VERSION 5.8 ;
BUSBITCHARS "[]" ;
DIVIDERCHAR "/" ;
UNITS
    DATABASE MICRONS 1000 ;
END UNITS

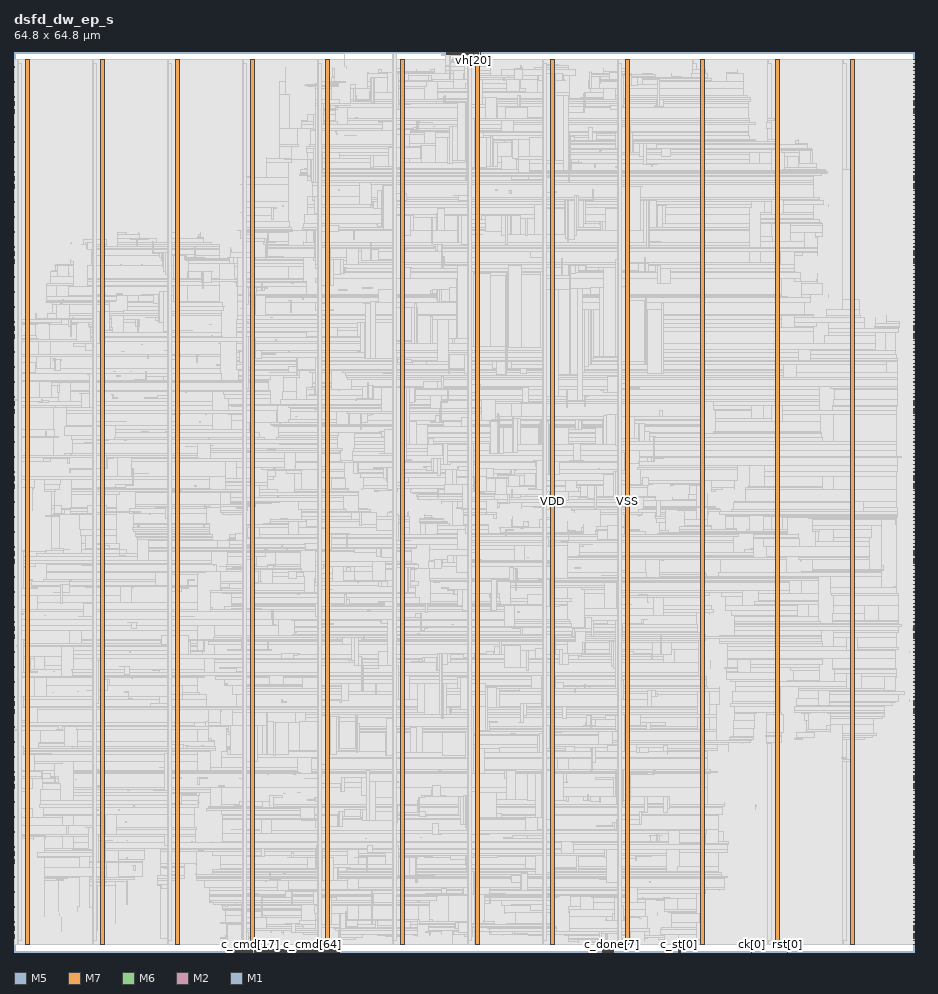
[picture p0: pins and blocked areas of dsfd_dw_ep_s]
MACRO dsfd_dw_ep_s
  FOREIGN dsfd_dw_ep_s 0 0 ;
  CLASS BLOCK ;
  SIZE 64.8 BY 64.8 ;
  PIN c_cmd[0]
    DIRECTION INPUT ;
    USE SIGNAL ;
    PORT
      LAYER M5 ;
        RECT  15.36 0 15.384 0.192 ;
    END
  END c_cmd[0]
  PIN c_cmd[10]
    DIRECTION INPUT ;
    USE SIGNAL ;
    PORT
      LAYER M5 ;
        RECT  16.32 0 16.344 0.192 ;
    END
  END c_cmd[10]
  PIN c_cmd[11]
    DIRECTION INPUT ;
    USE SIGNAL ;
    PORT
      LAYER M5 ;
        RECT  16.416 0 16.44 0.192 ;
    END
  END c_cmd[11]
  PIN c_cmd[12]
    DIRECTION INPUT ;
    USE SIGNAL ;
    PORT
      LAYER M5 ;
        RECT  16.512 0 16.536 0.192 ;
    END
  END c_cmd[12]
  PIN c_cmd[13]
    DIRECTION INPUT ;
    USE SIGNAL ;
    PORT
      LAYER M5 ;
        RECT  16.608 0 16.632 0.192 ;
    END
  END c_cmd[13]
  PIN c_cmd[14]
    DIRECTION INPUT ;
    USE SIGNAL ;
    PORT
      LAYER M5 ;
        RECT  16.704 0 16.728 0.192 ;
    END
  END c_cmd[14]
  PIN c_cmd[15]
    DIRECTION INPUT ;
    USE SIGNAL ;
    PORT
      LAYER M5 ;
        RECT  16.8 0 16.824 0.192 ;
    END
  END c_cmd[15]
  PIN c_cmd[16]
    DIRECTION INPUT ;
    USE SIGNAL ;
    PORT
      LAYER M5 ;
        RECT  16.896 0 16.92 0.192 ;
    END
  END c_cmd[16]
  PIN c_cmd[17]
    DIRECTION INPUT ;
    USE SIGNAL ;
    PORT
      LAYER M5 ;
        RECT  16.992 0 17.016 0.192 ;
    END
  END c_cmd[17]
  PIN c_cmd[18]
    DIRECTION INPUT ;
    USE SIGNAL ;
    PORT
      LAYER M5 ;
        RECT  17.088 0 17.112 0.192 ;
    END
  END c_cmd[18]
  PIN c_cmd[19]
    DIRECTION INPUT ;
    USE SIGNAL ;
    PORT
      LAYER M5 ;
        RECT  17.184 0 17.208 0.192 ;
    END
  END c_cmd[19]
  PIN c_cmd[1]
    DIRECTION INPUT ;
    USE SIGNAL ;
    PORT
      LAYER M5 ;
        RECT  15.456 0 15.48 0.192 ;
    END
  END c_cmd[1]
  PIN c_cmd[20]
    DIRECTION INPUT ;
    USE SIGNAL ;
    PORT
      LAYER M5 ;
        RECT  17.28 0 17.304 0.192 ;
    END
  END c_cmd[20]
  PIN c_cmd[21]
    DIRECTION INPUT ;
    USE SIGNAL ;
    PORT
      LAYER M5 ;
        RECT  17.376 0 17.4 0.192 ;
    END
  END c_cmd[21]
  PIN c_cmd[22]
    DIRECTION INPUT ;
    USE SIGNAL ;
    PORT
      LAYER M5 ;
        RECT  17.472 0 17.496 0.192 ;
    END
  END c_cmd[22]
  PIN c_cmd[23]
    DIRECTION INPUT ;
    USE SIGNAL ;
    PORT
      LAYER M5 ;
        RECT  17.568 0 17.592 0.192 ;
    END
  END c_cmd[23]
  PIN c_cmd[24]
    DIRECTION INPUT ;
    USE SIGNAL ;
    PORT
      LAYER M5 ;
        RECT  17.664 0 17.688 0.192 ;
    END
  END c_cmd[24]
  PIN c_cmd[25]
    DIRECTION INPUT ;
    USE SIGNAL ;
    PORT
      LAYER M5 ;
        RECT  17.76 0 17.784 0.192 ;
    END
  END c_cmd[25]
  PIN c_cmd[26]
    DIRECTION INPUT ;
    USE SIGNAL ;
    PORT
      LAYER M5 ;
        RECT  17.856 0 17.88 0.192 ;
    END
  END c_cmd[26]
  PIN c_cmd[27]
    DIRECTION INPUT ;
    USE SIGNAL ;
    PORT
      LAYER M5 ;
        RECT  17.952 0 17.976 0.192 ;
    END
  END c_cmd[27]
  PIN c_cmd[28]
    DIRECTION INPUT ;
    USE SIGNAL ;
    PORT
      LAYER M5 ;
        RECT  18.048 0 18.072 0.192 ;
    END
  END c_cmd[28]
  PIN c_cmd[29]
    DIRECTION INPUT ;
    USE SIGNAL ;
    PORT
      LAYER M5 ;
        RECT  18.144 0 18.168 0.192 ;
    END
  END c_cmd[29]
  PIN c_cmd[2]
    DIRECTION INPUT ;
    USE SIGNAL ;
    PORT
      LAYER M5 ;
        RECT  15.552 0 15.576 0.192 ;
    END
  END c_cmd[2]
  PIN c_cmd[30]
    DIRECTION INPUT ;
    USE SIGNAL ;
    PORT
      LAYER M5 ;
        RECT  18.24 0 18.264 0.192 ;
    END
  END c_cmd[30]
  PIN c_cmd[31]
    DIRECTION INPUT ;
    USE SIGNAL ;
    PORT
      LAYER M5 ;
        RECT  18.336 0 18.36 0.192 ;
    END
  END c_cmd[31]
  PIN c_cmd[32]
    DIRECTION INPUT ;
    USE SIGNAL ;
    PORT
      LAYER M5 ;
        RECT  18.432 0 18.456 0.192 ;
    END
  END c_cmd[32]
  PIN c_cmd[33]
    DIRECTION INPUT ;
    USE SIGNAL ;
    PORT
      LAYER M5 ;
        RECT  18.528 0 18.552 0.192 ;
    END
  END c_cmd[33]
  PIN c_cmd[34]
    DIRECTION INPUT ;
    USE SIGNAL ;
    PORT
      LAYER M5 ;
        RECT  18.624 0 18.648 0.192 ;
    END
  END c_cmd[34]
  PIN c_cmd[35]
    DIRECTION INPUT ;
    USE SIGNAL ;
    PORT
      LAYER M5 ;
        RECT  18.72 0 18.744 0.192 ;
    END
  END c_cmd[35]
  PIN c_cmd[36]
    DIRECTION INPUT ;
    USE SIGNAL ;
    PORT
      LAYER M5 ;
        RECT  18.816 0 18.84 0.192 ;
    END
  END c_cmd[36]
  PIN c_cmd[37]
    DIRECTION INPUT ;
    USE SIGNAL ;
    PORT
      LAYER M5 ;
        RECT  18.912 0 18.936 0.192 ;
    END
  END c_cmd[37]
  PIN c_cmd[38]
    DIRECTION INPUT ;
    USE SIGNAL ;
    PORT
      LAYER M5 ;
        RECT  19.008 0 19.032 0.192 ;
    END
  END c_cmd[38]
  PIN c_cmd[39]
    DIRECTION INPUT ;
    USE SIGNAL ;
    PORT
      LAYER M5 ;
        RECT  19.104 0 19.128 0.192 ;
    END
  END c_cmd[39]
  PIN c_cmd[3]
    DIRECTION INPUT ;
    USE SIGNAL ;
    PORT
      LAYER M5 ;
        RECT  15.648 0 15.672 0.192 ;
    END
  END c_cmd[3]
  PIN c_cmd[40]
    DIRECTION INPUT ;
    USE SIGNAL ;
    PORT
      LAYER M5 ;
        RECT  19.2 0 19.224 0.192 ;
    END
  END c_cmd[40]
  PIN c_cmd[41]
    DIRECTION INPUT ;
    USE SIGNAL ;
    PORT
      LAYER M5 ;
        RECT  19.296 0 19.32 0.192 ;
    END
  END c_cmd[41]
  PIN c_cmd[42]
    DIRECTION INPUT ;
    USE SIGNAL ;
    PORT
      LAYER M5 ;
        RECT  19.392 0 19.416 0.192 ;
    END
  END c_cmd[42]
  PIN c_cmd[43]
    DIRECTION INPUT ;
    USE SIGNAL ;
    PORT
      LAYER M5 ;
        RECT  19.488 0 19.512 0.192 ;
    END
  END c_cmd[43]
  PIN c_cmd[44]
    DIRECTION INPUT ;
    USE SIGNAL ;
    PORT
      LAYER M5 ;
        RECT  19.584 0 19.608 0.192 ;
    END
  END c_cmd[44]
  PIN c_cmd[45]
    DIRECTION INPUT ;
    USE SIGNAL ;
    PORT
      LAYER M5 ;
        RECT  19.68 0 19.704 0.192 ;
    END
  END c_cmd[45]
  PIN c_cmd[46]
    DIRECTION INPUT ;
    USE SIGNAL ;
    PORT
      LAYER M5 ;
        RECT  19.776 0 19.8 0.192 ;
    END
  END c_cmd[46]
  PIN c_cmd[47]
    DIRECTION INPUT ;
    USE SIGNAL ;
    PORT
      LAYER M5 ;
        RECT  19.872 0 19.896 0.192 ;
    END
  END c_cmd[47]
  PIN c_cmd[48]
    DIRECTION INPUT ;
    USE SIGNAL ;
    PORT
      LAYER M5 ;
        RECT  19.968 0 19.992 0.192 ;
    END
  END c_cmd[48]
  PIN c_cmd[49]
    DIRECTION INPUT ;
    USE SIGNAL ;
    PORT
      LAYER M5 ;
        RECT  20.064 0 20.088 0.192 ;
    END
  END c_cmd[49]
  PIN c_cmd[4]
    DIRECTION INPUT ;
    USE SIGNAL ;
    PORT
      LAYER M5 ;
        RECT  15.744 0 15.768 0.192 ;
    END
  END c_cmd[4]
  PIN c_cmd[50]
    DIRECTION INPUT ;
    USE SIGNAL ;
    PORT
      LAYER M5 ;
        RECT  20.16 0 20.184 0.192 ;
    END
  END c_cmd[50]
  PIN c_cmd[51]
    DIRECTION INPUT ;
    USE SIGNAL ;
    PORT
      LAYER M5 ;
        RECT  20.256 0 20.28 0.192 ;
    END
  END c_cmd[51]
  PIN c_cmd[52]
    DIRECTION INPUT ;
    USE SIGNAL ;
    PORT
      LAYER M5 ;
        RECT  20.352 0 20.376 0.192 ;
    END
  END c_cmd[52]
  PIN c_cmd[53]
    DIRECTION INPUT ;
    USE SIGNAL ;
    PORT
      LAYER M5 ;
        RECT  20.448 0 20.472 0.192 ;
    END
  END c_cmd[53]
  PIN c_cmd[54]
    DIRECTION INPUT ;
    USE SIGNAL ;
    PORT
      LAYER M5 ;
        RECT  20.544 0 20.568 0.192 ;
    END
  END c_cmd[54]
  PIN c_cmd[55]
    DIRECTION INPUT ;
    USE SIGNAL ;
    PORT
      LAYER M5 ;
        RECT  20.64 0 20.664 0.192 ;
    END
  END c_cmd[55]
  PIN c_cmd[56]
    DIRECTION INPUT ;
    USE SIGNAL ;
    PORT
      LAYER M5 ;
        RECT  20.736 0 20.76 0.192 ;
    END
  END c_cmd[56]
  PIN c_cmd[57]
    DIRECTION INPUT ;
    USE SIGNAL ;
    PORT
      LAYER M5 ;
        RECT  20.832 0 20.856 0.192 ;
    END
  END c_cmd[57]
  PIN c_cmd[58]
    DIRECTION INPUT ;
    USE SIGNAL ;
    PORT
      LAYER M5 ;
        RECT  20.928 0 20.952 0.192 ;
    END
  END c_cmd[58]
  PIN c_cmd[59]
    DIRECTION INPUT ;
    USE SIGNAL ;
    PORT
      LAYER M5 ;
        RECT  21.024 0 21.048 0.192 ;
    END
  END c_cmd[59]
  PIN c_cmd[5]
    DIRECTION INPUT ;
    USE SIGNAL ;
    PORT
      LAYER M5 ;
        RECT  15.84 0 15.864 0.192 ;
    END
  END c_cmd[5]
  PIN c_cmd[60]
    DIRECTION INPUT ;
    USE SIGNAL ;
    PORT
      LAYER M5 ;
        RECT  21.12 0 21.144 0.192 ;
    END
  END c_cmd[60]
  PIN c_cmd[61]
    DIRECTION INPUT ;
    USE SIGNAL ;
    PORT
      LAYER M5 ;
        RECT  21.216 0 21.24 0.192 ;
    END
  END c_cmd[61]
  PIN c_cmd[62]
    DIRECTION INPUT ;
    USE SIGNAL ;
    PORT
      LAYER M5 ;
        RECT  21.312 0 21.336 0.192 ;
    END
  END c_cmd[62]
  PIN c_cmd[63]
    DIRECTION INPUT ;
    USE SIGNAL ;
    PORT
      LAYER M5 ;
        RECT  21.408 0 21.432 0.192 ;
    END
  END c_cmd[63]
  PIN c_cmd[64]
    DIRECTION INPUT ;
    USE SIGNAL ;
    PORT
      LAYER M5 ;
        RECT  21.504 0 21.528 0.192 ;
    END
  END c_cmd[64]
  PIN c_cmd[65]
    DIRECTION INPUT ;
    USE SIGNAL ;
    PORT
      LAYER M5 ;
        RECT  21.6 0 21.624 0.192 ;
    END
  END c_cmd[65]
  PIN c_cmd[66]
    DIRECTION INPUT ;
    USE SIGNAL ;
    PORT
      LAYER M5 ;
        RECT  21.696 0 21.72 0.192 ;
    END
  END c_cmd[66]
  PIN c_cmd[67]
    DIRECTION INPUT ;
    USE SIGNAL ;
    PORT
      LAYER M5 ;
        RECT  21.792 0 21.816 0.192 ;
    END
  END c_cmd[67]
  PIN c_cmd[68]
    DIRECTION INPUT ;
    USE SIGNAL ;
    PORT
      LAYER M5 ;
        RECT  21.888 0 21.912 0.192 ;
    END
  END c_cmd[68]
  PIN c_cmd[69]
    DIRECTION INPUT ;
    USE SIGNAL ;
    PORT
      LAYER M5 ;
        RECT  21.984 0 22.008 0.192 ;
    END
  END c_cmd[69]
  PIN c_cmd[6]
    DIRECTION INPUT ;
    USE SIGNAL ;
    PORT
      LAYER M5 ;
        RECT  15.936 0 15.96 0.192 ;
    END
  END c_cmd[6]
  PIN c_cmd[70]
    DIRECTION INPUT ;
    USE SIGNAL ;
    PORT
      LAYER M5 ;
        RECT  22.08 0 22.104 0.192 ;
    END
  END c_cmd[70]
  PIN c_cmd[71]
    DIRECTION INPUT ;
    USE SIGNAL ;
    PORT
      LAYER M5 ;
        RECT  22.176 0 22.2 0.192 ;
    END
  END c_cmd[71]
  PIN c_cmd[72]
    DIRECTION INPUT ;
    USE SIGNAL ;
    PORT
      LAYER M5 ;
        RECT  22.272 0 22.296 0.192 ;
    END
  END c_cmd[72]
  PIN c_cmd[73]
    DIRECTION INPUT ;
    USE SIGNAL ;
    PORT
      LAYER M5 ;
        RECT  22.368 0 22.392 0.192 ;
    END
  END c_cmd[73]
  PIN c_cmd[74]
    DIRECTION INPUT ;
    USE SIGNAL ;
    PORT
      LAYER M5 ;
        RECT  22.464 0 22.488 0.192 ;
    END
  END c_cmd[74]
  PIN c_cmd[75]
    DIRECTION INPUT ;
    USE SIGNAL ;
    PORT
      LAYER M5 ;
        RECT  22.56 0 22.584 0.192 ;
    END
  END c_cmd[75]
  PIN c_cmd[76]
    DIRECTION INPUT ;
    USE SIGNAL ;
    PORT
      LAYER M5 ;
        RECT  22.656 0 22.68 0.192 ;
    END
  END c_cmd[76]
  PIN c_cmd[77]
    DIRECTION INPUT ;
    USE SIGNAL ;
    PORT
      LAYER M5 ;
        RECT  22.752 0 22.776 0.192 ;
    END
  END c_cmd[77]
  PIN c_cmd[78]
    DIRECTION INPUT ;
    USE SIGNAL ;
    PORT
      LAYER M5 ;
        RECT  22.848 0 22.872 0.192 ;
    END
  END c_cmd[78]
  PIN c_cmd[79]
    DIRECTION INPUT ;
    USE SIGNAL ;
    PORT
      LAYER M5 ;
        RECT  22.944 0 22.968 0.192 ;
    END
  END c_cmd[79]
  PIN c_cmd[7]
    DIRECTION INPUT ;
    USE SIGNAL ;
    PORT
      LAYER M5 ;
        RECT  16.032 0 16.056 0.192 ;
    END
  END c_cmd[7]
  PIN c_cmd[80]
    DIRECTION INPUT ;
    USE SIGNAL ;
    PORT
      LAYER M5 ;
        RECT  23.04 0 23.064 0.192 ;
    END
  END c_cmd[80]
  PIN c_cmd[81]
    DIRECTION INPUT ;
    USE SIGNAL ;
    PORT
      LAYER M5 ;
        RECT  23.136 0 23.16 0.192 ;
    END
  END c_cmd[81]
  PIN c_cmd[82]
    DIRECTION INPUT ;
    USE SIGNAL ;
    PORT
      LAYER M5 ;
        RECT  23.232 0 23.256 0.192 ;
    END
  END c_cmd[82]
  PIN c_cmd[83]
    DIRECTION INPUT ;
    USE SIGNAL ;
    PORT
      LAYER M5 ;
        RECT  23.328 0 23.352 0.192 ;
    END
  END c_cmd[83]
  PIN c_cmd[84]
    DIRECTION INPUT ;
    USE SIGNAL ;
    PORT
      LAYER M5 ;
        RECT  23.424 0 23.448 0.192 ;
    END
  END c_cmd[84]
  PIN c_cmd[8]
    DIRECTION INPUT ;
    USE SIGNAL ;
    PORT
      LAYER M5 ;
        RECT  16.128 0 16.152 0.192 ;
    END
  END c_cmd[8]
  PIN c_cmd[9]
    DIRECTION INPUT ;
    USE SIGNAL ;
    PORT
      LAYER M5 ;
        RECT  16.224 0 16.248 0.192 ;
    END
  END c_cmd[9]
  PIN c_done[0]
    DIRECTION OUTPUT ;
    USE SIGNAL ;
    PORT
      LAYER M5 ;
        RECT  42.336 0 42.36 0.192 ;
    END
  END c_done[0]
  PIN c_done[1]
    DIRECTION OUTPUT ;
    USE SIGNAL ;
    PORT
      LAYER M5 ;
        RECT  42.432 0 42.456 0.192 ;
    END
  END c_done[1]
  PIN c_done[2]
    DIRECTION OUTPUT ;
    USE SIGNAL ;
    PORT
      LAYER M5 ;
        RECT  42.528 0 42.552 0.192 ;
    END
  END c_done[2]
  PIN c_done[3]
    DIRECTION OUTPUT ;
    USE SIGNAL ;
    PORT
      LAYER M5 ;
        RECT  42.624 0 42.648 0.192 ;
    END
  END c_done[3]
  PIN c_done[4]
    DIRECTION OUTPUT ;
    USE SIGNAL ;
    PORT
      LAYER M5 ;
        RECT  42.72 0 42.744 0.192 ;
    END
  END c_done[4]
  PIN c_done[5]
    DIRECTION OUTPUT ;
    USE SIGNAL ;
    PORT
      LAYER M5 ;
        RECT  42.816 0 42.84 0.192 ;
    END
  END c_done[5]
  PIN c_done[6]
    DIRECTION OUTPUT ;
    USE SIGNAL ;
    PORT
      LAYER M5 ;
        RECT  42.912 0 42.936 0.192 ;
    END
  END c_done[6]
  PIN c_done[7]
    DIRECTION OUTPUT ;
    USE SIGNAL ;
    PORT
      LAYER M5 ;
        RECT  43.008 0 43.032 0.192 ;
    END
  END c_done[7]
  PIN c_done[8]
    DIRECTION OUTPUT ;
    USE SIGNAL ;
    PORT
      LAYER M5 ;
        RECT  43.104 0 43.128 0.192 ;
    END
  END c_done[8]
  PIN c_st[0]
    DIRECTION OUTPUT ;
    USE SIGNAL ;
    PORT
      LAYER M5 ;
        RECT  47.856 0 47.88 0.192 ;
    END
  END c_st[0]
  PIN c_st[1]
    DIRECTION OUTPUT ;
    USE SIGNAL ;
    PORT
      LAYER M5 ;
        RECT  47.952 0 47.976 0.192 ;
    END
  END c_st[1]
  PIN ck[0]
    DIRECTION INPUT ;
    USE SIGNAL ;
    PORT
      LAYER M5 ;
        RECT  53.088 0 53.112 0.192 ;
    END
  END ck[0]
  PIN rst[0]
    DIRECTION INPUT ;
    USE SIGNAL ;
    PORT
      LAYER M5 ;
        RECT  55.68 0 55.704 0.192 ;
    END
  END rst[0]
  PIN vh[0]
    DIRECTION INPUT ;
    USE SIGNAL ;
    PORT
      LAYER M5 ;
        RECT  31.152 64.608 31.176 64.8 ;
    END
  END vh[0]
  PIN vh[10]
    DIRECTION INPUT ;
    USE SIGNAL ;
    PORT
      LAYER M5 ;
        RECT  32.112 64.608 32.136 64.8 ;
    END
  END vh[10]
  PIN vh[11]
    DIRECTION INPUT ;
    USE SIGNAL ;
    PORT
      LAYER M5 ;
        RECT  32.208 64.608 32.232 64.8 ;
    END
  END vh[11]
  PIN vh[12]
    DIRECTION INPUT ;
    USE SIGNAL ;
    PORT
      LAYER M5 ;
        RECT  32.304 64.608 32.328 64.8 ;
    END
  END vh[12]
  PIN vh[13]
    DIRECTION INPUT ;
    USE SIGNAL ;
    PORT
      LAYER M5 ;
        RECT  32.4 64.608 32.424 64.8 ;
    END
  END vh[13]
  PIN vh[14]
    DIRECTION INPUT ;
    USE SIGNAL ;
    PORT
      LAYER M5 ;
        RECT  32.496 64.608 32.52 64.8 ;
    END
  END vh[14]
  PIN vh[15]
    DIRECTION INPUT ;
    USE SIGNAL ;
    PORT
      LAYER M5 ;
        RECT  32.592 64.608 32.616 64.8 ;
    END
  END vh[15]
  PIN vh[16]
    DIRECTION INPUT ;
    USE SIGNAL ;
    PORT
      LAYER M5 ;
        RECT  32.688 64.608 32.712 64.8 ;
    END
  END vh[16]
  PIN vh[17]
    DIRECTION INPUT ;
    USE SIGNAL ;
    PORT
      LAYER M5 ;
        RECT  32.784 64.608 32.808 64.8 ;
    END
  END vh[17]
  PIN vh[18]
    DIRECTION INPUT ;
    USE SIGNAL ;
    PORT
      LAYER M5 ;
        RECT  32.88 64.608 32.904 64.8 ;
    END
  END vh[18]
  PIN vh[19]
    DIRECTION INPUT ;
    USE SIGNAL ;
    PORT
      LAYER M5 ;
        RECT  32.976 64.608 33 64.8 ;
    END
  END vh[19]
  PIN vh[1]
    DIRECTION INPUT ;
    USE SIGNAL ;
    PORT
      LAYER M5 ;
        RECT  31.248 64.608 31.272 64.8 ;
    END
  END vh[1]
  PIN vh[20]
    DIRECTION INPUT ;
    USE SIGNAL ;
    PORT
      LAYER M5 ;
        RECT  33.072 64.608 33.096 64.8 ;
    END
  END vh[20]
  PIN vh[21]
    DIRECTION INPUT ;
    USE SIGNAL ;
    PORT
      LAYER M5 ;
        RECT  33.168 64.608 33.192 64.8 ;
    END
  END vh[21]
  PIN vh[22]
    DIRECTION INPUT ;
    USE SIGNAL ;
    PORT
      LAYER M5 ;
        RECT  33.264 64.608 33.288 64.8 ;
    END
  END vh[22]
  PIN vh[23]
    DIRECTION INPUT ;
    USE SIGNAL ;
    PORT
      LAYER M5 ;
        RECT  33.36 64.608 33.384 64.8 ;
    END
  END vh[23]
  PIN vh[24]
    DIRECTION INPUT ;
    USE SIGNAL ;
    PORT
      LAYER M5 ;
        RECT  33.456 64.608 33.48 64.8 ;
    END
  END vh[24]
  PIN vh[25]
    DIRECTION INPUT ;
    USE SIGNAL ;
    PORT
      LAYER M5 ;
        RECT  33.552 64.608 33.576 64.8 ;
    END
  END vh[25]
  PIN vh[2]
    DIRECTION INPUT ;
    USE SIGNAL ;
    PORT
      LAYER M5 ;
        RECT  31.344 64.608 31.368 64.8 ;
    END
  END vh[2]
  PIN vh[3]
    DIRECTION INPUT ;
    USE SIGNAL ;
    PORT
      LAYER M5 ;
        RECT  31.44 64.608 31.464 64.8 ;
    END
  END vh[3]
  PIN vh[4]
    DIRECTION INPUT ;
    USE SIGNAL ;
    PORT
      LAYER M5 ;
        RECT  31.536 64.608 31.56 64.8 ;
    END
  END vh[4]
  PIN vh[5]
    DIRECTION INPUT ;
    USE SIGNAL ;
    PORT
      LAYER M5 ;
        RECT  31.632 64.608 31.656 64.8 ;
    END
  END vh[5]
  PIN vh[6]
    DIRECTION INPUT ;
    USE SIGNAL ;
    PORT
      LAYER M5 ;
        RECT  31.728 64.608 31.752 64.8 ;
    END
  END vh[6]
  PIN vh[7]
    DIRECTION INPUT ;
    USE SIGNAL ;
    PORT
      LAYER M5 ;
        RECT  31.824 64.608 31.848 64.8 ;
    END
  END vh[7]
  PIN vh[8]
    DIRECTION INPUT ;
    USE SIGNAL ;
    PORT
      LAYER M5 ;
        RECT  31.92 64.608 31.944 64.8 ;
    END
  END vh[8]
  PIN vh[9]
    DIRECTION INPUT ;
    USE SIGNAL ;
    PORT
      LAYER M5 ;
        RECT  32.016 64.608 32.04 64.8 ;
    END
  END vh[9]
  PIN VDD
    DIRECTION INOUT ;
    USE POWER ;
    PORT
      LAYER M7 ;
        RECT  60.256 0.531 60.544 64.269 ;
        RECT  49.456 0.531 49.744 64.269 ;
        RECT  38.656 0.531 38.944 64.269 ;
        RECT  27.856 0.531 28.144 64.269 ;
        RECT  17.056 0.531 17.344 64.269 ;
        RECT  6.256 0.531 6.544 64.269 ;
      LAYER M6 ;
        RECT  64.768 60.972 64.8 61.26 ;
        RECT  0 60.972 0.032 61.26 ;
        RECT  64.768 55.572 64.8 55.86 ;
        RECT  0 55.572 0.032 55.86 ;
        RECT  64.768 50.172 64.8 50.46 ;
        RECT  0 50.172 0.032 50.46 ;
        RECT  64.768 44.772 64.8 45.06 ;
        RECT  0 44.772 0.032 45.06 ;
        RECT  64.768 39.372 64.8 39.66 ;
        RECT  0 39.372 0.032 39.66 ;
        RECT  64.768 33.972 64.8 34.26 ;
        RECT  0 33.972 0.032 34.26 ;
        RECT  64.768 28.572 64.8 28.86 ;
        RECT  0 28.572 0.032 28.86 ;
        RECT  64.768 23.172 64.8 23.46 ;
        RECT  0 23.172 0.032 23.46 ;
        RECT  64.768 17.772 64.8 18.06 ;
        RECT  0 17.772 0.032 18.06 ;
        RECT  64.768 12.372 64.8 12.66 ;
        RECT  0 12.372 0.032 12.66 ;
        RECT  64.768 6.972 64.8 7.26 ;
        RECT  0 6.972 0.032 7.26 ;
        RECT  64.768 1.572 64.8 1.86 ;
        RECT  0 1.572 0.032 1.86 ;
      LAYER M2 ;
        RECT  64.782 63.981 64.8 63.999 ;
        RECT  0 63.981 0.018 63.999 ;
        RECT  64.782 63.441 64.8 63.459 ;
        RECT  0 63.441 0.018 63.459 ;
        RECT  64.782 62.901 64.8 62.919 ;
        RECT  0 62.901 0.018 62.919 ;
        RECT  64.782 62.361 64.8 62.379 ;
        RECT  0 62.361 0.018 62.379 ;
        RECT  64.782 61.821 64.8 61.839 ;
        RECT  0 61.821 0.018 61.839 ;
        RECT  64.782 61.281 64.8 61.299 ;
        RECT  0 61.281 0.018 61.299 ;
        RECT  64.782 60.741 64.8 60.759 ;
        RECT  0 60.741 0.018 60.759 ;
        RECT  64.782 60.201 64.8 60.219 ;
        RECT  0 60.201 0.018 60.219 ;
        RECT  64.782 59.661 64.8 59.679 ;
        RECT  0 59.661 0.018 59.679 ;
        RECT  64.782 59.121 64.8 59.139 ;
        RECT  0 59.121 0.018 59.139 ;
        RECT  64.782 58.581 64.8 58.599 ;
        RECT  0 58.581 0.018 58.599 ;
        RECT  64.782 58.041 64.8 58.059 ;
        RECT  0 58.041 0.018 58.059 ;
        RECT  64.782 57.501 64.8 57.519 ;
        RECT  0 57.501 0.018 57.519 ;
        RECT  64.782 56.961 64.8 56.979 ;
        RECT  0 56.961 0.018 56.979 ;
        RECT  64.782 56.421 64.8 56.439 ;
        RECT  0 56.421 0.018 56.439 ;
        RECT  64.782 55.881 64.8 55.899 ;
        RECT  0 55.881 0.018 55.899 ;
        RECT  64.782 55.341 64.8 55.359 ;
        RECT  0 55.341 0.018 55.359 ;
        RECT  64.782 54.801 64.8 54.819 ;
        RECT  0 54.801 0.018 54.819 ;
        RECT  64.782 54.261 64.8 54.279 ;
        RECT  0 54.261 0.018 54.279 ;
        RECT  64.782 53.721 64.8 53.739 ;
        RECT  0 53.721 0.018 53.739 ;
        RECT  64.782 53.181 64.8 53.199 ;
        RECT  0 53.181 0.018 53.199 ;
        RECT  64.782 52.641 64.8 52.659 ;
        RECT  0 52.641 0.018 52.659 ;
        RECT  64.782 52.101 64.8 52.119 ;
        RECT  0 52.101 0.018 52.119 ;
        RECT  64.782 51.561 64.8 51.579 ;
        RECT  0 51.561 0.018 51.579 ;
        RECT  64.782 51.021 64.8 51.039 ;
        RECT  0 51.021 0.018 51.039 ;
        RECT  64.782 50.481 64.8 50.499 ;
        RECT  0 50.481 0.018 50.499 ;
        RECT  64.782 49.941 64.8 49.959 ;
        RECT  0 49.941 0.018 49.959 ;
        RECT  64.782 49.401 64.8 49.419 ;
        RECT  0 49.401 0.018 49.419 ;
        RECT  64.782 48.861 64.8 48.879 ;
        RECT  0 48.861 0.018 48.879 ;
        RECT  64.782 48.321 64.8 48.339 ;
        RECT  0 48.321 0.018 48.339 ;
        RECT  64.782 47.781 64.8 47.799 ;
        RECT  0 47.781 0.018 47.799 ;
        RECT  64.782 47.241 64.8 47.259 ;
        RECT  0 47.241 0.018 47.259 ;
        RECT  64.782 46.701 64.8 46.719 ;
        RECT  0 46.701 0.018 46.719 ;
        RECT  64.782 46.161 64.8 46.179 ;
        RECT  0 46.161 0.018 46.179 ;
        RECT  64.782 45.621 64.8 45.639 ;
        RECT  0 45.621 0.018 45.639 ;
        RECT  64.782 45.081 64.8 45.099 ;
        RECT  0 45.081 0.018 45.099 ;
        RECT  64.782 44.541 64.8 44.559 ;
        RECT  0 44.541 0.018 44.559 ;
        RECT  64.782 44.001 64.8 44.019 ;
        RECT  0 44.001 0.018 44.019 ;
        RECT  64.782 43.461 64.8 43.479 ;
        RECT  0 43.461 0.018 43.479 ;
        RECT  64.782 42.921 64.8 42.939 ;
        RECT  0 42.921 0.018 42.939 ;
        RECT  64.782 42.381 64.8 42.399 ;
        RECT  0 42.381 0.018 42.399 ;
        RECT  64.782 41.841 64.8 41.859 ;
        RECT  0 41.841 0.018 41.859 ;
        RECT  64.782 41.301 64.8 41.319 ;
        RECT  0 41.301 0.018 41.319 ;
        RECT  64.782 40.761 64.8 40.779 ;
        RECT  0 40.761 0.018 40.779 ;
        RECT  64.782 40.221 64.8 40.239 ;
        RECT  0 40.221 0.018 40.239 ;
        RECT  64.782 39.681 64.8 39.699 ;
        RECT  0 39.681 0.018 39.699 ;
        RECT  64.782 39.141 64.8 39.159 ;
        RECT  0 39.141 0.018 39.159 ;
        RECT  64.782 38.601 64.8 38.619 ;
        RECT  0 38.601 0.018 38.619 ;
        RECT  64.782 38.061 64.8 38.079 ;
        RECT  0 38.061 0.018 38.079 ;
        RECT  64.782 37.521 64.8 37.539 ;
        RECT  0 37.521 0.018 37.539 ;
        RECT  64.782 36.981 64.8 36.999 ;
        RECT  0 36.981 0.018 36.999 ;
        RECT  64.782 36.441 64.8 36.459 ;
        RECT  0 36.441 0.018 36.459 ;
        RECT  64.782 35.901 64.8 35.919 ;
        RECT  0 35.901 0.018 35.919 ;
        RECT  64.782 35.361 64.8 35.379 ;
        RECT  0 35.361 0.018 35.379 ;
        RECT  64.782 34.821 64.8 34.839 ;
        RECT  0 34.821 0.018 34.839 ;
        RECT  64.782 34.281 64.8 34.299 ;
        RECT  0 34.281 0.018 34.299 ;
        RECT  64.782 33.741 64.8 33.759 ;
        RECT  0 33.741 0.018 33.759 ;
        RECT  64.782 33.201 64.8 33.219 ;
        RECT  0 33.201 0.018 33.219 ;
        RECT  64.782 32.661 64.8 32.679 ;
        RECT  0 32.661 0.018 32.679 ;
        RECT  64.782 32.121 64.8 32.139 ;
        RECT  0 32.121 0.018 32.139 ;
        RECT  64.782 31.581 64.8 31.599 ;
        RECT  0 31.581 0.018 31.599 ;
        RECT  64.782 31.041 64.8 31.059 ;
        RECT  0 31.041 0.018 31.059 ;
        RECT  64.782 30.501 64.8 30.519 ;
        RECT  0 30.501 0.018 30.519 ;
        RECT  64.782 29.961 64.8 29.979 ;
        RECT  0 29.961 0.018 29.979 ;
        RECT  64.782 29.421 64.8 29.439 ;
        RECT  0 29.421 0.018 29.439 ;
        RECT  64.782 28.881 64.8 28.899 ;
        RECT  0 28.881 0.018 28.899 ;
        RECT  64.782 28.341 64.8 28.359 ;
        RECT  0 28.341 0.018 28.359 ;
        RECT  64.782 27.801 64.8 27.819 ;
        RECT  0 27.801 0.018 27.819 ;
        RECT  64.782 27.261 64.8 27.279 ;
        RECT  0 27.261 0.018 27.279 ;
        RECT  64.782 26.721 64.8 26.739 ;
        RECT  0 26.721 0.018 26.739 ;
        RECT  64.782 26.181 64.8 26.199 ;
        RECT  0 26.181 0.018 26.199 ;
        RECT  64.782 25.641 64.8 25.659 ;
        RECT  0 25.641 0.018 25.659 ;
        RECT  64.782 25.101 64.8 25.119 ;
        RECT  0 25.101 0.018 25.119 ;
        RECT  64.782 24.561 64.8 24.579 ;
        RECT  0 24.561 0.018 24.579 ;
        RECT  64.782 24.021 64.8 24.039 ;
        RECT  0 24.021 0.018 24.039 ;
        RECT  64.782 23.481 64.8 23.499 ;
        RECT  0 23.481 0.018 23.499 ;
        RECT  64.782 22.941 64.8 22.959 ;
        RECT  0 22.941 0.018 22.959 ;
        RECT  64.782 22.401 64.8 22.419 ;
        RECT  0 22.401 0.018 22.419 ;
        RECT  64.782 21.861 64.8 21.879 ;
        RECT  0 21.861 0.018 21.879 ;
        RECT  64.782 21.321 64.8 21.339 ;
        RECT  0 21.321 0.018 21.339 ;
        RECT  64.782 20.781 64.8 20.799 ;
        RECT  0 20.781 0.018 20.799 ;
        RECT  64.782 20.241 64.8 20.259 ;
        RECT  0 20.241 0.018 20.259 ;
        RECT  64.782 19.701 64.8 19.719 ;
        RECT  0 19.701 0.018 19.719 ;
        RECT  64.782 19.161 64.8 19.179 ;
        RECT  0 19.161 0.018 19.179 ;
        RECT  64.782 18.621 64.8 18.639 ;
        RECT  0 18.621 0.018 18.639 ;
        RECT  64.782 18.081 64.8 18.099 ;
        RECT  0 18.081 0.018 18.099 ;
        RECT  64.782 17.541 64.8 17.559 ;
        RECT  0 17.541 0.018 17.559 ;
        RECT  64.782 17.001 64.8 17.019 ;
        RECT  0 17.001 0.018 17.019 ;
        RECT  64.782 16.461 64.8 16.479 ;
        RECT  0 16.461 0.018 16.479 ;
        RECT  64.782 15.921 64.8 15.939 ;
        RECT  0 15.921 0.018 15.939 ;
        RECT  64.782 15.381 64.8 15.399 ;
        RECT  0 15.381 0.018 15.399 ;
        RECT  64.782 14.841 64.8 14.859 ;
        RECT  0 14.841 0.018 14.859 ;
        RECT  64.782 14.301 64.8 14.319 ;
        RECT  0 14.301 0.018 14.319 ;
        RECT  64.782 13.761 64.8 13.779 ;
        RECT  0 13.761 0.018 13.779 ;
        RECT  64.782 13.221 64.8 13.239 ;
        RECT  0 13.221 0.018 13.239 ;
        RECT  64.782 12.681 64.8 12.699 ;
        RECT  0 12.681 0.018 12.699 ;
        RECT  64.782 12.141 64.8 12.159 ;
        RECT  0 12.141 0.018 12.159 ;
        RECT  64.782 11.601 64.8 11.619 ;
        RECT  0 11.601 0.018 11.619 ;
        RECT  64.782 11.061 64.8 11.079 ;
        RECT  0 11.061 0.018 11.079 ;
        RECT  64.782 10.521 64.8 10.539 ;
        RECT  0 10.521 0.018 10.539 ;
        RECT  64.782 9.981 64.8 9.999 ;
        RECT  0 9.981 0.018 9.999 ;
        RECT  64.782 9.441 64.8 9.459 ;
        RECT  0 9.441 0.018 9.459 ;
        RECT  64.782 8.901 64.8 8.919 ;
        RECT  0 8.901 0.018 8.919 ;
        RECT  64.782 8.361 64.8 8.379 ;
        RECT  0 8.361 0.018 8.379 ;
        RECT  64.782 7.821 64.8 7.839 ;
        RECT  0 7.821 0.018 7.839 ;
        RECT  64.782 7.281 64.8 7.299 ;
        RECT  0 7.281 0.018 7.299 ;
        RECT  64.782 6.741 64.8 6.759 ;
        RECT  0 6.741 0.018 6.759 ;
        RECT  64.782 6.201 64.8 6.219 ;
        RECT  0 6.201 0.018 6.219 ;
        RECT  64.782 5.661 64.8 5.679 ;
        RECT  0 5.661 0.018 5.679 ;
        RECT  64.782 5.121 64.8 5.139 ;
        RECT  0 5.121 0.018 5.139 ;
        RECT  64.782 4.581 64.8 4.599 ;
        RECT  0 4.581 0.018 4.599 ;
        RECT  64.782 4.041 64.8 4.059 ;
        RECT  0 4.041 0.018 4.059 ;
        RECT  64.782 3.501 64.8 3.519 ;
        RECT  0 3.501 0.018 3.519 ;
        RECT  64.782 2.961 64.8 2.979 ;
        RECT  0 2.961 0.018 2.979 ;
        RECT  64.782 2.421 64.8 2.439 ;
        RECT  0 2.421 0.018 2.439 ;
        RECT  64.782 1.881 64.8 1.899 ;
        RECT  0 1.881 0.018 1.899 ;
        RECT  64.782 1.341 64.8 1.359 ;
        RECT  0 1.341 0.018 1.359 ;
        RECT  64.782 0.801 64.8 0.819 ;
        RECT  0 0.801 0.018 0.819 ;
      LAYER M1 ;
        RECT  64.782 63.981 64.8 63.999 ;
        RECT  0 63.981 0.018 63.999 ;
        RECT  64.782 63.441 64.8 63.459 ;
        RECT  0 63.441 0.018 63.459 ;
        RECT  64.782 62.901 64.8 62.919 ;
        RECT  0 62.901 0.018 62.919 ;
        RECT  64.782 62.361 64.8 62.379 ;
        RECT  0 62.361 0.018 62.379 ;
        RECT  64.782 61.821 64.8 61.839 ;
        RECT  0 61.821 0.018 61.839 ;
        RECT  64.782 61.281 64.8 61.299 ;
        RECT  0 61.281 0.018 61.299 ;
        RECT  64.782 60.741 64.8 60.759 ;
        RECT  0 60.741 0.018 60.759 ;
        RECT  64.782 60.201 64.8 60.219 ;
        RECT  0 60.201 0.018 60.219 ;
        RECT  64.782 59.661 64.8 59.679 ;
        RECT  0 59.661 0.018 59.679 ;
        RECT  64.782 59.121 64.8 59.139 ;
        RECT  0 59.121 0.018 59.139 ;
        RECT  64.782 58.581 64.8 58.599 ;
        RECT  0 58.581 0.018 58.599 ;
        RECT  64.782 58.041 64.8 58.059 ;
        RECT  0 58.041 0.018 58.059 ;
        RECT  64.782 57.501 64.8 57.519 ;
        RECT  0 57.501 0.018 57.519 ;
        RECT  64.782 56.961 64.8 56.979 ;
        RECT  0 56.961 0.018 56.979 ;
        RECT  64.782 56.421 64.8 56.439 ;
        RECT  0 56.421 0.018 56.439 ;
        RECT  64.782 55.881 64.8 55.899 ;
        RECT  0 55.881 0.018 55.899 ;
        RECT  64.782 55.341 64.8 55.359 ;
        RECT  0 55.341 0.018 55.359 ;
        RECT  64.782 54.801 64.8 54.819 ;
        RECT  0 54.801 0.018 54.819 ;
        RECT  64.782 54.261 64.8 54.279 ;
        RECT  0 54.261 0.018 54.279 ;
        RECT  64.782 53.721 64.8 53.739 ;
        RECT  0 53.721 0.018 53.739 ;
        RECT  64.782 53.181 64.8 53.199 ;
        RECT  0 53.181 0.018 53.199 ;
        RECT  64.782 52.641 64.8 52.659 ;
        RECT  0 52.641 0.018 52.659 ;
        RECT  64.782 52.101 64.8 52.119 ;
        RECT  0 52.101 0.018 52.119 ;
        RECT  64.782 51.561 64.8 51.579 ;
        RECT  0 51.561 0.018 51.579 ;
        RECT  64.782 51.021 64.8 51.039 ;
        RECT  0 51.021 0.018 51.039 ;
        RECT  64.782 50.481 64.8 50.499 ;
        RECT  0 50.481 0.018 50.499 ;
        RECT  64.782 49.941 64.8 49.959 ;
        RECT  0 49.941 0.018 49.959 ;
        RECT  64.782 49.401 64.8 49.419 ;
        RECT  0 49.401 0.018 49.419 ;
        RECT  64.782 48.861 64.8 48.879 ;
        RECT  0 48.861 0.018 48.879 ;
        RECT  64.782 48.321 64.8 48.339 ;
        RECT  0 48.321 0.018 48.339 ;
        RECT  64.782 47.781 64.8 47.799 ;
        RECT  0 47.781 0.018 47.799 ;
        RECT  64.782 47.241 64.8 47.259 ;
        RECT  0 47.241 0.018 47.259 ;
        RECT  64.782 46.701 64.8 46.719 ;
        RECT  0 46.701 0.018 46.719 ;
        RECT  64.782 46.161 64.8 46.179 ;
        RECT  0 46.161 0.018 46.179 ;
        RECT  64.782 45.621 64.8 45.639 ;
        RECT  0 45.621 0.018 45.639 ;
        RECT  64.782 45.081 64.8 45.099 ;
        RECT  0 45.081 0.018 45.099 ;
        RECT  64.782 44.541 64.8 44.559 ;
        RECT  0 44.541 0.018 44.559 ;
        RECT  64.782 44.001 64.8 44.019 ;
        RECT  0 44.001 0.018 44.019 ;
        RECT  64.782 43.461 64.8 43.479 ;
        RECT  0 43.461 0.018 43.479 ;
        RECT  64.782 42.921 64.8 42.939 ;
        RECT  0 42.921 0.018 42.939 ;
        RECT  64.782 42.381 64.8 42.399 ;
        RECT  0 42.381 0.018 42.399 ;
        RECT  64.782 41.841 64.8 41.859 ;
        RECT  0 41.841 0.018 41.859 ;
        RECT  64.782 41.301 64.8 41.319 ;
        RECT  0 41.301 0.018 41.319 ;
        RECT  64.782 40.761 64.8 40.779 ;
        RECT  0 40.761 0.018 40.779 ;
        RECT  64.782 40.221 64.8 40.239 ;
        RECT  0 40.221 0.018 40.239 ;
        RECT  64.782 39.681 64.8 39.699 ;
        RECT  0 39.681 0.018 39.699 ;
        RECT  64.782 39.141 64.8 39.159 ;
        RECT  0 39.141 0.018 39.159 ;
        RECT  64.782 38.601 64.8 38.619 ;
        RECT  0 38.601 0.018 38.619 ;
        RECT  64.782 38.061 64.8 38.079 ;
        RECT  0 38.061 0.018 38.079 ;
        RECT  64.782 37.521 64.8 37.539 ;
        RECT  0 37.521 0.018 37.539 ;
        RECT  64.782 36.981 64.8 36.999 ;
        RECT  0 36.981 0.018 36.999 ;
        RECT  64.782 36.441 64.8 36.459 ;
        RECT  0 36.441 0.018 36.459 ;
        RECT  64.782 35.901 64.8 35.919 ;
        RECT  0 35.901 0.018 35.919 ;
        RECT  64.782 35.361 64.8 35.379 ;
        RECT  0 35.361 0.018 35.379 ;
        RECT  64.782 34.821 64.8 34.839 ;
        RECT  0 34.821 0.018 34.839 ;
        RECT  64.782 34.281 64.8 34.299 ;
        RECT  0 34.281 0.018 34.299 ;
        RECT  64.782 33.741 64.8 33.759 ;
        RECT  0 33.741 0.018 33.759 ;
        RECT  64.782 33.201 64.8 33.219 ;
        RECT  0 33.201 0.018 33.219 ;
        RECT  64.782 32.661 64.8 32.679 ;
        RECT  0 32.661 0.018 32.679 ;
        RECT  64.782 32.121 64.8 32.139 ;
        RECT  0 32.121 0.018 32.139 ;
        RECT  64.782 31.581 64.8 31.599 ;
        RECT  0 31.581 0.018 31.599 ;
        RECT  64.782 31.041 64.8 31.059 ;
        RECT  0 31.041 0.018 31.059 ;
        RECT  64.782 30.501 64.8 30.519 ;
        RECT  0 30.501 0.018 30.519 ;
        RECT  64.782 29.961 64.8 29.979 ;
        RECT  0 29.961 0.018 29.979 ;
        RECT  64.782 29.421 64.8 29.439 ;
        RECT  0 29.421 0.018 29.439 ;
        RECT  64.782 28.881 64.8 28.899 ;
        RECT  0 28.881 0.018 28.899 ;
        RECT  64.782 28.341 64.8 28.359 ;
        RECT  0 28.341 0.018 28.359 ;
        RECT  64.782 27.801 64.8 27.819 ;
        RECT  0 27.801 0.018 27.819 ;
        RECT  64.782 27.261 64.8 27.279 ;
        RECT  0 27.261 0.018 27.279 ;
        RECT  64.782 26.721 64.8 26.739 ;
        RECT  0 26.721 0.018 26.739 ;
        RECT  64.782 26.181 64.8 26.199 ;
        RECT  0 26.181 0.018 26.199 ;
        RECT  64.782 25.641 64.8 25.659 ;
        RECT  0 25.641 0.018 25.659 ;
        RECT  64.782 25.101 64.8 25.119 ;
        RECT  0 25.101 0.018 25.119 ;
        RECT  64.782 24.561 64.8 24.579 ;
        RECT  0 24.561 0.018 24.579 ;
        RECT  64.782 24.021 64.8 24.039 ;
        RECT  0 24.021 0.018 24.039 ;
        RECT  64.782 23.481 64.8 23.499 ;
        RECT  0 23.481 0.018 23.499 ;
        RECT  64.782 22.941 64.8 22.959 ;
        RECT  0 22.941 0.018 22.959 ;
        RECT  64.782 22.401 64.8 22.419 ;
        RECT  0 22.401 0.018 22.419 ;
        RECT  64.782 21.861 64.8 21.879 ;
        RECT  0 21.861 0.018 21.879 ;
        RECT  64.782 21.321 64.8 21.339 ;
        RECT  0 21.321 0.018 21.339 ;
        RECT  64.782 20.781 64.8 20.799 ;
        RECT  0 20.781 0.018 20.799 ;
        RECT  64.782 20.241 64.8 20.259 ;
        RECT  0 20.241 0.018 20.259 ;
        RECT  64.782 19.701 64.8 19.719 ;
        RECT  0 19.701 0.018 19.719 ;
        RECT  64.782 19.161 64.8 19.179 ;
        RECT  0 19.161 0.018 19.179 ;
        RECT  64.782 18.621 64.8 18.639 ;
        RECT  0 18.621 0.018 18.639 ;
        RECT  64.782 18.081 64.8 18.099 ;
        RECT  0 18.081 0.018 18.099 ;
        RECT  64.782 17.541 64.8 17.559 ;
        RECT  0 17.541 0.018 17.559 ;
        RECT  64.782 17.001 64.8 17.019 ;
        RECT  0 17.001 0.018 17.019 ;
        RECT  64.782 16.461 64.8 16.479 ;
        RECT  0 16.461 0.018 16.479 ;
        RECT  64.782 15.921 64.8 15.939 ;
        RECT  0 15.921 0.018 15.939 ;
        RECT  64.782 15.381 64.8 15.399 ;
        RECT  0 15.381 0.018 15.399 ;
        RECT  64.782 14.841 64.8 14.859 ;
        RECT  0 14.841 0.018 14.859 ;
        RECT  64.782 14.301 64.8 14.319 ;
        RECT  0 14.301 0.018 14.319 ;
        RECT  64.782 13.761 64.8 13.779 ;
        RECT  0 13.761 0.018 13.779 ;
        RECT  64.782 13.221 64.8 13.239 ;
        RECT  0 13.221 0.018 13.239 ;
        RECT  64.782 12.681 64.8 12.699 ;
        RECT  0 12.681 0.018 12.699 ;
        RECT  64.782 12.141 64.8 12.159 ;
        RECT  0 12.141 0.018 12.159 ;
        RECT  64.782 11.601 64.8 11.619 ;
        RECT  0 11.601 0.018 11.619 ;
        RECT  64.782 11.061 64.8 11.079 ;
        RECT  0 11.061 0.018 11.079 ;
        RECT  64.782 10.521 64.8 10.539 ;
        RECT  0 10.521 0.018 10.539 ;
        RECT  64.782 9.981 64.8 9.999 ;
        RECT  0 9.981 0.018 9.999 ;
        RECT  64.782 9.441 64.8 9.459 ;
        RECT  0 9.441 0.018 9.459 ;
        RECT  64.782 8.901 64.8 8.919 ;
        RECT  0 8.901 0.018 8.919 ;
        RECT  64.782 8.361 64.8 8.379 ;
        RECT  0 8.361 0.018 8.379 ;
        RECT  64.782 7.821 64.8 7.839 ;
        RECT  0 7.821 0.018 7.839 ;
        RECT  64.782 7.281 64.8 7.299 ;
        RECT  0 7.281 0.018 7.299 ;
        RECT  64.782 6.741 64.8 6.759 ;
        RECT  0 6.741 0.018 6.759 ;
        RECT  64.782 6.201 64.8 6.219 ;
        RECT  0 6.201 0.018 6.219 ;
        RECT  64.782 5.661 64.8 5.679 ;
        RECT  0 5.661 0.018 5.679 ;
        RECT  64.782 5.121 64.8 5.139 ;
        RECT  0 5.121 0.018 5.139 ;
        RECT  64.782 4.581 64.8 4.599 ;
        RECT  0 4.581 0.018 4.599 ;
        RECT  64.782 4.041 64.8 4.059 ;
        RECT  0 4.041 0.018 4.059 ;
        RECT  64.782 3.501 64.8 3.519 ;
        RECT  0 3.501 0.018 3.519 ;
        RECT  64.782 2.961 64.8 2.979 ;
        RECT  0 2.961 0.018 2.979 ;
        RECT  64.782 2.421 64.8 2.439 ;
        RECT  0 2.421 0.018 2.439 ;
        RECT  64.782 1.881 64.8 1.899 ;
        RECT  0 1.881 0.018 1.899 ;
        RECT  64.782 1.341 64.8 1.359 ;
        RECT  0 1.341 0.018 1.359 ;
        RECT  64.782 0.801 64.8 0.819 ;
        RECT  0 0.801 0.018 0.819 ;
    END
  END VDD
  PIN VSS
    DIRECTION INOUT ;
    USE GROUND ;
    PORT
      LAYER M7 ;
        RECT  54.856 0.531 55.144 64.269 ;
        RECT  44.056 0.531 44.344 64.269 ;
        RECT  33.256 0.531 33.544 64.269 ;
        RECT  22.456 0.531 22.744 64.269 ;
        RECT  11.656 0.531 11.944 64.269 ;
        RECT  0.856 0.531 1.144 64.269 ;
      LAYER M6 ;
        RECT  64.768 60.396 64.8 60.684 ;
        RECT  0 60.396 0.032 60.684 ;
        RECT  64.768 54.996 64.8 55.284 ;
        RECT  0 54.996 0.032 55.284 ;
        RECT  64.768 49.596 64.8 49.884 ;
        RECT  0 49.596 0.032 49.884 ;
        RECT  64.768 44.196 64.8 44.484 ;
        RECT  0 44.196 0.032 44.484 ;
        RECT  64.768 38.796 64.8 39.084 ;
        RECT  0 38.796 0.032 39.084 ;
        RECT  64.768 33.396 64.8 33.684 ;
        RECT  0 33.396 0.032 33.684 ;
        RECT  64.768 27.996 64.8 28.284 ;
        RECT  0 27.996 0.032 28.284 ;
        RECT  64.768 22.596 64.8 22.884 ;
        RECT  0 22.596 0.032 22.884 ;
        RECT  64.768 17.196 64.8 17.484 ;
        RECT  0 17.196 0.032 17.484 ;
        RECT  64.768 11.796 64.8 12.084 ;
        RECT  0 11.796 0.032 12.084 ;
        RECT  64.768 6.396 64.8 6.684 ;
        RECT  0 6.396 0.032 6.684 ;
        RECT  64.768 0.996 64.8 1.284 ;
        RECT  0 0.996 0.032 1.284 ;
      LAYER M2 ;
        RECT  64.782 64.251 64.8 64.269 ;
        RECT  0 64.251 0.018 64.269 ;
        RECT  64.782 63.711 64.8 63.729 ;
        RECT  0 63.711 0.018 63.729 ;
        RECT  64.782 63.171 64.8 63.189 ;
        RECT  0 63.171 0.018 63.189 ;
        RECT  64.782 62.631 64.8 62.649 ;
        RECT  0 62.631 0.018 62.649 ;
        RECT  64.782 62.091 64.8 62.109 ;
        RECT  0 62.091 0.018 62.109 ;
        RECT  64.782 61.551 64.8 61.569 ;
        RECT  0 61.551 0.018 61.569 ;
        RECT  64.782 61.011 64.8 61.029 ;
        RECT  0 61.011 0.018 61.029 ;
        RECT  64.782 60.471 64.8 60.489 ;
        RECT  0 60.471 0.018 60.489 ;
        RECT  64.782 59.931 64.8 59.949 ;
        RECT  0 59.931 0.018 59.949 ;
        RECT  64.782 59.391 64.8 59.409 ;
        RECT  0 59.391 0.018 59.409 ;
        RECT  64.782 58.851 64.8 58.869 ;
        RECT  0 58.851 0.018 58.869 ;
        RECT  64.782 58.311 64.8 58.329 ;
        RECT  0 58.311 0.018 58.329 ;
        RECT  64.782 57.771 64.8 57.789 ;
        RECT  0 57.771 0.018 57.789 ;
        RECT  64.782 57.231 64.8 57.249 ;
        RECT  0 57.231 0.018 57.249 ;
        RECT  64.782 56.691 64.8 56.709 ;
        RECT  0 56.691 0.018 56.709 ;
        RECT  64.782 56.151 64.8 56.169 ;
        RECT  0 56.151 0.018 56.169 ;
        RECT  64.782 55.611 64.8 55.629 ;
        RECT  0 55.611 0.018 55.629 ;
        RECT  64.782 55.071 64.8 55.089 ;
        RECT  0 55.071 0.018 55.089 ;
        RECT  64.782 54.531 64.8 54.549 ;
        RECT  0 54.531 0.018 54.549 ;
        RECT  64.782 53.991 64.8 54.009 ;
        RECT  0 53.991 0.018 54.009 ;
        RECT  64.782 53.451 64.8 53.469 ;
        RECT  0 53.451 0.018 53.469 ;
        RECT  64.782 52.911 64.8 52.929 ;
        RECT  0 52.911 0.018 52.929 ;
        RECT  64.782 52.371 64.8 52.389 ;
        RECT  0 52.371 0.018 52.389 ;
        RECT  64.782 51.831 64.8 51.849 ;
        RECT  0 51.831 0.018 51.849 ;
        RECT  64.782 51.291 64.8 51.309 ;
        RECT  0 51.291 0.018 51.309 ;
        RECT  64.782 50.751 64.8 50.769 ;
        RECT  0 50.751 0.018 50.769 ;
        RECT  64.782 50.211 64.8 50.229 ;
        RECT  0 50.211 0.018 50.229 ;
        RECT  64.782 49.671 64.8 49.689 ;
        RECT  0 49.671 0.018 49.689 ;
        RECT  64.782 49.131 64.8 49.149 ;
        RECT  0 49.131 0.018 49.149 ;
        RECT  64.782 48.591 64.8 48.609 ;
        RECT  0 48.591 0.018 48.609 ;
        RECT  64.782 48.051 64.8 48.069 ;
        RECT  0 48.051 0.018 48.069 ;
        RECT  64.782 47.511 64.8 47.529 ;
        RECT  0 47.511 0.018 47.529 ;
        RECT  64.782 46.971 64.8 46.989 ;
        RECT  0 46.971 0.018 46.989 ;
        RECT  64.782 46.431 64.8 46.449 ;
        RECT  0 46.431 0.018 46.449 ;
        RECT  64.782 45.891 64.8 45.909 ;
        RECT  0 45.891 0.018 45.909 ;
        RECT  64.782 45.351 64.8 45.369 ;
        RECT  0 45.351 0.018 45.369 ;
        RECT  64.782 44.811 64.8 44.829 ;
        RECT  0 44.811 0.018 44.829 ;
        RECT  64.782 44.271 64.8 44.289 ;
        RECT  0 44.271 0.018 44.289 ;
        RECT  64.782 43.731 64.8 43.749 ;
        RECT  0 43.731 0.018 43.749 ;
        RECT  64.782 43.191 64.8 43.209 ;
        RECT  0 43.191 0.018 43.209 ;
        RECT  64.782 42.651 64.8 42.669 ;
        RECT  0 42.651 0.018 42.669 ;
        RECT  64.782 42.111 64.8 42.129 ;
        RECT  0 42.111 0.018 42.129 ;
        RECT  64.782 41.571 64.8 41.589 ;
        RECT  0 41.571 0.018 41.589 ;
        RECT  64.782 41.031 64.8 41.049 ;
        RECT  0 41.031 0.018 41.049 ;
        RECT  64.782 40.491 64.8 40.509 ;
        RECT  0 40.491 0.018 40.509 ;
        RECT  64.782 39.951 64.8 39.969 ;
        RECT  0 39.951 0.018 39.969 ;
        RECT  64.782 39.411 64.8 39.429 ;
        RECT  0 39.411 0.018 39.429 ;
        RECT  64.782 38.871 64.8 38.889 ;
        RECT  0 38.871 0.018 38.889 ;
        RECT  64.782 38.331 64.8 38.349 ;
        RECT  0 38.331 0.018 38.349 ;
        RECT  64.782 37.791 64.8 37.809 ;
        RECT  0 37.791 0.018 37.809 ;
        RECT  64.782 37.251 64.8 37.269 ;
        RECT  0 37.251 0.018 37.269 ;
        RECT  64.782 36.711 64.8 36.729 ;
        RECT  0 36.711 0.018 36.729 ;
        RECT  64.782 36.171 64.8 36.189 ;
        RECT  0 36.171 0.018 36.189 ;
        RECT  64.782 35.631 64.8 35.649 ;
        RECT  0 35.631 0.018 35.649 ;
        RECT  64.782 35.091 64.8 35.109 ;
        RECT  0 35.091 0.018 35.109 ;
        RECT  64.782 34.551 64.8 34.569 ;
        RECT  0 34.551 0.018 34.569 ;
        RECT  64.782 34.011 64.8 34.029 ;
        RECT  0 34.011 0.018 34.029 ;
        RECT  64.782 33.471 64.8 33.489 ;
        RECT  0 33.471 0.018 33.489 ;
        RECT  64.782 32.931 64.8 32.949 ;
        RECT  0 32.931 0.018 32.949 ;
        RECT  64.782 32.391 64.8 32.409 ;
        RECT  0 32.391 0.018 32.409 ;
        RECT  64.782 31.851 64.8 31.869 ;
        RECT  0 31.851 0.018 31.869 ;
        RECT  64.782 31.311 64.8 31.329 ;
        RECT  0 31.311 0.018 31.329 ;
        RECT  64.782 30.771 64.8 30.789 ;
        RECT  0 30.771 0.018 30.789 ;
        RECT  64.782 30.231 64.8 30.249 ;
        RECT  0 30.231 0.018 30.249 ;
        RECT  64.782 29.691 64.8 29.709 ;
        RECT  0 29.691 0.018 29.709 ;
        RECT  64.782 29.151 64.8 29.169 ;
        RECT  0 29.151 0.018 29.169 ;
        RECT  64.782 28.611 64.8 28.629 ;
        RECT  0 28.611 0.018 28.629 ;
        RECT  64.782 28.071 64.8 28.089 ;
        RECT  0 28.071 0.018 28.089 ;
        RECT  64.782 27.531 64.8 27.549 ;
        RECT  0 27.531 0.018 27.549 ;
        RECT  64.782 26.991 64.8 27.009 ;
        RECT  0 26.991 0.018 27.009 ;
        RECT  64.782 26.451 64.8 26.469 ;
        RECT  0 26.451 0.018 26.469 ;
        RECT  64.782 25.911 64.8 25.929 ;
        RECT  0 25.911 0.018 25.929 ;
        RECT  64.782 25.371 64.8 25.389 ;
        RECT  0 25.371 0.018 25.389 ;
        RECT  64.782 24.831 64.8 24.849 ;
        RECT  0 24.831 0.018 24.849 ;
        RECT  64.782 24.291 64.8 24.309 ;
        RECT  0 24.291 0.018 24.309 ;
        RECT  64.782 23.751 64.8 23.769 ;
        RECT  0 23.751 0.018 23.769 ;
        RECT  64.782 23.211 64.8 23.229 ;
        RECT  0 23.211 0.018 23.229 ;
        RECT  64.782 22.671 64.8 22.689 ;
        RECT  0 22.671 0.018 22.689 ;
        RECT  64.782 22.131 64.8 22.149 ;
        RECT  0 22.131 0.018 22.149 ;
        RECT  64.782 21.591 64.8 21.609 ;
        RECT  0 21.591 0.018 21.609 ;
        RECT  64.782 21.051 64.8 21.069 ;
        RECT  0 21.051 0.018 21.069 ;
        RECT  64.782 20.511 64.8 20.529 ;
        RECT  0 20.511 0.018 20.529 ;
        RECT  64.782 19.971 64.8 19.989 ;
        RECT  0 19.971 0.018 19.989 ;
        RECT  64.782 19.431 64.8 19.449 ;
        RECT  0 19.431 0.018 19.449 ;
        RECT  64.782 18.891 64.8 18.909 ;
        RECT  0 18.891 0.018 18.909 ;
        RECT  64.782 18.351 64.8 18.369 ;
        RECT  0 18.351 0.018 18.369 ;
        RECT  64.782 17.811 64.8 17.829 ;
        RECT  0 17.811 0.018 17.829 ;
        RECT  64.782 17.271 64.8 17.289 ;
        RECT  0 17.271 0.018 17.289 ;
        RECT  64.782 16.731 64.8 16.749 ;
        RECT  0 16.731 0.018 16.749 ;
        RECT  64.782 16.191 64.8 16.209 ;
        RECT  0 16.191 0.018 16.209 ;
        RECT  64.782 15.651 64.8 15.669 ;
        RECT  0 15.651 0.018 15.669 ;
        RECT  64.782 15.111 64.8 15.129 ;
        RECT  0 15.111 0.018 15.129 ;
        RECT  64.782 14.571 64.8 14.589 ;
        RECT  0 14.571 0.018 14.589 ;
        RECT  64.782 14.031 64.8 14.049 ;
        RECT  0 14.031 0.018 14.049 ;
        RECT  64.782 13.491 64.8 13.509 ;
        RECT  0 13.491 0.018 13.509 ;
        RECT  64.782 12.951 64.8 12.969 ;
        RECT  0 12.951 0.018 12.969 ;
        RECT  64.782 12.411 64.8 12.429 ;
        RECT  0 12.411 0.018 12.429 ;
        RECT  64.782 11.871 64.8 11.889 ;
        RECT  0 11.871 0.018 11.889 ;
        RECT  64.782 11.331 64.8 11.349 ;
        RECT  0 11.331 0.018 11.349 ;
        RECT  64.782 10.791 64.8 10.809 ;
        RECT  0 10.791 0.018 10.809 ;
        RECT  64.782 10.251 64.8 10.269 ;
        RECT  0 10.251 0.018 10.269 ;
        RECT  64.782 9.711 64.8 9.729 ;
        RECT  0 9.711 0.018 9.729 ;
        RECT  64.782 9.171 64.8 9.189 ;
        RECT  0 9.171 0.018 9.189 ;
        RECT  64.782 8.631 64.8 8.649 ;
        RECT  0 8.631 0.018 8.649 ;
        RECT  64.782 8.091 64.8 8.109 ;
        RECT  0 8.091 0.018 8.109 ;
        RECT  64.782 7.551 64.8 7.569 ;
        RECT  0 7.551 0.018 7.569 ;
        RECT  64.782 7.011 64.8 7.029 ;
        RECT  0 7.011 0.018 7.029 ;
        RECT  64.782 6.471 64.8 6.489 ;
        RECT  0 6.471 0.018 6.489 ;
        RECT  64.782 5.931 64.8 5.949 ;
        RECT  0 5.931 0.018 5.949 ;
        RECT  64.782 5.391 64.8 5.409 ;
        RECT  0 5.391 0.018 5.409 ;
        RECT  64.782 4.851 64.8 4.869 ;
        RECT  0 4.851 0.018 4.869 ;
        RECT  64.782 4.311 64.8 4.329 ;
        RECT  0 4.311 0.018 4.329 ;
        RECT  64.782 3.771 64.8 3.789 ;
        RECT  0 3.771 0.018 3.789 ;
        RECT  64.782 3.231 64.8 3.249 ;
        RECT  0 3.231 0.018 3.249 ;
        RECT  64.782 2.691 64.8 2.709 ;
        RECT  0 2.691 0.018 2.709 ;
        RECT  64.782 2.151 64.8 2.169 ;
        RECT  0 2.151 0.018 2.169 ;
        RECT  64.782 1.611 64.8 1.629 ;
        RECT  0 1.611 0.018 1.629 ;
        RECT  64.782 1.071 64.8 1.089 ;
        RECT  0 1.071 0.018 1.089 ;
        RECT  64.782 0.531 64.8 0.549 ;
        RECT  0 0.531 0.018 0.549 ;
      LAYER M1 ;
        RECT  64.782 64.251 64.8 64.269 ;
        RECT  0 64.251 0.018 64.269 ;
        RECT  64.782 63.711 64.8 63.729 ;
        RECT  0 63.711 0.018 63.729 ;
        RECT  64.782 63.171 64.8 63.189 ;
        RECT  0 63.171 0.018 63.189 ;
        RECT  64.782 62.631 64.8 62.649 ;
        RECT  0 62.631 0.018 62.649 ;
        RECT  64.782 62.091 64.8 62.109 ;
        RECT  0 62.091 0.018 62.109 ;
        RECT  64.782 61.551 64.8 61.569 ;
        RECT  0 61.551 0.018 61.569 ;
        RECT  64.782 61.011 64.8 61.029 ;
        RECT  0 61.011 0.018 61.029 ;
        RECT  64.782 60.471 64.8 60.489 ;
        RECT  0 60.471 0.018 60.489 ;
        RECT  64.782 59.931 64.8 59.949 ;
        RECT  0 59.931 0.018 59.949 ;
        RECT  64.782 59.391 64.8 59.409 ;
        RECT  0 59.391 0.018 59.409 ;
        RECT  64.782 58.851 64.8 58.869 ;
        RECT  0 58.851 0.018 58.869 ;
        RECT  64.782 58.311 64.8 58.329 ;
        RECT  0 58.311 0.018 58.329 ;
        RECT  64.782 57.771 64.8 57.789 ;
        RECT  0 57.771 0.018 57.789 ;
        RECT  64.782 57.231 64.8 57.249 ;
        RECT  0 57.231 0.018 57.249 ;
        RECT  64.782 56.691 64.8 56.709 ;
        RECT  0 56.691 0.018 56.709 ;
        RECT  64.782 56.151 64.8 56.169 ;
        RECT  0 56.151 0.018 56.169 ;
        RECT  64.782 55.611 64.8 55.629 ;
        RECT  0 55.611 0.018 55.629 ;
        RECT  64.782 55.071 64.8 55.089 ;
        RECT  0 55.071 0.018 55.089 ;
        RECT  64.782 54.531 64.8 54.549 ;
        RECT  0 54.531 0.018 54.549 ;
        RECT  64.782 53.991 64.8 54.009 ;
        RECT  0 53.991 0.018 54.009 ;
        RECT  64.782 53.451 64.8 53.469 ;
        RECT  0 53.451 0.018 53.469 ;
        RECT  64.782 52.911 64.8 52.929 ;
        RECT  0 52.911 0.018 52.929 ;
        RECT  64.782 52.371 64.8 52.389 ;
        RECT  0 52.371 0.018 52.389 ;
        RECT  64.782 51.831 64.8 51.849 ;
        RECT  0 51.831 0.018 51.849 ;
        RECT  64.782 51.291 64.8 51.309 ;
        RECT  0 51.291 0.018 51.309 ;
        RECT  64.782 50.751 64.8 50.769 ;
        RECT  0 50.751 0.018 50.769 ;
        RECT  64.782 50.211 64.8 50.229 ;
        RECT  0 50.211 0.018 50.229 ;
        RECT  64.782 49.671 64.8 49.689 ;
        RECT  0 49.671 0.018 49.689 ;
        RECT  64.782 49.131 64.8 49.149 ;
        RECT  0 49.131 0.018 49.149 ;
        RECT  64.782 48.591 64.8 48.609 ;
        RECT  0 48.591 0.018 48.609 ;
        RECT  64.782 48.051 64.8 48.069 ;
        RECT  0 48.051 0.018 48.069 ;
        RECT  64.782 47.511 64.8 47.529 ;
        RECT  0 47.511 0.018 47.529 ;
        RECT  64.782 46.971 64.8 46.989 ;
        RECT  0 46.971 0.018 46.989 ;
        RECT  64.782 46.431 64.8 46.449 ;
        RECT  0 46.431 0.018 46.449 ;
        RECT  64.782 45.891 64.8 45.909 ;
        RECT  0 45.891 0.018 45.909 ;
        RECT  64.782 45.351 64.8 45.369 ;
        RECT  0 45.351 0.018 45.369 ;
        RECT  64.782 44.811 64.8 44.829 ;
        RECT  0 44.811 0.018 44.829 ;
        RECT  64.782 44.271 64.8 44.289 ;
        RECT  0 44.271 0.018 44.289 ;
        RECT  64.782 43.731 64.8 43.749 ;
        RECT  0 43.731 0.018 43.749 ;
        RECT  64.782 43.191 64.8 43.209 ;
        RECT  0 43.191 0.018 43.209 ;
        RECT  64.782 42.651 64.8 42.669 ;
        RECT  0 42.651 0.018 42.669 ;
        RECT  64.782 42.111 64.8 42.129 ;
        RECT  0 42.111 0.018 42.129 ;
        RECT  64.782 41.571 64.8 41.589 ;
        RECT  0 41.571 0.018 41.589 ;
        RECT  64.782 41.031 64.8 41.049 ;
        RECT  0 41.031 0.018 41.049 ;
        RECT  64.782 40.491 64.8 40.509 ;
        RECT  0 40.491 0.018 40.509 ;
        RECT  64.782 39.951 64.8 39.969 ;
        RECT  0 39.951 0.018 39.969 ;
        RECT  64.782 39.411 64.8 39.429 ;
        RECT  0 39.411 0.018 39.429 ;
        RECT  64.782 38.871 64.8 38.889 ;
        RECT  0 38.871 0.018 38.889 ;
        RECT  64.782 38.331 64.8 38.349 ;
        RECT  0 38.331 0.018 38.349 ;
        RECT  64.782 37.791 64.8 37.809 ;
        RECT  0 37.791 0.018 37.809 ;
        RECT  64.782 37.251 64.8 37.269 ;
        RECT  0 37.251 0.018 37.269 ;
        RECT  64.782 36.711 64.8 36.729 ;
        RECT  0 36.711 0.018 36.729 ;
        RECT  64.782 36.171 64.8 36.189 ;
        RECT  0 36.171 0.018 36.189 ;
        RECT  64.782 35.631 64.8 35.649 ;
        RECT  0 35.631 0.018 35.649 ;
        RECT  64.782 35.091 64.8 35.109 ;
        RECT  0 35.091 0.018 35.109 ;
        RECT  64.782 34.551 64.8 34.569 ;
        RECT  0 34.551 0.018 34.569 ;
        RECT  64.782 34.011 64.8 34.029 ;
        RECT  0 34.011 0.018 34.029 ;
        RECT  64.782 33.471 64.8 33.489 ;
        RECT  0 33.471 0.018 33.489 ;
        RECT  64.782 32.931 64.8 32.949 ;
        RECT  0 32.931 0.018 32.949 ;
        RECT  64.782 32.391 64.8 32.409 ;
        RECT  0 32.391 0.018 32.409 ;
        RECT  64.782 31.851 64.8 31.869 ;
        RECT  0 31.851 0.018 31.869 ;
        RECT  64.782 31.311 64.8 31.329 ;
        RECT  0 31.311 0.018 31.329 ;
        RECT  64.782 30.771 64.8 30.789 ;
        RECT  0 30.771 0.018 30.789 ;
        RECT  64.782 30.231 64.8 30.249 ;
        RECT  0 30.231 0.018 30.249 ;
        RECT  64.782 29.691 64.8 29.709 ;
        RECT  0 29.691 0.018 29.709 ;
        RECT  64.782 29.151 64.8 29.169 ;
        RECT  0 29.151 0.018 29.169 ;
        RECT  64.782 28.611 64.8 28.629 ;
        RECT  0 28.611 0.018 28.629 ;
        RECT  64.782 28.071 64.8 28.089 ;
        RECT  0 28.071 0.018 28.089 ;
        RECT  64.782 27.531 64.8 27.549 ;
        RECT  0 27.531 0.018 27.549 ;
        RECT  64.782 26.991 64.8 27.009 ;
        RECT  0 26.991 0.018 27.009 ;
        RECT  64.782 26.451 64.8 26.469 ;
        RECT  0 26.451 0.018 26.469 ;
        RECT  64.782 25.911 64.8 25.929 ;
        RECT  0 25.911 0.018 25.929 ;
        RECT  64.782 25.371 64.8 25.389 ;
        RECT  0 25.371 0.018 25.389 ;
        RECT  64.782 24.831 64.8 24.849 ;
        RECT  0 24.831 0.018 24.849 ;
        RECT  64.782 24.291 64.8 24.309 ;
        RECT  0 24.291 0.018 24.309 ;
        RECT  64.782 23.751 64.8 23.769 ;
        RECT  0 23.751 0.018 23.769 ;
        RECT  64.782 23.211 64.8 23.229 ;
        RECT  0 23.211 0.018 23.229 ;
        RECT  64.782 22.671 64.8 22.689 ;
        RECT  0 22.671 0.018 22.689 ;
        RECT  64.782 22.131 64.8 22.149 ;
        RECT  0 22.131 0.018 22.149 ;
        RECT  64.782 21.591 64.8 21.609 ;
        RECT  0 21.591 0.018 21.609 ;
        RECT  64.782 21.051 64.8 21.069 ;
        RECT  0 21.051 0.018 21.069 ;
        RECT  64.782 20.511 64.8 20.529 ;
        RECT  0 20.511 0.018 20.529 ;
        RECT  64.782 19.971 64.8 19.989 ;
        RECT  0 19.971 0.018 19.989 ;
        RECT  64.782 19.431 64.8 19.449 ;
        RECT  0 19.431 0.018 19.449 ;
        RECT  64.782 18.891 64.8 18.909 ;
        RECT  0 18.891 0.018 18.909 ;
        RECT  64.782 18.351 64.8 18.369 ;
        RECT  0 18.351 0.018 18.369 ;
        RECT  64.782 17.811 64.8 17.829 ;
        RECT  0 17.811 0.018 17.829 ;
        RECT  64.782 17.271 64.8 17.289 ;
        RECT  0 17.271 0.018 17.289 ;
        RECT  64.782 16.731 64.8 16.749 ;
        RECT  0 16.731 0.018 16.749 ;
        RECT  64.782 16.191 64.8 16.209 ;
        RECT  0 16.191 0.018 16.209 ;
        RECT  64.782 15.651 64.8 15.669 ;
        RECT  0 15.651 0.018 15.669 ;
        RECT  64.782 15.111 64.8 15.129 ;
        RECT  0 15.111 0.018 15.129 ;
        RECT  64.782 14.571 64.8 14.589 ;
        RECT  0 14.571 0.018 14.589 ;
        RECT  64.782 14.031 64.8 14.049 ;
        RECT  0 14.031 0.018 14.049 ;
        RECT  64.782 13.491 64.8 13.509 ;
        RECT  0 13.491 0.018 13.509 ;
        RECT  64.782 12.951 64.8 12.969 ;
        RECT  0 12.951 0.018 12.969 ;
        RECT  64.782 12.411 64.8 12.429 ;
        RECT  0 12.411 0.018 12.429 ;
        RECT  64.782 11.871 64.8 11.889 ;
        RECT  0 11.871 0.018 11.889 ;
        RECT  64.782 11.331 64.8 11.349 ;
        RECT  0 11.331 0.018 11.349 ;
        RECT  64.782 10.791 64.8 10.809 ;
        RECT  0 10.791 0.018 10.809 ;
        RECT  64.782 10.251 64.8 10.269 ;
        RECT  0 10.251 0.018 10.269 ;
        RECT  64.782 9.711 64.8 9.729 ;
        RECT  0 9.711 0.018 9.729 ;
        RECT  64.782 9.171 64.8 9.189 ;
        RECT  0 9.171 0.018 9.189 ;
        RECT  64.782 8.631 64.8 8.649 ;
        RECT  0 8.631 0.018 8.649 ;
        RECT  64.782 8.091 64.8 8.109 ;
        RECT  0 8.091 0.018 8.109 ;
        RECT  64.782 7.551 64.8 7.569 ;
        RECT  0 7.551 0.018 7.569 ;
        RECT  64.782 7.011 64.8 7.029 ;
        RECT  0 7.011 0.018 7.029 ;
        RECT  64.782 6.471 64.8 6.489 ;
        RECT  0 6.471 0.018 6.489 ;
        RECT  64.782 5.931 64.8 5.949 ;
        RECT  0 5.931 0.018 5.949 ;
        RECT  64.782 5.391 64.8 5.409 ;
        RECT  0 5.391 0.018 5.409 ;
        RECT  64.782 4.851 64.8 4.869 ;
        RECT  0 4.851 0.018 4.869 ;
        RECT  64.782 4.311 64.8 4.329 ;
        RECT  0 4.311 0.018 4.329 ;
        RECT  64.782 3.771 64.8 3.789 ;
        RECT  0 3.771 0.018 3.789 ;
        RECT  64.782 3.231 64.8 3.249 ;
        RECT  0 3.231 0.018 3.249 ;
        RECT  64.782 2.691 64.8 2.709 ;
        RECT  0 2.691 0.018 2.709 ;
        RECT  64.782 2.151 64.8 2.169 ;
        RECT  0 2.151 0.018 2.169 ;
        RECT  64.782 1.611 64.8 1.629 ;
        RECT  0 1.611 0.018 1.629 ;
        RECT  64.782 1.071 64.8 1.089 ;
        RECT  0 1.071 0.018 1.089 ;
        RECT  64.782 0.531 64.8 0.549 ;
        RECT  0 0.531 0.018 0.549 ;
    END
  END VSS
  OBS
    LAYER LVTN ;
     RECT  46.116 31.32 46.44 31.455 ;
     RECT  46.602 31.725 47.196 31.86 ;
     RECT  46.062 31.86 46.44 31.995 ;
     RECT  46.764 31.86 47.088 31.995 ;
     RECT  46.278 32.265 47.034 32.4 ;
     RECT  31.212 32.94 32.184 33.075 ;
     RECT  30.888 37.8 31.266 37.935 ;
     RECT  18.306 38.205 19.008 38.34 ;
     RECT  34.128 38.205 34.56 38.34 ;
     RECT  17.118 38.88 17.658 39.015 ;
     RECT  50.598 39.285 51.03 39.42 ;
     RECT  19.116 39.825 20.52 39.96 ;
     RECT  24.462 39.825 24.894 39.96 ;
     RECT  48.762 39.96 49.194 40.095 ;
     RECT  40.554 40.365 41.094 40.5 ;
     RECT  16.254 41.445 16.632 41.58 ;
     RECT  51.408 41.985 51.84 42.12 ;
     RECT  39.528 42.12 40.068 42.255 ;
     RECT  31.158 43.2 31.374 43.335 ;
     RECT  30.618 44.145 30.942 44.28 ;
     RECT  30.618 46.845 31.158 46.98 ;
     RECT  45.198 46.845 46.17 46.98 ;
     RECT  30.348 46.98 30.726 47.115 ;
     RECT  37.152 46.98 37.692 47.115 ;
     RECT  30.942 47.925 31.806 48.06 ;
     RECT  39.42 49.68 40.392 49.815 ;
     RECT  39.582 52.38 40.122 52.515 ;
     RECT  37.692 52.92 38.34 53.055 ;
     RECT  39.096 52.92 40.068 53.055 ;
     RECT  40.23 53.46 41.202 53.595 ;
     RECT  34.668 54.945 35.64 55.08 ;
     RECT  40.662 56.7 41.094 56.835 ;
     RECT  37.152 58.725 37.692 58.86 ;
     RECT  51.408 59.4 51.84 59.535 ;
     RECT  51.462 60.48 51.894 60.615 ;
     RECT  48.978 62.64 49.41 62.775 ;
     RECT  31.05 63.72 32.022 63.855 ;
    LAYER LVTP ;
     RECT  46.116 31.455 46.44 31.59 ;
     RECT  46.602 31.59 47.196 31.725 ;
     RECT  46.062 31.995 46.44 32.13 ;
     RECT  46.764 31.995 47.088 32.13 ;
     RECT  46.278 32.13 47.034 32.265 ;
     RECT  31.212 33.075 32.184 33.21 ;
     RECT  30.888 37.935 31.266 38.07 ;
     RECT  18.306 38.07 19.008 38.205 ;
     RECT  34.128 38.07 34.56 38.205 ;
     RECT  17.118 39.015 17.658 39.15 ;
     RECT  50.598 39.15 51.03 39.285 ;
     RECT  19.116 39.69 20.52 39.825 ;
     RECT  24.462 39.69 24.894 39.825 ;
     RECT  48.762 40.095 49.194 40.23 ;
     RECT  40.554 40.23 41.094 40.365 ;
     RECT  16.254 41.31 16.632 41.445 ;
     RECT  51.408 41.85 51.84 41.985 ;
     RECT  39.528 42.255 40.068 42.39 ;
     RECT  31.158 43.335 31.374 43.47 ;
     RECT  30.618 44.01 30.942 44.145 ;
     RECT  30.618 46.71 31.158 46.845 ;
     RECT  45.198 46.71 46.17 46.845 ;
     RECT  30.348 47.115 30.726 47.25 ;
     RECT  37.152 47.115 37.692 47.25 ;
     RECT  30.942 47.79 31.806 47.925 ;
     RECT  39.42 49.815 40.392 49.95 ;
     RECT  39.582 52.515 40.122 52.65 ;
     RECT  37.692 53.055 38.34 53.19 ;
     RECT  39.096 53.055 40.068 53.19 ;
     RECT  40.23 53.595 41.202 53.73 ;
     RECT  34.668 54.81 35.64 54.945 ;
     RECT  40.662 56.835 41.094 56.97 ;
     RECT  37.152 58.59 37.692 58.725 ;
     RECT  51.408 59.535 51.84 59.67 ;
     RECT  51.462 60.615 51.894 60.75 ;
     RECT  48.978 62.775 49.41 62.91 ;
     RECT  31.05 63.855 32.022 63.99 ;
    LAYER RVTN ;
     RECT  0 0.54 64.8 0.675 ;
     RECT  0 0.945 64.8 1.215 ;
     RECT  0 1.485 64.8 1.755 ;
     RECT  0 2.025 64.8 2.295 ;
     RECT  0 2.565 64.8 2.835 ;
     RECT  0 3.105 64.8 3.375 ;
     RECT  0 3.645 64.8 3.915 ;
     RECT  0 4.185 64.8 4.455 ;
     RECT  0 4.725 64.8 4.995 ;
     RECT  0 5.265 64.8 5.535 ;
     RECT  0 5.805 64.8 6.075 ;
     RECT  0 6.345 64.8 6.615 ;
     RECT  0 6.885 64.8 7.155 ;
     RECT  0 7.425 64.8 7.695 ;
     RECT  0 7.965 64.8 8.235 ;
     RECT  0 8.505 64.8 8.775 ;
     RECT  0 9.045 64.8 9.315 ;
     RECT  0 9.585 64.8 9.855 ;
     RECT  0 10.125 64.8 10.395 ;
     RECT  0 10.665 64.8 10.935 ;
     RECT  0 11.205 64.8 11.475 ;
     RECT  0 11.745 64.8 12.015 ;
     RECT  0 12.285 64.8 12.555 ;
     RECT  0 12.825 64.8 13.095 ;
     RECT  0 13.365 64.8 13.635 ;
     RECT  0 13.905 64.8 14.175 ;
     RECT  0 14.445 64.8 14.715 ;
     RECT  0 14.985 64.8 15.255 ;
     RECT  0 15.525 64.8 15.795 ;
     RECT  0 16.065 64.8 16.335 ;
     RECT  0 16.605 64.8 16.875 ;
     RECT  0 17.145 64.8 17.415 ;
     RECT  0 17.685 64.8 17.955 ;
     RECT  0 18.225 64.8 18.495 ;
     RECT  0 18.765 64.8 19.035 ;
     RECT  0 19.305 64.8 19.575 ;
     RECT  0 19.845 64.8 20.115 ;
     RECT  0 20.385 64.8 20.655 ;
     RECT  0 20.925 64.8 21.195 ;
     RECT  0 21.465 64.8 21.735 ;
     RECT  0 22.005 64.8 22.275 ;
     RECT  0 22.545 64.8 22.815 ;
     RECT  0 23.085 64.8 23.355 ;
     RECT  0 23.625 64.8 23.895 ;
     RECT  0 24.165 64.8 24.435 ;
     RECT  0 24.705 64.8 24.975 ;
     RECT  0 25.245 64.8 25.515 ;
     RECT  0 25.785 64.8 26.055 ;
     RECT  0 26.325 64.8 26.595 ;
     RECT  0 26.865 64.8 27.135 ;
     RECT  0 27.405 64.8 27.675 ;
     RECT  0 27.945 64.8 28.215 ;
     RECT  0 28.485 64.8 28.755 ;
     RECT  0 29.025 64.8 29.295 ;
     RECT  0 29.565 64.8 29.835 ;
     RECT  0 30.105 64.8 30.375 ;
     RECT  0 30.645 64.8 30.915 ;
     RECT  0 31.185 64.8 31.32 ;
     RECT  0 31.32 46.116 31.455 ;
     RECT  46.44 31.32 64.8 31.455 ;
     RECT  0 31.725 46.602 31.86 ;
     RECT  47.196 31.725 64.8 31.86 ;
     RECT  0 31.86 46.062 31.995 ;
     RECT  46.44 31.86 46.764 31.995 ;
     RECT  47.088 31.86 64.8 31.995 ;
     RECT  0 32.265 46.278 32.4 ;
     RECT  47.034 32.265 64.8 32.4 ;
     RECT  0 32.4 64.8 32.535 ;
     RECT  0 32.805 64.8 32.94 ;
     RECT  0 32.94 31.212 33.075 ;
     RECT  32.184 32.94 64.8 33.075 ;
     RECT  0 33.345 64.8 33.615 ;
     RECT  0 33.885 64.8 34.155 ;
     RECT  0 34.425 64.8 34.695 ;
     RECT  0 34.965 64.8 35.235 ;
     RECT  0 35.505 64.8 35.775 ;
     RECT  0 36.045 64.8 36.315 ;
     RECT  0 36.585 64.8 36.855 ;
     RECT  0 37.125 64.8 37.395 ;
     RECT  0 37.665 64.8 37.8 ;
     RECT  0 37.8 30.888 37.935 ;
     RECT  31.266 37.8 64.8 37.935 ;
     RECT  0 38.205 18.306 38.34 ;
     RECT  19.008 38.205 34.128 38.34 ;
     RECT  34.56 38.205 64.8 38.34 ;
     RECT  0 38.34 64.8 38.475 ;
     RECT  0 38.745 64.8 38.88 ;
     RECT  0 38.88 17.118 39.015 ;
     RECT  17.658 38.88 64.8 39.015 ;
     RECT  0 39.285 50.598 39.42 ;
     RECT  51.03 39.285 64.8 39.42 ;
     RECT  0 39.42 64.8 39.555 ;
     RECT  0 39.825 19.116 39.96 ;
     RECT  20.52 39.825 24.462 39.96 ;
     RECT  24.894 39.825 64.8 39.96 ;
     RECT  0 39.96 48.762 40.095 ;
     RECT  49.194 39.96 64.8 40.095 ;
     RECT  0 40.365 40.554 40.5 ;
     RECT  41.094 40.365 64.8 40.5 ;
     RECT  0 40.5 64.8 40.635 ;
     RECT  0 40.905 64.8 41.175 ;
     RECT  0 41.445 16.254 41.58 ;
     RECT  16.632 41.445 64.8 41.58 ;
     RECT  0 41.58 64.8 41.715 ;
     RECT  0 41.985 51.408 42.12 ;
     RECT  51.84 41.985 64.8 42.12 ;
     RECT  0 42.12 39.528 42.255 ;
     RECT  40.068 42.12 64.8 42.255 ;
     RECT  0 42.525 64.8 42.795 ;
     RECT  0 43.065 64.8 43.2 ;
     RECT  0 43.2 31.158 43.335 ;
     RECT  31.374 43.2 64.8 43.335 ;
     RECT  0 43.605 64.8 43.875 ;
     RECT  0 44.145 30.618 44.28 ;
     RECT  30.942 44.145 64.8 44.28 ;
     RECT  0 44.28 64.8 44.415 ;
     RECT  0 44.685 64.8 44.955 ;
     RECT  0 45.225 64.8 45.495 ;
     RECT  0 45.765 64.8 46.035 ;
     RECT  0 46.305 64.8 46.575 ;
     RECT  0 46.845 30.618 46.98 ;
     RECT  31.158 46.845 45.198 46.98 ;
     RECT  46.17 46.845 64.8 46.98 ;
     RECT  0 46.98 30.348 47.115 ;
     RECT  30.726 46.98 37.152 47.115 ;
     RECT  37.692 46.98 64.8 47.115 ;
     RECT  0 47.385 64.8 47.655 ;
     RECT  0 47.925 30.942 48.06 ;
     RECT  31.806 47.925 64.8 48.06 ;
     RECT  0 48.06 64.8 48.195 ;
     RECT  0 48.465 64.8 48.735 ;
     RECT  0 49.005 64.8 49.275 ;
     RECT  0 49.545 64.8 49.68 ;
     RECT  0 49.68 39.42 49.815 ;
     RECT  40.392 49.68 64.8 49.815 ;
     RECT  0 50.085 64.8 50.355 ;
     RECT  0 50.625 64.8 50.895 ;
     RECT  0 51.165 64.8 51.435 ;
     RECT  0 51.705 64.8 51.975 ;
     RECT  0 52.245 64.8 52.38 ;
     RECT  0 52.38 39.582 52.515 ;
     RECT  40.122 52.38 64.8 52.515 ;
     RECT  0 52.785 64.8 52.92 ;
     RECT  0 52.92 37.692 53.055 ;
     RECT  38.34 52.92 39.096 53.055 ;
     RECT  40.068 52.92 64.8 53.055 ;
     RECT  0 53.325 64.8 53.46 ;
     RECT  0 53.46 40.23 53.595 ;
     RECT  41.202 53.46 64.8 53.595 ;
     RECT  0 53.865 64.8 54.135 ;
     RECT  0 54.405 64.8 54.675 ;
     RECT  0 54.945 34.668 55.08 ;
     RECT  35.64 54.945 64.8 55.08 ;
     RECT  0 55.08 64.8 55.215 ;
     RECT  0 55.485 64.8 55.755 ;
     RECT  0 56.025 64.8 56.295 ;
     RECT  0 56.565 64.8 56.7 ;
     RECT  0 56.7 40.662 56.835 ;
     RECT  41.094 56.7 64.8 56.835 ;
     RECT  0 57.105 64.8 57.375 ;
     RECT  0 57.645 64.8 57.915 ;
     RECT  0 58.185 64.8 58.455 ;
     RECT  0 58.725 37.152 58.86 ;
     RECT  37.692 58.725 64.8 58.86 ;
     RECT  0 58.86 64.8 58.995 ;
     RECT  0 59.265 64.8 59.4 ;
     RECT  0 59.4 51.408 59.535 ;
     RECT  51.84 59.4 64.8 59.535 ;
     RECT  0 59.805 64.8 60.075 ;
     RECT  0 60.345 64.8 60.48 ;
     RECT  0 60.48 51.462 60.615 ;
     RECT  51.894 60.48 64.8 60.615 ;
     RECT  0 60.885 64.8 61.155 ;
     RECT  0 61.425 64.8 61.695 ;
     RECT  0 61.965 64.8 62.235 ;
     RECT  0 62.505 64.8 62.64 ;
     RECT  0 62.64 48.978 62.775 ;
     RECT  49.41 62.64 64.8 62.775 ;
     RECT  0 63.045 64.8 63.315 ;
     RECT  0 63.585 64.8 63.72 ;
     RECT  0 63.72 31.05 63.855 ;
     RECT  32.022 63.72 64.8 63.855 ;
     RECT  0 64.125 64.8 64.26 ;
    LAYER RVTP ;
     RECT  0 0.675 64.8 0.945 ;
     RECT  0 1.215 64.8 1.485 ;
     RECT  0 1.755 64.8 2.025 ;
     RECT  0 2.295 64.8 2.565 ;
     RECT  0 2.835 64.8 3.105 ;
     RECT  0 3.375 64.8 3.645 ;
     RECT  0 3.915 64.8 4.185 ;
     RECT  0 4.455 64.8 4.725 ;
     RECT  0 4.995 64.8 5.265 ;
     RECT  0 5.535 64.8 5.805 ;
     RECT  0 6.075 64.8 6.345 ;
     RECT  0 6.615 64.8 6.885 ;
     RECT  0 7.155 64.8 7.425 ;
     RECT  0 7.695 64.8 7.965 ;
     RECT  0 8.235 64.8 8.505 ;
     RECT  0 8.775 64.8 9.045 ;
     RECT  0 9.315 64.8 9.585 ;
     RECT  0 9.855 64.8 10.125 ;
     RECT  0 10.395 64.8 10.665 ;
     RECT  0 10.935 64.8 11.205 ;
     RECT  0 11.475 64.8 11.745 ;
     RECT  0 12.015 64.8 12.285 ;
     RECT  0 12.555 64.8 12.825 ;
     RECT  0 13.095 64.8 13.365 ;
     RECT  0 13.635 64.8 13.905 ;
     RECT  0 14.175 64.8 14.445 ;
     RECT  0 14.715 64.8 14.985 ;
     RECT  0 15.255 64.8 15.525 ;
     RECT  0 15.795 64.8 16.065 ;
     RECT  0 16.335 64.8 16.605 ;
     RECT  0 16.875 64.8 17.145 ;
     RECT  0 17.415 64.8 17.685 ;
     RECT  0 17.955 64.8 18.225 ;
     RECT  0 18.495 64.8 18.765 ;
     RECT  0 19.035 64.8 19.305 ;
     RECT  0 19.575 64.8 19.845 ;
     RECT  0 20.115 64.8 20.385 ;
     RECT  0 20.655 64.8 20.925 ;
     RECT  0 21.195 64.8 21.465 ;
     RECT  0 21.735 64.8 22.005 ;
     RECT  0 22.275 64.8 22.545 ;
     RECT  0 22.815 64.8 23.085 ;
     RECT  0 23.355 64.8 23.625 ;
     RECT  0 23.895 64.8 24.165 ;
     RECT  0 24.435 64.8 24.705 ;
     RECT  0 24.975 64.8 25.245 ;
     RECT  0 25.515 64.8 25.785 ;
     RECT  0 26.055 64.8 26.325 ;
     RECT  0 26.595 64.8 26.865 ;
     RECT  0 27.135 64.8 27.405 ;
     RECT  0 27.675 64.8 27.945 ;
     RECT  0 28.215 64.8 28.485 ;
     RECT  0 28.755 64.8 29.025 ;
     RECT  0 29.295 64.8 29.565 ;
     RECT  0 29.835 64.8 30.105 ;
     RECT  0 30.375 64.8 30.645 ;
     RECT  0 30.915 64.8 31.185 ;
     RECT  0 31.455 46.116 31.59 ;
     RECT  46.44 31.455 64.8 31.59 ;
     RECT  0 31.59 46.602 31.725 ;
     RECT  47.196 31.59 64.8 31.725 ;
     RECT  0 31.995 46.062 32.13 ;
     RECT  46.44 31.995 46.764 32.13 ;
     RECT  47.088 31.995 64.8 32.13 ;
     RECT  0 32.13 46.278 32.265 ;
     RECT  47.034 32.13 64.8 32.265 ;
     RECT  0 32.535 64.8 32.805 ;
     RECT  0 33.075 31.212 33.21 ;
     RECT  32.184 33.075 64.8 33.21 ;
     RECT  0 33.21 64.8 33.345 ;
     RECT  0 33.615 64.8 33.885 ;
     RECT  0 34.155 64.8 34.425 ;
     RECT  0 34.695 64.8 34.965 ;
     RECT  0 35.235 64.8 35.505 ;
     RECT  0 35.775 64.8 36.045 ;
     RECT  0 36.315 64.8 36.585 ;
     RECT  0 36.855 64.8 37.125 ;
     RECT  0 37.395 64.8 37.665 ;
     RECT  0 37.935 30.888 38.07 ;
     RECT  31.266 37.935 64.8 38.07 ;
     RECT  0 38.07 18.306 38.205 ;
     RECT  19.008 38.07 34.128 38.205 ;
     RECT  34.56 38.07 64.8 38.205 ;
     RECT  0 38.475 64.8 38.745 ;
     RECT  0 39.015 17.118 39.15 ;
     RECT  17.658 39.015 64.8 39.15 ;
     RECT  0 39.15 50.598 39.285 ;
     RECT  51.03 39.15 64.8 39.285 ;
     RECT  0 39.555 64.8 39.69 ;
     RECT  0 39.69 19.116 39.825 ;
     RECT  20.52 39.69 24.462 39.825 ;
     RECT  24.894 39.69 64.8 39.825 ;
     RECT  0 40.095 48.762 40.23 ;
     RECT  49.194 40.095 64.8 40.23 ;
     RECT  0 40.23 40.554 40.365 ;
     RECT  41.094 40.23 64.8 40.365 ;
     RECT  0 40.635 64.8 40.905 ;
     RECT  0 41.175 64.8 41.31 ;
     RECT  0 41.31 16.254 41.445 ;
     RECT  16.632 41.31 64.8 41.445 ;
     RECT  0 41.715 64.8 41.85 ;
     RECT  0 41.85 51.408 41.985 ;
     RECT  51.84 41.85 64.8 41.985 ;
     RECT  0 42.255 39.528 42.39 ;
     RECT  40.068 42.255 64.8 42.39 ;
     RECT  0 42.39 64.8 42.525 ;
     RECT  0 42.795 64.8 43.065 ;
     RECT  0 43.335 31.158 43.47 ;
     RECT  31.374 43.335 64.8 43.47 ;
     RECT  0 43.47 64.8 43.605 ;
     RECT  0 43.875 64.8 44.01 ;
     RECT  0 44.01 30.618 44.145 ;
     RECT  30.942 44.01 64.8 44.145 ;
     RECT  0 44.415 64.8 44.685 ;
     RECT  0 44.955 64.8 45.225 ;
     RECT  0 45.495 64.8 45.765 ;
     RECT  0 46.035 64.8 46.305 ;
     RECT  0 46.575 64.8 46.71 ;
     RECT  0 46.71 30.618 46.845 ;
     RECT  31.158 46.71 45.198 46.845 ;
     RECT  46.17 46.71 64.8 46.845 ;
     RECT  0 47.115 30.348 47.25 ;
     RECT  30.726 47.115 37.152 47.25 ;
     RECT  37.692 47.115 64.8 47.25 ;
     RECT  0 47.25 64.8 47.385 ;
     RECT  0 47.655 64.8 47.79 ;
     RECT  0 47.79 30.942 47.925 ;
     RECT  31.806 47.79 64.8 47.925 ;
     RECT  0 48.195 64.8 48.465 ;
     RECT  0 48.735 64.8 49.005 ;
     RECT  0 49.275 64.8 49.545 ;
     RECT  0 49.815 39.42 49.95 ;
     RECT  40.392 49.815 64.8 49.95 ;
     RECT  0 49.95 64.8 50.085 ;
     RECT  0 50.355 64.8 50.625 ;
     RECT  0 50.895 64.8 51.165 ;
     RECT  0 51.435 64.8 51.705 ;
     RECT  0 51.975 64.8 52.245 ;
     RECT  0 52.515 39.582 52.65 ;
     RECT  40.122 52.515 64.8 52.65 ;
     RECT  0 52.65 64.8 52.785 ;
     RECT  0 53.055 37.692 53.19 ;
     RECT  38.34 53.055 39.096 53.19 ;
     RECT  40.068 53.055 64.8 53.19 ;
     RECT  0 53.19 64.8 53.325 ;
     RECT  0 53.595 40.23 53.73 ;
     RECT  41.202 53.595 64.8 53.73 ;
     RECT  0 53.73 64.8 53.865 ;
     RECT  0 54.135 64.8 54.405 ;
     RECT  0 54.675 64.8 54.81 ;
     RECT  0 54.81 34.668 54.945 ;
     RECT  35.64 54.81 64.8 54.945 ;
     RECT  0 55.215 64.8 55.485 ;
     RECT  0 55.755 64.8 56.025 ;
     RECT  0 56.295 64.8 56.565 ;
     RECT  0 56.835 40.662 56.97 ;
     RECT  41.094 56.835 64.8 56.97 ;
     RECT  0 56.97 64.8 57.105 ;
     RECT  0 57.375 64.8 57.645 ;
     RECT  0 57.915 64.8 58.185 ;
     RECT  0 58.455 64.8 58.59 ;
     RECT  0 58.59 37.152 58.725 ;
     RECT  37.692 58.59 64.8 58.725 ;
     RECT  0 58.995 64.8 59.265 ;
     RECT  0 59.535 51.408 59.67 ;
     RECT  51.84 59.535 64.8 59.67 ;
     RECT  0 59.67 64.8 59.805 ;
     RECT  0 60.075 64.8 60.345 ;
     RECT  0 60.615 51.462 60.75 ;
     RECT  51.894 60.615 64.8 60.75 ;
     RECT  0 60.75 64.8 60.885 ;
     RECT  0 61.155 64.8 61.425 ;
     RECT  0 61.695 64.8 61.965 ;
     RECT  0 62.235 64.8 62.505 ;
     RECT  0 62.775 48.978 62.91 ;
     RECT  49.41 62.775 64.8 62.91 ;
     RECT  0 62.91 64.8 63.045 ;
     RECT  0 63.315 64.8 63.585 ;
     RECT  0 63.855 31.05 63.99 ;
     RECT  32.022 63.855 64.8 63.99 ;
     RECT  0 63.99 64.8 64.125 ;
    LAYER M1 ;
     RECT  0 0.531 64.8 64.269 ;
    LAYER M2 ;
     RECT  0 0.531 31.603 64.269 ;
     RECT  31.603 0.531 33.143 64.386 ;
     RECT  33.143 0.531 64.8 64.269 ;
    LAYER M3 ;
     RECT  42.66 0.187 42.678 0.235 ;
     RECT  15.408 0.187 16.326 0.283 ;
     RECT  15.408 0.283 16.434 0.379 ;
     RECT  42.66 0.235 42.75 0.523 ;
     RECT  49.176 0.043 49.194 0.523 ;
     RECT  42.66 0.523 43.545 0.571 ;
     RECT  42.48 0.571 44.118 0.619 ;
     RECT  42.084 0.619 44.118 0.667 ;
     RECT  42.084 0.667 44.226 0.712 ;
     RECT  15.408 0.379 16.614 0.751 ;
     RECT  40.608 0.715 40.626 0.751 ;
     RECT  0.255 0.523 0.345 0.793 ;
     RECT  5.655 0.523 5.745 0.793 ;
     RECT  11.055 0.523 11.145 0.793 ;
     RECT  21.855 0.523 21.945 0.793 ;
     RECT  27.255 0.523 27.345 0.793 ;
     RECT  32.655 0.523 32.745 0.793 ;
     RECT  38.055 0.523 38.145 0.793 ;
     RECT  54.255 0.523 54.345 0.793 ;
     RECT  59.655 0.523 59.745 0.793 ;
     RECT  48.855 0.523 49.194 0.811 ;
     RECT  48.855 0.811 49.554 0.869 ;
     RECT  23.328 0.187 23.346 0.877 ;
     RECT  41.508 0.712 44.226 0.877 ;
     RECT  46.836 0.751 46.854 0.877 ;
     RECT  47.844 0.187 47.862 0.877 ;
     RECT  48.855 0.869 49.194 0.877 ;
     RECT  47.844 0.877 49.194 0.905 ;
     RECT  39.888 0.751 40.626 0.913 ;
     RECT  41.4 0.877 44.226 0.913 ;
     RECT  11.055 0.793 11.337 0.949 ;
     RECT  15.408 0.751 17.046 0.949 ;
     RECT  45.396 0.751 45.414 0.949 ;
     RECT  39.888 0.913 44.226 0.985 ;
     RECT  23.328 0.877 24.57 1.021 ;
     RECT  45.396 0.949 45.594 1.021 ;
     RECT  46.368 0.877 46.854 1.021 ;
     RECT  14.832 0.949 17.046 1.049 ;
     RECT  15.264 1.049 17.046 1.111 ;
     RECT  27.255 0.793 27.537 1.111 ;
     RECT  32.655 0.793 32.937 1.111 ;
     RECT  45.396 1.021 46.854 1.175 ;
     RECT  26.748 1.111 27.954 1.219 ;
     RECT  29.052 1.111 29.07 1.219 ;
     RECT  38.055 0.793 38.337 1.219 ;
     RECT  39.888 0.985 44.406 1.219 ;
     RECT  26.172 1.219 27.954 1.255 ;
     RECT  28.728 1.219 29.07 1.255 ;
     RECT  32.436 1.111 32.994 1.255 ;
     RECT  35.172 1.219 35.19 1.255 ;
     RECT  37.044 1.219 38.337 1.255 ;
     RECT  39.6 1.219 44.406 1.255 ;
     RECT  21.855 0.793 22.137 1.291 ;
     RECT  23.328 1.021 25.074 1.291 ;
     RECT  26.172 1.255 29.07 1.291 ;
     RECT  29.916 1.219 29.934 1.291 ;
     RECT  32.004 1.255 32.994 1.291 ;
     RECT  34.884 1.255 35.946 1.291 ;
     RECT  36.828 1.255 38.337 1.291 ;
     RECT  39.528 1.255 44.406 1.291 ;
     RECT  46.512 1.175 46.854 1.291 ;
     RECT  47.844 0.905 49.137 1.291 ;
     RECT  15.264 1.111 17.226 1.381 ;
     RECT  19.368 1.291 19.386 1.417 ;
     RECT  29.916 1.291 30.006 1.417 ;
     RECT  20.844 1.291 22.137 1.435 ;
     RECT  29.844 1.417 30.006 1.453 ;
     RECT  30.744 1.255 30.762 1.453 ;
     RECT  34.2 1.291 44.406 1.453 ;
     RECT  45.396 1.175 45.774 1.453 ;
     RECT  34.2 1.453 45.774 1.481 ;
     RECT  31.644 1.291 32.994 1.489 ;
     RECT  5.655 0.793 5.937 1.561 ;
     RECT  15.264 1.381 17.298 1.561 ;
     RECT  18.504 1.387 18.522 1.561 ;
     RECT  19.26 1.417 19.386 1.561 ;
     RECT  20.268 1.435 22.137 1.561 ;
     RECT  23.328 1.291 29.07 1.561 ;
     RECT  29.844 1.453 30.762 1.561 ;
     RECT  31.536 1.489 32.994 1.561 ;
     RECT  46.512 1.291 49.137 1.589 ;
     RECT  15.264 1.561 22.137 1.679 ;
     RECT  39.96 1.481 45.774 1.679 ;
     RECT  23.112 1.561 29.07 1.687 ;
     RECT  18.18 1.679 20.898 1.715 ;
     RECT  34.2 1.481 39.042 1.723 ;
     RECT  46.62 1.589 49.137 1.751 ;
     RECT  29.844 1.561 32.994 1.759 ;
     RECT  34.056 1.723 39.042 1.759 ;
     RECT  21.672 1.679 22.137 1.795 ;
     RECT  23.004 1.687 29.07 1.795 ;
     RECT  18.18 1.715 20.826 1.859 ;
     RECT  29.844 1.759 39.042 1.859 ;
     RECT  18.18 1.859 20.754 1.949 ;
     RECT  29.844 1.859 38.898 1.949 ;
     RECT  21.672 1.795 29.07 1.957 ;
     RECT  29.844 1.949 34.578 1.957 ;
     RECT  35.46 1.949 38.898 2.021 ;
     RECT  15.264 1.679 17.226 2.029 ;
     RECT  21.672 1.957 34.578 2.057 ;
     RECT  47.34 1.751 49.137 2.101 ;
     RECT  14.832 2.029 17.226 2.129 ;
     RECT  21.672 2.057 32.937 2.219 ;
     RECT  33.768 2.057 34.578 2.219 ;
     RECT  33.768 2.219 33.858 2.291 ;
     RECT  21.672 2.219 29.106 2.363 ;
     RECT  29.916 2.219 30.114 2.363 ;
     RECT  3.42 1.489 3.438 2.489 ;
     RECT  18.18 1.949 20.718 2.491 ;
     RECT  39.96 1.679 45.63 2.525 ;
     RECT  15.192 2.129 17.226 2.605 ;
     RECT  18.108 2.491 20.718 2.605 ;
     RECT  3.276 2.641 3.294 2.759 ;
     RECT  47.34 2.101 49.338 2.759 ;
     RECT  21.672 2.363 24.03 2.803 ;
     RECT  47.34 2.759 49.137 2.827 ;
     RECT  36.108 2.021 38.898 2.831 ;
     RECT  46.296 2.641 46.314 2.831 ;
     RECT  35.352 2.803 35.37 2.839 ;
     RECT  36.108 2.831 38.862 2.839 ;
     RECT  47.196 2.827 49.137 2.911 ;
     RECT  15.192 2.605 20.718 3.001 ;
     RECT  39.96 2.525 45.486 3.029 ;
     RECT  39.96 3.029 40.986 3.065 ;
     RECT  46.836 2.911 49.137 3.065 ;
     RECT  15.048 3.001 20.718 3.073 ;
     RECT  39.96 3.065 40.77 3.073 ;
     RECT  15.012 3.073 20.718 3.145 ;
     RECT  5.655 1.561 6.03 3.181 ;
     RECT  4.572 2.911 4.59 3.271 ;
     RECT  4.572 3.271 4.698 3.299 ;
     RECT  39.888 3.073 40.77 3.299 ;
     RECT  29.916 2.363 29.934 3.307 ;
     RECT  14.976 3.145 20.718 3.343 ;
     RECT  21.636 2.803 24.03 3.379 ;
     RECT  24.804 2.363 29.106 3.379 ;
     RECT  29.88 3.307 29.934 3.379 ;
     RECT  35.352 2.839 38.862 3.379 ;
     RECT  14.94 3.343 20.718 3.403 ;
     RECT  14.868 3.403 20.718 3.415 ;
     RECT  14.328 3.415 20.862 3.451 ;
     RECT  21.636 3.379 29.934 3.451 ;
     RECT  33.84 2.291 33.858 3.499 ;
     RECT  41.724 3.029 45.486 3.569 ;
     RECT  14.328 3.451 29.934 3.577 ;
     RECT  46.836 3.065 46.854 3.685 ;
     RECT  14.076 3.577 29.934 3.721 ;
     RECT  33.84 3.499 34.254 3.721 ;
     RECT  35.064 3.379 38.862 3.721 ;
     RECT  44.892 3.569 45.486 3.811 ;
     RECT  46.224 3.685 46.854 3.811 ;
     RECT  44.892 3.811 46.854 3.883 ;
     RECT  47.736 3.065 49.137 3.883 ;
     RECT  41.724 3.569 44.154 3.931 ;
     RECT  33.84 3.721 38.862 3.955 ;
     RECT  14.076 3.721 30.402 3.991 ;
     RECT  33.84 3.955 39.114 3.991 ;
     RECT  40.032 3.299 40.77 3.991 ;
     RECT  41.58 3.931 44.154 3.991 ;
     RECT  14.076 3.991 30.51 4.081 ;
     RECT  31.248 2.219 32.937 4.081 ;
     RECT  33.84 3.991 39.258 4.081 ;
     RECT  40.032 3.991 44.154 4.081 ;
     RECT  14.076 4.081 32.937 4.123 ;
     RECT  33.84 4.081 44.154 4.123 ;
     RECT  44.892 3.883 49.137 4.189 ;
     RECT  14.076 4.123 44.154 4.415 ;
     RECT  19.764 4.415 44.154 4.487 ;
     RECT  44.892 4.189 49.77 4.495 ;
     RECT  50.796 4.459 50.814 4.495 ;
     RECT  44.892 4.495 50.814 4.531 ;
     RECT  14.076 4.415 18.954 4.657 ;
     RECT  24.768 4.487 44.154 4.657 ;
     RECT  44.892 4.531 51.174 4.657 ;
     RECT  5.436 3.181 6.03 4.801 ;
     RECT  7.272 2.029 7.29 4.801 ;
     RECT  10.548 0.949 11.337 4.801 ;
     RECT  5.436 4.801 7.29 5.071 ;
     RECT  8.136 3.451 8.154 5.071 ;
     RECT  2.196 2.569 2.214 5.131 ;
     RECT  3.168 2.911 3.186 5.131 ;
     RECT  2.196 5.131 3.186 5.161 ;
     RECT  10.332 4.801 11.337 5.161 ;
     RECT  13.68 4.657 18.954 5.161 ;
     RECT  2.196 5.161 3.222 5.179 ;
     RECT  13.14 5.161 18.954 5.179 ;
     RECT  19.764 4.487 24.03 5.179 ;
     RECT  5.436 5.071 8.154 5.233 ;
     RECT  10.332 5.161 11.79 5.269 ;
     RECT  2.196 5.179 3.546 5.305 ;
     RECT  10.296 5.269 11.79 5.305 ;
     RECT  13.14 5.179 24.03 5.305 ;
     RECT  24.768 4.657 51.174 5.305 ;
     RECT  2.196 5.305 3.87 5.341 ;
     RECT  4.68 3.299 4.698 5.341 ;
     RECT  13.14 5.305 51.174 5.341 ;
     RECT  5.436 5.233 8.658 5.369 ;
     RECT  7.488 5.369 8.658 5.431 ;
     RECT  13.14 5.341 51.39 5.459 ;
     RECT  2.196 5.341 4.698 5.467 ;
     RECT  5.436 5.369 6.678 5.467 ;
     RECT  10.296 5.305 12.258 5.531 ;
     RECT  13.14 5.459 50.958 5.567 ;
     RECT  14.256 5.567 50.958 5.729 ;
     RECT  14.256 5.729 50.742 5.765 ;
     RECT  14.256 5.765 46.998 5.909 ;
     RECT  14.832 5.909 46.998 5.999 ;
     RECT  2.196 5.467 6.678 6.107 ;
     RECT  10.512 5.531 12.258 6.107 ;
     RECT  37.584 5.999 46.998 6.125 ;
     RECT  37.656 6.125 46.998 6.143 ;
     RECT  10.548 6.107 12.258 6.151 ;
     RECT  47.736 5.765 50.742 6.179 ;
     RECT  13.14 5.567 13.158 6.277 ;
     RECT  14.832 5.999 36.81 6.305 ;
     RECT  10.548 6.151 12.294 6.349 ;
     RECT  13.068 6.277 13.158 6.349 ;
     RECT  5.436 6.107 6.678 6.421 ;
     RECT  7.488 5.431 9.27 6.421 ;
     RECT  5.436 6.421 9.27 6.539 ;
     RECT  7.524 6.539 9.27 6.691 ;
     RECT  2.196 6.107 4.698 6.811 ;
     RECT  1.692 6.811 4.698 6.889 ;
     RECT  5.436 6.539 6.57 6.889 ;
     RECT  24.804 6.305 36.81 6.889 ;
     RECT  14.832 6.305 24.03 6.961 ;
     RECT  24.804 6.889 36.99 6.961 ;
     RECT  37.836 6.143 46.998 6.961 ;
     RECT  24.804 6.961 46.998 7.079 ;
     RECT  1.692 6.889 6.57 7.151 ;
     RECT  47.916 6.179 50.742 7.159 ;
     RECT  10.548 6.349 13.158 7.231 ;
     RECT  14.292 6.961 24.03 7.231 ;
     RECT  2.196 7.151 6.57 7.321 ;
     RECT  7.524 6.691 9.378 7.321 ;
     RECT  10.548 7.231 24.03 7.357 ;
     RECT  24.804 7.079 39.402 7.357 ;
     RECT  40.248 7.079 46.998 7.357 ;
     RECT  47.916 7.159 51.39 7.357 ;
     RECT  2.196 7.321 9.378 7.421 ;
     RECT  4.284 7.421 9.378 7.429 ;
     RECT  10.548 7.357 39.402 7.429 ;
     RECT  2.196 7.421 3.546 7.457 ;
     RECT  40.248 7.357 51.39 7.763 ;
     RECT  47.88 7.763 51.39 7.771 ;
     RECT  47.88 7.771 51.426 7.805 ;
     RECT  4.284 7.429 39.402 7.889 ;
     RECT  47.88 7.805 49.77 7.889 ;
     RECT  40.248 7.763 47.106 7.897 ;
     RECT  14.256 7.889 14.274 7.925 ;
     RECT  15.012 7.889 39.402 7.933 ;
     RECT  40.14 7.897 47.106 7.933 ;
     RECT  50.724 7.805 51.426 7.961 ;
     RECT  0.255 0.793 0.537 8.203 ;
     RECT  1.368 8.131 1.386 8.203 ;
     RECT  0.255 8.203 1.386 8.311 ;
     RECT  2.196 7.457 3.51 8.311 ;
     RECT  4.284 7.889 13.05 8.311 ;
     RECT  0.255 8.311 13.05 8.465 ;
     RECT  15.012 7.933 47.106 8.537 ;
     RECT  47.916 7.889 49.77 8.539 ;
     RECT  47.916 8.539 49.806 8.545 ;
     RECT  50.724 7.961 51.066 8.699 ;
     RECT  18.54 8.537 47.106 8.743 ;
     RECT  47.916 8.545 49.842 8.743 ;
     RECT  18.54 8.743 49.842 8.771 ;
     RECT  50.724 8.699 50.742 8.815 ;
     RECT  7.344 8.465 13.05 8.851 ;
     RECT  37.692 8.771 49.842 8.851 ;
     RECT  50.652 8.815 50.742 8.851 ;
     RECT  7.344 8.851 13.158 8.969 ;
     RECT  0.255 8.465 6.57 9.101 ;
     RECT  15.012 8.537 17.802 9.517 ;
     RECT  18.54 8.771 36.846 9.517 ;
     RECT  15.012 9.517 36.846 9.617 ;
     RECT  0.255 9.101 3.474 9.653 ;
     RECT  2.088 9.653 3.474 9.823 ;
     RECT  4.284 9.101 6.57 9.823 ;
     RECT  15.012 9.617 20.61 9.859 ;
     RECT  21.6 9.617 36.846 9.859 ;
     RECT  37.692 8.851 50.742 9.859 ;
     RECT  2.088 9.823 6.57 9.931 ;
     RECT  7.344 8.969 13.014 9.931 ;
     RECT  14.976 9.859 20.61 9.931 ;
     RECT  21.6 9.859 50.742 9.931 ;
     RECT  13.86 10.129 13.878 10.165 ;
     RECT  13.86 10.165 14.022 10.201 ;
     RECT  14.94 9.931 20.61 10.201 ;
     RECT  0.255 9.653 1.35 10.319 ;
     RECT  13.86 10.201 20.61 10.319 ;
     RECT  2.088 9.931 13.014 10.399 ;
     RECT  14.004 10.319 20.61 10.399 ;
     RECT  21.6 9.931 50.994 10.399 ;
     RECT  14.004 10.399 50.994 10.463 ;
     RECT  14.112 10.463 50.994 10.471 ;
     RECT  53.388 10.291 53.406 10.471 ;
     RECT  14.112 10.471 51.174 10.493 ;
     RECT  53.388 10.471 53.442 10.541 ;
     RECT  1.836 10.399 13.266 10.589 ;
     RECT  14.94 10.493 51.174 10.589 ;
     RECT  53.388 10.541 53.406 10.589 ;
     RECT  51.156 10.589 51.174 10.733 ;
     RECT  1.872 10.589 13.266 10.925 ;
     RECT  4.248 10.925 13.266 11.281 ;
     RECT  14.112 10.493 14.13 11.479 ;
     RECT  4.248 11.281 13.338 11.515 ;
     RECT  14.076 11.479 14.13 11.515 ;
     RECT  0.255 10.319 1.098 11.551 ;
     RECT  1.872 10.925 3.33 11.705 ;
     RECT  4.248 11.515 14.13 11.713 ;
     RECT  0.255 11.551 1.134 11.785 ;
     RECT  4.248 11.713 14.166 11.821 ;
     RECT  14.94 10.589 49.95 11.821 ;
     RECT  2.052 11.705 3.33 12.119 ;
     RECT  2.052 12.119 3.222 12.209 ;
     RECT  0.255 11.785 1.314 12.523 ;
     RECT  2.052 12.209 3.186 12.523 ;
     RECT  0.255 12.523 3.186 12.659 ;
     RECT  4.248 11.821 49.95 12.821 ;
     RECT  21.42 12.821 49.95 12.865 ;
     RECT  21.42 12.865 50.166 12.901 ;
     RECT  4.248 12.821 20.61 12.929 ;
     RECT  4.248 12.929 20.466 13.019 ;
     RECT  21.42 12.901 50.67 13.019 ;
     RECT  0.255 12.659 2.898 13.037 ;
     RECT  4.248 13.019 20.394 13.091 ;
     RECT  21.42 13.019 50.166 13.163 ;
     RECT  14.148 13.091 20.394 13.289 ;
     RECT  1.44 13.037 2.898 13.603 ;
     RECT  1.44 13.603 3.51 13.711 ;
     RECT  4.248 13.091 13.23 13.711 ;
     RECT  59.655 0.793 59.937 13.711 ;
     RECT  59.655 13.711 60.498 13.829 ;
     RECT  21.42 13.163 39.15 13.945 ;
     RECT  39.888 13.163 49.95 13.945 ;
     RECT  59.655 13.829 59.937 13.945 ;
     RECT  14.94 13.289 20.394 13.981 ;
     RECT  21.42 13.945 49.95 13.981 ;
     RECT  59.544 13.945 59.937 13.997 ;
     RECT  0.255 13.037 0.537 14.215 ;
     RECT  1.44 13.711 13.23 14.215 ;
     RECT  14.94 13.981 49.95 14.405 ;
     RECT  0.255 14.215 13.23 14.449 ;
     RECT  14.148 13.289 14.166 14.449 ;
     RECT  0.255 14.449 14.166 14.485 ;
     RECT  15.3 14.405 49.95 14.485 ;
     RECT  15.3 14.485 50.274 14.521 ;
     RECT  0.255 14.485 14.526 14.639 ;
     RECT  15.3 14.521 50.67 14.639 ;
     RECT  15.3 14.639 25.974 14.747 ;
     RECT  1.728 14.639 14.526 14.783 ;
     RECT  15.3 14.747 20.466 14.783 ;
     RECT  1.728 14.783 14.418 14.819 ;
     RECT  26.712 14.639 50.67 14.915 ;
     RECT  43.056 14.915 50.67 14.917 ;
     RECT  51.408 14.443 51.426 14.917 ;
     RECT  1.728 14.819 3.654 15.017 ;
     RECT  54.255 0.793 54.537 15.025 ;
     RECT  1.764 15.017 3.654 15.053 ;
     RECT  43.056 14.917 51.426 15.061 ;
     RECT  52.452 15.025 52.47 15.061 ;
     RECT  54.18 15.025 54.537 15.061 ;
     RECT  4.572 14.819 14.418 15.179 ;
     RECT  14.004 15.179 14.418 15.215 ;
     RECT  43.056 15.061 53.046 15.215 ;
     RECT  51.48 15.215 53.046 15.223 ;
     RECT  51.48 15.223 53.118 15.331 ;
     RECT  59.655 13.997 59.937 15.331 ;
     RECT  14.004 15.215 14.238 15.359 ;
     RECT  56.16 15.331 56.79 15.389 ;
     RECT  59.655 15.331 61.218 15.448 ;
     RECT  51.48 15.331 53.226 15.449 ;
     RECT  56.304 15.389 56.79 15.457 ;
     RECT  57.636 15.421 57.654 15.457 ;
     RECT  51.588 15.449 53.226 15.491 ;
     RECT  54.18 15.061 55.278 15.529 ;
     RECT  21.204 14.747 25.974 15.565 ;
     RECT  26.712 14.915 42.102 15.565 ;
     RECT  54.108 15.529 55.278 15.581 ;
     RECT  59.655 15.448 61.83 15.601 ;
     RECT  15.3 14.783 20.43 15.691 ;
     RECT  21.204 15.565 42.102 15.691 ;
     RECT  59.655 15.601 62.082 15.719 ;
     RECT  56.304 15.457 57.654 15.827 ;
     RECT  54.18 15.581 55.278 15.835 ;
     RECT  15.3 15.691 42.102 15.871 ;
     RECT  43.056 15.215 50.562 15.871 ;
     RECT  56.952 15.827 57.654 15.871 ;
     RECT  58.788 15.799 58.806 15.871 ;
     RECT  56.952 15.871 58.806 15.899 ;
     RECT  0.255 14.639 0.918 15.961 ;
     RECT  1.872 15.053 3.654 15.961 ;
     RECT  57.06 15.899 58.806 15.989 ;
     RECT  4.572 15.179 13.23 15.997 ;
     RECT  14.004 15.359 14.022 15.997 ;
     RECT  15.3 15.871 50.562 16.025 ;
     RECT  4.572 15.997 14.022 16.033 ;
     RECT  51.804 15.491 53.226 16.069 ;
     RECT  15.3 16.025 49.23 16.097 ;
     RECT  0.255 15.961 3.654 16.231 ;
     RECT  4.5 16.033 14.022 16.231 ;
     RECT  15.732 16.097 49.23 16.259 ;
     RECT  58.5 15.989 58.806 16.301 ;
     RECT  0.255 16.231 14.238 16.303 ;
     RECT  58.752 16.301 58.806 16.411 ;
     RECT  59.655 15.719 61.866 16.411 ;
     RECT  0.255 16.303 14.85 16.529 ;
     RECT  0.255 16.529 14.022 16.541 ;
     RECT  0.255 16.541 0.954 16.637 ;
     RECT  51.804 16.069 53.334 16.673 ;
     RECT  57.06 15.989 57.222 16.681 ;
     RECT  58.752 16.411 61.866 16.807 ;
     RECT  20.988 16.259 49.23 16.915 ;
     RECT  50.076 16.025 50.562 16.915 ;
     RECT  58.752 16.807 62.514 16.951 ;
     RECT  20.988 16.915 50.562 17.069 ;
     RECT  54.18 15.835 55.386 17.069 ;
     RECT  56.88 16.681 57.222 17.149 ;
     RECT  51.84 16.673 53.334 17.185 ;
     RECT  56.7 17.149 57.222 17.185 ;
     RECT  58.752 16.951 62.694 17.185 ;
     RECT  15.732 16.259 20.25 17.221 ;
     RECT  20.988 17.069 49.23 17.221 ;
     RECT  51.84 17.185 53.442 17.221 ;
     RECT  54.18 17.069 55.278 17.221 ;
     RECT  56.7 17.185 57.366 17.221 ;
     RECT  58.536 17.185 62.694 17.221 ;
     RECT  51.84 17.221 55.278 17.249 ;
     RECT  14.832 16.529 14.85 17.347 ;
     RECT  56.16 17.221 62.694 17.411 ;
     RECT  1.692 16.541 14.022 17.491 ;
     RECT  14.832 17.347 14.922 17.491 ;
     RECT  15.732 17.221 49.23 17.491 ;
     RECT  0.255 16.637 0.918 17.581 ;
     RECT  1.692 17.491 49.23 17.581 ;
     RECT  0.255 17.581 49.23 17.645 ;
     RECT  56.196 17.411 62.694 17.645 ;
     RECT  0.255 17.645 14.922 17.651 ;
     RECT  51.84 17.249 55.206 17.653 ;
     RECT  14.904 17.651 14.922 17.681 ;
     RECT  15.912 17.645 49.23 17.681 ;
     RECT  56.34 17.645 62.694 17.717 ;
     RECT  58.68 17.717 62.694 17.725 ;
     RECT  58.68 17.725 62.838 17.761 ;
     RECT  50.076 17.069 50.562 17.851 ;
     RECT  51.588 17.653 55.206 17.879 ;
     RECT  58.68 17.761 63.27 17.959 ;
     RECT  58.68 17.959 63.486 18.031 ;
     RECT  51.732 17.879 55.206 18.059 ;
     RECT  64.476 18.031 64.494 18.149 ;
     RECT  0.255 17.651 13.842 18.185 ;
     RECT  56.34 17.717 57.906 18.221 ;
     RECT  0.255 18.185 11.337 18.419 ;
     RECT  12.096 18.185 13.842 18.527 ;
     RECT  16.02 17.681 49.23 18.565 ;
     RECT  58.68 18.031 63.702 18.571 ;
     RECT  12.096 18.527 13.374 18.689 ;
     RECT  51.732 18.059 55.17 18.725 ;
     RECT  58.68 18.571 64.134 18.725 ;
     RECT  15.768 18.565 49.23 18.769 ;
     RECT  50.076 17.851 50.814 18.769 ;
     RECT  58.68 18.725 63.486 18.797 ;
     RECT  56.448 18.221 57.906 18.805 ;
     RECT  58.68 18.797 62.694 18.805 ;
     RECT  15.768 18.769 50.814 18.959 ;
     RECT  56.448 18.805 62.694 18.995 ;
     RECT  15.768 18.959 49.914 19.103 ;
     RECT  51.948 18.725 55.17 19.111 ;
     RECT  56.448 18.995 59.937 19.111 ;
     RECT  50.796 18.959 50.814 19.139 ;
     RECT  15.768 19.103 49.878 19.192 ;
     RECT  2.304 18.419 11.337 19.201 ;
     RECT  12.096 18.689 13.23 19.201 ;
     RECT  15.444 19.192 49.878 19.201 ;
     RECT  51.948 19.111 59.937 19.471 ;
     RECT  51.876 19.471 59.937 19.499 ;
     RECT  51.876 19.499 54.846 19.507 ;
     RECT  55.692 19.499 58.014 19.535 ;
     RECT  15.156 19.201 49.878 19.651 ;
     RECT  51.588 19.507 54.846 19.651 ;
     RECT  63.468 18.797 63.486 19.741 ;
     RECT  0.255 18.419 1.458 19.777 ;
     RECT  2.304 19.201 13.23 19.777 ;
     RECT  14.472 19.651 49.878 19.805 ;
     RECT  60.984 18.995 62.694 19.813 ;
     RECT  63.468 19.741 63.522 19.813 ;
     RECT  0.255 19.777 13.698 19.841 ;
     RECT  4.176 19.841 13.698 19.921 ;
     RECT  14.472 19.805 49.266 19.921 ;
     RECT  59.076 19.499 59.937 20.047 ;
     RECT  60.984 19.813 63.522 20.047 ;
     RECT  4.176 19.921 49.266 20.147 ;
     RECT  51.3 19.651 54.846 20.147 ;
     RECT  51.3 20.147 52.146 20.219 ;
     RECT  56.124 19.535 58.014 20.281 ;
     RECT  59.076 20.047 63.522 20.317 ;
     RECT  0.255 19.841 3.438 20.345 ;
     RECT  4.176 20.147 13.698 20.345 ;
     RECT  58.932 20.317 63.522 20.381 ;
     RECT  51.3 20.219 52.074 20.425 ;
     RECT  53.028 20.147 54.846 20.461 ;
     RECT  55.872 20.281 58.014 20.461 ;
     RECT  51.12 20.425 52.074 20.477 ;
     RECT  2.196 20.345 3.438 20.651 ;
     RECT  53.028 20.461 58.014 20.695 ;
     RECT  14.436 20.147 49.266 20.849 ;
     RECT  50.148 20.425 50.166 21.005 ;
     RECT  14.436 20.849 46.782 21.029 ;
     RECT  51.336 20.477 52.074 21.091 ;
     RECT  53.028 20.695 58.194 21.091 ;
     RECT  0.255 20.345 1.458 21.127 ;
     RECT  4.284 20.345 13.698 21.127 ;
     RECT  14.436 21.029 39.87 21.127 ;
     RECT  51.336 21.091 58.194 21.127 ;
     RECT  58.932 20.381 63.486 21.127 ;
     RECT  0.216 21.127 1.458 21.271 ;
     RECT  2.196 20.651 3.402 21.271 ;
     RECT  40.644 21.029 46.782 21.299 ;
     RECT  40.824 21.299 46.782 21.395 ;
     RECT  4.284 21.127 39.87 21.425 ;
     RECT  64.476 21.541 64.494 21.659 ;
     RECT  4.284 21.425 13.554 21.677 ;
     RECT  51.336 21.127 63.486 21.677 ;
     RECT  40.932 21.395 46.782 21.775 ;
     RECT  47.556 20.849 49.266 21.775 ;
     RECT  60.696 21.677 63.486 21.775 ;
     RECT  60.696 21.775 63.558 21.811 ;
     RECT  60.696 21.811 63.702 21.929 ;
     RECT  51.336 21.677 59.937 21.971 ;
     RECT  0.216 21.271 3.402 22.009 ;
     RECT  4.284 21.677 13.23 22.009 ;
     RECT  0.216 22.009 13.23 22.061 ;
     RECT  14.436 21.425 39.87 22.171 ;
     RECT  0.255 22.061 13.23 22.199 ;
     RECT  51.336 21.971 58.194 22.219 ;
     RECT  40.932 21.775 49.266 22.307 ;
     RECT  50.76 22.219 58.194 22.343 ;
     RECT  13.968 22.171 39.87 22.351 ;
     RECT  41.148 22.307 49.266 22.441 ;
     RECT  4.824 22.199 13.23 22.459 ;
     RECT  13.968 22.351 40.41 22.459 ;
     RECT  4.824 22.459 40.41 22.505 ;
     RECT  41.148 22.441 49.806 22.585 ;
     RECT  50.76 22.343 58.122 22.585 ;
     RECT  58.968 21.971 59.937 22.621 ;
     RECT  60.696 21.929 63.558 22.621 ;
     RECT  14.328 22.505 40.41 22.649 ;
     RECT  41.148 22.585 58.122 22.739 ;
     RECT  14.4 22.649 40.41 22.811 ;
     RECT  50.76 22.739 58.122 22.811 ;
     RECT  20.016 22.811 40.41 22.847 ;
     RECT  41.148 22.739 49.806 22.883 ;
     RECT  58.968 22.621 63.558 22.981 ;
     RECT  41.148 22.883 49.482 23.009 ;
     RECT  20.16 22.847 40.41 23.089 ;
     RECT  41.148 23.009 49.23 23.089 ;
     RECT  51.84 22.811 58.122 23.125 ;
     RECT  58.968 22.981 63.702 23.125 ;
     RECT  0.255 22.199 3.978 23.161 ;
     RECT  4.824 22.505 13.23 23.161 ;
     RECT  64.656 23.161 64.674 23.279 ;
     RECT  20.16 23.089 49.23 23.351 ;
     RECT  20.16 23.351 40.158 23.423 ;
     RECT  51.84 23.125 63.702 23.431 ;
     RECT  0.255 23.161 13.23 23.515 ;
     RECT  14.4 22.811 19.026 23.515 ;
     RECT  41.076 23.351 49.23 23.549 ;
     RECT  51.84 23.431 63.918 23.549 ;
     RECT  36.036 23.423 40.158 23.621 ;
     RECT  51.84 23.549 63.702 23.657 ;
     RECT  36.036 23.621 40.086 23.819 ;
     RECT  51.84 23.657 58.086 23.819 ;
     RECT  58.896 23.657 63.702 23.819 ;
     RECT  58.896 23.819 63.666 23.855 ;
     RECT  20.16 23.423 35.298 23.863 ;
     RECT  36.036 23.819 40.014 23.927 ;
     RECT  0.255 23.515 19.026 23.935 ;
     RECT  19.944 23.863 35.298 23.935 ;
     RECT  51.84 23.819 57.906 24.125 ;
     RECT  41.076 23.549 49.137 24.197 ;
     RECT  51.84 24.125 56.43 24.205 ;
     RECT  58.896 23.855 61.218 24.395 ;
     RECT  46.764 24.197 49.137 24.469 ;
     RECT  50.04 24.331 50.058 24.469 ;
     RECT  46.764 24.469 50.058 24.475 ;
     RECT  0.255 23.935 35.298 24.503 ;
     RECT  51.66 24.205 56.43 24.601 ;
     RECT  0.255 24.503 13.23 24.629 ;
     RECT  14.112 24.503 35.298 24.629 ;
     RECT  46.764 24.475 50.346 24.629 ;
     RECT  41.076 24.197 46.026 24.737 ;
     RECT  14.112 24.629 14.274 24.809 ;
     RECT  15.12 24.629 35.298 24.899 ;
     RECT  46.764 24.629 50.202 24.935 ;
     RECT  15.66 24.899 35.298 24.943 ;
     RECT  36.036 23.927 39.87 24.943 ;
     RECT  51.228 24.601 56.43 24.971 ;
     RECT  58.968 24.395 61.218 24.979 ;
     RECT  62.208 23.855 63.666 24.979 ;
     RECT  15.66 24.943 39.87 25.043 ;
     RECT  53.28 24.971 56.43 25.051 ;
     RECT  57.168 24.125 57.906 25.051 ;
     RECT  15.66 25.043 35.01 25.085 ;
     RECT  1.656 24.629 13.23 25.169 ;
     RECT  29.952 25.085 35.01 25.205 ;
     RECT  53.28 25.051 57.906 25.205 ;
     RECT  53.568 25.205 57.906 25.24 ;
     RECT  35.748 25.043 39.87 25.249 ;
     RECT  53.568 25.24 57.942 25.277 ;
     RECT  35.748 25.249 40.158 25.439 ;
     RECT  43.344 24.737 46.026 25.519 ;
     RECT  46.764 24.935 49.662 25.519 ;
     RECT  15.66 25.085 29.178 25.547 ;
     RECT  51.228 24.971 52.434 25.591 ;
     RECT  43.344 25.519 49.662 25.675 ;
     RECT  0.255 24.629 0.846 25.681 ;
     RECT  1.656 25.169 7.65 25.681 ;
     RECT  58.968 24.979 63.666 25.681 ;
     RECT  29.952 25.205 34.974 25.781 ;
     RECT  58.86 25.681 63.666 25.781 ;
     RECT  15.66 25.547 28.89 25.789 ;
     RECT  53.568 25.277 57.906 25.817 ;
     RECT  15.588 25.789 28.89 25.825 ;
     RECT  41.076 24.737 42.498 25.825 ;
     RECT  58.86 25.781 63.558 25.825 ;
     RECT  14.112 24.809 14.13 25.861 ;
     RECT  14.976 25.825 28.89 25.861 ;
     RECT  43.344 25.675 50.094 25.861 ;
     RECT  50.94 25.591 52.434 25.861 ;
     RECT  14.112 25.861 28.89 25.889 ;
     RECT  43.344 25.861 52.434 26.023 ;
     RECT  53.568 25.817 55.818 26.023 ;
     RECT  14.112 25.889 20.898 26.051 ;
     RECT  41.04 25.825 42.498 26.131 ;
     RECT  58.788 25.825 63.558 26.249 ;
     RECT  35.748 25.439 39.87 26.257 ;
     RECT  40.824 26.131 42.498 26.257 ;
     RECT  63.288 26.249 63.558 26.285 ;
     RECT  0.255 25.681 7.65 26.293 ;
     RECT  8.424 25.169 13.23 26.293 ;
     RECT  63.396 26.285 63.558 26.321 ;
     RECT  0.255 26.293 13.23 26.393 ;
     RECT  21.636 25.889 28.89 26.401 ;
     RECT  35.748 26.257 42.498 26.401 ;
     RECT  14.832 26.051 20.898 26.519 ;
     RECT  35.748 26.401 42.534 26.599 ;
     RECT  43.344 26.023 55.818 26.599 ;
     RECT  0.255 26.393 10.17 26.663 ;
     RECT  14.832 26.519 17.802 26.663 ;
     RECT  21.636 26.401 29.106 26.663 ;
     RECT  29.952 25.781 34.794 26.671 ;
     RECT  35.748 26.599 55.818 26.671 ;
     RECT  23.724 26.663 29.106 26.699 ;
     RECT  23.724 26.699 28.854 26.717 ;
     RECT  29.952 26.671 55.818 26.731 ;
     RECT  56.664 25.817 57.906 26.731 ;
     RECT  29.952 26.731 57.906 26.761 ;
     RECT  0.255 26.663 1.314 26.789 ;
     RECT  2.124 26.663 10.17 26.789 ;
     RECT  29.916 26.761 57.906 26.861 ;
     RECT  21.636 26.663 22.95 26.897 ;
     RECT  39.852 26.861 57.906 26.969 ;
     RECT  46.476 26.969 57.906 27.031 ;
     RECT  58.788 26.249 62.478 27.031 ;
     RECT  18.576 26.519 20.898 27.059 ;
     RECT  46.476 27.031 62.478 27.059 ;
     RECT  46.476 27.059 49.878 27.167 ;
     RECT  11.052 26.393 13.23 27.211 ;
     RECT  21.672 26.897 22.95 27.239 ;
     RECT  2.34 26.789 10.17 27.307 ;
     RECT  11.052 27.211 13.266 27.307 ;
     RECT  18.576 27.059 20.862 27.329 ;
     RECT  39.852 26.969 45.558 27.329 ;
     RECT  46.476 27.167 49.77 27.329 ;
     RECT  50.724 27.059 62.478 27.329 ;
     RECT  2.34 27.307 13.266 27.337 ;
     RECT  56.664 27.329 62.478 27.365 ;
     RECT  2.34 27.337 13.806 27.373 ;
     RECT  14.832 26.663 17.73 27.373 ;
     RECT  2.34 27.373 17.73 27.401 ;
     RECT  23.724 26.717 25.83 27.403 ;
     RECT  56.664 27.365 56.682 27.437 ;
     RECT  57.456 27.365 62.478 27.481 ;
     RECT  57.456 27.481 62.622 27.509 ;
     RECT  15.3 27.401 17.73 27.571 ;
     RECT  18.576 27.329 20.718 27.571 ;
     RECT  26.712 26.717 28.854 27.571 ;
     RECT  26.712 27.571 28.962 27.595 ;
     RECT  0.255 26.789 0.846 27.607 ;
     RECT  15.3 27.571 20.718 27.635 ;
     RECT  26.712 27.595 29.178 27.635 ;
     RECT  0.255 27.607 0.918 27.679 ;
     RECT  15.3 27.635 20.61 27.743 ;
     RECT  0.255 27.679 0.99 27.751 ;
     RECT  21.708 27.239 22.95 27.751 ;
     RECT  23.688 27.403 25.83 27.751 ;
     RECT  29.916 26.861 38.862 27.751 ;
     RECT  62.46 27.509 62.622 27.821 ;
     RECT  2.34 27.401 14.562 27.869 ;
     RECT  18.252 27.743 20.61 27.869 ;
     RECT  26.712 27.635 29.142 27.869 ;
     RECT  2.34 27.869 14.418 27.905 ;
     RECT  15.3 27.743 17.478 27.905 ;
     RECT  26.712 27.869 28.962 27.941 ;
     RECT  26.712 27.941 28.638 27.977 ;
     RECT  0.255 27.751 1.566 27.985 ;
     RECT  2.34 27.905 14.238 27.985 ;
     RECT  29.916 27.751 38.934 28.075 ;
     RECT  29.88 28.075 38.934 28.139 ;
     RECT  21.708 27.751 25.83 28.147 ;
     RECT  26.712 27.977 28.602 28.147 ;
     RECT  0.255 27.985 14.238 28.175 ;
     RECT  29.916 28.139 38.934 28.211 ;
     RECT  56.628 28.147 56.646 28.219 ;
     RECT  39.852 27.329 45.486 28.255 ;
     RECT  46.476 27.329 49.734 28.255 ;
     RECT  50.832 27.329 55.602 28.255 ;
     RECT  56.628 28.219 56.682 28.255 ;
     RECT  57.456 27.509 61.578 28.255 ;
     RECT  56.628 28.255 61.578 28.291 ;
     RECT  56.484 28.291 61.578 28.381 ;
     RECT  39.852 28.255 55.602 28.409 ;
     RECT  0.255 28.175 8.91 28.445 ;
     RECT  54.144 28.409 55.602 28.445 ;
     RECT  39.852 28.409 53.226 28.481 ;
     RECT  15.336 27.905 17.478 28.489 ;
     RECT  54.18 28.445 55.602 28.489 ;
     RECT  56.448 28.381 61.578 28.489 ;
     RECT  40.608 28.481 53.226 28.553 ;
     RECT  1.62 28.445 8.91 28.679 ;
     RECT  40.68 28.553 53.226 28.787 ;
     RECT  15.336 28.489 18.09 28.795 ;
     RECT  18.828 27.869 20.61 28.795 ;
     RECT  9.684 28.175 14.238 28.831 ;
     RECT  15.336 28.795 20.61 28.831 ;
     RECT  21.708 28.147 28.602 28.831 ;
     RECT  0.255 28.445 0.882 28.877 ;
     RECT  2.268 28.679 3.582 28.877 ;
     RECT  9.684 28.831 20.61 28.921 ;
     RECT  21.672 28.831 28.602 28.921 ;
     RECT  29.916 28.211 36.018 28.949 ;
     RECT  52.596 28.787 53.226 28.949 ;
     RECT  4.86 28.679 8.082 28.985 ;
     RECT  2.7 28.877 3.582 29.021 ;
     RECT  52.992 28.949 53.226 29.021 ;
     RECT  9.684 28.921 28.602 29.029 ;
     RECT  9.684 29.029 28.962 29.093 ;
     RECT  54.18 28.489 61.578 29.191 ;
     RECT  53.964 29.191 61.578 29.219 ;
     RECT  32.655 28.949 36.018 29.299 ;
     RECT  36.756 28.211 38.934 29.299 ;
     RECT  39.852 28.481 39.87 29.299 ;
     RECT  15.48 29.093 28.962 29.335 ;
     RECT  29.916 28.949 31.914 29.335 ;
     RECT  4.86 28.985 7.614 29.399 ;
     RECT  32.655 29.299 39.87 29.497 ;
     RECT  40.68 28.787 51.786 29.497 ;
     RECT  57.708 29.219 61.578 29.561 ;
     RECT  9.684 29.093 14.67 29.605 ;
     RECT  32.655 29.497 51.786 29.641 ;
     RECT  9.648 29.605 14.67 29.645 ;
     RECT  8.892 28.679 8.91 29.731 ;
     RECT  9.648 29.645 14.274 29.731 ;
     RECT  15.48 29.335 31.914 29.795 ;
     RECT  53.964 29.219 56.574 29.795 ;
     RECT  53.208 29.021 53.226 29.803 ;
     RECT  53.964 29.795 56.502 29.803 ;
     RECT  15.516 29.795 31.914 29.831 ;
     RECT  53.208 29.803 56.502 29.831 ;
     RECT  58.968 29.561 61.578 29.839 ;
     RECT  8.892 29.731 14.274 29.875 ;
     RECT  8.82 29.875 14.274 29.911 ;
     RECT  32.655 29.641 51.822 29.911 ;
     RECT  4.86 29.399 7.398 30.001 ;
     RECT  8.712 29.911 14.274 30.029 ;
     RECT  15.516 29.831 16.83 30.029 ;
     RECT  17.64 29.831 31.914 30.029 ;
     RECT  32.655 29.911 52.146 30.029 ;
     RECT  53.208 29.831 56.466 30.029 ;
     RECT  15.516 30.029 15.534 30.065 ;
     RECT  20.484 30.029 28.53 30.065 ;
     RECT  29.268 30.029 31.914 30.065 ;
     RECT  32.655 30.029 41.13 30.065 ;
     RECT  16.272 30.029 16.83 30.074 ;
     RECT  8.712 30.029 14.166 30.101 ;
     RECT  32.655 30.065 41.022 30.101 ;
     RECT  16.308 30.074 16.83 30.125 ;
     RECT  30.384 30.065 31.914 30.137 ;
     RECT  46.296 30.029 52.146 30.137 ;
     RECT  56.448 30.029 56.466 30.137 ;
     RECT  46.476 30.137 52.146 30.145 ;
     RECT  53.208 30.029 55.71 30.145 ;
     RECT  34.992 30.101 41.022 30.209 ;
     RECT  46.476 30.145 55.71 30.209 ;
     RECT  39.852 30.209 41.022 30.299 ;
     RECT  41.868 30.029 45.486 30.299 ;
     RECT  47.88 30.209 55.71 30.299 ;
     RECT  8.712 30.101 14.094 30.307 ;
     RECT  57.708 29.561 57.906 30.307 ;
     RECT  46.476 30.209 47.142 30.335 ;
     RECT  41.868 30.299 45.018 30.371 ;
     RECT  39.852 30.299 39.942 30.407 ;
     RECT  47.88 30.299 52.002 30.407 ;
     RECT  4.752 30.001 7.398 30.415 ;
     RECT  53.964 30.299 55.71 30.416 ;
     RECT  41.904 30.371 45.018 30.443 ;
     RECT  47.88 30.407 50.274 30.443 ;
     RECT  52.74 30.299 52.938 30.443 ;
     RECT  8.568 30.307 14.094 30.451 ;
     RECT  30.492 30.137 31.914 30.451 ;
     RECT  32.655 30.101 34.182 30.451 ;
     RECT  57.456 30.307 58.014 30.451 ;
     RECT  58.968 29.839 61.722 30.451 ;
     RECT  51.192 30.407 52.002 30.461 ;
     RECT  8.532 30.451 14.094 30.569 ;
     RECT  20.484 30.065 28.494 30.569 ;
     RECT  34.992 30.209 38.754 30.569 ;
     RECT  40.824 30.299 41.022 30.569 ;
     RECT  16.455 30.125 16.83 30.577 ;
     RECT  17.64 30.029 19.746 30.577 ;
     RECT  47.88 30.443 50.202 30.605 ;
     RECT  35.82 30.569 37.026 30.641 ;
     RECT  41.904 30.443 43.938 30.641 ;
     RECT  30.492 30.451 34.182 30.677 ;
     RECT  48.276 30.605 50.202 30.701 ;
     RECT  57.456 30.451 61.722 30.721 ;
     RECT  62.46 27.821 62.478 30.721 ;
     RECT  8.568 30.569 14.094 30.749 ;
     RECT  16.455 30.577 19.746 30.749 ;
     RECT  32.364 30.677 34.182 30.749 ;
     RECT  41.004 30.569 41.022 30.749 ;
     RECT  63.54 26.321 63.558 30.811 ;
     RECT  30.492 30.677 31.374 30.839 ;
     RECT  8.568 30.749 13.914 30.875 ;
     RECT  17.964 30.749 19.746 30.875 ;
     RECT  29.268 30.065 29.646 30.883 ;
     RECT  30.492 30.839 31.194 30.883 ;
     RECT  29.268 30.883 31.194 30.955 ;
     RECT  46.476 30.335 46.89 30.955 ;
     RECT  29.196 30.955 31.194 30.983 ;
     RECT  36.648 30.641 37.026 30.983 ;
     RECT  39.852 30.407 39.87 30.983 ;
     RECT  37.008 30.983 37.026 30.989 ;
     RECT  18.432 30.875 19.746 30.991 ;
     RECT  20.484 30.569 28.458 30.991 ;
     RECT  18.432 30.991 28.458 31.109 ;
     RECT  29.196 30.983 30.942 31.109 ;
     RECT  35.82 30.641 35.91 31.109 ;
     RECT  37.8 30.569 38.754 31.109 ;
     RECT  48.276 30.701 49.95 31.109 ;
     RECT  19.188 31.109 28.458 31.145 ;
     RECT  57.456 30.721 62.478 31.153 ;
     RECT  63.468 30.811 63.558 31.153 ;
     RECT  18.432 31.109 18.45 31.181 ;
     RECT  19.188 31.145 19.674 31.181 ;
     RECT  29.232 31.109 30.942 31.181 ;
     RECT  57.456 31.153 63.558 31.189 ;
     RECT  46.224 30.955 46.89 31.225 ;
     RECT  29.232 31.181 30.222 31.229 ;
     RECT  55.296 30.416 55.71 31.261 ;
     RECT  57.168 31.189 63.558 31.261 ;
     RECT  29.52 31.229 30.222 31.289 ;
     RECT  38.055 31.109 38.754 31.289 ;
     RECT  46.188 31.225 46.89 31.339 ;
     RECT  20.664 31.145 28.458 31.379 ;
     RECT  35.892 31.109 35.91 31.379 ;
     RECT  55.26 31.261 63.63 31.379 ;
     RECT  2.7 29.021 3.294 31.387 ;
     RECT  51.192 30.461 51.786 31.387 ;
     RECT  52.92 30.443 52.938 31.387 ;
     RECT  53.964 30.416 54.537 31.387 ;
     RECT  55.26 31.379 63.594 31.387 ;
     RECT  29.52 31.289 30.078 31.415 ;
     RECT  32.364 30.749 33.39 31.423 ;
     RECT  44.928 31.351 44.946 31.423 ;
     RECT  2.556 31.387 3.294 31.424 ;
     RECT  51.192 31.387 52.938 31.459 ;
     RECT  53.964 31.387 63.594 31.459 ;
     RECT  29.52 31.415 29.538 31.487 ;
     RECT  4.68 30.415 7.398 31.495 ;
     RECT  32.328 31.423 33.39 31.495 ;
     RECT  34.488 31.225 34.758 31.495 ;
     RECT  44.928 31.423 45.198 31.495 ;
     RECT  4.104 31.495 7.398 31.525 ;
     RECT  2.7 31.424 3.294 31.531 ;
     RECT  4.032 31.525 7.398 31.531 ;
     RECT  15.588 31.459 15.606 31.531 ;
     RECT  16.455 30.749 16.737 31.531 ;
     RECT  42.192 30.641 43.938 31.531 ;
     RECT  44.676 31.495 45.198 31.531 ;
     RECT  46.152 31.339 46.89 31.531 ;
     RECT  49.932 31.109 49.95 31.531 ;
     RECT  51.192 31.459 63.594 31.531 ;
     RECT  8.568 30.875 13.878 31.579 ;
     RECT  26.892 31.379 27.537 31.649 ;
     RECT  28.296 31.379 28.422 31.649 ;
     RECT  32.328 31.495 34.758 31.649 ;
     RECT  42.192 31.531 45.234 31.649 ;
     RECT  14.976 31.531 16.737 31.657 ;
     RECT  44.928 31.649 45.234 31.657 ;
     RECT  46.152 31.531 46.926 31.657 ;
     RECT  20.664 31.379 26.082 31.661 ;
     RECT  50.796 31.531 63.594 31.685 ;
     RECT  49.932 31.531 50.022 31.693 ;
     RECT  50.796 31.685 60.354 31.693 ;
     RECT  20.664 31.661 25.65 31.721 ;
     RECT  27 31.649 27.537 31.721 ;
     RECT  28.404 31.649 28.422 31.721 ;
     RECT  49.932 31.693 60.354 31.721 ;
     RECT  14.832 31.657 16.737 31.801 ;
     RECT  40.356 31.657 40.374 31.801 ;
     RECT  48.276 31.109 49.137 31.801 ;
     RECT  20.664 31.721 23.922 31.829 ;
     RECT  24.804 31.721 25.65 31.829 ;
     RECT  44.928 31.657 46.926 31.829 ;
     RECT  49.932 31.721 50.886 31.829 ;
     RECT  51.66 31.721 60.354 31.829 ;
     RECT  20.664 31.829 23.742 31.891 ;
     RECT  32.328 31.649 34.038 31.891 ;
     RECT  40.104 31.801 40.374 31.891 ;
     RECT  42.192 31.649 44.154 31.891 ;
     RECT  45.216 31.829 46.926 31.891 ;
     RECT  47.772 31.801 49.137 31.891 ;
     RECT  2.7 31.531 7.398 31.901 ;
     RECT  2.7 31.901 3.114 31.919 ;
     RECT  8.316 31.579 13.878 31.919 ;
     RECT  45.216 31.891 49.137 31.919 ;
     RECT  49.932 31.829 50.814 31.919 ;
     RECT  24.804 31.829 25.434 31.955 ;
     RECT  32.184 31.891 34.038 31.963 ;
     RECT  34.776 31.927 34.794 31.999 ;
     RECT  40.104 31.891 44.154 31.999 ;
     RECT  4.032 31.901 7.398 32.027 ;
     RECT  61.164 31.685 63.594 32.027 ;
     RECT  34.776 31.999 34.866 32.035 ;
     RECT  38.055 31.289 38.337 32.035 ;
     RECT  39.564 31.999 44.154 32.035 ;
     RECT  45.288 31.919 49.137 32.035 ;
     RECT  49.932 31.919 50.49 32.035 ;
     RECT  45.288 32.035 50.49 32.063 ;
     RECT  8.712 31.919 13.878 32.071 ;
     RECT  14.832 31.801 16.794 32.071 ;
     RECT  36.54 31.963 36.558 32.071 ;
     RECT  37.404 32.035 38.337 32.071 ;
     RECT  39.06 32.035 44.154 32.071 ;
     RECT  45.288 32.063 50.166 32.093 ;
     RECT  2.7 31.919 2.97 32.141 ;
     RECT  14.832 32.071 17.406 32.189 ;
     RECT  8.712 32.071 14.094 32.197 ;
     RECT  14.832 32.189 14.85 32.197 ;
     RECT  15.588 32.189 17.406 32.269 ;
     RECT  34.776 32.035 34.938 32.269 ;
     RECT  15.588 32.269 17.946 32.305 ;
     RECT  15.588 32.305 18.558 32.341 ;
     RECT  34.776 32.269 35.622 32.341 ;
     RECT  36.54 32.071 44.154 32.341 ;
     RECT  51.768 31.829 60.354 32.369 ;
     RECT  51.84 32.369 60.354 32.431 ;
     RECT  61.164 32.027 63.558 32.431 ;
     RECT  51.84 32.431 63.558 32.459 ;
     RECT  15.588 32.341 19.098 32.467 ;
     RECT  20.484 31.891 23.742 32.467 ;
     RECT  30.78 32.269 30.798 32.467 ;
     RECT  31.932 31.963 34.038 32.467 ;
     RECT  45.288 32.093 49.137 32.495 ;
     RECT  51.84 32.459 51.858 32.495 ;
     RECT  47.376 32.495 49.137 32.567 ;
     RECT  29.988 32.539 30.006 32.575 ;
     RECT  30.78 32.467 34.038 32.575 ;
     RECT  34.776 32.341 44.154 32.575 ;
     RECT  30.78 32.575 44.154 32.603 ;
     RECT  29.808 32.575 30.006 32.611 ;
     RECT  30.78 32.603 39.69 32.611 ;
     RECT  15.588 32.467 23.742 32.729 ;
     RECT  47.376 32.567 47.394 32.729 ;
     RECT  40.608 32.603 44.154 32.737 ;
     RECT  45.288 32.495 46.206 32.737 ;
     RECT  40.608 32.737 46.206 32.765 ;
     RECT  29.052 32.611 39.69 32.827 ;
     RECT  17.676 32.729 23.742 32.845 ;
     RECT  24.804 31.955 24.822 32.845 ;
     RECT  29.016 32.827 39.69 32.909 ;
     RECT  48.564 32.567 49.137 32.909 ;
     RECT  4.104 32.027 7.398 32.971 ;
     RECT  29.016 32.909 34.686 32.999 ;
     RECT  49.932 32.093 49.95 33.035 ;
     RECT  29.016 32.999 33.102 33.043 ;
     RECT  17.676 32.845 24.822 33.071 ;
     RECT  28.656 33.043 33.102 33.071 ;
     RECT  8.712 32.197 14.85 33.115 ;
     RECT  15.588 32.729 16.737 33.115 ;
     RECT  28.656 33.071 33.066 33.115 ;
     RECT  20.16 33.071 24.822 33.143 ;
     RECT  33.84 32.999 34.686 33.149 ;
     RECT  2.7 32.141 2.934 33.151 ;
     RECT  4.104 32.971 7.578 33.151 ;
     RECT  8.712 33.115 16.737 33.151 ;
     RECT  27.255 31.721 27.537 33.151 ;
     RECT  27.255 33.151 27.594 33.241 ;
     RECT  25.956 33.151 26.226 33.259 ;
     RECT  27.072 33.241 27.594 33.259 ;
     RECT  4.104 33.151 16.737 33.269 ;
     RECT  17.676 33.071 18.99 33.269 ;
     RECT  20.16 33.143 24.102 33.269 ;
     RECT  52.668 32.459 63.558 33.269 ;
     RECT  1.332 31.801 1.35 33.277 ;
     RECT  2.196 33.151 2.97 33.277 ;
     RECT  50.184 33.151 50.526 33.277 ;
     RECT  17.676 33.269 18.558 33.305 ;
     RECT  20.16 33.269 21.114 33.305 ;
     RECT  1.332 33.277 1.386 33.313 ;
     RECT  22.86 33.269 24.102 33.341 ;
     RECT  25.02 33.307 25.038 33.347 ;
     RECT  25.956 33.259 27.594 33.349 ;
     RECT  4.104 33.269 14.166 33.377 ;
     RECT  25.128 33.349 27.594 33.385 ;
     RECT  28.512 33.115 33.066 33.385 ;
     RECT  0.255 28.877 0.537 33.421 ;
     RECT  1.296 33.313 1.386 33.421 ;
     RECT  40.608 32.765 45.594 33.421 ;
     RECT  50.184 33.277 51.03 33.421 ;
     RECT  51.876 33.277 51.894 33.421 ;
     RECT  52.668 33.269 58.23 33.449 ;
     RECT  35.424 32.909 39.69 33.539 ;
     RECT  52.848 33.449 58.23 33.539 ;
     RECT  36.36 33.539 39.69 33.575 ;
     RECT  52.848 33.539 52.938 33.575 ;
     RECT  15.192 33.269 16.737 33.583 ;
     RECT  17.676 33.305 18.27 33.583 ;
     RECT  48.6 32.909 49.137 33.583 ;
     RECT  40.464 33.421 45.594 33.595 ;
     RECT  25.128 33.385 33.066 33.611 ;
     RECT  47.268 33.547 47.286 33.619 ;
     RECT  40.464 33.595 45.666 33.629 ;
     RECT  47.268 33.619 47.502 33.655 ;
     RECT  48.6 33.583 49.446 33.655 ;
     RECT  2.196 33.277 3.294 33.691 ;
     RECT  45.108 33.629 45.666 33.691 ;
     RECT  47.268 33.655 47.682 33.691 ;
     RECT  48.456 33.655 49.446 33.691 ;
     RECT  45.108 33.691 45.99 33.739 ;
     RECT  47.268 33.691 49.446 33.739 ;
     RECT  15.192 33.583 18.27 33.809 ;
     RECT  15.192 33.809 17.226 33.845 ;
     RECT  37.548 33.575 39.69 33.961 ;
     RECT  40.464 33.629 44.154 33.961 ;
     RECT  45.108 33.739 49.446 33.961 ;
     RECT  50.184 33.421 51.894 33.961 ;
     RECT  0.255 33.421 1.458 34.051 ;
     RECT  2.196 33.691 3.366 34.051 ;
     RECT  4.104 33.377 14.058 34.051 ;
     RECT  18.252 33.809 18.27 34.051 ;
     RECT  15.192 33.845 17.082 34.079 ;
     RECT  22.86 33.341 23.886 34.079 ;
     RECT  34.02 33.149 34.686 34.087 ;
     RECT  35.424 33.539 35.622 34.087 ;
     RECT  21.855 33.269 22.137 34.159 ;
     RECT  22.86 34.079 23.814 34.159 ;
     RECT  25.128 33.611 31.086 34.159 ;
     RECT  31.824 33.611 33.066 34.195 ;
     RECT  34.02 34.087 35.622 34.195 ;
     RECT  0.255 34.051 14.058 34.231 ;
     RECT  15.192 34.079 15.21 34.231 ;
     RECT  18.252 34.051 18.666 34.231 ;
     RECT  31.824 34.195 33.102 34.231 ;
     RECT  54.036 33.539 58.23 34.231 ;
     RECT  58.968 33.269 63.558 34.231 ;
     RECT  0.255 34.231 15.21 34.259 ;
     RECT  33.912 34.195 35.622 34.321 ;
     RECT  36.36 33.575 36.738 34.321 ;
     RECT  24.912 34.159 31.086 34.429 ;
     RECT  20.16 33.305 20.682 34.465 ;
     RECT  33.912 34.321 36.738 34.465 ;
     RECT  37.548 33.961 44.154 34.465 ;
     RECT  24.696 34.429 31.086 34.493 ;
     RECT  21.855 34.159 23.814 34.627 ;
     RECT  54.036 34.231 63.558 34.627 ;
     RECT  18.252 34.231 18.846 34.699 ;
     RECT  19.62 34.465 20.682 34.699 ;
     RECT  18.252 34.699 20.682 34.735 ;
     RECT  45.108 33.961 52.11 34.735 ;
     RECT  18.252 34.735 21.078 34.763 ;
     RECT  18.252 34.763 19.458 34.771 ;
     RECT  20.232 34.763 21.078 34.771 ;
     RECT  21.816 34.627 23.814 34.771 ;
     RECT  24.768 34.493 31.086 34.771 ;
     RECT  31.824 34.231 33.174 34.771 ;
     RECT  33.912 34.465 44.154 34.771 ;
     RECT  15.984 34.079 16.737 34.861 ;
     RECT  17.784 34.771 19.458 34.861 ;
     RECT  44.892 34.735 52.11 34.889 ;
     RECT  52.92 33.575 52.938 35.005 ;
     RECT  45 34.889 52.11 35.041 ;
     RECT  52.92 35.005 53.298 35.041 ;
     RECT  54.036 34.627 63.594 35.041 ;
     RECT  20.232 34.771 23.814 35.227 ;
     RECT  24.768 34.771 44.154 35.227 ;
     RECT  8.46 34.259 15.21 35.311 ;
     RECT  15.984 34.861 19.458 35.311 ;
     RECT  20.232 35.227 44.154 35.339 ;
     RECT  8.46 35.311 19.458 35.501 ;
     RECT  0.255 34.259 7.434 35.581 ;
     RECT  8.46 35.501 13.23 35.581 ;
     RECT  45 35.041 63.594 35.581 ;
     RECT  45 35.581 63.882 35.699 ;
     RECT  24.372 35.339 44.154 35.735 ;
     RECT  0.255 35.581 13.23 35.771 ;
     RECT  3.6 35.771 13.23 35.879 ;
     RECT  14.148 35.501 19.458 35.977 ;
     RECT  20.232 35.339 23.49 35.977 ;
     RECT  24.372 35.735 29.79 36.014 ;
     RECT  14.148 35.977 23.49 36.121 ;
     RECT  30.816 35.735 44.154 36.121 ;
     RECT  45 35.699 63.558 36.121 ;
     RECT  14.148 36.121 23.634 36.239 ;
     RECT  24.408 36.014 29.79 36.275 ;
     RECT  24.516 36.275 29.79 36.553 ;
     RECT  30.816 36.121 63.558 36.553 ;
     RECT  4.176 35.879 13.23 36.625 ;
     RECT  14.148 36.239 23.31 36.625 ;
     RECT  24.516 36.553 63.558 36.779 ;
     RECT  4.176 36.625 23.31 36.923 ;
     RECT  4.176 36.923 6.426 36.931 ;
     RECT  0.255 35.771 2.862 37.048 ;
     RECT  7.2 36.923 18.018 37.049 ;
     RECT  18.864 36.923 23.31 37.049 ;
     RECT  24.516 36.779 58.23 37.049 ;
     RECT  0.255 37.048 3.186 37.085 ;
     RECT  4.104 36.931 6.426 37.165 ;
     RECT  19.008 37.049 23.31 37.201 ;
     RECT  24.516 37.049 58.122 37.355 ;
     RECT  50.328 37.355 58.122 37.391 ;
     RECT  7.308 37.049 17.694 37.427 ;
     RECT  50.328 37.391 58.086 37.427 ;
     RECT  19.008 37.201 23.382 37.435 ;
     RECT  24.516 37.355 49.59 37.435 ;
     RECT  50.364 37.427 58.086 37.499 ;
     RECT  0.255 37.085 2.898 37.589 ;
     RECT  7.308 37.427 16.974 37.625 ;
     RECT  19.008 37.435 49.59 37.831 ;
     RECT  3.636 37.165 6.426 37.859 ;
     RECT  3.744 37.859 6.426 37.903 ;
     RECT  7.308 37.625 14.274 37.903 ;
     RECT  18.684 37.831 49.59 37.939 ;
     RECT  18.54 37.939 49.59 37.967 ;
     RECT  18.54 37.967 23.31 37.975 ;
     RECT  18.468 37.975 23.31 38.003 ;
     RECT  18.468 38.003 23.238 38.101 ;
     RECT  18.396 38.101 23.238 38.129 ;
     RECT  18.396 38.129 18.954 38.155 ;
     RECT  50.472 37.499 58.086 38.165 ;
     RECT  24.048 37.967 49.59 38.273 ;
     RECT  15.624 37.625 16.974 38.281 ;
     RECT  18.216 38.155 18.954 38.281 ;
     RECT  19.764 38.129 23.238 38.309 ;
     RECT  34.38 38.273 49.59 38.309 ;
     RECT  50.472 38.165 54.537 38.435 ;
     RECT  34.668 38.309 49.59 38.579 ;
     RECT  55.296 38.165 58.086 38.677 ;
     RECT  58.968 36.779 63.558 38.677 ;
     RECT  15.624 38.281 18.954 38.713 ;
     RECT  24.048 38.273 33.642 38.779 ;
     RECT  3.744 37.903 14.274 38.785 ;
     RECT  15.444 38.713 18.954 38.785 ;
     RECT  19.908 38.309 23.238 38.947 ;
     RECT  23.976 38.779 33.642 38.947 ;
     RECT  3.744 38.785 18.954 39.011 ;
     RECT  55.296 38.677 63.558 39.011 ;
     RECT  15.408 39.011 18.954 39.019 ;
     RECT  50.472 38.435 53.082 39.019 ;
     RECT  50.436 39.019 53.082 39.091 ;
     RECT  19.908 38.947 33.642 39.101 ;
     RECT  19.908 39.101 29.97 39.181 ;
     RECT  0.255 37.589 2.862 39.211 ;
     RECT  58.932 39.011 63.558 39.253 ;
     RECT  58.932 39.253 63.63 39.317 ;
     RECT  15.408 39.019 18.99 39.355 ;
     RECT  19.764 39.181 29.97 39.355 ;
     RECT  0.255 39.211 2.97 39.361 ;
     RECT  3.744 39.011 14.274 39.361 ;
     RECT  50.328 39.091 53.082 39.361 ;
     RECT  53.964 38.435 54.537 39.361 ;
     RECT  55.296 39.011 58.014 39.361 ;
     RECT  15.408 39.355 29.97 39.389 ;
     RECT  34.668 38.579 35.802 39.487 ;
     RECT  36.54 38.579 49.59 39.487 ;
     RECT  0.255 39.361 14.274 39.623 ;
     RECT  34.668 39.487 49.59 39.631 ;
     RECT  50.328 39.361 58.014 39.631 ;
     RECT  30.744 39.101 33.642 39.721 ;
     RECT  19.188 39.389 29.97 39.749 ;
     RECT  58.968 39.317 63.63 39.749 ;
     RECT  19.188 39.749 20.322 39.785 ;
     RECT  30.744 39.721 33.678 39.793 ;
     RECT  34.668 39.631 58.014 39.793 ;
     RECT  15.408 39.389 18.45 39.865 ;
     RECT  0.255 39.623 3.222 39.893 ;
     RECT  21.06 39.749 29.97 40.063 ;
     RECT  30.744 39.793 58.014 40.063 ;
     RECT  15.156 39.865 18.45 40.135 ;
     RECT  19.296 39.785 20.322 40.325 ;
     RECT  4.032 39.623 14.274 40.333 ;
     RECT  15.048 40.135 18.45 40.333 ;
     RECT  4.032 40.333 18.45 40.445 ;
     RECT  21.06 40.063 58.014 40.469 ;
     RECT  59.04 39.749 63.63 40.531 ;
     RECT  59.004 40.531 63.63 40.567 ;
     RECT  21.06 40.469 22.878 40.667 ;
     RECT  21.42 40.667 22.878 40.703 ;
     RECT  24.264 40.469 58.014 40.711 ;
     RECT  58.788 40.567 63.63 40.711 ;
     RECT  2.7 39.893 3.222 40.795 ;
     RECT  21.456 40.703 22.878 40.937 ;
     RECT  2.7 40.795 3.258 40.981 ;
     RECT  4.032 40.445 18.342 40.981 ;
     RECT  21.492 40.937 22.878 41.009 ;
     RECT  0.255 39.893 1.854 41.107 ;
     RECT  2.7 40.981 18.342 41.107 ;
     RECT  0.255 41.107 18.342 41.135 ;
     RECT  16.128 41.135 18.342 41.215 ;
     RECT  24.264 40.711 63.63 41.215 ;
     RECT  19.404 40.325 20.322 41.341 ;
     RECT  24.012 41.215 63.63 41.369 ;
     RECT  24.012 41.369 55.386 41.377 ;
     RECT  16.128 41.215 18.486 41.485 ;
     RECT  19.404 41.341 20.538 41.485 ;
     RECT  23.904 41.377 55.386 41.521 ;
     RECT  0.255 41.135 14.922 41.639 ;
     RECT  56.34 41.369 63.63 41.711 ;
     RECT  21.492 41.009 22.842 41.719 ;
     RECT  23.832 41.521 55.386 41.755 ;
     RECT  16.128 41.485 20.538 41.881 ;
     RECT  21.276 41.719 22.842 41.881 ;
     RECT  23.652 41.755 55.386 41.881 ;
     RECT  16.128 41.881 55.386 41.953 ;
     RECT  0.255 41.639 14.85 41.981 ;
     RECT  16.02 41.953 55.386 42.331 ;
     RECT  56.34 41.711 62.838 42.331 ;
     RECT  16.02 42.331 62.838 42.493 ;
     RECT  63.612 41.711 63.63 42.493 ;
     RECT  16.02 42.493 63.63 42.557 ;
     RECT  57.312 42.557 63.63 42.719 ;
     RECT  16.02 42.557 56.502 42.799 ;
     RECT  0.255 41.981 1.638 42.871 ;
     RECT  2.628 41.981 14.85 42.871 ;
     RECT  0.255 42.871 14.85 42.989 ;
     RECT  57.312 42.719 63.558 42.989 ;
     RECT  15.984 42.799 56.502 43.169 ;
     RECT  15.984 43.169 41.778 43.295 ;
     RECT  57.312 42.989 63.486 43.295 ;
     RECT  42.516 43.169 56.502 43.411 ;
     RECT  57.312 43.295 62.01 43.411 ;
     RECT  15.984 43.295 41.742 43.799 ;
     RECT  42.516 43.411 62.01 43.835 ;
     RECT  0.255 42.989 1.746 43.951 ;
     RECT  2.628 42.989 14.85 43.951 ;
     RECT  15.984 43.799 30.978 43.951 ;
     RECT  0.255 43.951 30.978 43.979 ;
     RECT  0.255 43.979 4.518 44.105 ;
     RECT  0.255 44.105 1.746 44.177 ;
     RECT  5.508 43.979 30.978 44.249 ;
     RECT  5.508 44.249 15.03 44.339 ;
     RECT  0.255 44.177 1.602 44.375 ;
     RECT  58.356 43.835 62.01 44.384 ;
     RECT  15.984 44.249 30.978 44.581 ;
     RECT  31.716 43.799 41.742 44.581 ;
     RECT  58.608 44.384 62.01 44.581 ;
     RECT  62.748 43.295 63.486 44.581 ;
     RECT  5.508 44.339 14.958 44.609 ;
     RECT  58.608 44.581 63.486 44.617 ;
     RECT  15.984 44.581 41.742 44.653 ;
     RECT  42.516 43.835 57.582 44.653 ;
     RECT  5.508 44.609 7.11 44.813 ;
     RECT  58.608 44.617 63.666 44.879 ;
     RECT  5.508 44.813 7.074 44.951 ;
     RECT  15.984 44.653 57.582 44.987 ;
     RECT  5.508 44.951 7.038 44.995 ;
     RECT  61.956 44.879 63.666 44.995 ;
     RECT  5.4 44.995 7.038 45.031 ;
     RECT  56.196 44.987 57.582 45.031 ;
     RECT  61.956 44.995 63.738 45.059 ;
     RECT  0.255 44.375 1.53 45.193 ;
     RECT  2.52 44.105 4.518 45.193 ;
     RECT  15.984 44.987 55.278 45.221 ;
     RECT  61.992 45.059 63.738 45.221 ;
     RECT  0.255 45.193 1.674 45.265 ;
     RECT  2.484 45.193 4.518 45.265 ;
     RECT  0.255 45.265 4.59 45.301 ;
     RECT  5.364 45.031 7.038 45.301 ;
     RECT  56.196 45.031 57.798 45.301 ;
     RECT  58.608 44.879 61.218 45.301 ;
     RECT  62.784 45.221 63.738 45.419 ;
     RECT  0.255 45.301 7.038 45.527 ;
     RECT  16.02 45.221 55.278 45.527 ;
     RECT  1.512 45.527 7.038 45.581 ;
     RECT  2.376 45.581 7.038 45.599 ;
     RECT  56.196 45.301 61.218 45.689 ;
     RECT  61.992 45.221 62.01 45.689 ;
     RECT  7.884 44.609 14.958 45.805 ;
     RECT  16.056 45.527 55.278 45.833 ;
     RECT  58.5 45.689 60.966 45.833 ;
     RECT  62.784 45.419 62.802 45.833 ;
     RECT  18.108 45.833 55.278 45.835 ;
     RECT  56.196 45.689 57.582 45.835 ;
     RECT  3.996 45.599 7.038 45.841 ;
     RECT  7.848 45.805 14.958 45.841 ;
     RECT  18.108 45.835 57.582 45.869 ;
     RECT  1.512 45.581 1.602 45.959 ;
     RECT  2.376 45.599 3.078 45.959 ;
     RECT  3.996 45.841 14.958 45.959 ;
     RECT  1.512 45.959 1.53 45.995 ;
     RECT  7.848 45.959 14.958 46.157 ;
     RECT  8.172 46.157 14.958 46.201 ;
     RECT  58.5 45.833 60.894 46.229 ;
     RECT  58.5 46.229 58.518 46.265 ;
     RECT  8.172 46.201 15.102 46.499 ;
     RECT  2.736 45.959 3.078 46.615 ;
     RECT  3.996 45.959 6.858 46.615 ;
     RECT  2.736 46.615 6.858 46.741 ;
     RECT  2.628 46.741 6.858 46.747 ;
     RECT  18.108 45.869 56.898 46.747 ;
     RECT  8.172 46.499 15.03 46.769 ;
     RECT  16.056 45.833 17.37 46.805 ;
     RECT  8.172 46.769 14.778 46.829 ;
     RECT  2.304 46.747 6.858 46.849 ;
     RECT  2.304 46.849 7.326 46.921 ;
     RECT  59.655 46.229 60.894 46.949 ;
     RECT  18.108 46.747 57.33 47.147 ;
     RECT  18.108 47.147 55.674 47.165 ;
     RECT  18.108 47.165 55.602 47.183 ;
     RECT  2.304 46.921 7.398 47.219 ;
     RECT  3.888 47.219 7.398 47.281 ;
     RECT  8.172 46.829 11.502 47.281 ;
     RECT  16.092 46.805 17.37 47.281 ;
     RECT  18.108 47.183 55.278 47.281 ;
     RECT  16.092 47.281 55.278 47.309 ;
     RECT  58.608 47.155 58.626 47.309 ;
     RECT  56.7 47.147 57.33 47.353 ;
     RECT  58.14 47.317 58.194 47.353 ;
     RECT  3.888 47.281 11.502 47.885 ;
     RECT  16.092 47.309 21.078 47.893 ;
     RECT  2.304 47.219 3.078 48.001 ;
     RECT  3.888 47.885 4.302 48.001 ;
     RECT  5.292 47.885 11.502 48.001 ;
     RECT  12.492 46.829 14.778 48.001 ;
     RECT  56.7 47.353 58.194 48.119 ;
     RECT  2.304 48.001 4.302 48.155 ;
     RECT  16.02 47.893 21.078 48.199 ;
     RECT  56.7 48.119 57.834 48.263 ;
     RECT  5.292 48.001 14.778 48.271 ;
     RECT  15.84 48.199 21.078 48.271 ;
     RECT  5.292 48.271 21.078 48.299 ;
     RECT  5.292 48.299 20.826 48.389 ;
     RECT  57.744 48.263 57.834 48.389 ;
     RECT  5.292 48.389 14.778 48.461 ;
     RECT  15.84 48.389 20.826 48.461 ;
     RECT  21.855 47.309 55.278 48.505 ;
     RECT  56.196 48.271 56.61 48.505 ;
     RECT  2.628 48.155 4.302 48.659 ;
     RECT  57.816 48.389 57.834 48.839 ;
     RECT  21.855 48.505 56.61 48.929 ;
     RECT  2.628 48.659 3.114 48.965 ;
     RECT  21.855 48.929 56.25 48.965 ;
     RECT  2.736 48.965 3.114 49.073 ;
     RECT  21.855 48.965 56.214 49.243 ;
     RECT  15.84 48.461 19.782 49.351 ;
     RECT  20.808 48.461 20.826 49.351 ;
     RECT  5.292 48.461 11.502 49.421 ;
     RECT  2.952 49.073 3.114 49.435 ;
     RECT  3.888 48.659 4.302 49.435 ;
     RECT  2.952 49.435 4.302 49.469 ;
     RECT  21.708 49.243 56.214 49.469 ;
     RECT  3.6 49.469 4.302 49.505 ;
     RECT  15.84 49.351 20.826 49.579 ;
     RECT  12.528 48.461 14.778 49.585 ;
     RECT  15.552 49.579 20.826 49.585 ;
     RECT  24.768 49.469 55.17 49.613 ;
     RECT  4.032 49.505 4.302 49.739 ;
     RECT  12.528 49.585 20.826 49.813 ;
     RECT  21.708 49.469 23.958 49.819 ;
     RECT  12.384 49.813 20.826 49.855 ;
     RECT  4.032 49.739 4.05 49.883 ;
     RECT  12.24 49.855 20.826 49.883 ;
     RECT  12.24 49.883 17.334 49.919 ;
     RECT  15.552 49.919 17.334 49.949 ;
     RECT  18.108 49.883 20.826 50.017 ;
     RECT  21.564 49.819 23.958 50.017 ;
     RECT  5.544 49.421 11.502 50.125 ;
     RECT  12.24 49.919 14.778 50.125 ;
     RECT  56.196 49.469 56.214 50.161 ;
     RECT  15.552 49.949 17.226 50.351 ;
     RECT  56.196 50.161 56.754 50.395 ;
     RECT  57.852 50.161 57.87 50.395 ;
     RECT  24.768 49.613 52.974 50.431 ;
     RECT  53.712 49.613 55.17 50.431 ;
     RECT  56.196 50.395 57.87 50.431 ;
     RECT  15.552 50.351 15.642 50.549 ;
     RECT  5.544 50.125 14.778 50.584 ;
     RECT  5.364 50.584 14.778 50.665 ;
     RECT  18.108 50.017 23.958 50.665 ;
     RECT  24.768 50.431 57.87 50.665 ;
     RECT  15.552 50.549 15.57 50.693 ;
     RECT  18.108 50.665 57.87 50.693 ;
     RECT  18.108 50.693 56.898 50.729 ;
     RECT  5.184 50.665 14.778 50.819 ;
     RECT  18.108 50.729 52.974 50.891 ;
     RECT  5.184 50.819 6.642 50.923 ;
     RECT  7.416 50.819 14.778 50.927 ;
     RECT  4.896 50.923 6.642 50.963 ;
     RECT  18.108 50.891 19.782 50.971 ;
     RECT  4.104 51.019 4.122 51.089 ;
     RECT  7.416 50.927 14.238 51.089 ;
     RECT  20.808 50.891 52.974 51.101 ;
     RECT  20.808 51.101 20.826 51.125 ;
     RECT  16.455 50.351 17.226 51.133 ;
     RECT  17.964 50.971 19.782 51.133 ;
     RECT  53.712 50.729 56.898 51.161 ;
     RECT  4.968 50.963 6.642 51.269 ;
     RECT  7.416 51.089 10.242 51.359 ;
     RECT  11.055 51.089 13.662 51.359 ;
     RECT  7.416 51.359 9.666 51.395 ;
     RECT  57.852 50.693 57.87 51.439 ;
     RECT  13.212 51.359 13.662 51.467 ;
     RECT  53.712 51.161 54.594 51.503 ;
     RECT  57.708 51.439 57.87 51.511 ;
     RECT  13.212 51.467 13.41 51.539 ;
     RECT  13.284 51.539 13.41 51.629 ;
     RECT  7.416 51.395 9.018 51.665 ;
     RECT  8.928 51.665 9.018 51.737 ;
     RECT  7.416 51.665 8.118 51.773 ;
     RECT  8.928 51.737 8.946 51.773 ;
     RECT  11.055 51.359 11.934 51.773 ;
     RECT  13.392 51.629 13.41 51.773 ;
     RECT  16.455 51.133 19.782 51.781 ;
     RECT  55.872 51.161 56.898 51.781 ;
     RECT  57.708 51.511 58.194 51.781 ;
     RECT  8.1 51.773 8.118 51.809 ;
     RECT  16.344 51.781 19.782 51.871 ;
     RECT  16.344 51.871 20.034 51.931 ;
     RECT  20.844 51.931 20.862 51.943 ;
     RECT  21.6 51.101 52.974 51.943 ;
     RECT  16.164 51.931 20.07 51.971 ;
     RECT  20.844 51.943 52.974 52.015 ;
     RECT  16.455 51.971 20.07 52.043 ;
     RECT  20.808 52.015 52.974 52.051 ;
     RECT  16.455 52.043 19.962 52.169 ;
     RECT  20.736 52.051 52.974 52.169 ;
     RECT  55.872 51.781 58.194 52.321 ;
     RECT  20.808 52.169 52.974 52.439 ;
     RECT  55.872 52.321 58.23 52.439 ;
     RECT  53.712 51.503 54.537 52.447 ;
     RECT  55.872 52.439 58.122 52.447 ;
     RECT  53.712 52.447 58.122 52.511 ;
     RECT  16.455 52.169 19.818 52.583 ;
     RECT  53.712 52.511 57.978 52.709 ;
     RECT  53.712 52.709 57.654 52.745 ;
     RECT  53.712 52.745 57.582 52.817 ;
     RECT  20.88 52.439 52.974 53.087 ;
     RECT  53.748 52.817 57.582 53.123 ;
     RECT  53.748 53.123 54.537 53.249 ;
     RECT  55.296 53.123 57.582 53.249 ;
     RECT  21.132 53.087 52.974 53.635 ;
     RECT  58.644 53.671 58.662 53.789 ;
     RECT  55.404 53.249 57.582 53.797 ;
     RECT  21.132 53.635 53.118 53.825 ;
     RECT  16.455 52.583 19.782 54.067 ;
     RECT  25.704 53.825 53.118 54.067 ;
     RECT  54 53.249 54.537 54.067 ;
     RECT  55.404 53.797 58.266 54.095 ;
     RECT  55.404 54.095 58.014 54.139 ;
     RECT  25.704 54.067 54.537 54.211 ;
     RECT  55.296 54.139 58.014 54.211 ;
     RECT  25.704 54.211 58.014 54.329 ;
     RECT  21.132 53.825 24.894 54.413 ;
     RECT  21.492 54.413 24.894 55.219 ;
     RECT  16.416 54.067 19.782 55.243 ;
     RECT  16.344 55.243 19.782 55.283 ;
     RECT  25.704 54.329 57.582 55.291 ;
     RECT  21.456 55.219 24.894 55.381 ;
     RECT  25.632 55.291 57.582 55.381 ;
     RECT  21.456 55.381 57.582 55.417 ;
     RECT  21.384 55.417 57.582 55.525 ;
     RECT  16.455 55.283 19.782 55.751 ;
     RECT  16.455 55.751 17.118 55.823 ;
     RECT  21.132 55.525 57.582 55.831 ;
     RECT  21.096 55.831 57.582 55.915 ;
     RECT  20.628 55.915 57.582 55.921 ;
     RECT  20.628 55.921 58.122 56.065 ;
     RECT  20.628 56.065 58.554 56.129 ;
     RECT  37.08 56.129 58.554 56.219 ;
     RECT  37.08 56.219 58.446 56.291 ;
     RECT  20.628 56.129 36.306 56.327 ;
     RECT  55.332 56.291 58.446 56.363 ;
     RECT  59.655 46.949 60.354 56.363 ;
     RECT  20.916 56.327 35.082 56.399 ;
     RECT  55.476 56.363 57.798 56.489 ;
     RECT  56.448 56.489 57.798 56.759 ;
     RECT  37.08 56.291 54.537 56.795 ;
     RECT  18.144 55.751 19.782 56.839 ;
     RECT  21.096 56.399 35.082 56.867 ;
     RECT  36.18 56.327 36.306 57.073 ;
     RECT  37.08 56.795 52.938 57.073 ;
     RECT  18.144 56.839 19.962 57.101 ;
     RECT  18.144 57.101 18.162 57.173 ;
     RECT  55.476 56.489 55.674 57.307 ;
     RECT  56.448 56.759 56.538 57.307 ;
     RECT  36.108 57.073 52.938 57.407 ;
     RECT  36.18 57.407 52.938 57.437 ;
     RECT  21.096 56.867 27.702 57.541 ;
     RECT  55.476 57.307 56.538 57.541 ;
     RECT  36.216 57.437 52.938 57.577 ;
     RECT  53.676 56.795 54.537 57.577 ;
     RECT  55.26 57.541 56.538 57.685 ;
     RECT  57.348 56.759 57.474 57.685 ;
     RECT  55.26 57.685 57.474 57.749 ;
     RECT  36.216 57.577 54.537 57.787 ;
     RECT  55.26 57.749 57.438 57.787 ;
     RECT  21.06 57.541 27.702 57.839 ;
     RECT  36.216 57.787 57.438 57.839 ;
     RECT  28.44 56.867 35.082 57.883 ;
     RECT  21.06 57.839 27.537 57.983 ;
     RECT  19.116 57.101 19.962 57.991 ;
     RECT  28.26 57.883 35.082 57.991 ;
     RECT  28.26 57.991 35.226 58.019 ;
     RECT  19.116 57.991 20.466 58.109 ;
     RECT  21.24 57.983 27.537 58.145 ;
     RECT  36.216 57.839 57.114 58.145 ;
     RECT  36.216 58.145 55.494 58.157 ;
     RECT  56.268 58.145 57.114 58.181 ;
     RECT  36.216 58.157 55.098 58.189 ;
     RECT  28.44 58.019 35.226 58.217 ;
     RECT  30.312 58.217 35.226 58.253 ;
     RECT  33.804 58.253 35.226 58.261 ;
     RECT  36.144 58.189 55.098 58.379 ;
     RECT  56.268 58.181 56.502 58.415 ;
     RECT  33.804 58.261 35.298 58.459 ;
     RECT  36.144 58.379 53.406 58.459 ;
     RECT  54.255 58.379 55.098 58.487 ;
     RECT  56.484 58.415 56.502 58.487 ;
     RECT  33.804 58.459 53.406 58.523 ;
     RECT  33.804 58.523 52.938 58.793 ;
     RECT  28.44 58.217 29.538 58.891 ;
     RECT  30.312 58.253 33.066 59.029 ;
     RECT  33.804 58.793 52.866 59.029 ;
     RECT  28.404 58.891 29.538 59.035 ;
     RECT  28.26 59.035 29.538 59.071 ;
     RECT  30.312 59.029 52.866 59.071 ;
     RECT  28.26 59.071 52.866 59.099 ;
     RECT  21.312 58.145 27.537 59.161 ;
     RECT  28.26 59.099 35.082 59.161 ;
     RECT  19.116 58.109 20.394 59.269 ;
     RECT  21.312 59.161 35.082 59.269 ;
     RECT  54.255 58.487 54.537 59.275 ;
     RECT  19.116 59.269 35.082 59.297 ;
     RECT  20.7 59.297 35.082 59.603 ;
     RECT  35.964 59.099 52.866 59.611 ;
     RECT  35.964 59.611 53.37 59.729 ;
     RECT  54.144 59.275 54.537 59.729 ;
     RECT  20.7 59.603 23.274 59.765 ;
     RECT  20.7 59.765 23.13 59.837 ;
     RECT  24.012 59.603 35.082 59.845 ;
     RECT  54.255 59.729 54.537 59.851 ;
     RECT  24.012 59.845 35.19 59.881 ;
     RECT  35.964 59.729 52.974 59.881 ;
     RECT  54.255 59.851 54.738 59.999 ;
     RECT  24.012 59.881 52.974 60.035 ;
     RECT  21.168 59.837 23.13 60.275 ;
     RECT  21.672 60.275 23.13 60.575 ;
     RECT  21.708 60.575 23.13 60.655 ;
     RECT  21.708 60.655 23.274 60.781 ;
     RECT  24.012 60.035 52.902 60.781 ;
     RECT  21.708 60.781 52.902 61.079 ;
     RECT  24.228 61.079 52.902 61.231 ;
     RECT  21.708 61.079 23.454 61.349 ;
     RECT  24.228 61.231 53.01 61.349 ;
     RECT  30.312 61.349 42.426 61.385 ;
     RECT  30.492 61.385 42.426 61.421 ;
     RECT  40.788 61.421 42.426 61.493 ;
     RECT  43.308 61.349 53.01 61.529 ;
     RECT  43.308 61.529 52.794 61.655 ;
     RECT  19.116 59.297 19.818 61.763 ;
     RECT  30.492 61.421 40.014 61.889 ;
     RECT  41.076 61.493 42.426 61.889 ;
     RECT  30.492 61.889 36.81 61.925 ;
     RECT  36.324 61.925 36.81 61.961 ;
     RECT  30.492 61.925 35.478 62.159 ;
     RECT  21.708 61.349 22.842 62.167 ;
     RECT  24.228 61.349 29.574 62.195 ;
     RECT  36.36 61.961 36.81 62.195 ;
     RECT  41.508 61.889 42.426 62.203 ;
     RECT  43.308 61.655 52.542 62.203 ;
     RECT  21.672 62.167 22.842 62.311 ;
     RECT  25.452 62.195 29.574 62.311 ;
     RECT  21.096 62.311 23.346 62.395 ;
     RECT  24.228 62.195 24.57 62.429 ;
     RECT  20.952 62.395 23.346 62.435 ;
     RECT  21.672 62.435 23.346 62.465 ;
     RECT  21.708 62.465 23.346 62.501 ;
     RECT  32.544 62.159 35.478 62.501 ;
     RECT  21.855 62.501 23.346 62.581 ;
     RECT  21.855 62.581 23.85 62.669 ;
     RECT  19.116 61.763 19.566 62.699 ;
     RECT  21.855 62.669 23.778 62.699 ;
     RECT  41.508 62.203 52.542 62.699 ;
     RECT  25.452 62.311 29.718 62.707 ;
     RECT  30.492 62.159 31.626 62.707 ;
     RECT  41.508 62.699 50.238 62.731 ;
     RECT  41.4 62.731 50.238 62.78 ;
     RECT  41.436 62.78 50.238 62.861 ;
     RECT  41.436 62.861 50.022 62.879 ;
     RECT  22.86 62.699 23.094 62.969 ;
     RECT  41.436 62.879 49.95 62.969 ;
     RECT  32.616 62.501 35.478 62.971 ;
     RECT  47.304 62.969 48.042 63.005 ;
     RECT  22.932 62.969 23.094 63.041 ;
     RECT  41.436 62.969 46.17 63.053 ;
     RECT  32.616 62.971 35.586 63.085 ;
     RECT  36.36 62.195 36.486 63.085 ;
     RECT  32.616 63.085 36.486 63.113 ;
     RECT  35.1 63.113 36.486 63.121 ;
     RECT  37.692 61.889 40.014 63.121 ;
     RECT  41.508 63.053 46.17 63.149 ;
     RECT  25.452 62.707 31.626 63.239 ;
     RECT  41.508 63.149 44.478 63.239 ;
     RECT  45.216 63.149 45.99 63.239 ;
     RECT  47.304 63.005 47.322 63.239 ;
     RECT  48.78 62.969 49.95 63.239 ;
     RECT  51.264 62.699 52.542 63.239 ;
     RECT  32.616 63.113 34.326 63.247 ;
     RECT  45.972 63.239 45.99 63.275 ;
     RECT  48.78 63.239 49.806 63.275 ;
     RECT  51.264 63.239 52.074 63.311 ;
     RECT  25.452 63.239 25.47 63.347 ;
     RECT  26.244 63.239 30.294 63.347 ;
     RECT  51.912 63.311 52.074 63.347 ;
     RECT  27.255 63.347 30.294 63.383 ;
     RECT  41.508 63.239 41.526 63.383 ;
     RECT  42.408 63.239 44.298 63.383 ;
     RECT  27.255 63.383 28.962 63.419 ;
     RECT  31.068 63.239 31.626 63.481 ;
     RECT  32.4 63.247 34.326 63.481 ;
     RECT  26.244 63.347 26.442 63.509 ;
     RECT  28.944 63.419 28.962 63.509 ;
     RECT  29.952 63.383 30.294 63.509 ;
     RECT  35.1 63.121 40.41 63.509 ;
     RECT  42.408 63.383 42.462 63.509 ;
     RECT  48.855 63.275 49.806 63.509 ;
     RECT  52.056 63.347 52.074 63.509 ;
     RECT  22.932 63.041 23.058 63.581 ;
     RECT  30.276 63.509 30.294 63.581 ;
     RECT  36.036 63.509 36.594 63.581 ;
     RECT  42.444 63.509 42.462 63.581 ;
     RECT  43.452 63.383 44.298 63.581 ;
     RECT  27.255 63.419 27.918 63.617 ;
     RECT  22.932 63.581 22.95 63.653 ;
     RECT  19.548 62.699 19.566 63.689 ;
     RECT  36.468 63.581 36.594 63.689 ;
     RECT  37.476 63.509 39.906 63.689 ;
     RECT  23.904 63.625 23.922 63.779 ;
     RECT  31.068 63.481 34.326 63.779 ;
     RECT  36.468 63.689 36.558 63.815 ;
     RECT  38.055 63.689 39.906 63.815 ;
     RECT  36.54 63.815 36.558 63.851 ;
     RECT  38.055 63.815 39.186 63.887 ;
     RECT  38.055 63.887 38.97 63.923 ;
     RECT  0.255 45.527 0.537 64.007 ;
     RECT  5.655 51.269 5.937 64.007 ;
     RECT  11.055 51.773 11.337 64.007 ;
     RECT  16.455 55.823 16.737 64.007 ;
     RECT  21.855 62.699 22.137 64.007 ;
     RECT  27.255 63.617 27.537 64.007 ;
     RECT  38.055 63.923 38.337 64.007 ;
     RECT  43.455 63.581 43.737 64.007 ;
     RECT  48.855 63.509 49.137 64.007 ;
     RECT  54.255 59.999 54.537 64.007 ;
     RECT  59.655 56.363 59.937 64.007 ;
     RECT  31.068 63.779 33.93 64.049 ;
     RECT  31.068 64.049 33.606 64.121 ;
     RECT  31.068 64.121 33.138 64.205 ;
     RECT  0.255 64.007 0.345 64.277 ;
     RECT  5.655 64.007 5.745 64.277 ;
     RECT  11.055 64.007 11.145 64.277 ;
     RECT  16.455 64.007 16.545 64.277 ;
     RECT  21.855 64.007 21.945 64.277 ;
     RECT  27.255 64.007 27.345 64.277 ;
     RECT  38.055 64.007 38.145 64.277 ;
     RECT  43.455 64.007 43.545 64.277 ;
     RECT  48.855 64.007 48.945 64.277 ;
     RECT  54.255 64.007 54.345 64.277 ;
     RECT  59.655 64.007 59.745 64.277 ;
     RECT  31.608 64.205 33.138 64.319 ;
     RECT  31.608 64.319 31.626 64.391 ;
     RECT  32.436 64.319 33.138 64.397 ;
     RECT  32.616 64.397 33.138 64.445 ;
     RECT  23.796 63.787 23.814 64.685 ;
     RECT  30.78 64.555 30.798 64.685 ;
    LAYER M4 ;
     RECT  0.133 15.984 0.248 16.008 ;
     RECT  0.205 22.032 0.248 22.056 ;
     RECT  0.133 39.744 0.248 39.768 ;
     RECT  0.248 0.528 0.352 64.272 ;
     RECT  0.352 0.798 0.544 64.002 ;
     RECT  0.544 17.616 0.659 18.408 ;
     RECT  0.544 20.16 0.659 22.488 ;
     RECT  0.544 24.336 0.659 24.36 ;
     RECT  0.544 26.208 0.659 28.872 ;
     RECT  0.544 14.256 0.713 14.808 ;
     RECT  0.659 18.384 0.857 18.408 ;
     RECT  0.659 22.464 0.94 22.488 ;
     RECT  0.659 26.208 1.001 27.72 ;
     RECT  0.544 16.32 1.109 16.536 ;
     RECT  0.659 20.16 1.181 21.144 ;
     RECT  1.001 26.208 1.225 26.76 ;
     RECT  0.544 41.76 1.571 42.456 ;
     RECT  1.181 20.16 1.715 20.184 ;
     RECT  1.225 26.208 1.715 26.232 ;
     RECT  1.109 16.32 1.721 16.344 ;
     RECT  1.753 39.552 1.964 39.576 ;
     RECT  0.544 13.008 2.005 13.032 ;
     RECT  2.005 12.528 2.045 13.032 ;
     RECT  1.964 39.552 2.051 39.768 ;
     RECT  0.544 8.4 2.077 8.424 ;
     RECT  0.544 35.328 2.108 35.352 ;
     RECT  2.077 8.4 2.185 8.472 ;
     RECT  1.681 37.056 2.245 37.08 ;
     RECT  2.197 24.24 2.284 24.264 ;
     RECT  2.185 20.832 2.291 20.856 ;
     RECT  2.185 8.208 2.297 8.472 ;
     RECT  0.659 28.848 2.332 28.872 ;
     RECT  2.245 37.056 2.332 37.464 ;
     RECT  0.544 45.552 2.339 45.576 ;
     RECT  2.293 46.752 2.377 46.776 ;
     RECT  2.051 39.552 2.513 39.72 ;
     RECT  2.293 31.392 2.585 31.416 ;
     RECT  2.54 45.312 2.617 45.336 ;
     RECT  2.045 12.528 2.657 12.84 ;
     RECT  2.108 35.328 2.657 35.544 ;
     RECT  0.713 14.256 2.693 14.28 ;
     RECT  1.681 6.816 2.837 6.84 ;
     RECT  2.78 18.672 2.867 18.696 ;
     RECT  2.761 42.72 2.869 42.744 ;
     RECT  2.869 42.624 2.917 42.744 ;
     RECT  2.657 12.528 2.924 12.552 ;
     RECT  2.869 31.584 2.941 31.608 ;
     RECT  2.861 20.208 2.945 20.232 ;
     RECT  2.924 12.24 2.981 12.552 ;
     RECT  2.981 12.24 3.011 12.264 ;
     RECT  2.917 41.856 3.017 42.744 ;
     RECT  2.905 5.136 3.085 5.16 ;
     RECT  2.917 40.8 3.164 40.824 ;
     RECT  2.332 37.056 3.197 37.08 ;
     RECT  3.049 16.032 3.229 16.056 ;
     RECT  3.164 40.32 3.251 40.824 ;
     RECT  3.251 40.8 3.269 40.824 ;
     RECT  2.725 33.312 3.305 33.336 ;
     RECT  3.017 41.856 3.341 42.648 ;
     RECT  2.869 25.872 3.356 25.896 ;
     RECT  3.356 25.872 3.373 26.472 ;
     RECT  2.297 8.304 3.413 8.472 ;
     RECT  2.905 22.224 3.413 22.248 ;
     RECT  3.085 5.136 3.443 5.208 ;
     RECT  2.941 31.584 3.443 32.136 ;
     RECT  3.341 42.624 3.443 42.648 ;
     RECT  2.617 45.216 3.445 45.336 ;
     RECT  3.373 25.104 3.457 26.472 ;
     RECT  3.349 46.656 3.491 46.68 ;
     RECT  3.229 16.032 3.521 16.296 ;
     RECT  3.443 5.184 3.557 5.208 ;
     RECT  3.493 46.992 3.58 47.016 ;
     RECT  3.443 31.584 3.625 31.896 ;
     RECT  2.941 49.44 3.635 49.464 ;
     RECT  3.521 16.272 3.737 16.296 ;
     RECT  3.413 8.448 3.788 8.472 ;
     RECT  3.788 8.448 3.805 8.904 ;
     RECT  3.797 13.728 3.881 13.752 ;
     RECT  2.657 35.52 3.884 35.544 ;
     RECT  3.805 8.448 3.889 9.096 ;
     RECT  3.445 45.216 3.913 45.576 ;
     RECT  3.805 10.896 3.971 10.92 ;
     RECT  3.553 28.992 3.971 29.016 ;
     RECT  3.884 35.136 3.971 35.544 ;
     RECT  3.889 8.448 3.989 8.472 ;
     RECT  3.925 48.864 4.012 48.888 ;
     RECT  3.457 25.872 4.021 26.472 ;
     RECT  4.021 25.872 4.025 26.808 ;
     RECT  3.625 31.536 4.061 31.896 ;
     RECT  3.98 34.512 4.067 34.776 ;
     RECT  3.913 45.024 4.069 45.576 ;
     RECT  4.061 31.584 4.097 31.896 ;
     RECT  4.025 26.784 4.105 26.808 ;
     RECT  4.069 44.352 4.156 45.576 ;
     RECT  4.076 51.024 4.163 51.048 ;
     RECT  4.085 35.808 4.169 35.832 ;
     RECT  4.156 45.024 4.169 45.576 ;
     RECT  4.117 20.304 4.205 20.328 ;
     RECT  4.165 14.64 4.237 14.664 ;
     RECT  4.229 45.648 4.313 45.672 ;
     RECT  4.412 12.432 4.499 12.456 ;
     RECT  4.237 14.64 4.601 14.808 ;
     RECT  4.549 18.768 4.636 18.792 ;
     RECT  2.877 39.216 4.837 39.24 ;
     RECT  4.7 40.224 4.837 40.248 ;
     RECT  4.652 24.144 5.036 24.168 ;
     RECT  4.885 50.928 5.125 50.952 ;
     RECT  4.273 43.584 5.137 43.848 ;
     RECT  4.837 30 5.145 30.024 ;
     RECT  4.097 31.584 5.269 31.704 ;
     RECT  5.125 50.928 5.269 51.096 ;
     RECT  4.237 7.392 5.389 7.416 ;
     RECT  5.125 8.976 5.389 9 ;
     RECT  4.837 39.216 5.425 40.248 ;
     RECT  5.276 41.616 5.425 41.64 ;
     RECT  5.389 7.392 5.648 9 ;
     RECT  5.221 10.896 5.648 10.92 ;
     RECT  5.276 13.008 5.648 13.032 ;
     RECT  4.601 14.64 5.648 14.664 ;
     RECT  4.777 16.032 5.648 16.056 ;
     RECT  4.597 17.616 5.648 17.64 ;
     RECT  5.209 18.816 5.648 18.84 ;
     RECT  5.605 20.976 5.648 21 ;
     RECT  5.036 24.144 5.648 25.128 ;
     RECT  5.125 26.256 5.648 26.28 ;
     RECT  4.844 27.84 5.648 27.864 ;
     RECT  5.145 29.04 5.648 30.024 ;
     RECT  5.269 31.584 5.648 32.184 ;
     RECT  4.837 33.264 5.648 33.288 ;
     RECT  4.067 34.752 5.648 34.776 ;
     RECT  5.065 36.624 5.648 36.648 ;
     RECT  5.425 39.216 5.648 41.64 ;
     RECT  5.137 43.344 5.648 43.848 ;
     RECT  5.353 45.168 5.648 45.192 ;
     RECT  5.269 49.392 5.648 49.416 ;
     RECT  5.269 50.592 5.648 51.096 ;
     RECT  5.648 0.528 5.752 64.272 ;
     RECT  5.752 0.798 5.944 64.002 ;
     RECT  5.944 41.136 5.969 41.16 ;
     RECT  5.944 14.208 6.005 14.232 ;
     RECT  5.944 6.528 6.077 8.472 ;
     RECT  5.944 10.224 6.083 10.248 ;
     RECT  5.944 17.904 6.083 21 ;
     RECT  5.944 13.104 6.113 13.128 ;
     RECT  5.944 43.824 6.149 46.152 ;
     RECT  6.083 18.816 6.257 21 ;
     RECT  5.944 24.528 6.437 24.552 ;
     RECT  6.257 20.928 6.473 21 ;
     RECT  5.944 29.04 6.473 29.352 ;
     RECT  5.944 26.256 6.515 26.28 ;
     RECT  5.944 11.952 6.545 11.976 ;
     RECT  6.473 20.928 6.545 20.952 ;
     RECT  6.077 6.528 6.563 8.04 ;
     RECT  5.944 47.328 6.563 47.352 ;
     RECT  6.563 7.392 6.581 8.04 ;
     RECT  5.944 5.04 6.653 5.064 ;
     RECT  5.944 31.68 6.653 32.184 ;
     RECT  5.944 34.848 6.689 35.736 ;
     RECT  6.257 18.816 6.761 19.656 ;
     RECT  6.689 34.848 6.761 35.544 ;
     RECT  5.944 36.864 6.803 36.888 ;
     RECT  6.761 19.2 6.851 19.656 ;
     RECT  6.473 29.04 6.851 29.256 ;
     RECT  6.149 44.784 6.869 46.152 ;
     RECT  7.045 40.128 7.081 40.152 ;
     RECT  6.581 8.016 7.085 8.04 ;
     RECT  6.869 44.784 7.121 44.808 ;
     RECT  7.081 39.888 7.132 40.152 ;
     RECT  6.761 35.52 7.193 35.544 ;
     RECT  7.196 41.808 7.283 41.832 ;
     RECT  5.944 33.408 7.333 33.432 ;
     RECT  6.851 19.2 7.427 19.224 ;
     RECT  7.132 39.888 7.445 39.912 ;
     RECT  6.851 29.04 7.585 29.064 ;
     RECT  7.532 10.224 7.619 10.248 ;
     RECT  7.585 28.512 7.625 29.064 ;
     RECT  7.405 41.472 7.661 41.496 ;
     RECT  7.676 49.488 7.763 49.512 ;
     RECT  7.369 47.376 7.841 47.4 ;
     RECT  6.869 46.128 7.877 46.152 ;
     RECT  7.729 43.248 7.955 43.272 ;
     RECT  7.585 20.544 7.957 20.568 ;
     RECT  7.625 28.512 8.057 28.536 ;
     RECT  7.333 33.408 8.057 33.624 ;
     RECT  8.005 9.36 8.092 9.384 ;
     RECT  7.957 36.864 8.093 36.888 ;
     RECT  5.944 38.208 8.093 38.232 ;
     RECT  8.089 6.768 8.173 6.792 ;
     RECT  8.089 8.016 8.173 8.04 ;
     RECT  7.957 18.72 8.233 18.744 ;
     RECT  8.233 18.24 8.273 18.744 ;
     RECT  8.204 11.664 8.291 11.688 ;
     RECT  6.653 31.68 8.305 31.704 ;
     RECT  7.957 19.968 8.339 20.568 ;
     RECT  8.293 21.6 8.38 21.624 ;
     RECT  8.396 41.808 8.483 41.832 ;
     RECT  8.197 23.712 8.485 23.736 ;
     RECT  8.273 18.24 8.531 18.264 ;
     RECT  8.444 19.68 8.531 19.704 ;
     RECT  8.305 31.584 8.531 31.704 ;
     RECT  8.057 33.6 8.533 33.624 ;
     RECT  8.449 34.8 8.533 34.824 ;
     RECT  8.477 27.36 8.561 27.384 ;
     RECT  8.533 33.6 8.579 34.824 ;
     RECT  8.513 26.256 8.597 26.28 ;
     RECT  8.579 33.6 8.633 34.488 ;
     RECT  8.521 6.24 8.636 6.264 ;
     RECT  8.588 10.512 8.675 10.536 ;
     RECT  8.636 5.856 8.723 6.264 ;
     RECT  7.909 45.36 8.773 45.528 ;
     RECT  8.413 51.312 8.809 51.336 ;
     RECT  8.485 23.328 8.813 23.736 ;
     RECT  8.773 45.024 8.869 45.528 ;
     RECT  8.813 23.712 8.885 23.736 ;
     RECT  8.809 50.784 8.893 51.336 ;
     RECT  8.869 44.592 8.957 45.528 ;
     RECT  8.869 46.848 8.981 46.872 ;
     RECT  8.981 46.848 8.993 47.304 ;
     RECT  8.917 30.672 9.029 30.696 ;
     RECT  8.957 45.024 9.065 45.528 ;
     RECT  8.993 47.28 9.065 47.304 ;
     RECT  8.953 14.208 9.107 14.232 ;
     RECT  8.531 31.68 9.137 31.704 ;
     RECT  9.157 49.488 9.245 49.512 ;
     RECT  9.164 43.728 9.251 43.752 ;
     RECT  8.701 41.184 9.452 41.208 ;
     RECT  9.452 41.184 9.539 41.832 ;
     RECT  9.421 43.008 9.589 43.032 ;
     RECT  8.633 34.464 9.677 34.488 ;
     RECT  9.589 42.72 9.677 43.032 ;
     RECT  8.893 51.312 9.677 51.336 ;
     RECT  9.205 37.44 9.683 37.464 ;
     RECT  9.677 43.008 9.683 43.032 ;
     RECT  9.733 17.616 9.817 17.64 ;
     RECT  9.733 31.536 9.82 31.56 ;
     RECT  9.817 17.616 9.821 17.928 ;
     RECT  9.169 47.328 10.069 47.352 ;
     RECT  9.961 50.304 10.073 51.192 ;
     RECT  9.452 45.648 10.177 45.672 ;
     RECT  9.421 39.888 10.357 39.912 ;
     RECT  10.177 45.456 10.405 45.672 ;
     RECT  10.069 46.704 10.405 47.352 ;
     RECT  9.821 17.904 10.453 17.928 ;
     RECT  10.073 50.304 10.453 50.328 ;
     RECT  9.961 20.304 10.501 20.328 ;
     RECT  10.405 45.312 10.508 47.352 ;
     RECT  10.316 4.848 10.597 4.872 ;
     RECT  10.537 22.32 10.609 22.536 ;
     RECT  10.453 50.016 10.609 50.328 ;
     RECT  10.609 22.32 10.652 22.776 ;
     RECT  10.609 49.824 10.717 50.328 ;
     RECT  10.508 45.312 10.741 47.592 ;
     RECT  9.539 41.184 10.753 41.448 ;
     RECT  10.717 49.344 10.789 50.328 ;
     RECT  10.46 8.448 10.825 8.472 ;
     RECT  10.069 11.664 10.825 11.688 ;
     RECT  10.453 13.296 10.825 13.32 ;
     RECT  10.213 32.016 10.933 32.04 ;
     RECT  10.789 49.008 10.933 50.328 ;
     RECT  10.597 4.608 11.048 4.872 ;
     RECT  10.837 6 11.048 6.024 ;
     RECT  10.825 7.68 11.048 8.472 ;
     RECT  10.825 11.664 11.048 14.28 ;
     RECT  9.709 16.224 11.048 16.248 ;
     RECT  10.453 17.904 11.048 18.408 ;
     RECT  10.501 20.16 11.048 20.328 ;
     RECT  10.652 22.176 11.048 22.776 ;
     RECT  10.261 27.312 11.048 27.336 ;
     RECT  10.933 31.2 11.048 32.04 ;
     RECT  10.885 37.44 11.048 37.464 ;
     RECT  10.357 39.888 11.048 40.056 ;
     RECT  10.753 41.136 11.048 41.448 ;
     RECT  10.837 43.296 11.048 43.32 ;
     RECT  10.741 44.688 11.048 47.592 ;
     RECT  10.933 48.768 11.048 50.328 ;
     RECT  11.048 0.528 11.152 64.272 ;
     RECT  11.152 0.798 11.344 64.002 ;
     RECT  11.344 5.616 11.603 5.784 ;
     RECT  11.603 5.76 11.621 5.784 ;
     RECT  11.344 46.128 11.692 46.824 ;
     RECT  11.344 27.408 11.795 27.912 ;
     RECT  11.344 38.208 11.909 38.712 ;
     RECT  11.344 42.672 11.945 42.984 ;
     RECT  11.909 38.688 11.987 38.712 ;
     RECT  11.945 42.864 11.987 42.984 ;
     RECT  11.344 29.664 12.009 29.688 ;
     RECT  11.344 10.704 12.035 11.4 ;
     RECT  11.344 51.36 12.035 51.384 ;
     RECT  11.344 25.968 12.053 26.232 ;
     RECT  11.344 33.216 12.053 33.24 ;
     RECT  11.344 12.528 12.089 12.552 ;
     RECT  11.692 46.8 12.172 46.824 ;
     RECT  11.344 18.528 12.179 18.552 ;
     RECT  11.344 14.688 12.197 14.952 ;
     RECT  11.344 16.032 12.269 16.056 ;
     RECT  11.344 50.208 12.332 50.232 ;
     RECT  12.197 14.688 12.413 14.856 ;
     RECT  12.325 40.272 12.413 40.296 ;
     RECT  12.332 49.824 12.419 50.232 ;
     RECT  11.344 30.816 12.485 30.84 ;
     RECT  12.053 26.208 12.517 26.232 ;
     RECT  11.344 48.432 12.517 48.456 ;
     RECT  11.344 21.408 12.557 22.776 ;
     RECT  12.517 26.208 12.563 26.808 ;
     RECT  12.517 48.432 12.563 49.032 ;
     RECT  12.413 14.832 12.593 14.856 ;
     RECT  12.409 16.224 12.593 16.296 ;
     RECT  12.557 21.408 12.701 22.344 ;
     RECT  12.757 7.92 12.844 7.944 ;
     RECT  11.344 44.736 12.845 44.76 ;
     RECT  11.344 24.144 12.988 24.168 ;
     RECT  12.593 16.272 12.997 16.296 ;
     RECT  12.419 50.016 13.013 50.232 ;
     RECT  12.563 26.784 13.025 26.808 ;
     RECT  12.332 36.384 13.091 36.408 ;
     RECT  13.013 50.016 13.097 50.808 ;
     RECT  12.035 11.376 13.133 11.4 ;
     RECT  12.985 33.552 13.133 33.576 ;
     RECT  11.987 42.864 13.141 42.888 ;
     RECT  13.085 5.616 13.169 5.64 ;
     RECT  13.141 42.432 13.228 42.984 ;
     RECT  13.228 42.96 13.313 42.984 ;
     RECT  13.237 10.752 13.321 10.776 ;
     RECT  13.237 12.096 13.324 12.552 ;
     RECT  13.333 38.16 13.42 38.184 ;
     RECT  12.563 49.008 13.525 49.032 ;
     RECT  12.701 21.408 13.565 21.672 ;
     RECT  13.525 48.192 13.573 49.032 ;
     RECT  13.525 14.88 13.612 14.904 ;
     RECT  13.093 30.864 13.621 30.888 ;
     RECT  13.573 47.808 13.66 49.032 ;
     RECT  13.309 7.344 13.667 7.368 ;
     RECT  13.58 27.408 13.667 27.432 ;
     RECT  13.565 21.648 13.669 21.672 ;
     RECT  13.621 30.576 13.708 30.888 ;
     RECT  13.097 50.016 13.709 50.04 ;
     RECT  13.669 21.648 13.715 22.488 ;
     RECT  13.669 23.52 13.781 23.544 ;
     RECT  13.717 32.016 13.804 32.184 ;
     RECT  12.997 16.272 13.813 16.536 ;
     RECT  13.715 22.464 13.817 22.488 ;
     RECT  13.777 38.736 13.889 38.76 ;
     RECT  13.324 12.528 13.925 12.552 ;
     RECT  13.813 16.272 14.033 16.632 ;
     RECT  13.708 30.864 14.051 30.888 ;
     RECT  14.021 36.96 14.105 36.984 ;
     RECT  14.101 45.168 14.188 45.192 ;
     RECT  14.156 3.6 14.243 3.624 ;
     RECT  13.66 48.192 14.243 49.032 ;
     RECT  14.243 48.96 14.249 49.032 ;
     RECT  14.197 44.352 14.284 44.376 ;
     RECT  14.249 49.008 14.321 49.032 ;
     RECT  14.245 36.48 14.332 36.504 ;
     RECT  14.293 17.616 14.38 17.64 ;
     RECT  14.348 27.84 14.435 27.864 ;
     RECT  14.485 46.8 14.572 46.824 ;
     RECT  14.629 10.464 14.716 10.488 ;
     RECT  14.605 23.952 14.819 23.976 ;
     RECT  14.569 42.24 14.819 42.264 ;
     RECT  14.713 43.824 14.819 43.848 ;
     RECT  13.804 32.016 14.861 32.04 ;
     RECT  14.869 26.016 14.893 26.04 ;
     RECT  14.893 26.016 14.956 26.232 ;
     RECT  14.965 46.464 15.148 46.488 ;
     RECT  14.749 11.952 15.185 11.976 ;
     RECT  14.317 40.416 15.185 40.44 ;
     RECT  14.857 3.408 15.253 3.432 ;
     RECT  15.253 1.152 15.325 1.176 ;
     RECT  15.253 3.312 15.34 3.432 ;
     RECT  14.821 27.744 15.365 27.768 ;
     RECT  15.145 19.296 15.395 19.32 ;
     RECT  15.325 1.152 15.397 1.224 ;
     RECT  14.629 29.616 15.397 29.64 ;
     RECT  14.033 16.272 15.469 16.296 ;
     RECT  14.956 26.208 15.541 26.232 ;
     RECT  15.397 49.968 15.541 49.992 ;
     RECT  15.397 14.256 15.577 14.616 ;
     RECT  15.469 15.84 15.577 16.296 ;
     RECT  15.433 19.2 15.74 19.224 ;
     RECT  15.541 49.584 15.829 49.992 ;
     RECT  15.397 29.616 15.973 29.688 ;
     RECT  15.34 3.408 16.045 3.432 ;
     RECT  14.785 20.448 16.045 20.472 ;
     RECT  16.076 48.432 16.117 48.456 ;
     RECT  15.829 49.584 16.117 50.04 ;
     RECT  16.165 43.2 16.22 43.224 ;
     RECT  15.884 10.56 16.225 10.584 ;
     RECT  16.117 51.936 16.309 51.96 ;
     RECT  15.397 0.192 16.381 1.992 ;
     RECT  16.381 0.288 16.405 1.992 ;
     RECT  16.045 3.408 16.405 3.576 ;
     RECT  15.397 21.744 16.405 21.768 ;
     RECT  16.405 0.288 16.448 3.576 ;
     RECT  15.644 8.832 16.448 8.856 ;
     RECT  16.225 10.56 16.448 10.824 ;
     RECT  16.213 12.48 16.448 12.504 ;
     RECT  15.577 14.256 16.448 16.296 ;
     RECT  15.74 18.576 16.448 19.224 ;
     RECT  16.045 20.208 16.448 20.472 ;
     RECT  16.405 21.744 16.448 22.584 ;
     RECT  15.649 24.72 16.448 24.744 ;
     RECT  15.541 26.208 16.448 26.52 ;
     RECT  15.721 27.696 16.448 27.72 ;
     RECT  15.973 29.616 16.448 30.12 ;
     RECT  16.028 31.968 16.448 31.992 ;
     RECT  15.685 39.312 16.448 39.336 ;
     RECT  16.22 41.424 16.448 41.448 ;
     RECT  16.22 42.432 16.448 43.224 ;
     RECT  16.309 46.32 16.448 46.344 ;
     RECT  16.117 47.904 16.448 50.04 ;
     RECT  16.309 51.36 16.448 51.96 ;
     RECT  16.309 53.232 16.448 53.256 ;
     RECT  16.333 55.248 16.448 55.272 ;
     RECT  16.448 0.288 16.552 64.272 ;
     RECT  16.552 0.288 16.744 64.002 ;
     RECT  16.744 0.288 16.883 1.416 ;
     RECT  16.744 40.56 16.883 44.328 ;
     RECT  16.744 45.36 16.883 45.384 ;
     RECT  16.744 46.608 16.883 47.832 ;
     RECT  16.883 1.152 17.021 1.416 ;
     RECT  16.744 4.224 17.021 4.488 ;
     RECT  16.883 42.096 17.075 44.328 ;
     RECT  16.744 48.96 17.075 50.04 ;
     RECT  16.744 36 17.093 36.024 ;
     RECT  16.744 29.232 17.123 29.256 ;
     RECT  16.744 32.112 17.123 32.232 ;
     RECT  16.883 40.56 17.123 40.584 ;
     RECT  17.075 49.824 17.123 50.04 ;
     RECT  16.744 30.72 17.129 30.744 ;
     RECT  17.075 42.096 17.164 44.136 ;
     RECT  16.744 51.36 17.164 51.672 ;
     RECT  16.744 24.72 17.201 28.248 ;
     RECT  17.123 32.112 17.212 32.136 ;
     RECT  17.021 1.392 17.315 1.416 ;
     RECT  17.201 24.72 17.345 27.432 ;
     RECT  17.164 42.768 17.363 44.136 ;
     RECT  17.123 49.92 17.363 50.04 ;
     RECT  16.883 47.472 17.459 47.832 ;
     RECT  16.744 13.728 17.507 16.296 ;
     RECT  17.345 26.592 17.596 27.432 ;
     RECT  17.021 4.224 17.603 4.248 ;
     RECT  16.744 8.784 17.651 8.808 ;
     RECT  17.596 27.408 17.741 27.432 ;
     RECT  17.363 42.768 17.795 43.32 ;
     RECT  16.744 2.496 17.804 2.904 ;
     RECT  17.459 47.664 17.804 47.832 ;
     RECT  16.744 6.864 17.845 6.888 ;
     RECT  17.345 24.72 17.849 24.744 ;
     RECT  17.507 14.208 17.881 16.296 ;
     RECT  17.804 2.496 17.891 3.96 ;
     RECT  17.804 47.664 17.891 48.12 ;
     RECT  16.744 10.512 17.917 10.872 ;
     RECT  17.845 6.864 18.035 7.464 ;
     RECT  17.891 47.664 18.035 47.832 ;
     RECT  17.164 51.36 18.037 51.384 ;
     RECT  17.891 2.496 18.137 2.52 ;
     RECT  17.881 14.208 18.169 16.344 ;
     RECT  18.092 5.088 18.179 5.112 ;
     RECT  18.035 7.44 18.179 7.464 ;
     RECT  17.363 50.016 18.181 50.04 ;
     RECT  18.037 51.12 18.181 51.384 ;
     RECT  18.025 28.992 18.227 29.016 ;
     RECT  16.744 21.744 18.229 21.768 ;
     RECT  18.181 50.016 18.236 51.384 ;
     RECT  18.035 47.808 18.245 47.832 ;
     RECT  18.169 14.208 18.253 17.16 ;
     RECT  18.236 50.016 18.268 51.816 ;
     RECT  18.229 12.816 18.316 12.84 ;
     RECT  18.229 21.744 18.317 22.488 ;
     RECT  18.268 50.016 18.323 50.088 ;
     RECT  18.268 51.12 18.323 51.816 ;
     RECT  17.917 10.416 18.421 10.872 ;
     RECT  16.744 19.296 18.421 19.8 ;
     RECT  18.373 5.184 18.46 5.64 ;
     RECT  18.373 30.912 18.461 30.936 ;
     RECT  18.373 40.416 18.461 40.44 ;
     RECT  18.317 21.744 18.541 21.768 ;
     RECT  18.476 1.392 18.563 1.416 ;
     RECT  18.097 24.672 18.565 24.696 ;
     RECT  16.744 53.04 18.565 53.592 ;
     RECT  18.493 45.648 18.577 45.672 ;
     RECT  18.565 24.048 18.601 24.696 ;
     RECT  18.601 23.568 18.652 24.696 ;
     RECT  18.565 52.752 18.652 53.592 ;
     RECT  18.253 14.208 18.659 16.632 ;
     RECT  18.241 27.648 18.707 27.864 ;
     RECT  18.421 10.416 18.713 11.256 ;
     RECT  18.659 14.208 18.716 16.536 ;
     RECT  18.716 14.16 18.803 16.536 ;
     RECT  18.652 23.568 18.803 23.592 ;
     RECT  18.707 27.84 18.803 27.864 ;
     RECT  18.716 34.752 18.803 34.776 ;
     RECT  18.277 36.192 18.803 36.216 ;
     RECT  17.795 43.056 18.803 43.08 ;
     RECT  18.323 51.12 18.803 51.144 ;
     RECT  18.652 53.568 18.865 53.592 ;
     RECT  18.805 44.064 18.893 44.088 ;
     RECT  16.744 38.16 18.929 39 ;
     RECT  18.949 25.008 19.036 25.032 ;
     RECT  18.949 32.832 19.036 32.856 ;
     RECT  18.46 5.184 19.187 5.208 ;
     RECT  19.1 38.016 19.187 38.04 ;
     RECT  19.133 39.36 19.217 39.384 ;
     RECT  19.237 18.144 19.285 18.168 ;
     RECT  19.285 18 19.324 18.168 ;
     RECT  19.237 29.232 19.325 29.256 ;
     RECT  18.713 11.136 19.331 11.256 ;
     RECT  19.177 31.152 19.379 31.176 ;
     RECT  18.323 50.064 19.397 50.088 ;
     RECT  19.321 53.664 19.405 53.784 ;
     RECT  19.405 53.664 19.42 53.688 ;
     RECT  18.421 19.296 19.433 19.944 ;
     RECT  19.349 26.016 19.433 26.04 ;
     RECT  19.429 5.616 19.513 5.64 ;
     RECT  19.381 11.424 19.541 11.448 ;
     RECT  17.891 3.936 19.573 3.96 ;
     RECT  19.324 18 19.613 18.024 ;
     RECT  19.628 28.992 19.715 29.016 ;
     RECT  18.373 41.712 19.772 41.736 ;
     RECT  19.753 26.88 19.789 27.336 ;
     RECT  18.803 14.208 19.793 16.536 ;
     RECT  19.765 52.176 19.852 52.2 ;
     RECT  19.772 43.2 19.859 43.224 ;
     RECT  19.765 46.896 19.897 46.92 ;
     RECT  19.573 2.064 19.957 2.088 ;
     RECT  19.573 3.936 19.964 4.392 ;
     RECT  19.897 46.032 19.981 46.92 ;
     RECT  19.681 6.816 20.005 6.84 ;
     RECT  19.964 3.456 20.051 4.392 ;
     RECT  20.051 4.176 20.081 4.392 ;
     RECT  20.005 6.816 20.092 7.176 ;
     RECT  19.249 21.12 20.153 21.48 ;
     RECT  19.957 48.144 20.153 48.168 ;
     RECT  20.149 12.768 20.236 12.792 ;
     RECT  20.197 34.944 20.284 34.968 ;
     RECT  19.957 1.44 20.297 2.088 ;
     RECT  19.789 26.88 20.333 27.432 ;
     RECT  20.252 22.992 20.339 23.016 ;
     RECT  19.772 41.712 20.341 42.168 ;
     RECT  20.341 41.52 20.365 42.168 ;
     RECT  20.293 38.544 20.38 38.568 ;
     RECT  20.365 41.52 20.428 42.792 ;
     RECT  20.153 21.36 20.441 21.48 ;
     RECT  20.444 25.776 20.531 25.8 ;
     RECT  19.793 14.496 20.533 16.536 ;
     RECT  20.441 21.456 20.549 21.48 ;
     RECT  20.297 2.016 20.581 2.088 ;
     RECT  20.401 11.472 20.621 11.496 ;
     RECT  20.113 50.64 20.627 50.664 ;
     RECT  20.725 9.456 20.773 9.48 ;
     RECT  19.433 19.296 20.797 19.8 ;
     RECT  20.773 9.456 20.86 9.576 ;
     RECT  20.773 46.992 20.86 47.304 ;
     RECT  20.924 29.424 20.972 29.448 ;
     RECT  20.965 31.104 21.049 31.128 ;
     RECT  20.293 44.64 21.049 44.664 ;
     RECT  20.041 51.936 21.049 51.96 ;
     RECT  20.092 6.816 21.109 6.84 ;
     RECT  20.689 59.808 21.116 59.832 ;
     RECT  21.109 6.096 21.121 6.84 ;
     RECT  20.588 55.92 21.121 55.944 ;
     RECT  19.465 57.072 21.121 57.096 ;
     RECT  21.121 55.92 21.373 57.096 ;
     RECT  21.373 55.68 21.404 57.096 ;
     RECT  21.109 54.384 21.481 54.408 ;
     RECT  21.049 51.072 21.548 51.96 ;
     RECT  21.116 59.808 21.548 60.264 ;
     RECT  20.081 4.176 21.589 4.344 ;
     RECT  21.404 55.488 21.589 57.096 ;
     RECT  21.589 55.488 21.596 57.864 ;
     RECT  21.301 40.128 21.637 40.152 ;
     RECT  21.625 53.136 21.637 53.16 ;
     RECT  21.481 54.144 21.637 54.408 ;
     RECT  21.121 10.944 21.661 10.968 ;
     RECT  20.732 50.016 21.661 50.04 ;
     RECT  21.548 51.072 21.661 52.056 ;
     RECT  21.661 10.944 21.685 11.16 ;
     RECT  21.596 55.44 21.685 57.864 ;
     RECT  21.548 59.232 21.685 60.264 ;
     RECT  20.581 2.016 21.733 2.28 ;
     RECT  21.121 6 21.733 6.84 ;
     RECT  20.86 9.456 21.733 9.48 ;
     RECT  21.301 25.104 21.733 25.128 ;
     RECT  20.333 27.408 21.733 27.432 ;
     RECT  21.637 40.128 21.733 40.584 ;
     RECT  20.428 41.904 21.733 42.792 ;
     RECT  21.013 46.752 21.733 46.776 ;
     RECT  21.661 50.016 21.733 52.056 ;
     RECT  21.685 55.44 21.733 60.6 ;
     RECT  20.924 62.4 21.733 62.424 ;
     RECT  21.733 6 21.769 7.416 ;
     RECT  21.769 6 21.841 7.704 ;
     RECT  21.733 1.536 21.848 2.28 ;
     RECT  21.589 3.456 21.848 4.344 ;
     RECT  21.841 5.76 21.848 7.704 ;
     RECT  21.733 8.976 21.848 9.48 ;
     RECT  21.685 10.848 21.848 11.16 ;
     RECT  20.941 12.48 21.848 12.504 ;
     RECT  20.533 14.496 21.848 16.584 ;
     RECT  20.797 19.008 21.848 19.8 ;
     RECT  21.685 22.368 21.848 22.392 ;
     RECT  21.733 24.192 21.848 25.128 ;
     RECT  21.733 26.64 21.848 27.864 ;
     RECT  20.972 28.992 21.848 29.448 ;
     RECT  21.049 30.624 21.848 31.128 ;
     RECT  19.141 36.528 21.848 36.552 ;
     RECT  21.637 39.072 21.848 39.096 ;
     RECT  21.733 40.128 21.848 42.792 ;
     RECT  21.049 44.352 21.848 44.664 ;
     RECT  21.733 46.224 21.848 46.776 ;
     RECT  21.733 48.192 21.848 48.456 ;
     RECT  21.733 49.536 21.848 52.056 ;
     RECT  21.637 53.136 21.848 54.408 ;
     RECT  21.733 55.44 21.848 60.936 ;
     RECT  21.733 62.16 21.848 62.424 ;
     RECT  21.848 0.528 21.952 64.272 ;
     RECT  21.952 0.798 22.144 64.002 ;
     RECT  22.144 24.864 22.169 26.664 ;
     RECT  22.144 56.064 22.205 57.672 ;
     RECT  22.144 5.184 22.241 7.416 ;
     RECT  22.144 41.904 22.241 41.928 ;
     RECT  22.205 57.168 22.241 57.672 ;
     RECT  22.144 27.648 22.259 27.912 ;
     RECT  22.144 59.616 22.277 61.128 ;
     RECT  22.259 27.888 22.403 27.912 ;
     RECT  22.144 8.976 22.421 9.816 ;
     RECT  22.144 46.224 22.421 46.68 ;
     RECT  22.144 28.992 22.444 30.504 ;
     RECT  22.144 34.944 22.492 35.88 ;
     RECT  22.144 13.536 22.529 17.016 ;
     RECT  22.144 62.4 22.529 62.664 ;
     RECT  22.144 19.2 22.565 20.616 ;
     RECT  22.565 20.592 22.637 20.616 ;
     RECT  22.169 24.864 22.637 26.136 ;
     RECT  22.144 38.016 22.643 38.04 ;
     RECT  22.144 48 22.787 50.712 ;
     RECT  22.277 59.616 22.787 59.64 ;
     RECT  22.277 60.768 22.787 61.128 ;
     RECT  22.529 14.208 22.789 17.016 ;
     RECT  22.637 24.864 22.825 25.08 ;
     RECT  22.144 2.016 22.853 3.96 ;
     RECT  22.444 28.992 22.876 30.168 ;
     RECT  22.876 28.992 22.883 29.064 ;
     RECT  22.637 26.112 22.931 26.136 ;
     RECT  22.144 23.616 22.979 23.64 ;
     RECT  22.787 48 22.997 49.848 ;
     RECT  22.241 5.184 23.027 6.84 ;
     RECT  22.421 46.224 23.033 46.248 ;
     RECT  22.787 60.768 23.171 60.984 ;
     RECT  22.789 14.208 23.213 16.968 ;
     RECT  23.125 59.04 23.213 59.064 ;
     RECT  22.853 3.744 23.249 3.96 ;
     RECT  22.144 22.512 23.281 22.536 ;
     RECT  22.144 44.352 23.285 45 ;
     RECT  23.221 58.896 23.308 58.92 ;
     RECT  22.421 9.072 23.317 9.816 ;
     RECT  23.027 5.184 23.321 6.12 ;
     RECT  23.317 9.072 23.353 9.912 ;
     RECT  23.321 5.328 23.357 6.12 ;
     RECT  23.171 60.864 23.363 60.984 ;
     RECT  22.144 18.144 23.372 18.216 ;
     RECT  23.357 5.808 23.393 6.12 ;
     RECT  23.213 14.448 23.393 16.968 ;
     RECT  22.144 51.84 23.393 52.344 ;
     RECT  23.317 0.192 23.401 0.216 ;
     RECT  23.393 52.32 23.411 52.344 ;
     RECT  22.853 2.016 23.413 2.76 ;
     RECT  23.372 18.096 23.413 18.216 ;
     RECT  22.492 35.856 23.413 35.88 ;
     RECT  22.241 57.168 23.429 57.576 ;
     RECT  23.353 40.416 23.437 40.44 ;
     RECT  23.372 54.864 23.459 54.888 ;
     RECT  23.353 9.072 23.461 10.104 ;
     RECT  23.393 14.688 23.465 16.968 ;
     RECT  23.413 1.152 23.501 2.76 ;
     RECT  23.413 35.856 23.501 36.024 ;
     RECT  22.997 48.768 23.501 49.848 ;
     RECT  22.144 12.144 23.533 12.168 ;
     RECT  23.413 17.952 23.573 18.216 ;
     RECT  23.533 11.568 23.605 12.168 ;
     RECT  23.573 18.096 23.605 18.216 ;
     RECT  22.565 19.2 23.605 19.32 ;
     RECT  23.461 9.072 23.645 10.152 ;
     RECT  23.281 22.512 23.66 22.68 ;
     RECT  23.501 48.864 23.717 49.848 ;
     RECT  23.605 11.568 23.789 12.552 ;
     RECT  23.713 31.92 23.797 31.944 ;
     RECT  23.645 9.792 23.821 10.152 ;
     RECT  22.825 25.056 23.821 25.08 ;
     RECT  23.717 48.864 23.825 49.272 ;
     RECT  22.529 62.64 23.861 62.664 ;
     RECT  23.825 49.104 23.869 49.272 ;
     RECT  23.501 1.728 23.885 2.76 ;
     RECT  23.677 27.408 23.929 27.432 ;
     RECT  22.883 29.04 23.929 29.064 ;
     RECT  22.876 30.144 23.929 30.168 ;
     RECT  23.821 25.056 23.932 25.752 ;
     RECT  23.885 1.728 23.933 2.904 ;
     RECT  23.353 47.616 23.933 47.688 ;
     RECT  23.869 49.248 23.933 49.272 ;
     RECT  23.605 3.984 23.939 4.104 ;
     RECT  23.933 1.824 23.969 2.904 ;
     RECT  23.393 5.808 23.969 6.072 ;
     RECT  23.929 29.04 24.013 30.168 ;
     RECT  23.933 47.616 24.041 47.64 ;
     RECT  23.605 18.096 24.077 19.32 ;
     RECT  23.965 38.784 24.133 38.808 ;
     RECT  23.932 25.056 24.149 25.416 ;
     RECT  24.133 38.016 24.179 38.808 ;
     RECT  24.013 30.144 24.185 30.168 ;
     RECT  22.205 56.064 24.227 56.088 ;
     RECT  23.929 27.408 24.253 27.672 ;
     RECT  23.969 6 24.257 6.072 ;
     RECT  23.363 60.96 24.257 60.984 ;
     RECT  24.085 20.976 24.289 21 ;
     RECT  23.66 22.176 24.289 22.68 ;
     RECT  24.149 25.056 24.365 25.128 ;
     RECT  23.569 35.232 24.421 35.4 ;
     RECT  24.421 34.464 24.467 35.4 ;
     RECT  24.428 51.264 24.469 51.288 ;
     RECT  24.469 51.264 24.515 51.96 ;
     RECT  24.253 27.408 24.517 27.768 ;
     RECT  24.013 29.04 24.517 29.064 ;
     RECT  24.289 20.976 24.541 22.68 ;
     RECT  24.365 25.056 24.545 25.08 ;
     RECT  24.517 26.832 24.545 27.768 ;
     RECT  24.515 51.936 24.553 51.96 ;
     RECT  24.428 61.344 24.553 62.184 ;
     RECT  24.253 59.856 24.563 59.88 ;
     RECT  23.465 14.688 24.613 16.632 ;
     RECT  24.545 26.832 24.617 26.856 ;
     RECT  24.572 39.744 24.659 39.768 ;
     RECT  24.553 61.344 24.659 61.704 ;
     RECT  24.613 14.688 24.661 17.064 ;
     RECT  24.577 36.528 24.661 36.552 ;
     RECT  23.785 58.8 24.689 58.824 ;
     RECT  24.661 14.4 24.7 17.064 ;
     RECT  24.613 60.048 24.7 60.072 ;
     RECT  24.649 43.296 24.716 43.32 ;
     RECT  23.969 1.824 24.725 2.28 ;
     RECT  24.467 34.464 24.725 35.256 ;
     RECT  24.7 14.4 24.748 16.488 ;
     RECT  23.285 44.352 24.757 44.712 ;
     RECT  24.541 20.64 24.796 22.68 ;
     RECT  24.709 26.592 24.796 26.616 ;
     RECT  24.289 31.152 24.901 31.656 ;
     RECT  24.748 14.448 24.905 16.488 ;
     RECT  24.179 38.016 24.956 38.76 ;
     RECT  23.821 9.792 24.973 10.248 ;
     RECT  24.716 43.248 24.973 43.32 ;
     RECT  24.757 44.352 24.973 45.336 ;
     RECT  24.901 30.72 24.985 31.656 ;
     RECT  24.796 22.464 24.988 22.68 ;
     RECT  24.796 20.64 25.013 21.288 ;
     RECT  24.956 37.584 25.043 38.76 ;
     RECT  23.789 12.192 25.045 12.552 ;
     RECT  24.764 50.64 25.045 50.664 ;
     RECT  24.077 18.768 25.052 19.32 ;
     RECT  25.013 20.64 25.052 21.192 ;
     RECT  24.685 39.84 25.081 39.864 ;
     RECT  24.997 33.312 25.084 33.336 ;
     RECT  25.052 18.768 25.085 21.192 ;
     RECT  24.973 9.696 25.093 10.248 ;
     RECT  25.081 39.84 25.117 40.584 ;
     RECT  25.085 18.768 25.139 20.664 ;
     RECT  24.988 22.512 25.148 22.68 ;
     RECT  24.973 43.152 25.225 45.336 ;
     RECT  25.148 22.512 25.235 22.776 ;
     RECT  25.235 22.512 25.265 22.68 ;
     RECT  25.225 42.72 25.333 45.336 ;
     RECT  25.189 46.704 25.333 46.728 ;
     RECT  25.292 8.16 25.379 8.184 ;
     RECT  25.093 9.456 25.381 10.248 ;
     RECT  25.045 11.28 25.381 12.552 ;
     RECT  24.517 6.816 25.388 6.84 ;
     RECT  25.381 9.456 25.405 12.552 ;
     RECT  25.388 5.856 25.427 6.84 ;
     RECT  25.117 39.84 25.436 40.728 ;
     RECT  25.427 5.856 25.475 5.88 ;
     RECT  25.043 38.112 25.481 38.76 ;
     RECT  25.436 39.84 25.523 41.016 ;
     RECT  25.436 63.312 25.523 63.336 ;
     RECT  25.405 9.456 25.619 13.08 ;
     RECT  24.659 61.344 25.621 61.368 ;
     RECT  25.333 42.72 25.657 46.728 ;
     RECT  24.965 53.616 25.657 53.64 ;
     RECT  24.725 35.232 25.661 35.256 ;
     RECT  25.481 38.64 25.667 38.76 ;
     RECT  23.429 57.168 25.669 57.336 ;
     RECT  25.045 49.824 25.676 50.664 ;
     RECT  25.621 61.344 25.693 61.944 ;
     RECT  25.477 24.624 25.697 24.648 ;
     RECT  24.725 2.016 25.717 2.28 ;
     RECT  23.939 4.08 25.717 4.104 ;
     RECT  25.676 49.824 25.763 51 ;
     RECT  25.693 61.344 25.772 63 ;
     RECT  25.717 2.016 25.801 4.488 ;
     RECT  25.657 53.616 25.801 53.736 ;
     RECT  25.801 1.968 25.804 4.488 ;
     RECT  25.441 7.152 25.805 7.656 ;
     RECT  25.265 22.512 25.805 22.536 ;
     RECT  25.081 47.808 25.805 47.832 ;
     RECT  25.523 39.84 25.82 40.776 ;
     RECT  25.772 61.152 25.858 63 ;
     RECT  25.669 56.496 25.859 57.336 ;
     RECT  25.804 3.456 25.877 4.248 ;
     RECT  25.82 39.792 25.877 40.776 ;
     RECT  25.667 38.736 25.907 38.76 ;
     RECT  25.801 53.616 25.909 54.024 ;
     RECT  25.858 61.104 25.955 63 ;
     RECT  25.139 18.768 26.005 19.32 ;
     RECT  25.619 9.456 26.021 12.312 ;
     RECT  25.657 42.72 26.044 46.824 ;
     RECT  25.804 1.968 26.053 2.28 ;
     RECT  26.005 18.528 26.093 19.32 ;
     RECT  24.985 30.816 26.093 31.656 ;
     RECT  24.517 28.8 26.125 29.064 ;
     RECT  26.093 30.816 26.125 31.128 ;
     RECT  26.053 1.68 26.14 2.28 ;
     RECT  26.125 52.416 26.161 52.44 ;
     RECT  25.909 53.52 26.197 54.024 ;
     RECT  26.117 23.952 26.201 23.976 ;
     RECT  26.101 26.688 26.233 26.712 ;
     RECT  25.139 20.4 26.237 20.664 ;
     RECT  25.763 49.824 26.243 50.568 ;
     RECT  26.237 20.64 26.269 20.664 ;
     RECT  26.044 46.752 26.269 46.824 ;
     RECT  26.125 28.512 26.389 29.064 ;
     RECT  26.389 23.76 26.449 23.928 ;
     RECT  26.293 37.44 26.449 37.464 ;
     RECT  26.161 52.224 26.449 52.44 ;
     RECT  26.197 53.52 26.449 54.84 ;
     RECT  26.233 26.352 26.485 26.712 ;
     RECT  26.389 28.464 26.485 29.064 ;
     RECT  25.877 39.792 26.485 40.632 ;
     RECT  25.805 7.152 26.524 7.176 ;
     RECT  26.449 52.224 26.557 54.84 ;
     RECT  26.245 59.76 26.557 59.784 ;
     RECT  26.557 52.224 26.581 55.176 ;
     RECT  25.909 34.848 26.629 34.872 ;
     RECT  26.3 35.904 26.665 35.928 ;
     RECT  26.449 37.104 26.665 37.464 ;
     RECT  26.269 25.2 26.693 25.224 ;
     RECT  26.665 35.904 26.693 37.464 ;
     RECT  26.524 7.104 26.773 7.176 ;
     RECT  24.905 14.448 26.773 15.816 ;
     RECT  26.773 14.16 26.809 15.816 ;
     RECT  26.629 34.128 26.809 34.872 ;
     RECT  26.809 14.16 26.828 16.632 ;
     RECT  26.809 33.84 26.876 34.872 ;
     RECT  26.449 23.664 26.881 23.928 ;
     RECT  26.269 20.64 26.917 21.624 ;
     RECT  26.881 22.656 26.917 23.928 ;
     RECT  26.485 26.304 26.917 26.712 ;
     RECT  25.955 61.92 26.924 63 ;
     RECT  25.859 56.544 26.953 57.336 ;
     RECT  26.14 1.92 27.248 2.28 ;
     RECT  25.877 3.552 27.248 4.248 ;
     RECT  26.773 6.288 27.248 7.176 ;
     RECT  26.021 9.456 27.248 10.104 ;
     RECT  26.021 11.136 27.248 12.312 ;
     RECT  26.828 14.16 27.248 16.824 ;
     RECT  26.093 18.768 27.248 19.32 ;
     RECT  26.917 20.64 27.248 23.928 ;
     RECT  26.693 24.912 27.248 25.224 ;
     RECT  26.917 26.304 27.248 26.76 ;
     RECT  26.485 28.416 27.248 29.064 ;
     RECT  26.125 30.336 27.248 31.128 ;
     RECT  26.876 33.264 27.248 34.872 ;
     RECT  26.693 35.904 27.248 37.608 ;
     RECT  26.485 38.928 27.248 40.632 ;
     RECT  26.593 41.664 27.248 41.688 ;
     RECT  26.044 42.72 27.248 45.336 ;
     RECT  26.269 46.752 27.248 47.736 ;
     RECT  26.243 49.824 27.248 49.848 ;
     RECT  26.581 52.032 27.248 55.176 ;
     RECT  26.953 56.544 27.248 57.912 ;
     RECT  26.557 59.136 27.248 59.784 ;
     RECT  26.924 61.92 27.248 63.336 ;
     RECT  23.785 64.656 27.248 64.68 ;
     RECT  27.248 0.528 27.352 64.68 ;
     RECT  27.352 0.798 27.544 64.68 ;
     RECT  27.544 9.36 27.605 10.584 ;
     RECT  27.544 42.432 27.641 42.744 ;
     RECT  27.544 5.52 27.683 7.704 ;
     RECT  27.544 12.24 27.683 12.264 ;
     RECT  27.544 18.192 27.683 20.616 ;
     RECT  27.544 29.616 27.683 31.512 ;
     RECT  27.544 60.672 27.713 63.24 ;
     RECT  27.544 56.496 27.875 57.912 ;
     RECT  27.544 48.48 27.893 53.016 ;
     RECT  27.544 22.56 27.923 22.776 ;
     RECT  27.544 33.792 27.923 40.632 ;
     RECT  27.875 56.544 27.929 57.912 ;
     RECT  27.683 29.616 27.965 30.888 ;
     RECT  27.544 1.776 28.001 2.28 ;
     RECT  27.713 60.672 28.012 61.032 ;
     RECT  27.923 22.56 28.037 22.584 ;
     RECT  27.965 30.864 28.037 30.888 ;
     RECT  27.893 50.592 28.108 53.016 ;
     RECT  28.012 60.816 28.145 61.032 ;
     RECT  27.923 35.424 28.259 40.632 ;
     RECT  28.108 50.592 28.259 50.616 ;
     RECT  27.544 54.144 28.289 54.6 ;
     RECT  27.544 25.92 28.355 27.672 ;
     RECT  27.713 62.736 28.397 63.24 ;
     RECT  28.355 25.968 28.433 27.672 ;
     RECT  27.923 33.792 28.433 34.152 ;
     RECT  27.683 18.192 28.469 19.896 ;
     RECT  27.683 5.52 28.499 6.84 ;
     RECT  28.259 36.576 28.499 40.632 ;
     RECT  27.544 14.352 28.537 15.816 ;
     RECT  28.108 51.6 28.54 53.016 ;
     RECT  28.001 1.776 28.541 2.232 ;
     RECT  28.433 26.256 28.541 27.672 ;
     RECT  27.965 29.616 28.541 29.64 ;
     RECT  27.893 48.48 28.541 49.272 ;
     RECT  28.145 61.008 28.541 61.032 ;
     RECT  27.544 58.896 28.577 59.256 ;
     RECT  28.549 33.312 28.636 33.336 ;
     RECT  27.544 44.064 28.645 46.392 ;
     RECT  28.259 35.424 28.649 35.448 ;
     RECT  27.641 42.432 28.649 42.648 ;
     RECT  28.541 49.248 28.649 49.272 ;
     RECT  28.649 42.432 28.681 42.552 ;
     RECT  28.577 59.232 28.753 59.256 ;
     RECT  28.54 51.984 28.793 53.016 ;
     RECT  28.541 26.256 28.829 26.28 ;
     RECT  28.541 27.6 28.829 27.672 ;
     RECT  28.499 39.6 28.835 40.632 ;
     RECT  28.645 43.776 28.835 46.392 ;
     RECT  28.835 43.824 28.861 46.392 ;
     RECT  28.499 5.52 28.897 6.792 ;
     RECT  28.835 39.648 28.901 40.632 ;
     RECT  27.544 24.096 28.933 24.12 ;
     RECT  28.537 14.352 28.969 16.152 ;
     RECT  28.499 36.576 28.973 38.184 ;
     RECT  28.753 59.232 28.981 59.352 ;
     RECT  28.897 5.04 29.009 6.792 ;
     RECT  28.861 43.824 29.009 46.728 ;
     RECT  29.009 5.04 29.027 5.496 ;
     RECT  28.988 32.832 29.029 32.856 ;
     RECT  28.469 18.192 29.041 19.32 ;
     RECT  29.009 6.768 29.053 6.792 ;
     RECT  28.981 59.232 29.067 59.784 ;
     RECT  29.029 32.64 29.075 32.856 ;
     RECT  28.541 1.968 29.077 2.232 ;
     RECT  29.041 17.76 29.077 19.32 ;
     RECT  29.009 43.824 29.081 46.392 ;
     RECT  27.605 10.08 29.084 10.584 ;
     RECT  29.084 10.08 29.113 10.92 ;
     RECT  29.075 32.64 29.116 32.664 ;
     RECT  29.067 59.232 29.117 59.832 ;
     RECT  28.609 20.928 29.149 20.952 ;
     RECT  29.117 59.328 29.153 59.832 ;
     RECT  29.077 1.968 29.161 2.328 ;
     RECT  29.077 3.6 29.161 3.624 ;
     RECT  29.113 10.08 29.171 11.16 ;
     RECT  29.153 59.712 29.171 59.832 ;
     RECT  29.171 10.08 29.185 10.152 ;
     RECT  29.077 22.944 29.225 22.968 ;
     RECT  28.933 24.096 29.257 24.36 ;
     RECT  27.929 57.168 29.257 57.912 ;
     RECT  29.173 31.2 29.261 31.224 ;
     RECT  29.257 23.136 29.333 24.36 ;
     RECT  29.269 8.256 29.356 8.28 ;
     RECT  29.171 11.136 29.365 11.16 ;
     RECT  29.257 57.168 29.365 58.104 ;
     RECT  29.149 20.928 29.401 21.048 ;
     RECT  28.969 14.352 29.405 16.248 ;
     RECT  28.901 40.608 29.509 40.632 ;
     RECT  29.401 20.928 29.557 21.192 ;
     RECT  29.077 17.232 29.581 19.32 ;
     RECT  29.365 11.136 29.585 11.256 ;
     RECT  29.333 23.136 29.585 23.352 ;
     RECT  29.185 9.792 29.621 10.152 ;
     RECT  29.545 61.392 29.651 61.416 ;
     RECT  29.621 9.792 29.657 9.912 ;
     RECT  29.657 9.792 29.699 9.816 ;
     RECT  29.509 34.896 29.701 34.92 ;
     RECT  28.681 42.288 29.729 42.552 ;
     RECT  29.585 23.328 29.747 23.352 ;
     RECT  29.66 24.432 29.747 25.08 ;
     RECT  29.747 24.432 29.788 24.456 ;
     RECT  28.973 36.576 29.801 37.992 ;
     RECT  29.801 36.576 29.843 37.08 ;
     RECT  28.397 62.736 29.845 63.096 ;
     RECT  28.829 27.6 29.869 27.624 ;
     RECT  29.653 1.44 29.873 1.464 ;
     RECT  29.081 43.824 29.981 45.816 ;
     RECT  29.977 47.424 30.013 47.448 ;
     RECT  29.701 34.704 30.037 34.92 ;
     RECT  28.793 51.984 30.037 52.872 ;
     RECT  29.585 11.232 30.044 11.256 ;
     RECT  30.037 34.704 30.044 35.16 ;
     RECT  30.037 51.12 30.049 52.872 ;
     RECT  29.845 62.784 30.053 63.096 ;
     RECT  29.545 6.816 30.121 6.84 ;
     RECT  30.053 62.784 30.131 62.856 ;
     RECT  30.049 51.024 30.133 52.872 ;
     RECT  30.044 11.232 30.157 11.736 ;
     RECT  30.013 47.424 30.157 47.64 ;
     RECT  29.981 43.824 30.161 45.768 ;
     RECT  29.171 59.712 30.161 59.736 ;
     RECT  29.843 36.576 30.179 36.984 ;
     RECT  30.044 34.704 30.193 35.496 ;
     RECT  29.833 31.248 30.233 31.272 ;
     RECT  29.869 27.6 30.265 28.104 ;
     RECT  30.188 59.424 30.275 59.448 ;
     RECT  29.027 5.472 30.305 5.496 ;
     RECT  29.977 38.16 30.325 38.184 ;
     RECT  29.365 56.832 30.325 58.104 ;
     RECT  30.188 50.832 30.373 50.952 ;
     RECT  29.557 20.88 30.409 21.192 ;
     RECT  30.373 61.2 30.409 61.224 ;
     RECT  30.325 30.96 30.413 30.984 ;
     RECT  30.157 47.424 30.445 47.688 ;
     RECT  30.133 51.984 30.445 52.872 ;
     RECT  30.445 51.984 30.469 53.16 ;
     RECT  30.469 32.736 30.476 32.76 ;
     RECT  30.193 34.512 30.476 35.496 ;
     RECT  30.373 50.544 30.476 50.952 ;
     RECT  30.409 20.304 30.481 21.192 ;
     RECT  29.509 40.608 30.517 41.064 ;
     RECT  29.729 42.528 30.517 42.552 ;
     RECT  30.161 43.824 30.517 45.576 ;
     RECT  30.445 46.992 30.517 47.688 ;
     RECT  30.476 32.736 30.556 33.288 ;
     RECT  30.556 32.832 30.565 33.288 ;
     RECT  30.121 8.496 30.593 9.24 ;
     RECT  30.229 26.592 30.604 26.616 ;
     RECT  30.325 38.16 30.613 38.664 ;
     RECT  30.613 38.16 30.62 38.76 ;
     RECT  29.581 17.136 30.661 19.32 ;
     RECT  30.481 20.304 30.661 21.48 ;
     RECT  30.517 46.848 30.661 47.688 ;
     RECT  30.157 11.232 30.701 12.024 ;
     RECT  30.476 34.32 30.707 35.496 ;
     RECT  30.62 49.2 30.707 49.224 ;
     RECT  30.62 38.16 30.733 39.096 ;
     RECT  30.661 46.8 30.745 47.688 ;
     RECT  30.668 30.432 30.755 30.456 ;
     RECT  29.617 4.224 30.757 4.248 ;
     RECT  30.733 38.16 30.765 39.624 ;
     RECT  30.661 17.136 30.769 21.48 ;
     RECT  30.476 50.448 30.769 50.952 ;
     RECT  27.544 64.656 30.769 64.68 ;
     RECT  30.589 13.056 30.803 13.08 ;
     RECT  30.265 27.6 30.803 28.248 ;
     RECT  30.593 8.496 30.809 8.52 ;
     RECT  30.769 64.56 30.809 64.68 ;
     RECT  30.517 40.608 30.812 41.112 ;
     RECT  29.405 14.352 30.841 15.816 ;
     RECT  30.803 27.936 30.845 28.248 ;
     RECT  30.769 49.248 30.845 50.952 ;
     RECT  30.769 16.848 30.881 21.48 ;
     RECT  30.845 49.248 30.889 50.088 ;
     RECT  30.812 40.608 30.899 41.448 ;
     RECT  30.707 35.088 30.901 35.496 ;
     RECT  30.179 36.576 30.901 36.6 ;
     RECT  30.409 61.104 30.908 61.224 ;
     RECT  30.765 38.16 30.949 38.184 ;
     RECT  30.881 16.848 30.953 19.368 ;
     RECT  30.565 33.024 30.985 33.288 ;
     RECT  30.889 49.44 30.989 50.088 ;
     RECT  30.908 61.104 30.994 61.608 ;
     RECT  30.989 49.44 31.025 49.848 ;
     RECT  30.469 51.984 31.025 53.544 ;
     RECT  30.809 64.56 31.057 64.584 ;
     RECT  30.994 61.104 31.091 61.656 ;
     RECT  30.701 11.232 31.093 11.256 ;
     RECT  31.093 11.184 31.094 11.256 ;
     RECT  30.953 17.136 31.133 19.368 ;
     RECT  30.757 4.224 31.169 4.584 ;
     RECT  31.133 17.136 31.169 17.88 ;
     RECT  30.765 39.6 31.196 39.624 ;
     RECT  30.899 40.608 31.196 40.68 ;
     RECT  30.805 26.208 31.201 26.232 ;
     RECT  30.881 20.736 31.205 21.48 ;
     RECT  30.901 35.088 31.205 36.6 ;
     RECT  31.196 39.6 31.205 40.68 ;
     RECT  30.845 28.08 31.237 28.248 ;
     RECT  30.325 56.832 31.244 58.68 ;
     RECT  31.201 26.016 31.277 26.232 ;
     RECT  30.517 42.528 31.277 45.576 ;
     RECT  31.205 39.744 31.283 40.68 ;
     RECT  31.277 42.528 31.285 43.032 ;
     RECT  30.745 46.848 31.333 47.688 ;
     RECT  30.131 62.832 31.333 62.856 ;
     RECT  31.057 63.84 31.333 64.584 ;
     RECT  31.169 17.136 31.349 17.64 ;
     RECT  31.285 41.664 31.372 43.032 ;
     RECT  31.244 56.784 31.381 58.68 ;
     RECT  30.949 5.712 31.385 5.736 ;
     RECT  30.121 6.816 31.417 6.936 ;
     RECT  31.205 20.832 31.421 21.48 ;
     RECT  31.333 62.832 31.421 64.584 ;
     RECT  31.349 17.184 31.457 17.64 ;
     RECT  31.129 23.952 31.457 23.976 ;
     RECT  31.205 35.088 31.457 35.304 ;
     RECT  31.333 7.92 31.493 7.944 ;
     RECT  31.457 17.232 31.529 17.64 ;
     RECT  31.381 56.784 31.565 59.448 ;
     RECT  31.532 23.568 31.619 23.592 ;
     RECT  31.277 26.016 31.669 26.088 ;
     RECT  31.237 28.08 31.673 28.584 ;
     RECT  31.561 1.968 31.705 1.992 ;
     RECT  31.669 25.776 31.717 26.088 ;
     RECT  31.705 1.68 31.813 1.992 ;
     RECT  31.333 46.848 31.849 47.832 ;
     RECT  31.673 28.08 31.861 28.536 ;
     RECT  31.277 44.16 31.885 45.576 ;
     RECT  31.849 46.848 31.885 48.264 ;
     RECT  31.133 18.96 31.909 19.368 ;
     RECT  31.717 25.728 31.909 26.088 ;
     RECT  31.885 44.16 31.909 48.456 ;
     RECT  31.025 49.44 31.909 49.464 ;
     RECT  31.025 51.984 31.909 53.016 ;
     RECT  31.565 57.024 31.909 59.448 ;
     RECT  31.091 61.104 31.909 61.176 ;
     RECT  31.813 1.68 31.993 2.136 ;
     RECT  31.381 9.84 31.993 9.864 ;
     RECT  31.094 11.184 31.993 11.208 ;
     RECT  31.921 34.752 32.029 34.968 ;
     RECT  31.909 51.072 32.029 53.016 ;
     RECT  31.628 54.48 32.029 54.504 ;
     RECT  31.993 9.84 32.137 11.208 ;
     RECT  31.529 17.472 32.137 17.64 ;
     RECT  31.909 18.96 32.137 19.8 ;
     RECT  31.169 4.224 32.173 4.248 ;
     RECT  32.029 51.072 32.209 53.064 ;
     RECT  30.949 37.872 32.245 38.184 ;
     RECT  31.909 24.96 32.281 26.088 ;
     RECT  31.283 40.608 32.281 40.68 ;
     RECT  31.877 31.968 32.3 31.992 ;
     RECT  30.985 33.024 32.3 33.624 ;
     RECT  32.173 4.128 32.317 4.248 ;
     RECT  32.317 4.128 32.353 4.488 ;
     RECT  32.137 9.216 32.389 11.208 ;
     RECT  31.421 21.456 32.389 21.48 ;
     RECT  31.421 62.832 32.389 62.856 ;
     RECT  31.372 42 32.425 43.032 ;
     RECT  31.421 64.56 32.425 64.584 ;
     RECT  32.389 62.832 32.444 63.288 ;
     RECT  32.425 64.368 32.444 64.584 ;
     RECT  32.389 9.216 32.472 11.256 ;
     RECT  32.353 30.72 32.485 30.744 ;
     RECT  31.417 6.672 32.492 6.936 ;
     RECT  30.841 14.16 32.492 15.816 ;
     RECT  32.492 13.92 32.533 15.816 ;
     RECT  32.492 55.584 32.533 55.608 ;
     RECT  31.909 57.024 32.533 61.176 ;
     RECT  32.492 6.24 32.605 6.936 ;
     RECT  32.472 8.976 32.605 11.256 ;
     RECT  32.533 55.584 32.605 55.8 ;
     RECT  32.533 56.832 32.605 61.176 ;
     RECT  31.993 1.392 32.648 2.136 ;
     RECT  32.353 4.128 32.648 4.68 ;
     RECT  32.605 5.76 32.648 6.936 ;
     RECT  32.605 8.736 32.648 11.256 ;
     RECT  32.533 13.92 32.648 15.864 ;
     RECT  32.137 17.472 32.648 19.8 ;
     RECT  32.389 21.216 32.648 21.48 ;
     RECT  32.281 24.624 32.648 26.088 ;
     RECT  31.861 27.312 32.648 28.536 ;
     RECT  32.485 30.144 32.648 30.744 ;
     RECT  32.3 31.968 32.648 33.624 ;
     RECT  32.029 34.656 32.648 34.968 ;
     RECT  31.205 36.576 32.648 36.6 ;
     RECT  32.245 37.872 32.648 38.472 ;
     RECT  32.281 40.56 32.648 40.68 ;
     RECT  32.425 41.664 32.648 43.032 ;
     RECT  31.909 44.16 32.648 49.464 ;
     RECT  32.209 50.976 32.648 53.064 ;
     RECT  32.029 54.096 32.648 54.504 ;
     RECT  32.605 55.584 32.648 61.176 ;
     RECT  32.444 62.832 32.648 64.584 ;
     RECT  32.648 0.528 32.752 64.584 ;
     RECT  32.752 0.798 32.944 64.584 ;
     RECT  32.944 4.128 33.059 5.784 ;
     RECT  32.944 6.816 33.059 7.128 ;
     RECT  32.944 12.864 33.059 17.688 ;
     RECT  32.944 26.832 33.059 26.856 ;
     RECT  32.944 34.224 33.059 36.6 ;
     RECT  32.944 37.872 33.059 37.992 ;
     RECT  32.944 43.584 33.059 48.984 ;
     RECT  32.944 30.144 33.077 30.168 ;
     RECT  33.059 4.128 33.149 5.736 ;
     RECT  32.944 21.216 33.185 21.48 ;
     RECT  32.944 56.496 33.185 60.024 ;
     RECT  32.944 8.448 33.196 11.544 ;
     RECT  33.059 15.696 33.221 17.688 ;
     RECT  32.944 32.736 33.251 33.144 ;
     RECT  32.944 61.008 33.257 64.584 ;
     RECT  33.059 34.224 33.299 35.112 ;
     RECT  32.944 50.016 33.299 50.04 ;
     RECT  33.257 64.32 33.299 64.584 ;
     RECT  33.196 8.448 33.329 11.496 ;
     RECT  32.944 18.768 33.365 19.368 ;
     RECT  33.257 61.008 33.395 63.288 ;
     RECT  32.944 28.272 33.443 28.776 ;
     RECT  32.944 40.32 33.473 40.872 ;
     RECT  33.185 60 33.484 60.024 ;
     RECT  33.299 64.32 33.491 64.44 ;
     RECT  33.473 40.56 33.581 40.872 ;
     RECT  32.944 39.216 33.587 39.24 ;
     RECT  33.491 64.416 33.587 64.44 ;
     RECT  33.581 40.56 33.617 40.632 ;
     RECT  32.944 52.752 33.625 53.112 ;
     RECT  33.443 28.272 33.653 28.296 ;
     RECT  32.944 51.648 33.724 51.672 ;
     RECT  33.395 61.008 33.761 62.856 ;
     RECT  33.059 12.864 33.868 14.664 ;
     RECT  33.251 33.12 33.875 33.144 ;
     RECT  33.625 52.752 33.937 53.064 ;
     RECT  33.761 61.008 33.937 61.56 ;
     RECT  33.221 15.984 33.973 17.688 ;
     RECT  33.365 18.768 33.973 19.32 ;
     RECT  33.973 15.984 33.977 19.32 ;
     RECT  33.299 34.224 34.009 34.776 ;
     RECT  33.925 31.536 34.012 31.56 ;
     RECT  33.185 56.496 34.013 58.68 ;
     RECT  33.185 21.456 34.045 21.48 ;
     RECT  33.977 15.984 34.121 19.08 ;
     RECT  33.149 5.712 34.211 5.736 ;
     RECT  34.121 15.984 34.211 16.584 ;
     RECT  33.059 36.096 34.213 36.6 ;
     RECT  33.059 37.872 34.213 37.896 ;
     RECT  33.149 4.128 34.22 4.68 ;
     RECT  34.189 25.824 34.225 25.848 ;
     RECT  33.329 8.448 34.229 8.472 ;
     RECT  32.944 1.488 34.261 1.512 ;
     RECT  34.22 3.504 34.265 4.68 ;
     RECT  34.213 37.872 34.289 38.184 ;
     RECT  34.225 25.536 34.297 25.848 ;
     RECT  33.059 43.584 34.301 48.888 ;
     RECT  34.265 3.504 34.307 4.248 ;
     RECT  34.213 35.856 34.309 36.6 ;
     RECT  34.289 37.872 34.309 38.232 ;
     RECT  34.013 56.592 34.333 58.68 ;
     RECT  34.261 1.44 34.348 1.512 ;
     RECT  34.297 24.576 34.369 25.848 ;
     RECT  34.333 56.592 34.417 58.728 ;
     RECT  32.944 42.528 34.441 42.552 ;
     RECT  34.417 56.592 34.481 58.68 ;
     RECT  34.009 34.176 34.499 34.776 ;
     RECT  34.045 21.456 34.513 21.672 ;
     RECT  34.481 56.592 34.547 58.584 ;
     RECT  34.333 32.928 34.585 32.952 ;
     RECT  34.585 32.88 34.604 32.952 ;
     RECT  34.513 21.408 34.621 21.672 ;
     RECT  33.329 9.696 34.733 11.496 ;
     RECT  34.121 17.616 34.733 19.08 ;
     RECT  34.441 42 34.765 42.552 ;
     RECT  34.369 24.576 34.769 26.808 ;
     RECT  33.937 60.048 34.769 61.56 ;
     RECT  34.7 54.864 34.787 54.888 ;
     RECT  34.309 35.856 34.789 38.232 ;
     RECT  33.059 6.816 34.805 6.936 ;
     RECT  34.499 34.176 34.805 34.488 ;
     RECT  34.547 56.592 34.805 58.296 ;
     RECT  34.769 60.048 34.805 61.032 ;
     RECT  34.211 16.56 34.841 16.584 ;
     RECT  34.769 25.536 34.841 25.752 ;
     RECT  34.789 35.856 34.876 38.76 ;
     RECT  34.841 25.536 34.877 25.56 ;
     RECT  34.876 35.856 34.931 38.664 ;
     RECT  33.868 14.352 34.945 14.664 ;
     RECT  34.733 17.616 34.972 18.984 ;
     RECT  34.621 21.408 34.988 22.008 ;
     RECT  34.94 30.528 35.027 30.552 ;
     RECT  34.988 21.408 35.075 22.344 ;
     RECT  34.733 9.696 35.129 9.96 ;
     RECT  33.937 51.888 35.132 53.064 ;
     RECT  33.761 62.832 35.161 62.856 ;
     RECT  35.161 62.832 35.221 63 ;
     RECT  34.931 35.856 35.273 37.752 ;
     RECT  35.221 62.736 35.309 63 ;
     RECT  33.868 12.864 35.317 13.08 ;
     RECT  35.075 21.408 35.341 22.104 ;
     RECT  34.805 60.048 35.363 60.888 ;
     RECT  34.765 41.616 35.377 42.552 ;
     RECT  34.301 43.584 35.377 48.744 ;
     RECT  34.307 4.224 35.381 4.248 ;
     RECT  35.132 51.6 35.42 53.064 ;
     RECT  35.377 41.616 35.449 48.744 ;
     RECT  35.449 41.616 35.453 48.984 ;
     RECT  35.372 29.952 35.459 30.408 ;
     RECT  34.733 10.992 35.485 11.496 ;
     RECT  35.317 12.48 35.485 13.08 ;
     RECT  35.42 50.976 35.507 53.064 ;
     RECT  35.453 42 35.525 48.984 ;
     RECT  35.507 51.504 35.555 53.064 ;
     RECT  34.604 32.592 35.557 32.952 ;
     RECT  35.525 43.536 35.593 48.984 ;
     RECT  35.557 32.304 35.644 32.952 ;
     RECT  34.769 26.784 35.665 26.808 ;
     RECT  35.593 54.816 35.708 54.84 ;
     RECT  35.555 51.696 35.756 53.064 ;
     RECT  34.805 34.368 35.773 34.488 ;
     RECT  35.708 54.624 35.795 54.84 ;
     RECT  35.644 32.736 35.797 32.952 ;
     RECT  35.749 5.232 35.809 5.256 ;
     RECT  34.805 57.312 35.809 58.296 ;
     RECT  35.756 51.696 35.843 53.112 ;
     RECT  35.773 34.368 35.845 34.68 ;
     RECT  35.525 42 35.849 42.552 ;
     RECT  35.797 32.736 35.884 33.336 ;
     RECT  34.348 1.488 35.893 1.512 ;
     RECT  35.273 35.952 35.893 37.752 ;
     RECT  35.809 57.312 35.893 58.488 ;
     RECT  35.269 8.208 35.917 8.232 ;
     RECT  35.665 26.784 35.957 27.672 ;
     RECT  35.459 30.384 35.957 30.408 ;
     RECT  35.893 35.952 35.993 38.52 ;
     RECT  35.309 62.832 36.025 63 ;
     RECT  35.893 1.296 36.035 1.512 ;
     RECT  35.845 34.368 36.065 34.728 ;
     RECT  35.957 26.784 36.092 27.624 ;
     RECT  35.485 10.992 36.101 13.08 ;
     RECT  35.773 15.744 36.137 15.768 ;
     RECT  36.092 26.016 36.179 27.624 ;
     RECT  36.065 34.656 36.209 34.728 ;
     RECT  35.993 35.952 36.217 38.424 ;
     RECT  35.363 60.864 36.236 60.888 ;
     RECT  36.179 26.832 36.245 27.624 ;
     RECT  36.245 26.832 36.353 26.856 ;
     RECT  35.893 57.12 36.353 58.488 ;
     RECT  34.972 18.816 36.361 18.984 ;
     RECT  36.284 24.48 36.371 24.504 ;
     RECT  36.236 60.864 36.38 61.656 ;
     RECT  35.809 5.04 36.457 5.544 ;
     RECT  35.881 23.328 36.457 23.352 ;
     RECT  35.341 20.496 36.461 22.104 ;
     RECT  35.884 32.736 36.461 32.952 ;
     RECT  36.217 36.576 36.467 38.424 ;
     RECT  36.38 60.864 36.467 61.704 ;
     RECT  36.457 23.328 36.469 23.4 ;
     RECT  36.349 16.512 36.493 16.536 ;
     RECT  34.972 17.616 36.493 17.688 ;
     RECT  35.849 42 36.493 42.024 ;
     RECT  35.843 51.696 36.497 53.064 ;
     RECT  36.457 4.416 36.565 5.544 ;
     RECT  35.593 43.536 36.569 49.416 ;
     RECT  36.493 39.6 36.601 39.624 ;
     RECT  33.617 40.608 36.601 40.632 ;
     RECT  36.469 22.848 36.605 23.4 ;
     RECT  36.025 62.832 36.605 63.576 ;
     RECT  36.493 16.512 36.677 17.928 ;
     RECT  36.469 30.528 36.677 30.552 ;
     RECT  36.497 51.696 36.86 52.824 ;
     RECT  36.461 20.496 36.889 21.72 ;
     RECT  36.677 17.04 36.893 17.928 ;
     RECT  36.461 32.784 36.893 32.952 ;
     RECT  36.493 41.664 36.893 42.024 ;
     RECT  36.467 60.864 36.901 60.888 ;
     RECT  36.86 51.6 36.947 52.824 ;
     RECT  36.101 10.992 36.956 12.888 ;
     RECT  36.901 60.816 36.961 60.888 ;
     RECT  36.565 4.416 36.965 5.64 ;
     RECT  35.917 8.208 36.997 8.376 ;
     RECT  36.035 1.296 37.001 1.32 ;
     RECT  36.965 5.616 37.004 5.64 ;
     RECT  36.997 25.008 37.004 25.032 ;
     RECT  36.601 39.6 37.033 40.632 ;
     RECT  37.033 39.552 37.037 40.632 ;
     RECT  35.845 55.584 37.037 55.848 ;
     RECT  36.889 20.304 37.043 21.72 ;
     RECT  36.956 28.416 37.043 28.44 ;
     RECT  36.956 30.96 37.043 30.984 ;
     RECT  36.965 4.416 37.084 4.44 ;
     RECT  36.353 57.312 37.148 58.488 ;
     RECT  35.853 3.408 37.177 3.432 ;
     RECT  36.361 18.96 37.249 18.984 ;
     RECT  36.812 35.28 37.436 35.304 ;
     RECT  36.947 51.696 37.477 52.824 ;
     RECT  37.285 53.808 37.477 53.832 ;
     RECT  37.436 35.28 37.525 35.4 ;
     RECT  37.043 21.12 37.532 21.72 ;
     RECT  37.004 5.616 37.573 5.784 ;
     RECT  34.805 6.912 37.573 6.936 ;
     RECT  35.129 9.696 37.573 9.72 ;
     RECT  36.956 10.944 37.573 12.888 ;
     RECT  37.045 33.264 37.573 33.384 ;
     RECT  37.573 33.264 37.609 33.672 ;
     RECT  37.525 34.944 37.609 35.4 ;
     RECT  34.945 14.352 37.717 14.712 ;
     RECT  36.605 62.832 37.724 62.856 ;
     RECT  37.724 62.832 37.745 63.096 ;
     RECT  36.467 36.576 37.789 37.752 ;
     RECT  37.717 14.352 37.861 15.576 ;
     RECT  37.789 36.576 37.861 37.896 ;
     RECT  37.861 36.576 37.909 38.04 ;
     RECT  37.789 26.832 37.933 26.856 ;
     RECT  36.569 43.536 37.933 48.792 ;
     RECT  36.893 17.664 37.969 17.928 ;
     RECT  37.249 18.96 37.969 19.896 ;
     RECT  37.909 36.576 37.969 38.184 ;
     RECT  37.573 9.696 38.005 12.888 ;
     RECT  37.537 1.488 38.048 1.512 ;
     RECT  37.177 3.024 38.048 3.432 ;
     RECT  37.573 5.616 38.048 6.936 ;
     RECT  36.997 8.16 38.048 8.376 ;
     RECT  38.005 9.696 38.048 13.08 ;
     RECT  37.861 14.352 38.048 15.768 ;
     RECT  37.969 17.664 38.048 19.896 ;
     RECT  37.532 21.12 38.048 21.864 ;
     RECT  36.605 22.848 38.048 23.352 ;
     RECT  37.004 25.008 38.048 25.752 ;
     RECT  37.933 26.784 38.048 26.856 ;
     RECT  37.609 33.264 38.048 35.4 ;
     RECT  37.969 36.576 38.048 38.232 ;
     RECT  37.037 39.552 38.048 39.672 ;
     RECT  36.893 42 38.048 42.024 ;
     RECT  37.933 43.536 38.048 48.984 ;
     RECT  37.189 50.016 38.048 50.424 ;
     RECT  37.477 51.696 38.048 53.832 ;
     RECT  37.037 55.584 38.048 55.608 ;
     RECT  37.148 57.312 38.048 58.632 ;
     RECT  36.961 60.096 38.048 60.888 ;
     RECT  37.745 62.736 38.048 63.096 ;
     RECT  38.048 0.528 38.152 64.272 ;
     RECT  38.152 0.798 38.344 64.002 ;
     RECT  38.344 34.368 38.369 38.28 ;
     RECT  38.344 29.184 38.483 29.88 ;
     RECT  38.369 34.368 38.513 38.232 ;
     RECT  38.344 31.872 38.531 33.144 ;
     RECT  38.513 34.368 38.531 37.944 ;
     RECT  38.344 14.64 38.585 16.344 ;
     RECT  38.344 24.912 38.585 26.856 ;
     RECT  38.344 5.76 38.62 6.936 ;
     RECT  38.483 29.184 38.621 29.208 ;
     RECT  38.344 27.84 38.657 28.008 ;
     RECT  38.531 36.384 38.657 37.944 ;
     RECT  38.344 7.92 38.668 7.944 ;
     RECT  38.585 14.688 38.693 16.344 ;
     RECT  38.344 9.552 38.729 13.08 ;
     RECT  38.729 9.552 38.765 9.576 ;
     RECT  38.693 15.792 38.765 16.344 ;
     RECT  38.657 27.984 38.765 28.008 ;
     RECT  38.344 3.072 38.771 3.096 ;
     RECT  38.585 26.832 38.837 26.856 ;
     RECT  38.657 36.576 38.837 37.944 ;
     RECT  38.344 54.72 38.837 55.752 ;
     RECT  38.344 4.224 38.867 4.44 ;
     RECT  38.344 17.664 38.873 19.896 ;
     RECT  38.585 24.912 38.873 25.608 ;
     RECT  38.837 54.72 38.909 54.888 ;
     RECT  38.344 56.976 38.963 63.24 ;
     RECT  38.873 18.96 38.981 19.896 ;
     RECT  38.344 21.456 39.017 22.872 ;
     RECT  38.909 54.72 39.053 54.744 ;
     RECT  38.344 40.032 39.196 47.736 ;
     RECT  38.531 34.368 39.269 35.304 ;
     RECT  38.873 24.912 39.305 25.032 ;
     RECT  39.017 21.456 39.308 21.768 ;
     RECT  39.305 25.008 39.377 25.032 ;
     RECT  38.765 15.792 39.395 15.816 ;
     RECT  38.344 48.72 39.397 49.32 ;
     RECT  39.397 48.72 39.484 49.944 ;
     RECT  39.308 20.688 39.485 21.768 ;
     RECT  38.963 62.736 39.491 63.24 ;
     RECT  38.873 17.664 39.517 17.688 ;
     RECT  38.729 10.944 39.539 12.888 ;
     RECT  38.963 56.976 39.553 61.704 ;
     RECT  38.981 18.96 39.557 19.416 ;
     RECT  39.491 62.736 39.587 63.192 ;
     RECT  38.344 51.696 39.644 53.544 ;
     RECT  39.269 35.232 39.665 35.304 ;
     RECT  39.587 62.736 39.665 62.808 ;
     RECT  39.644 51.696 39.685 54.072 ;
     RECT  38.693 14.688 39.697 14.808 ;
     RECT  39.665 62.736 39.737 62.76 ;
     RECT  39.539 12.24 39.773 12.888 ;
     RECT  39.517 16.848 39.773 17.688 ;
     RECT  39.196 40.032 39.781 40.536 ;
     RECT  39.539 10.944 39.805 11.208 ;
     RECT  39.685 51.36 39.836 54.072 ;
     RECT  39.781 39.216 39.868 40.536 ;
     RECT  39.773 12.24 39.881 12.264 ;
     RECT  39.445 29.568 39.913 29.592 ;
     RECT  39.805 10.848 39.917 11.208 ;
     RECT  38.837 36.576 39.917 37.752 ;
     RECT  38.867 4.416 39.923 4.44 ;
     RECT  39.485 20.688 39.923 21.48 ;
     RECT  39.836 51.12 39.923 54.072 ;
     RECT  39.553 56.304 39.923 61.704 ;
     RECT  39.923 56.304 39.941 60.984 ;
     RECT  39.913 29.568 39.953 30.36 ;
     RECT  38.531 32.496 39.953 33.144 ;
     RECT  39.484 48.72 39.953 49.512 ;
     RECT  39.941 55.392 39.953 60.984 ;
     RECT  39.196 41.616 39.98 47.736 ;
     RECT  39.953 48.72 39.98 49.464 ;
     RECT  39.953 55.392 39.989 59.016 ;
     RECT  39.925 2.88 40.012 2.904 ;
     RECT  39.989 55.392 40.025 58.728 ;
     RECT  39.98 41.616 40.067 49.464 ;
     RECT  40.025 56.304 40.097 58.728 ;
     RECT  39.017 22.8 40.124 22.872 ;
     RECT  40.124 22.704 40.165 22.872 ;
     RECT  40.097 56.304 40.169 57.048 ;
     RECT  40.165 22.704 40.237 23.016 ;
     RECT  40.021 35.376 40.309 35.4 ;
     RECT  39.917 36.576 40.309 36.6 ;
     RECT  39.557 18.96 40.345 18.984 ;
     RECT  40.097 58.416 40.349 58.728 ;
     RECT  39.923 51.312 40.355 54.072 ;
     RECT  39.697 14.448 40.357 14.808 ;
     RECT  40.355 51.36 40.381 54.072 ;
     RECT  40.237 22.704 40.385 23.304 ;
     RECT  40.381 51.36 40.385 54.456 ;
     RECT  40.067 48.864 40.403 49.464 ;
     RECT  40.345 18.72 40.451 18.984 ;
     RECT  39.953 30.336 40.451 30.36 ;
     RECT  39.917 37.632 40.453 37.752 ;
     RECT  38.62 6.096 40.489 6.936 ;
     RECT  40.385 51.6 40.492 54.456 ;
     RECT  40.451 18.96 40.561 18.984 ;
     RECT  39.868 39.744 40.597 40.536 ;
     RECT  40.067 41.616 40.597 47.784 ;
     RECT  40.489 5.808 40.637 6.936 ;
     RECT  40.453 37.632 40.637 38.376 ;
     RECT  40.492 52.176 40.637 54.456 ;
     RECT  40.403 48.96 40.673 49.464 ;
     RECT  40.169 56.832 40.673 57.048 ;
     RECT  39.953 32.832 40.777 33.144 ;
     RECT  40.345 27.648 40.781 27.672 ;
     RECT  40.309 35.376 40.817 36.6 ;
     RECT  40.673 56.832 40.828 56.856 ;
     RECT  39.923 21.36 40.883 21.48 ;
     RECT  40.637 5.808 40.885 5.832 ;
     RECT  40.637 37.632 40.889 38.28 ;
     RECT  40.889 37.728 40.925 38.28 ;
     RECT  40.885 5.76 40.957 5.832 ;
     RECT  40.597 39.744 40.961 47.784 ;
     RECT  39.773 17.664 40.997 17.688 ;
     RECT  40.817 35.376 41.027 35.4 ;
     RECT  40.637 52.176 41.027 54.12 ;
     RECT  39.917 11.184 41.029 11.208 ;
     RECT  40.741 29.184 41.033 29.352 ;
     RECT  39.953 60.432 41.036 60.888 ;
     RECT  40.561 18.96 41.065 19.128 ;
     RECT  41.036 60.432 41.069 61.848 ;
     RECT  40.883 21.456 41.077 21.48 ;
     RECT  40.961 39.744 41.077 40.056 ;
     RECT  40.961 41.712 41.105 46.248 ;
     RECT  41.029 4.464 41.116 4.488 ;
     RECT  41.069 60.816 41.123 61.848 ;
     RECT  40.637 6.912 41.137 6.936 ;
     RECT  40.993 16.32 41.137 16.344 ;
     RECT  40.385 23.28 41.137 23.304 ;
     RECT  40.957 5.712 41.141 5.832 ;
     RECT  40.673 49.056 41.141 49.464 ;
     RECT  41.027 52.464 41.141 54.12 ;
     RECT  41.065 18.96 41.149 19.272 ;
     RECT  41.077 21.456 41.164 22.296 ;
     RECT  41.077 39.312 41.164 40.056 ;
     RECT  41.141 49.104 41.213 49.464 ;
     RECT  41.137 16.32 41.245 16.536 ;
     RECT  41.029 10.944 41.276 11.208 ;
     RECT  40.777 32.832 41.317 33.576 ;
     RECT  41.105 42.144 41.329 46.248 ;
     RECT  41.141 5.712 41.357 5.784 ;
     RECT  41.164 40.032 41.357 40.056 ;
     RECT  41.276 10.944 41.363 11.352 ;
     RECT  40.349 58.416 41.389 58.632 ;
     RECT  41.389 62.16 41.425 62.76 ;
     RECT  41.149 18.96 41.429 19.128 ;
     RECT  41.425 62.16 41.468 63.048 ;
     RECT  40.357 14.448 41.497 14.712 ;
     RECT  41.329 42.336 41.501 46.248 ;
     RECT  41.245 16.32 41.516 17.064 ;
     RECT  41.363 10.944 41.525 11.208 ;
     RECT  40.961 47.328 41.533 47.784 ;
     RECT  41.468 62.16 41.555 63.336 ;
     RECT  41.516 16.08 41.603 17.064 ;
     RECT  41.137 23.28 41.603 24.072 ;
     RECT  41.497 13.056 41.605 13.08 ;
     RECT  41.497 14.448 41.605 14.76 ;
     RECT  41.501 42.384 41.609 46.248 ;
     RECT  41.603 23.28 41.612 23.88 ;
     RECT  41.605 13.056 41.645 14.76 ;
     RECT  41.389 58.416 41.645 59.352 ;
     RECT  41.123 60.816 41.645 60.888 ;
     RECT  41.141 54.048 41.653 54.12 ;
     RECT  41.033 29.328 41.681 29.352 ;
     RECT  41.612 22.704 41.699 23.88 ;
     RECT  41.609 42.768 41.717 46.248 ;
     RECT  41.653 54.048 41.74 54.936 ;
     RECT  41.699 23.28 41.753 23.88 ;
     RECT  41.74 54.048 41.753 54.072 ;
     RECT  41.804 56.784 41.813 56.808 ;
     RECT  41.317 32.64 41.821 33.576 ;
     RECT  40.817 36.576 41.857 36.6 ;
     RECT  40.925 37.728 41.857 37.752 ;
     RECT  41.813 56.496 41.891 56.808 ;
     RECT  41.645 13.632 41.897 14.76 ;
     RECT  41.603 16.32 41.897 16.776 ;
     RECT  41.891 56.496 41.897 56.52 ;
     RECT  41.645 58.416 41.933 58.968 ;
     RECT  41.821 31.968 41.939 33.576 ;
     RECT  41.845 30.336 42.001 30.36 ;
     RECT  41.497 0.72 42.073 0.744 ;
     RECT  41.213 49.104 42.109 49.32 ;
     RECT  42.037 28.416 42.124 28.44 ;
     RECT  41.525 10.848 42.145 11.208 ;
     RECT  41.717 42.864 42.145 46.248 ;
     RECT  41.533 47.328 42.145 47.832 ;
     RECT  42.073 34.752 42.157 34.776 ;
     RECT  41.555 62.16 42.179 63.048 ;
     RECT  42.073 0.624 42.181 0.744 ;
     RECT  41.141 52.464 42.181 52.584 ;
     RECT  42.181 52.416 42.217 52.584 ;
     RECT  42.14 57.6 42.227 57.864 ;
     RECT  42.145 10.752 42.257 11.208 ;
     RECT  42.179 62.544 42.257 63.048 ;
     RECT  42.181 0.624 42.265 1.464 ;
     RECT  42.227 57.696 42.316 57.864 ;
     RECT  42.265 0.624 42.325 1.32 ;
     RECT  42.217 51.936 42.362 52.584 ;
     RECT  42.316 57.792 42.364 57.864 ;
     RECT  41.857 36.576 42.397 37.752 ;
     RECT  41.939 32.784 42.421 33.576 ;
     RECT  42.397 36.576 42.421 38.28 ;
     RECT  42.253 40.464 42.433 40.488 ;
     RECT  42.109 49.056 42.469 49.32 ;
     RECT  42.145 42.864 42.476 47.832 ;
     RECT  42.469 49.008 42.476 49.32 ;
     RECT  41.137 6.912 42.505 6.984 ;
     RECT  42.505 6.912 42.541 7.416 ;
     RECT  41.897 16.752 42.572 16.776 ;
     RECT  42.362 51.984 42.577 52.584 ;
     RECT  42.325 0.576 42.605 1.32 ;
     RECT  42.613 2.304 42.649 2.328 ;
     RECT  42.145 5.232 42.649 5.256 ;
     RECT  42.541 6.816 42.649 7.416 ;
     RECT  42.421 36.576 42.685 38.664 ;
     RECT  42.605 0.192 42.689 1.32 ;
     RECT  41.897 14.448 42.716 14.76 ;
     RECT  42.001 29.712 42.721 30.36 ;
     RECT  42.433 40.32 42.721 40.488 ;
     RECT  41.753 23.664 42.757 23.88 ;
     RECT  42.689 0.24 42.761 1.32 ;
     RECT  41.164 21.456 42.853 21.48 ;
     RECT  42.257 62.832 42.86 63.048 ;
     RECT  41.645 60.864 42.901 60.888 ;
     RECT  42.901 60.864 42.937 60.936 ;
     RECT  42.853 21.456 43.045 22.392 ;
     RECT  41.929 9.072 43.1 9.096 ;
     RECT  42.649 2.304 43.117 2.568 ;
     RECT  43.045 20.592 43.141 22.392 ;
     RECT  42.421 32.784 43.141 34.392 ;
     RECT  42.257 11.184 43.189 11.208 ;
     RECT  41.857 12.432 43.189 12.6 ;
     RECT  43.117 2.304 43.261 2.808 ;
     RECT  41.569 3.936 43.261 3.96 ;
     RECT  43.1 9.072 43.261 9.336 ;
     RECT  42.572 16.752 43.292 17.064 ;
     RECT  43.141 20.4 43.292 22.392 ;
     RECT  42.757 23.616 43.292 23.88 ;
     RECT  42.476 42.864 43.292 49.32 ;
     RECT  43.189 11.184 43.333 12.6 ;
     RECT  41.429 18.96 43.333 18.984 ;
     RECT  43.292 20.4 43.333 23.88 ;
     RECT  43.141 32.784 43.333 34.632 ;
     RECT  42.685 36.576 43.333 38.712 ;
     RECT  42.364 57.84 43.333 57.864 ;
     RECT  41.933 58.944 43.333 58.968 ;
     RECT  43.261 8.832 43.369 9.336 ;
     RECT  43.369 8.784 43.405 9.336 ;
     RECT  43.333 11.184 43.405 13.08 ;
     RECT  42.761 0.528 43.448 1.32 ;
     RECT  43.261 2.304 43.448 3.96 ;
     RECT  42.649 4.992 43.448 7.416 ;
     RECT  43.405 8.784 43.448 9.576 ;
     RECT  43.405 10.608 43.448 13.08 ;
     RECT  42.716 14.448 43.448 14.904 ;
     RECT  43.292 15.984 43.448 17.064 ;
     RECT  43.333 18.96 43.448 23.88 ;
     RECT  42.289 27.12 43.448 27.144 ;
     RECT  42.721 29.712 43.448 30.744 ;
     RECT  43.333 32.736 43.448 34.632 ;
     RECT  43.333 36.48 43.448 38.712 ;
     RECT  42.721 40.32 43.448 41.448 ;
     RECT  43.292 42.864 43.448 49.848 ;
     RECT  42.577 51.984 43.448 53.544 ;
     RECT  43.333 56.496 43.448 56.52 ;
     RECT  43.333 57.84 43.448 58.968 ;
     RECT  42.937 60.672 43.448 60.936 ;
     RECT  42.86 62.832 43.448 63.336 ;
     RECT  43.448 0.528 43.552 64.272 ;
     RECT  43.552 0.624 43.744 64.002 ;
     RECT  43.744 10.608 43.841 13.128 ;
     RECT  43.744 22.752 43.841 23.688 ;
     RECT  43.744 60.912 43.859 63.096 ;
     RECT  43.841 10.848 43.885 13.128 ;
     RECT  43.859 61.2 43.9 63.096 ;
     RECT  43.744 2.304 43.907 3.384 ;
     RECT  43.744 18.192 43.907 19.56 ;
     RECT  43.907 2.304 43.949 2.52 ;
     RECT  43.744 14.448 43.955 17.112 ;
     RECT  43.744 30.096 43.955 30.552 ;
     RECT  43.744 34.656 43.955 35.976 ;
     RECT  43.841 23.376 44.021 23.688 ;
     RECT  43.744 42.528 44.021 47.928 ;
     RECT  43.744 32.784 44.051 33.624 ;
     RECT  43.744 8.736 44.092 9.576 ;
     RECT  43.955 34.656 44.092 35.16 ;
     RECT  43.885 10.896 44.093 13.128 ;
     RECT  44.021 42.528 44.093 47.4 ;
     RECT  43.744 49.104 44.099 55.128 ;
     RECT  43.744 0.624 44.129 0.744 ;
     RECT  44.092 9.024 44.201 9.576 ;
     RECT  43.9 61.44 44.201 63.096 ;
     RECT  44.129 0.672 44.237 0.696 ;
     RECT  43.744 27.456 44.237 27.48 ;
     RECT  43.744 40.608 44.345 40.92 ;
     RECT  44.099 50.832 44.345 55.128 ;
     RECT  44.093 10.896 44.381 12.792 ;
     RECT  44.345 50.832 44.387 50.856 ;
     RECT  44.381 11.184 44.417 12.792 ;
     RECT  43.744 57.6 44.417 59.448 ;
     RECT  43.744 25.008 44.476 25.032 ;
     RECT  44.201 62.4 44.483 63.096 ;
     RECT  44.417 57.6 44.525 58.968 ;
     RECT  44.525 57.6 44.597 58.44 ;
     RECT  43.744 21.456 44.633 21.672 ;
     RECT  43.744 37.008 44.669 38.568 ;
     RECT  43.744 6.768 44.732 6.984 ;
     RECT  43.955 14.448 44.813 14.952 ;
     RECT  44.732 6.624 44.819 6.984 ;
     RECT  44.813 14.448 44.845 14.76 ;
     RECT  44.483 62.4 44.885 63 ;
     RECT  44.092 35.136 44.952 35.16 ;
     RECT  44.099 49.104 44.965 49.608 ;
     RECT  44.669 37.008 44.989 38.04 ;
     RECT  43.949 2.496 45.011 2.52 ;
     RECT  44.597 57.6 45.013 58.2 ;
     RECT  44.845 14.352 45.029 14.76 ;
     RECT  44.952 35.136 45.029 35.352 ;
     RECT  44.201 9.168 45.061 9.576 ;
     RECT  44.989 36.864 45.061 38.04 ;
     RECT  44.345 40.608 45.065 40.632 ;
     RECT  43.955 16.32 45.101 17.112 ;
     RECT  44.021 23.568 45.101 23.688 ;
     RECT  44.345 51.984 45.137 55.128 ;
     RECT  45.061 9.168 45.148 10.104 ;
     RECT  45.101 23.664 45.157 23.688 ;
     RECT  45.025 2.4 45.173 2.424 ;
     RECT  44.051 33.6 45.241 33.624 ;
     RECT  45.157 31.632 45.244 31.656 ;
     RECT  45.137 55.104 45.245 55.128 ;
     RECT  44.885 62.448 45.251 63 ;
     RECT  45.137 51.984 45.313 54.072 ;
     RECT  45.26 3.936 45.347 3.96 ;
     RECT  45.313 51.12 45.349 54.072 ;
     RECT  45.013 57.264 45.349 58.2 ;
     RECT  45.157 23.664 45.353 23.976 ;
     RECT  45.148 10.08 45.385 10.104 ;
     RECT  44.417 11.184 45.385 11.208 ;
     RECT  45.061 36.768 45.389 38.04 ;
     RECT  44.965 49.008 45.404 49.608 ;
     RECT  44.093 42.528 45.421 46.92 ;
     RECT  45.421 42.336 45.452 46.92 ;
     RECT  45.404 49.008 45.491 50.04 ;
     RECT  45.349 51.072 45.529 54.072 ;
     RECT  45.452 42.336 45.539 47.064 ;
     RECT  45.349 56.688 45.539 58.2 ;
     RECT  45.101 16.32 45.565 16.536 ;
     RECT  45.539 42.336 45.569 46.776 ;
     RECT  45.385 10.08 45.587 11.208 ;
     RECT  43.907 18.192 45.589 18.6 ;
     RECT  44.953 25.728 45.589 25.752 ;
     RECT  44.417 12.768 45.637 12.792 ;
     RECT  45.589 17.712 45.637 18.6 ;
     RECT  45.029 35.328 45.637 35.352 ;
     RECT  45.569 42.336 45.637 46.296 ;
     RECT  45.353 23.952 45.641 23.976 ;
     RECT  45.589 25.152 45.641 25.752 ;
     RECT  45.557 55.392 45.641 55.416 ;
     RECT  45.029 14.4 45.677 14.76 ;
     RECT  45.641 25.152 45.677 25.176 ;
     RECT  45.241 33.6 45.677 34.152 ;
     RECT  45.491 49.008 45.677 49.608 ;
     RECT  45.529 50.736 45.683 54.072 ;
     RECT  45.683 50.832 45.724 54.072 ;
     RECT  44.819 6.864 45.749 6.984 ;
     RECT  45.389 36.768 45.779 37.464 ;
     RECT  45.724 51.12 45.785 54.072 ;
     RECT  45.781 8.304 45.817 8.424 ;
     RECT  45.565 16.032 45.821 16.536 ;
     RECT  45.74 5.04 45.827 5.064 ;
     RECT  44.633 21.456 45.877 21.48 ;
     RECT  45.539 56.688 45.884 56.712 ;
     RECT  45.637 17.712 45.893 18.84 ;
     RECT  45.637 35.328 45.925 35.592 ;
     RECT  45.749 6.864 45.929 6.936 ;
     RECT  45.637 12.768 45.961 12.936 ;
     RECT  45.877 21.168 45.964 21.48 ;
     RECT  45.884 56.544 45.971 56.712 ;
     RECT  45.964 21.456 45.997 21.48 ;
     RECT  45.932 5.808 46.019 5.832 ;
     RECT  45.925 35.328 46.021 35.64 ;
     RECT  45.779 36.768 46.021 37.128 ;
     RECT  45.961 12.768 46.069 13.032 ;
     RECT  46.069 12.768 46.109 13.08 ;
     RECT  46.021 35.328 46.109 37.128 ;
     RECT  46.109 35.328 46.145 35.64 ;
     RECT  46.109 12.864 46.153 13.08 ;
     RECT  45.677 49.008 46.177 49.464 ;
     RECT  46.109 37.104 46.204 37.128 ;
     RECT  45.893 18.384 46.217 18.84 ;
     RECT  46.133 32.736 46.217 32.76 ;
     RECT  46.141 31.344 46.249 31.368 ;
     RECT  45.785 52.176 46.253 54.072 ;
     RECT  45.817 7.968 46.261 8.424 ;
     RECT  46.105 60.912 46.285 60.936 ;
     RECT  46.153 12.864 46.289 13.032 ;
     RECT  45.539 57.84 46.289 58.2 ;
     RECT  46.145 35.52 46.325 35.64 ;
     RECT  45.971 56.688 46.325 56.712 ;
     RECT  46.261 7.968 46.348 8.52 ;
     RECT  46.253 52.176 46.348 53.832 ;
     RECT  46.177 48.96 46.357 49.464 ;
     RECT  46.217 18.384 46.361 18.6 ;
     RECT  46.285 60.912 46.364 61.416 ;
     RECT  45.251 62.448 46.364 62.808 ;
     RECT  46.364 60.912 46.451 62.808 ;
     RECT  45.733 38.544 46.501 38.568 ;
     RECT  46.348 7.968 46.505 8.424 ;
     RECT  46.451 62.784 46.505 62.808 ;
     RECT  46.357 48.144 46.541 49.464 ;
     RECT  45.997 21.456 46.549 22.296 ;
     RECT  46.249 31.344 46.577 32.472 ;
     RECT  45.785 51.12 46.577 51.144 ;
     RECT  45.637 41.664 46.609 46.296 ;
     RECT  46.289 12.912 46.613 13.032 ;
     RECT  46.549 21.456 46.636 22.776 ;
     RECT  46.289 57.84 46.652 57.864 ;
     RECT  46.505 8.4 46.721 8.424 ;
     RECT  46.501 38.544 46.721 39 ;
     RECT  46.348 52.176 46.721 53.784 ;
     RECT  46.652 28.224 46.739 28.248 ;
     RECT  46.451 60.912 46.739 61.416 ;
     RECT  45.587 10.704 46.741 11.208 ;
     RECT  45.677 14.448 46.741 14.76 ;
     RECT  46.325 35.52 46.757 35.592 ;
     RECT  46.609 41.664 46.757 46.728 ;
     RECT  45.821 16.32 46.901 16.536 ;
     RECT  46.721 52.464 46.937 53.784 ;
     RECT  46.937 53.76 46.973 53.784 ;
     RECT  46.741 14.448 47.041 14.904 ;
     RECT  46.741 10.08 47.045 11.208 ;
     RECT  47.041 14.256 47.081 14.904 ;
     RECT  47.036 17.616 47.123 17.64 ;
     RECT  47.045 10.368 47.164 11.208 ;
     RECT  46.741 3.888 47.189 3.912 ;
     RECT  46.652 57.264 47.267 57.864 ;
     RECT  46.541 48.144 47.293 49.224 ;
     RECT  46.636 21.456 47.329 22.296 ;
     RECT  47.121 2.832 47.365 2.856 ;
     RECT  46.577 32.016 47.365 32.472 ;
     RECT  46.613 13.008 47.401 13.032 ;
     RECT  47.293 47.76 47.429 49.224 ;
     RECT  46.739 60.912 47.468 60.936 ;
     RECT  47.329 20.592 47.509 22.296 ;
     RECT  47.005 56.064 47.509 56.088 ;
     RECT  46.721 38.544 47.513 38.808 ;
     RECT  47.429 47.328 47.513 49.224 ;
     RECT  47.365 50.592 47.545 50.616 ;
     RECT  47.509 36.24 47.596 36.408 ;
     RECT  47.267 57.456 47.596 57.864 ;
     RECT  47.509 56.064 47.621 56.376 ;
     RECT  45.929 6.912 47.689 6.936 ;
     RECT  47.621 56.064 47.689 56.088 ;
     RECT  47.596 36.24 47.692 36.264 ;
     RECT  45.677 33.744 47.693 34.152 ;
     RECT  46.937 52.464 47.725 52.488 ;
     RECT  47.401 13.008 47.729 13.176 ;
     RECT  43.955 30.096 47.729 30.12 ;
     RECT  47.468 60.816 47.761 60.936 ;
     RECT  47.413 53.808 47.797 53.832 ;
     RECT  47.513 38.544 47.801 38.76 ;
     RECT  47.329 27.408 47.869 27.432 ;
     RECT  47.545 50.592 47.869 50.664 ;
     RECT  47.725 51.696 47.869 52.488 ;
     RECT  47.729 13.008 47.873 13.128 ;
     RECT  47.869 27.408 47.893 28.008 ;
     RECT  47.797 53.808 47.9 54.408 ;
     RECT  47.893 62.736 47.905 62.76 ;
     RECT  47.833 0.192 47.917 0.216 ;
     RECT  46.573 26.304 47.933 26.328 ;
     RECT  47.893 27.408 47.933 28.104 ;
     RECT  46.901 16.32 47.977 16.344 ;
     RECT  47.689 6.912 47.989 7.464 ;
     RECT  47.869 4.992 48.005 5.016 ;
     RECT  47.693 34.128 48.013 34.152 ;
     RECT  47.596 57.84 48.085 57.864 ;
     RECT  46.757 41.664 48.157 46.248 ;
     RECT  47.869 50.592 48.157 52.488 ;
     RECT  47.9 53.808 48.157 54.456 ;
     RECT  47.761 25.104 48.332 25.128 ;
     RECT  47.989 6.912 48.337 7.704 ;
     RECT  48.229 8.736 48.337 8.76 ;
     RECT  47.164 10.656 48.476 11.208 ;
     RECT  48.476 10.656 48.517 11.544 ;
     RECT  47.365 32.016 48.517 32.568 ;
     RECT  47.513 47.904 48.517 49.224 ;
     RECT  48.157 50.592 48.517 54.456 ;
     RECT  47.509 20.352 48.524 22.296 ;
     RECT  48.524 19.872 48.553 22.296 ;
     RECT  47.977 15.456 48.565 16.344 ;
     RECT  48.517 47.904 48.613 54.456 ;
     RECT  48.517 10.608 48.62 11.544 ;
     RECT  47.933 26.304 48.625 28.104 ;
     RECT  47.801 38.64 48.625 38.76 ;
     RECT  48.469 40.08 48.625 40.104 ;
     RECT  48.085 57.84 48.697 58.68 ;
     RECT  48.553 19.44 48.709 22.296 ;
     RECT  48.625 30.144 48.709 30.168 ;
     RECT  48.013 34.128 48.709 34.2 ;
     RECT  48.553 35.76 48.709 35.784 ;
     RECT  47.941 0.528 48.848 1.176 ;
     RECT  47.365 2.304 48.848 2.856 ;
     RECT  48.005 4.992 48.848 5.064 ;
     RECT  48.337 6.912 48.848 8.76 ;
     RECT  48.62 10.608 48.848 11.64 ;
     RECT  47.873 13.008 48.848 13.08 ;
     RECT  47.081 14.256 48.848 14.472 ;
     RECT  48.565 15.456 48.848 17.208 ;
     RECT  48.709 19.44 48.848 22.776 ;
     RECT  48.332 25.104 48.848 25.224 ;
     RECT  48.625 26.304 48.848 29.064 ;
     RECT  48.709 30.144 48.848 30.984 ;
     RECT  48.517 32.016 48.848 32.904 ;
     RECT  48.709 34.08 48.848 34.2 ;
     RECT  48.709 35.76 48.848 36.072 ;
     RECT  48.625 38.64 48.848 40.104 ;
     RECT  48.157 41.664 48.848 46.536 ;
     RECT  48.613 47.856 48.848 54.456 ;
     RECT  47.689 55.44 48.848 56.088 ;
     RECT  48.697 57.072 48.848 58.68 ;
     RECT  47.761 59.856 48.848 60.936 ;
     RECT  47.905 62.736 48.848 62.856 ;
     RECT  48.848 0.528 48.952 64.272 ;
     RECT  48.952 0.528 49.144 64.002 ;
     RECT  49.144 0.528 49.165 0.84 ;
     RECT  49.144 47.904 49.205 49.608 ;
     RECT  49.144 19.248 49.283 19.272 ;
     RECT  49.144 39.6 49.283 43.272 ;
     RECT  49.144 62.304 49.283 63.336 ;
     RECT  49.144 13.152 49.427 13.176 ;
     RECT  49.283 39.6 49.457 43.032 ;
     RECT  49.144 44.688 49.529 46.536 ;
     RECT  49.144 24.336 49.564 24.504 ;
     RECT  49.165 0.048 49.565 0.84 ;
     RECT  49.205 48.24 49.565 49.608 ;
     RECT  49.457 39.6 49.637 42.552 ;
     RECT  49.529 44.736 49.637 46.536 ;
     RECT  49.637 44.736 49.673 45.48 ;
     RECT  49.144 30.432 49.745 30.84 ;
     RECT  49.144 58.992 49.853 59.016 ;
     RECT  49.144 10.368 49.907 10.44 ;
     RECT  49.144 27.12 49.907 27.144 ;
     RECT  49.144 29.04 49.925 29.064 ;
     RECT  49.637 46.512 49.925 46.536 ;
     RECT  49.907 10.416 49.961 10.44 ;
     RECT  49.637 40.704 49.997 42.552 ;
     RECT  49.564 24.336 50.069 24.36 ;
     RECT  49.144 35.76 50.137 35.784 ;
     RECT  49.144 25.68 50.14 25.704 ;
     RECT  49.144 7.776 50.147 8.568 ;
     RECT  50.137 35.472 50.147 35.784 ;
     RECT  49.565 49.2 50.147 49.608 ;
     RECT  49.144 52.464 50.149 53.4 ;
     RECT  49.745 30.432 50.173 30.696 ;
     RECT  49.144 32.064 50.176 32.088 ;
     RECT  50.176 32.016 50.177 32.088 ;
     RECT  50.147 7.776 50.188 7.8 ;
     RECT  49.144 20.976 50.188 21 ;
     RECT  50.147 35.472 50.204 35.496 ;
     RECT  49.144 55.248 50.213 56.088 ;
     RECT  50.149 52.032 50.236 53.4 ;
     RECT  49.144 37.296 50.245 37.32 ;
     RECT  50.204 35.376 50.249 35.496 ;
     RECT  49.283 62.304 50.249 62.856 ;
     RECT  50.245 37.248 50.28 37.32 ;
     RECT  50.28 37.248 50.281 37.416 ;
     RECT  50.177 32.016 50.285 32.04 ;
     RECT  50.249 35.376 50.291 35.4 ;
     RECT  49.144 60.72 50.317 60.744 ;
     RECT  50.249 62.304 50.317 62.328 ;
     RECT  50.173 30.192 50.339 30.696 ;
     RECT  50.339 30.192 50.353 30.216 ;
     RECT  49.144 57.648 50.353 57.864 ;
     RECT  50.213 55.248 50.389 55.464 ;
     RECT  50.317 60.72 50.492 62.328 ;
     RECT  50.353 57.648 50.501 58.296 ;
     RECT  49.144 16.848 50.573 16.872 ;
     RECT  50.281 37.104 50.609 37.416 ;
     RECT  50.236 52.992 50.645 53.4 ;
     RECT  50.389 54.576 50.645 55.464 ;
     RECT  50.173 28.464 50.723 29.016 ;
     RECT  50.353 30.048 50.723 30.216 ;
     RECT  50.645 55.44 50.723 55.464 ;
     RECT  50.713 43.536 50.725 43.56 ;
     RECT  49.673 44.736 50.725 45.288 ;
     RECT  50.609 37.296 50.753 37.416 ;
     RECT  49.144 34.128 50.773 34.2 ;
     RECT  50.645 53.088 50.789 53.4 ;
     RECT  50.713 26.208 50.797 26.808 ;
     RECT  49.637 39.6 50.821 39.624 ;
     RECT  50.773 33.84 50.86 34.2 ;
     RECT  50.789 53.376 50.897 53.4 ;
     RECT  50.821 39.216 51.001 39.624 ;
     RECT  49.997 40.704 51.001 41.688 ;
     RECT  50.501 57.648 51.001 57.864 ;
     RECT  50.725 43.536 51.061 45.288 ;
     RECT  50.147 49.2 51.077 49.56 ;
     RECT  50.723 28.464 51.145 28.728 ;
     RECT  51.001 39.216 51.203 41.688 ;
     RECT  50.723 30.192 51.221 30.216 ;
     RECT  51.203 39.6 51.253 41.688 ;
     RECT  50.492 60.288 51.253 62.328 ;
     RECT  51.109 20.448 51.26 20.472 ;
     RECT  51.077 49.2 51.26 49.224 ;
     RECT  51.145 28.32 51.299 28.728 ;
     RECT  51.253 39.6 51.299 42.024 ;
     RECT  50.749 22.224 51.301 22.248 ;
     RECT  51.26 48.912 51.301 49.224 ;
     RECT  50.753 37.392 51.325 37.416 ;
     RECT  50.797 26.208 51.329 26.664 ;
     RECT  51.253 60.288 51.337 63.288 ;
     RECT  51.26 19.68 51.347 20.472 ;
     RECT  51.299 41.616 51.361 42.024 ;
     RECT  51.061 43.536 51.388 46.008 ;
     RECT  51.301 48.384 51.388 49.224 ;
     RECT  51.037 47.136 51.401 47.16 ;
     RECT  49.144 14.448 51.437 14.472 ;
     RECT  50.86 34.08 51.437 34.2 ;
     RECT  51.337 60.288 51.493 62.76 ;
     RECT  51.493 59.568 51.539 62.76 ;
     RECT  51.539 62.736 51.545 62.76 ;
     RECT  51.539 59.568 51.577 61.656 ;
     RECT  51.388 43.536 51.581 43.992 ;
     RECT  51.581 43.536 51.689 43.944 ;
     RECT  51.301 21.648 51.757 22.248 ;
     RECT  51.577 59.52 51.779 61.656 ;
     RECT  51.757 21.456 51.781 22.248 ;
     RECT  51.779 60.864 51.82 61.656 ;
     RECT  51.781 21.456 51.829 22.824 ;
     RECT  51.299 28.704 51.833 28.728 ;
     RECT  51.721 17.712 51.836 17.736 ;
     RECT  51.829 21.456 51.869 23.544 ;
     RECT  51.299 39.6 51.869 40.344 ;
     RECT  51.689 43.536 51.869 43.56 ;
     RECT  51.836 16.8 51.875 17.736 ;
     RECT  51.869 21.456 51.875 21.912 ;
     RECT  51.001 57.6 51.905 57.864 ;
     RECT  50.137 15.456 51.937 15.48 ;
     RECT  51.613 50.736 51.937 50.76 ;
     RECT  51.82 60.864 51.941 61.416 ;
     RECT  51.437 34.128 51.971 34.2 ;
     RECT  51.941 61.392 51.971 61.416 ;
     RECT  51.829 56.352 51.98 56.376 ;
     RECT  51.925 35.232 52.013 35.256 ;
     RECT  51.932 30.432 52.019 30.456 ;
     RECT  51.361 41.616 52.049 42.36 ;
     RECT  51.98 55.824 52.067 56.376 ;
     RECT  51.971 34.128 52.121 34.152 ;
     RECT  51.779 59.712 52.156 59.736 ;
     RECT  51.388 45.264 52.189 46.008 ;
     RECT  51.388 49.2 52.229 49.224 ;
     RECT  51.905 57.84 52.229 57.864 ;
     RECT  51.325 37.392 52.369 37.608 ;
     RECT  51.937 50.736 52.369 50.856 ;
     RECT  51.829 25.008 52.409 25.032 ;
     RECT  51.925 27.408 52.409 27.432 ;
     RECT  51.937 15.264 52.441 15.48 ;
     RECT  51.875 16.8 52.445 16.824 ;
     RECT  52.357 35.808 52.445 35.832 ;
     RECT  51.869 23.52 52.451 23.544 ;
     RECT  52.441 15.216 52.481 15.48 ;
     RECT  51.829 52.224 52.517 52.248 ;
     RECT  52.441 31.392 52.525 31.416 ;
     RECT  52.189 45.264 52.589 46.2 ;
     RECT  51.869 39.744 52.595 40.344 ;
     RECT  52.369 37.056 52.597 37.608 ;
     RECT  52.597 37.056 52.625 38.184 ;
     RECT  52.369 50.736 52.657 51 ;
     RECT  52.625 37.584 52.684 38.184 ;
     RECT  52.067 56.256 52.733 56.376 ;
     RECT  51.329 26.352 52.769 26.376 ;
     RECT  52.589 45.264 52.769 46.008 ;
     RECT  52.549 54.672 52.796 54.696 ;
     RECT  52.595 40.128 52.841 40.344 ;
     RECT  52.657 50.544 52.841 51 ;
     RECT  52.684 37.584 52.877 37.608 ;
     RECT  52.733 56.256 52.913 56.328 ;
     RECT  52.837 16.512 52.94 16.536 ;
     RECT  52.94 16.416 52.985 16.536 ;
     RECT  52.913 56.256 53.021 56.28 ;
     RECT  52.985 16.416 53.027 16.44 ;
     RECT  52.841 40.128 53.057 40.152 ;
     RECT  52.049 41.664 53.089 42.36 ;
     RECT  52.769 45.792 53.093 46.008 ;
     RECT  53.093 45.84 53.165 45.864 ;
     RECT  53.084 36.384 53.171 36.408 ;
     RECT  52.796 54.384 53.377 54.696 ;
     RECT  51.875 21.456 53.413 21.48 ;
     RECT  53.377 54.384 53.449 55.992 ;
     RECT  53.377 58.128 53.485 58.152 ;
     RECT  53.449 49.2 53.557 49.224 ;
     RECT  53.485 57.792 53.557 58.152 ;
     RECT  53.449 54.336 53.629 55.992 ;
     RECT  53.881 52.752 53.941 52.776 ;
     RECT  52.841 50.544 53.996 50.568 ;
     RECT  53.996 50.544 54.061 51.096 ;
     RECT  53.941 52.752 54.061 52.968 ;
     RECT  52.481 15.216 54.097 15.24 ;
     RECT  52.873 30.384 54.125 30.408 ;
     RECT  53.413 21.36 54.133 21.48 ;
     RECT  53.449 19.104 54.169 19.128 ;
     RECT  54.133 45.456 54.169 45.72 ;
     RECT  54.133 47.184 54.169 47.352 ;
     RECT  54.061 50.544 54.169 52.968 ;
     RECT  49.565 0.048 54.248 0.072 ;
     RECT  53.365 10.416 54.248 10.536 ;
     RECT  54.097 15.216 54.248 15.576 ;
     RECT  54.133 17.616 54.248 17.64 ;
     RECT  54.169 19.104 54.248 19.896 ;
     RECT  54.133 21.36 54.248 21.96 ;
     RECT  53.708 23.328 54.248 23.352 ;
     RECT  53.228 24.624 54.248 24.648 ;
     RECT  53.516 27.36 54.248 27.384 ;
     RECT  52.693 28.8 54.248 28.824 ;
     RECT  54.125 30.384 54.248 30.696 ;
     RECT  54.133 33.264 54.248 33.288 ;
     RECT  53.413 36 54.248 36.024 ;
     RECT  53.089 41.664 54.248 42.6 ;
     RECT  54.169 44.976 54.248 45.72 ;
     RECT  54.169 47.136 54.248 47.352 ;
     RECT  53.557 48.768 54.248 49.224 ;
     RECT  54.169 50.544 54.248 53.016 ;
     RECT  53.629 54.288 54.248 55.992 ;
     RECT  53.557 57.648 54.248 58.152 ;
     RECT  54.133 59.28 54.248 59.304 ;
     RECT  54.248 0.048 54.352 64.272 ;
     RECT  54.352 0.048 54.544 64.002 ;
     RECT  54.544 21.12 54.605 21.96 ;
     RECT  54.544 33.264 54.605 37.32 ;
     RECT  54.544 15.216 54.659 15.576 ;
     RECT  54.544 44.64 54.659 47.352 ;
     RECT  54.544 50.544 54.659 50.616 ;
     RECT  54.605 33.264 54.677 33.288 ;
     RECT  54.659 44.64 54.677 47.16 ;
     RECT  54.544 18.816 54.685 19.464 ;
     RECT  54.544 17.616 54.707 17.64 ;
     RECT  54.605 34.752 54.713 37.32 ;
     RECT  54.677 44.928 54.713 47.16 ;
     RECT  54.659 15.456 54.749 15.576 ;
     RECT  54.544 28.8 54.785 28.824 ;
     RECT  54.544 59.856 54.793 59.88 ;
     RECT  54.685 18.816 54.821 19.272 ;
     RECT  54.544 30.384 54.929 30.408 ;
     RECT  54.749 15.456 55.001 15.48 ;
     RECT  54.713 44.976 55.037 47.16 ;
     RECT  55.037 45.84 55.073 47.16 ;
     RECT  54.821 19.248 55.145 19.272 ;
     RECT  54.544 39.168 55.181 39.912 ;
     RECT  54.713 36 55.187 37.32 ;
     RECT  54.544 52.752 55.283 52.776 ;
     RECT  54.544 31.584 55.289 31.608 ;
     RECT  54.544 0.048 55.331 0.216 ;
     RECT  55.187 36 55.369 36.024 ;
     RECT  54.544 23.136 55.469 23.592 ;
     RECT  54.544 54.144 55.469 56.28 ;
     RECT  54.544 57.792 55.505 58.152 ;
     RECT  55.505 57.792 55.525 58.104 ;
     RECT  55.187 37.296 55.577 37.32 ;
     RECT  55.525 57.456 55.612 58.104 ;
     RECT  54.713 34.752 55.613 34.776 ;
     RECT  55.073 45.84 55.613 45.912 ;
     RECT  54.605 21.12 55.617 21.768 ;
     RECT  55.073 47.136 55.685 47.16 ;
     RECT  55.612 57.888 55.685 58.104 ;
     RECT  55.331 0.192 55.715 0.216 ;
     RECT  55.617 21.12 55.763 22.152 ;
     RECT  55.181 39.168 55.859 39.192 ;
     RECT  55.772 43.152 55.859 43.176 ;
     RECT  54.659 50.544 56.053 50.568 ;
     RECT  55.676 29.232 56.101 29.256 ;
     RECT  55.669 19.488 56.108 19.512 ;
     RECT  55.685 58.08 56.153 58.104 ;
     RECT  56.101 29.232 56.185 29.448 ;
     RECT  56.101 25.008 56.188 25.032 ;
     RECT  56.185 28.8 56.188 29.448 ;
     RECT  56.101 15.36 56.189 15.384 ;
     RECT  56.108 19.488 56.195 20.04 ;
     RECT  55.613 45.84 56.197 45.864 ;
     RECT  55.861 17.616 56.225 17.64 ;
     RECT  54.544 48.96 56.225 48.984 ;
     RECT  55.763 21.12 56.236 21.816 ;
     RECT  55.469 23.136 56.369 23.16 ;
     RECT  56.197 45.504 56.401 45.864 ;
     RECT  56.005 26.832 56.437 26.856 ;
     RECT  56.401 45.312 56.437 45.864 ;
     RECT  56.053 50.544 56.492 51.336 ;
     RECT  55.469 56.016 56.509 56.28 ;
     RECT  56.437 44.976 56.585 45.864 ;
     RECT  56.509 56.016 56.629 56.472 ;
     RECT  56.437 26.736 56.636 26.856 ;
     RECT  56.629 56.016 56.716 56.52 ;
     RECT  56.636 26.736 56.723 27.192 ;
     RECT  56.473 17.424 56.801 17.448 ;
     RECT  56.585 45.12 56.821 45.864 ;
     RECT  56.437 47.328 56.821 47.352 ;
     RECT  56.492 50.544 56.869 51.528 ;
     RECT  56.629 52.752 56.869 52.776 ;
     RECT  56.821 47.328 56.873 47.976 ;
     RECT  56.869 50.544 56.908 52.776 ;
     RECT  56.821 45.12 56.909 46.152 ;
     RECT  56.873 47.952 56.909 47.976 ;
     RECT  56.908 50.544 56.909 50.568 ;
     RECT  56.828 34.752 56.915 34.776 ;
     RECT  56.716 56.016 56.917 56.472 ;
     RECT  56.236 21.12 56.963 21.48 ;
     RECT  55.469 54.144 56.965 54.744 ;
     RECT  56.965 53.76 57.004 54.744 ;
     RECT  56.917 55.776 57.004 56.472 ;
     RECT  56.723 26.736 57.011 26.76 ;
     RECT  56.908 51.888 57.011 52.776 ;
     RECT  57.004 53.76 57.011 54.36 ;
     RECT  56.195 19.488 57.049 19.512 ;
     RECT  56.188 28.8 57.053 28.824 ;
     RECT  56.909 45.12 57.053 45.336 ;
     RECT  56.972 43.728 57.059 43.752 ;
     RECT  56.581 15.792 57.061 15.816 ;
     RECT  57.061 15.792 57.125 16.152 ;
     RECT  57.125 16.128 57.148 16.152 ;
     RECT  57.049 35.472 57.155 35.496 ;
     RECT  57.011 51.888 57.161 52.44 ;
     RECT  57.049 37.008 57.164 37.032 ;
     RECT  56.905 25.248 57.193 25.272 ;
     RECT  57.161 52.32 57.197 52.344 ;
     RECT  57.004 56.016 57.197 56.472 ;
     RECT  57.164 36.768 57.251 37.032 ;
     RECT  57.049 18.864 57.341 19.512 ;
     RECT  57.301 46.752 57.385 46.776 ;
     RECT  57.011 53.76 57.413 53.784 ;
     RECT  56.963 21.12 57.449 21.432 ;
     RECT  57.301 38.256 57.449 38.28 ;
     RECT  57.053 45.312 57.521 45.336 ;
     RECT  57.481 20.88 57.565 20.904 ;
     RECT  57.193 23.76 57.587 23.784 ;
     RECT  57.251 37.008 57.593 37.032 ;
     RECT  57.548 38.688 57.635 39.096 ;
     RECT  56.924 32.352 57.661 32.376 ;
     RECT  57.596 42.192 57.683 42.216 ;
     RECT  57.193 25.248 57.773 25.368 ;
     RECT  57.661 32.304 57.805 32.376 ;
     RECT  57.805 32.016 57.877 32.376 ;
     RECT  57.836 29.232 57.923 29.256 ;
     RECT  57.341 19.344 57.953 19.512 ;
     RECT  57.773 25.248 57.953 25.272 ;
     RECT  57.877 32.016 58.163 33.048 ;
     RECT  58.076 37.104 58.163 37.128 ;
     RECT  58.163 32.016 58.169 32.328 ;
     RECT  58.124 27.744 58.211 27.768 ;
     RECT  57.953 19.344 58.252 19.368 ;
     RECT  58.169 32.304 58.493 32.328 ;
     RECT  58.453 16.272 58.54 16.296 ;
     RECT  58.453 46.224 58.54 46.248 ;
     RECT  58.117 34.896 58.625 34.92 ;
     RECT  58.625 34.896 58.637 35.88 ;
     RECT  57.635 38.688 58.993 38.712 ;
     RECT  58.993 38.688 59.18 38.952 ;
     RECT  58.813 42.72 59.18 42.744 ;
     RECT  58.837 24.336 59.269 24.36 ;
     RECT  59.281 23.04 59.461 23.064 ;
     RECT  59.245 26.208 59.461 26.232 ;
     RECT  59.461 23.04 59.489 23.16 ;
     RECT  59.269 24.336 59.489 24.792 ;
     RECT  58.637 35.856 59.509 35.88 ;
     RECT  59.18 38.16 59.509 38.952 ;
     RECT  59.489 13.968 59.648 13.992 ;
     RECT  59.345 17.04 59.648 17.064 ;
     RECT  58.625 18.144 59.648 18.168 ;
     RECT  59.036 20.784 59.648 20.808 ;
     RECT  58.885 21.936 59.648 21.96 ;
     RECT  59.489 23.04 59.648 24.792 ;
     RECT  59.461 25.776 59.648 26.232 ;
     RECT  59.509 28.416 59.648 28.44 ;
     RECT  59.269 33.024 59.648 33.048 ;
     RECT  59.509 35.856 59.648 38.952 ;
     RECT  59.18 42.048 59.648 42.744 ;
     RECT  58.345 44.352 59.648 44.376 ;
     RECT  58.693 45.552 59.648 45.576 ;
     RECT  59.648 0.528 59.752 64.272 ;
     RECT  59.752 0.798 59.944 64.002 ;
     RECT  59.944 22.848 60.041 23.16 ;
     RECT  59.944 32.208 60.083 32.328 ;
     RECT  60.041 23.04 60.113 23.16 ;
     RECT  59.944 27.696 60.124 27.864 ;
     RECT  60.083 32.304 60.185 32.328 ;
     RECT  60.113 23.136 60.221 23.16 ;
     RECT  59.944 45.552 60.293 45.576 ;
     RECT  59.944 18.72 60.329 18.936 ;
     RECT  59.944 35.424 60.371 36.312 ;
     RECT  59.944 15.36 60.419 15.384 ;
     RECT  59.944 30.48 60.419 30.504 ;
     RECT  59.944 40.272 60.419 40.296 ;
     RECT  59.944 20.496 60.437 20.52 ;
     RECT  60.124 27.696 60.689 27.72 ;
     RECT  59.944 38.16 60.689 38.472 ;
     RECT  60.689 38.16 60.899 38.184 ;
     RECT  59.944 25.344 60.937 25.752 ;
     RECT  59.944 41.616 60.941 42.216 ;
     RECT  60.937 25.344 61.009 25.848 ;
     RECT  60.371 35.424 61.049 35.88 ;
     RECT  60.973 27.312 61.085 27.624 ;
     RECT  59.944 33.792 61.117 33.816 ;
     RECT  61.009 25.344 61.141 25.992 ;
     RECT  60.329 18.72 61.189 18.792 ;
     RECT  61.141 25.344 61.193 26.136 ;
     RECT  61.193 25.824 61.228 26.136 ;
     RECT  61.189 18.432 61.276 18.792 ;
     RECT  61.117 33.792 61.331 34.056 ;
     RECT  60.941 41.616 61.34 41.688 ;
     RECT  61.049 35.856 61.369 35.88 ;
     RECT  61.285 32.448 61.372 32.472 ;
     RECT  61.085 27.312 61.373 27.336 ;
     RECT  59.944 21.648 61.409 21.672 ;
     RECT  61.34 40.8 61.427 41.688 ;
     RECT  61.228 25.824 61.481 25.992 ;
     RECT  61.331 33.792 61.517 33.816 ;
     RECT  61.436 30.72 61.523 30.744 ;
     RECT  61.369 35.856 61.571 36.792 ;
     RECT  61.276 18.72 61.573 18.792 ;
     RECT  61.225 23.328 61.625 23.352 ;
     RECT  61.481 25.968 61.625 25.992 ;
     RECT  61.573 18.72 61.733 19.512 ;
     RECT  61.427 41.664 61.769 41.688 ;
     RECT  61.724 38.64 61.811 38.664 ;
     RECT  61.573 15.456 61.841 15.48 ;
     RECT  61.772 42.72 61.859 42.744 ;
     RECT  61.729 16.896 61.861 16.92 ;
     RECT  61.813 37.296 61.9 37.416 ;
     RECT  61.861 16.896 61.948 17.016 ;
     RECT  61.948 16.896 62.165 16.92 ;
     RECT  61.9 37.296 62.173 37.32 ;
     RECT  62.149 33.024 62.236 33.048 ;
     RECT  62.3 43.248 62.387 43.272 ;
     RECT  62.389 41.328 62.476 41.352 ;
     RECT  62.492 25.056 62.579 25.08 ;
     RECT  62.581 32.448 62.668 32.472 ;
     RECT  62.197 35.28 62.669 35.304 ;
     RECT  62.588 27.792 62.675 27.816 ;
     RECT  62.588 37.008 62.675 37.032 ;
     RECT  61.733 18.72 62.705 18.792 ;
     RECT  62.725 31.392 62.812 31.416 ;
     RECT  62.809 38.736 62.921 38.76 ;
     RECT  62.725 39.984 62.921 40.008 ;
     RECT  62.876 20.016 62.963 20.04 ;
     RECT  62.705 18.768 63.093 18.792 ;
     RECT  63.109 36.288 63.196 36.312 ;
     RECT  62.773 45.408 63.205 45.432 ;
     RECT  63.205 44.976 63.251 45.432 ;
     RECT  63.253 25.92 63.353 25.944 ;
     RECT  63.253 38.112 63.353 38.136 ;
     RECT  63.301 34.992 63.389 35.016 ;
     RECT  63.349 42.72 63.436 42.744 ;
     RECT  63.251 44.976 63.677 45 ;
     RECT  63.241 23.328 63.713 23.352 ;
     RECT  63.685 35.616 63.772 35.64 ;
    LAYER M5 ;
     RECT  53.232 0.053 53.256 0.144 ;
     RECT  55.296 0.037 55.32 0.144 ;
     RECT  23.328 0.144 23.448 0.227 ;
     RECT  47.856 0.144 47.976 0.227 ;
     RECT  55.296 0.144 55.704 0.227 ;
     RECT  53.088 0.144 53.256 0.235 ;
     RECT  15.36 0.144 16.728 0.277 ;
     RECT  42.336 0.144 43.128 0.517 ;
     RECT  47.952 0.227 47.976 0.517 ;
     RECT  0.24 0.517 0.36 0.787 ;
     RECT  5.64 0.517 5.76 0.787 ;
     RECT  11.04 0.517 11.16 0.787 ;
     RECT  21.84 0.517 21.96 0.787 ;
     RECT  27.24 0.517 27.36 0.787 ;
     RECT  32.64 0.517 32.76 0.787 ;
     RECT  38.04 0.517 38.16 0.787 ;
     RECT  42.336 0.517 43.56 0.787 ;
     RECT  47.952 0.517 48.96 0.787 ;
     RECT  59.64 0.517 59.76 0.787 ;
     RECT  47.952 0.787 49.152 0.805 ;
     RECT  47.952 0.805 49.272 0.889 ;
     RECT  15.36 0.277 16.872 1.187 ;
     RECT  23.424 0.227 23.448 1.187 ;
     RECT  47.952 0.889 49.152 1.187 ;
     RECT  15.408 1.187 16.872 1.331 ;
     RECT  42.336 0.787 43.752 1.331 ;
     RECT  16.44 1.331 16.872 1.363 ;
     RECT  32.64 0.787 32.952 1.381 ;
     RECT  21.84 0.787 22.152 1.397 ;
     RECT  32.448 1.381 32.952 1.397 ;
     RECT  35.904 1.285 35.928 1.397 ;
     RECT  16.44 1.363 17.304 1.451 ;
     RECT  18.528 1.363 18.552 1.451 ;
     RECT  35.904 1.397 36.024 1.451 ;
     RECT  19.968 1.391 19.992 1.475 ;
     RECT  42.192 1.391 42.216 1.475 ;
     RECT  34.272 1.397 34.296 1.485 ;
     RECT  32.352 1.397 32.952 1.523 ;
     RECT  36 1.451 36.024 1.523 ;
     RECT  21.744 1.397 22.152 1.571 ;
     RECT  27.24 0.787 27.552 1.813 ;
     RECT  26.064 1.669 26.088 1.957 ;
     RECT  29.664 1.429 29.688 1.973 ;
     RECT  27.24 1.813 27.672 2.027 ;
     RECT  29.088 1.973 29.688 2.027 ;
     RECT  15.408 1.331 15.432 2.041 ;
     RECT  26.064 1.957 26.232 2.041 ;
     RECT  26.064 2.041 26.088 2.091 ;
     RECT  20.448 2.037 20.472 2.125 ;
     RECT  48.84 1.187 49.152 2.259 ;
     RECT  29.088 2.027 29.112 2.339 ;
     RECT  43.44 1.331 43.752 2.533 ;
     RECT  44.976 2.485 45 2.569 ;
     RECT  43.44 2.533 43.896 2.821 ;
     RECT  47.184 2.485 47.208 2.867 ;
     RECT  48.384 2.259 49.152 2.867 ;
     RECT  23.904 2.725 23.928 2.915 ;
     RECT  38.04 0.787 38.352 2.975 ;
     RECT  43.344 2.821 43.896 3.051 ;
     RECT  37.584 2.975 38.352 3.059 ;
     RECT  38.04 3.059 38.352 3.061 ;
     RECT  39.936 2.869 39.96 3.115 ;
     RECT  38.04 3.061 38.76 3.145 ;
     RECT  21.84 1.571 22.152 3.205 ;
     RECT  17.856 3.283 17.88 3.371 ;
     RECT  21.84 3.205 22.584 3.371 ;
     RECT  43.44 3.051 43.896 3.395 ;
     RECT  21.84 3.371 22.152 3.411 ;
     RECT  20.016 3.411 20.04 3.499 ;
     RECT  21.6 3.411 22.152 3.499 ;
     RECT  35.904 3.397 35.928 3.499 ;
     RECT  34.272 3.445 34.296 3.539 ;
     RECT  14.208 3.589 14.232 3.691 ;
     RECT  15.264 3.301 15.288 3.691 ;
     RECT  29.088 3.509 29.112 3.691 ;
     RECT  46.752 3.877 46.776 3.961 ;
     RECT  45.312 3.893 45.336 3.981 ;
     RECT  23.904 3.935 23.928 4.019 ;
     RECT  16.44 1.451 16.752 4.179 ;
     RECT  38.04 3.145 38.352 4.213 ;
     RECT  16.44 4.179 17.592 4.267 ;
     RECT  37.008 4.405 37.032 4.489 ;
     RECT  39.888 4.405 39.912 4.489 ;
     RECT  25.728 2.549 25.752 4.499 ;
     RECT  41.04 4.405 41.064 4.499 ;
     RECT  11.04 0.787 11.352 4.533 ;
     RECT  38.04 4.213 38.856 4.587 ;
     RECT  30.768 4.511 30.792 4.595 ;
     RECT  10.608 4.533 11.352 4.819 ;
     RECT  10.368 4.819 11.352 4.907 ;
     RECT  32.64 1.523 32.952 4.981 ;
     RECT  5.64 0.787 5.952 5.029 ;
     RECT  48.84 2.867 49.152 5.029 ;
     RECT  45.792 5.011 45.816 5.099 ;
     RECT  48.048 5.029 49.152 5.113 ;
     RECT  5.64 5.029 6.6 5.163 ;
     RECT  3.408 5.087 3.432 5.171 ;
     RECT  21.84 3.499 22.152 5.173 ;
     RECT  18.144 5.077 18.168 5.227 ;
     RECT  19.152 5.139 19.176 5.227 ;
     RECT  21.84 5.173 23.112 5.355 ;
     RECT  27.24 2.027 27.552 5.509 ;
     RECT  28.992 5.029 29.016 5.509 ;
     RECT  10.608 4.907 11.352 5.587 ;
     RECT  10.608 5.587 11.592 5.675 ;
     RECT  18.384 5.587 18.408 5.675 ;
     RECT  13.104 5.605 13.128 5.689 ;
     RECT  19.44 5.605 19.464 5.689 ;
     RECT  38.04 4.587 38.352 5.715 ;
     RECT  35.76 5.221 35.784 5.739 ;
     RECT  34.176 5.663 34.2 5.747 ;
     RECT  32.64 4.981 33.048 5.795 ;
     RECT  37.056 5.715 38.568 5.803 ;
     RECT  43.44 3.395 43.752 5.807 ;
     RECT  45.984 5.779 46.008 5.867 ;
     RECT  42.72 5.807 43.752 5.891 ;
     RECT  21.84 5.355 22.152 6.047 ;
     RECT  10.608 5.675 11.352 6.059 ;
     RECT  10.848 6.059 11.352 6.073 ;
     RECT  21.12 6.047 22.152 6.131 ;
     RECT  32.64 5.795 32.952 6.229 ;
     RECT  5.64 5.163 5.952 6.261 ;
     RECT  8.688 5.845 8.712 6.261 ;
     RECT  38.04 5.803 38.568 6.261 ;
     RECT  8.112 6.261 8.712 6.275 ;
     RECT  40.56 6.133 40.584 6.275 ;
     RECT  27.24 5.509 29.016 6.277 ;
     RECT  5.64 6.261 6.552 6.563 ;
     RECT  21.84 6.131 22.152 6.661 ;
     RECT  43.44 5.891 43.752 6.739 ;
     RECT  44.784 6.613 44.808 6.739 ;
     RECT  25.44 5.301 25.464 6.767 ;
     RECT  8.112 6.275 8.136 6.827 ;
     RECT  43.44 6.739 44.808 6.827 ;
     RECT  24.528 6.767 25.464 6.829 ;
     RECT  26.784 6.277 29.016 6.837 ;
     RECT  32.544 6.229 32.952 6.837 ;
     RECT  21.84 6.661 23.016 6.851 ;
     RECT  24.528 6.829 25.416 6.851 ;
     RECT  38.04 6.261 39.336 6.851 ;
     RECT  25.392 6.851 25.416 6.891 ;
     RECT  18 6.837 18.024 6.925 ;
     RECT  26.544 6.837 29.016 7.139 ;
     RECT  43.44 6.827 43.752 7.343 ;
     RECT  21.84 6.851 22.152 7.349 ;
     RECT  20.016 7.141 20.04 7.403 ;
     RECT  27.24 7.139 29.016 7.403 ;
     RECT  32.544 6.837 33.048 7.403 ;
     RECT  13.632 7.333 13.656 7.417 ;
     RECT  42.72 7.343 43.752 7.427 ;
     RECT  21.744 7.349 22.152 7.437 ;
     RECT  18.144 7.391 18.168 7.475 ;
     RECT  48.84 5.113 49.152 7.635 ;
     RECT  27.24 7.403 27.672 7.723 ;
     RECT  48 7.635 49.152 7.723 ;
     RECT  48.84 7.723 49.152 7.765 ;
     RECT  38.04 6.851 38.352 7.891 ;
     RECT  5.64 6.563 5.952 7.967 ;
     RECT  12.768 7.891 12.792 7.979 ;
     RECT  38.04 7.891 38.616 7.979 ;
     RECT  31.344 7.909 31.368 7.993 ;
     RECT  5.52 7.967 6.888 8.051 ;
     RECT  8.112 7.967 8.136 8.051 ;
     RECT  25.344 8.117 25.368 8.205 ;
     RECT  29.28 7.669 29.304 8.291 ;
     RECT  0.24 0.787 0.552 8.309 ;
     RECT  2.928 8.293 2.952 8.377 ;
     RECT  11.04 6.073 11.352 8.403 ;
     RECT  0.24 8.309 1.272 8.435 ;
     RECT  45.792 8.293 45.816 8.467 ;
     RECT  10.512 8.403 11.352 8.491 ;
     RECT  45.792 8.467 46.296 8.555 ;
     RECT  48.84 7.765 50.136 8.579 ;
     RECT  43.44 7.427 43.752 8.693 ;
     RECT  45.792 8.555 45.816 8.693 ;
     RECT  16.44 4.267 16.752 8.735 ;
     RECT  45.072 8.693 45.816 8.747 ;
     RECT  43.44 8.693 44.04 8.781 ;
     RECT  16.44 8.735 17.64 8.787 ;
     RECT  15.696 8.787 17.64 8.819 ;
     RECT  15.696 8.819 16.752 8.875 ;
     RECT  5.52 8.051 5.952 8.885 ;
     RECT  32.544 7.403 32.952 9.013 ;
     RECT  5.136 8.885 5.952 9.067 ;
     RECT  3.84 8.851 3.864 9.145 ;
     RECT  43.44 8.781 43.848 9.269 ;
     RECT  21.84 7.437 22.152 9.333 ;
     RECT  43.152 9.269 43.848 9.357 ;
     RECT  27.24 7.723 27.552 9.461 ;
     RECT  21.072 9.333 22.152 9.491 ;
     RECT  25.104 9.333 25.128 9.491 ;
     RECT  38.04 7.979 38.352 9.503 ;
     RECT  26.352 9.461 27.552 9.549 ;
     RECT  32.544 9.013 33.048 9.579 ;
     RECT  38.04 9.503 38.472 9.587 ;
     RECT  20.784 9.525 20.808 9.613 ;
     RECT  45.072 8.747 45.096 9.643 ;
     RECT  32.64 9.579 33.048 9.683 ;
     RECT  29.664 9.717 29.688 9.827 ;
     RECT  24.624 10.003 24.648 10.091 ;
     RECT  45.12 10.069 45.576 10.155 ;
     RECT  5.64 9.067 5.952 10.195 ;
     RECT  8.016 9.349 8.04 10.195 ;
     RECT  45.12 10.155 45.144 10.219 ;
     RECT  7.584 10.195 8.04 10.229 ;
     RECT  5.64 10.195 6.072 10.283 ;
     RECT  7.584 10.229 8.664 10.283 ;
     RECT  48.84 8.579 49.152 10.323 ;
     RECT  46.752 10.069 46.776 10.357 ;
     RECT  54.24 0.517 54.552 10.357 ;
     RECT  48.84 10.323 49.896 10.411 ;
     RECT  27.24 9.549 27.552 10.485 ;
     RECT  16.44 8.875 16.752 10.501 ;
     RECT  16.44 10.501 17.448 10.515 ;
     RECT  48.84 10.411 49.152 10.549 ;
     RECT  38.04 9.587 38.352 10.579 ;
     RECT  27.24 10.485 28.152 10.595 ;
     RECT  8.64 10.283 8.664 10.603 ;
     RECT  15.936 10.515 17.448 10.603 ;
     RECT  53.376 10.357 54.552 10.603 ;
     RECT  11.04 8.491 11.352 10.632 ;
     RECT  46.752 10.357 47.112 10.645 ;
     RECT  46.752 10.645 47.304 10.677 ;
     RECT  46.128 10.677 47.304 10.731 ;
     RECT  46.128 10.731 46.152 10.765 ;
     RECT  14.64 10.453 14.664 10.795 ;
     RECT  16.44 10.603 17.448 10.805 ;
     RECT  21.84 9.491 22.152 10.805 ;
     RECT  13.248 10.741 13.272 10.825 ;
     RECT  5.64 10.283 5.952 10.869 ;
     RECT  41.568 10.677 41.592 10.883 ;
     RECT  21.696 10.805 22.152 10.893 ;
     RECT  25.728 10.805 25.752 10.893 ;
     RECT  38.04 10.579 38.472 10.899 ;
     RECT  3.936 10.847 3.96 10.931 ;
     RECT  29.136 10.485 29.16 10.931 ;
     RECT  43.44 9.357 43.848 10.933 ;
     RECT  5.232 10.869 5.952 10.957 ;
     RECT  34.656 10.885 34.68 10.987 ;
     RECT  38.04 10.899 39.192 10.987 ;
     RECT  41.04 10.933 41.352 11.017 ;
     RECT  43.44 10.933 43.896 11.017 ;
     RECT  16.44 10.805 17.736 11.115 ;
     RECT  25.392 11.091 25.416 11.179 ;
     RECT  21.744 10.893 22.152 11.209 ;
     RECT  19.296 10.805 19.32 11.221 ;
     RECT  18.432 11.221 19.32 11.307 ;
     RECT  25.056 11.231 25.08 11.315 ;
     RECT  36.768 10.933 37.032 11.363 ;
     RECT  39.504 11.269 39.528 11.371 ;
     RECT  41.328 11.017 41.352 11.371 ;
     RECT  11.04 10.632 12.024 11.411 ;
     RECT  37.008 11.363 37.032 11.411 ;
     RECT  19.392 11.317 19.416 11.459 ;
     RECT  32.64 9.683 32.952 11.509 ;
     RECT  48.528 10.549 49.152 11.563 ;
     RECT  11.04 11.411 11.352 11.637 ;
     RECT  48.672 11.563 49.152 11.661 ;
     RECT  32.64 11.509 33.144 11.691 ;
     RECT  8.256 11.637 8.28 11.725 ;
     RECT  10.08 11.637 11.352 11.725 ;
     RECT  30.096 11.637 30.12 11.747 ;
     RECT  43.44 11.017 43.752 11.749 ;
     RECT  5.64 10.957 5.952 11.941 ;
     RECT  5.64 11.941 6.312 12.213 ;
     RECT  16.44 11.115 16.752 12.213 ;
     RECT  21.84 11.209 22.152 12.213 ;
     RECT  27.24 10.595 27.552 12.213 ;
     RECT  24.096 12.143 24.12 12.227 ;
     RECT  4.464 12.213 6.312 12.267 ;
     RECT  2.976 12.213 3 12.301 ;
     RECT  27.24 12.213 27.672 12.301 ;
     RECT  4.464 12.267 5.952 12.467 ;
     RECT  35.328 11.029 35.352 12.469 ;
     RECT  16.224 12.213 16.752 12.515 ;
     RECT  21.456 12.213 22.152 12.515 ;
     RECT  35.328 12.469 35.592 12.515 ;
     RECT  13.248 12.085 13.272 12.563 ;
     RECT  38.04 10.987 38.352 12.757 ;
     RECT  35.568 12.515 35.592 12.779 ;
     RECT  20.16 12.725 20.184 12.813 ;
     RECT  45.072 12.725 45.096 12.813 ;
     RECT  38.04 12.757 39 12.843 ;
     RECT  18.24 12.805 18.264 12.907 ;
     RECT  48.84 11.661 49.152 12.981 ;
     RECT  32.64 11.691 32.952 12.997 ;
     RECT  5.328 12.467 5.952 13.043 ;
     RECT  32.64 12.997 33.048 13.045 ;
     RECT  43.344 11.749 43.752 13.091 ;
     RECT  48 12.981 49.152 13.091 ;
     RECT  30.768 13.011 30.792 13.099 ;
     RECT  48.84 13.091 49.152 13.109 ;
     RECT  25.584 13.045 25.608 13.129 ;
     RECT  46.08 13.045 46.104 13.129 ;
     RECT  48.84 13.109 49.416 13.197 ;
     RECT  11.04 11.725 11.352 13.237 ;
     RECT  10.464 13.237 11.352 13.331 ;
     RECT  21.84 12.515 22.152 13.487 ;
     RECT  32.64 13.045 33.816 13.523 ;
     RECT  16.44 12.515 16.752 13.679 ;
     RECT  41.616 13.621 41.64 13.705 ;
     RECT  16.44 13.679 17.496 13.763 ;
     RECT  59.64 0.787 59.952 13.877 ;
     RECT  32.64 13.523 33.048 13.909 ;
     RECT  59.52 13.877 59.952 14.059 ;
     RECT  27.24 12.301 27.552 14.111 ;
     RECT  3.84 13.679 3.864 14.123 ;
     RECT  21.84 13.487 22.248 14.133 ;
     RECT  18.768 14.111 18.792 14.195 ;
     RECT  26.784 14.111 27.552 14.195 ;
     RECT  32.544 13.909 33.048 14.243 ;
     RECT  9.072 14.197 9.096 14.281 ;
     RECT  10.848 13.331 11.352 14.291 ;
     RECT  16.44 13.763 16.752 14.325 ;
     RECT  16.272 14.325 16.752 14.413 ;
     RECT  24.672 14.355 24.696 14.443 ;
     RECT  21.84 14.133 22.92 14.571 ;
     RECT  21.84 14.571 22.776 14.579 ;
     RECT  0.24 8.435 0.552 14.739 ;
     RECT  0.24 14.739 0.648 14.827 ;
     RECT  20.496 14.725 20.52 14.827 ;
     RECT  21.84 14.579 22.488 14.827 ;
     RECT  40.32 14.739 40.344 14.827 ;
     RECT  38.04 12.843 38.352 14.831 ;
     RECT  23.952 14.773 23.976 14.857 ;
     RECT  43.44 13.091 43.752 14.869 ;
     RECT  42.768 14.869 43.752 14.879 ;
     RECT  45.024 14.485 45.048 14.879 ;
     RECT  38.04 14.831 38.472 14.915 ;
     RECT  46.752 14.831 46.776 14.915 ;
     RECT  13.536 14.837 13.56 14.925 ;
     RECT  42.768 14.879 45.048 14.955 ;
     RECT  43.44 14.955 45.048 14.963 ;
     RECT  54.24 10.603 54.552 15.205 ;
     RECT  21.84 14.827 22.248 15.275 ;
     RECT  19.392 15.061 19.416 15.285 ;
     RECT  59.64 14.059 59.952 15.349 ;
     RECT  56.112 15.315 56.136 15.403 ;
     RECT  19.392 15.285 19.464 15.407 ;
     RECT  48.84 13.197 49.152 15.407 ;
     RECT  16.44 14.413 16.752 15.413 ;
     RECT  59.64 15.349 60.408 15.467 ;
     RECT  32.64 14.243 33.048 15.491 ;
     RECT  48 15.407 49.152 15.491 ;
     RECT  61.584 15.407 61.608 15.491 ;
     RECT  16.32 15.413 16.752 15.587 ;
     RECT  19.392 15.407 20.28 15.595 ;
     RECT  43.44 14.963 43.944 15.693 ;
     RECT  20.256 15.595 20.28 15.787 ;
     RECT  43.44 15.693 43.896 15.817 ;
     RECT  39.36 15.733 39.384 15.827 ;
     RECT  43.44 15.817 43.752 15.955 ;
     RECT  0.24 14.827 0.552 15.973 ;
     RECT  21.84 15.275 22.152 15.983 ;
     RECT  16.44 15.587 16.752 16.031 ;
     RECT  0.144 15.973 0.552 16.057 ;
     RECT  34.176 15.973 34.2 16.057 ;
     RECT  20.544 15.983 22.152 16.067 ;
     RECT  16.44 16.031 17.64 16.115 ;
     RECT  11.04 14.291 11.352 16.175 ;
     RECT  10.224 16.175 11.352 16.259 ;
     RECT  54.24 15.205 54.648 16.299 ;
     RECT  57.072 16.117 57.096 16.299 ;
     RECT  58.464 16.245 58.488 16.333 ;
     RECT  51.888 15.445 51.912 16.467 ;
     RECT  52.992 16.405 53.016 16.467 ;
     RECT  51.888 16.467 53.016 16.491 ;
     RECT  0.24 16.057 0.552 16.501 ;
     RECT  51.888 16.491 52.872 16.555 ;
     RECT  18.96 16.021 18.984 16.559 ;
     RECT  13.008 16.181 13.032 16.608 ;
     RECT  18.624 16.559 18.984 16.619 ;
     RECT  20.544 16.067 20.568 16.633 ;
     RECT  18.624 16.619 18.648 16.643 ;
     RECT  43.344 15.955 43.752 16.693 ;
     RECT  27.24 14.195 27.552 16.757 ;
     RECT  42.576 16.693 43.752 16.787 ;
     RECT  51.888 16.555 51.912 16.835 ;
     RECT  26.88 16.757 27.552 16.845 ;
     RECT  45.024 14.963 45.048 16.979 ;
     RECT  21.84 16.067 22.152 16.981 ;
     RECT  23.76 16.261 23.784 16.991 ;
     RECT  59.64 15.467 59.952 16.991 ;
     RECT  21.84 16.981 22.776 17.067 ;
     RECT  61.872 16.981 61.896 17.067 ;
     RECT  23.76 16.991 24.648 17.075 ;
     RECT  41.568 15.989 41.592 17.075 ;
     RECT  42.624 16.787 43.752 17.075 ;
     RECT  59.376 16.991 59.952 17.075 ;
     RECT  48.84 15.491 49.152 17.077 ;
     RECT  18.192 17.077 18.216 17.171 ;
     RECT  54.24 16.299 54.552 17.567 ;
     RECT  54.24 17.567 54.696 17.605 ;
     RECT  54.144 17.605 54.696 17.651 ;
     RECT  55.872 17.567 55.896 17.651 ;
     RECT  9.744 17.589 9.768 17.677 ;
     RECT  14.304 17.589 14.328 17.677 ;
     RECT  47.088 17.589 47.112 17.677 ;
     RECT  48.576 17.077 49.152 17.707 ;
     RECT  54.144 17.651 54.552 17.707 ;
     RECT  45.6 17.653 45.624 17.747 ;
     RECT  51.84 17.653 51.864 17.747 ;
     RECT  5.64 13.043 5.952 17.893 ;
     RECT  23.76 17.075 23.784 17.941 ;
     RECT  23.424 17.941 23.784 18.131 ;
     RECT  59.64 17.075 59.952 18.133 ;
     RECT  38.04 14.915 38.352 18.143 ;
     RECT  27.24 16.845 27.552 18.165 ;
     RECT  29.088 17.653 29.112 18.165 ;
     RECT  19.248 17.653 19.272 18.179 ;
     RECT  27.24 18.165 29.112 18.181 ;
     RECT  58.656 18.133 59.952 18.219 ;
     RECT  27.24 18.181 29.592 18.227 ;
     RECT  38.04 18.143 38.808 18.227 ;
     RECT  11.04 16.259 11.352 18.229 ;
     RECT  27.24 18.227 28.2 18.253 ;
     RECT  29.568 18.227 29.592 18.283 ;
     RECT  8.496 18.229 8.52 18.313 ;
     RECT  0.24 16.501 0.648 18.419 ;
     RECT  10.464 18.229 11.352 18.419 ;
     RECT  23.664 18.131 23.784 18.467 ;
     RECT  34.896 18.181 34.92 18.469 ;
     RECT  11.04 18.419 11.352 18.485 ;
     RECT  34.176 18.469 34.92 18.539 ;
     RECT  34.176 18.539 34.2 18.553 ;
     RECT  26.016 18.357 26.04 18.563 ;
     RECT  16.44 16.115 16.752 18.565 ;
     RECT  11.04 18.485 12.168 18.573 ;
     RECT  61.2 18.421 61.224 18.719 ;
     RECT  2.832 18.661 2.856 18.745 ;
     RECT  32.64 15.491 32.952 18.757 ;
     RECT  40.416 18.709 40.44 18.795 ;
     RECT  4.56 18.677 4.584 18.803 ;
     RECT  61.152 18.719 63.048 18.803 ;
     RECT  59.64 18.219 59.952 18.863 ;
     RECT  32.64 18.757 33.624 18.899 ;
     RECT  36.288 18.805 36.312 18.899 ;
     RECT  59.64 18.863 60.168 18.947 ;
     RECT  21.84 17.067 22.392 18.997 ;
     RECT  21.072 18.997 22.392 19.081 ;
     RECT  21.408 19.081 22.392 19.155 ;
     RECT  7.968 18.709 7.992 19.189 ;
     RECT  15.792 18.565 16.752 19.189 ;
     RECT  21.408 19.155 22.488 19.219 ;
     RECT  27.24 18.253 27.552 19.219 ;
     RECT  48.84 17.707 49.152 19.219 ;
     RECT  7.392 19.189 7.992 19.273 ;
     RECT  15.456 19.189 16.752 19.273 ;
     RECT  41.088 19.189 41.112 19.283 ;
     RECT  21.408 19.219 22.584 19.307 ;
     RECT  48.84 19.219 49.272 19.307 ;
     RECT  15.36 19.285 15.384 19.371 ;
     RECT  61.2 18.803 61.608 19.371 ;
     RECT  27.24 19.219 27.672 19.381 ;
     RECT  43.44 17.075 43.752 19.381 ;
     RECT  48.84 19.307 49.152 19.381 ;
     RECT  54.24 17.707 54.552 19.381 ;
     RECT  58.176 19.317 58.2 19.405 ;
     RECT  54.24 19.381 54.648 19.475 ;
     RECT  55.68 19.381 55.704 19.523 ;
     RECT  61.584 19.371 61.608 19.563 ;
     RECT  43.44 19.381 43.896 19.571 ;
     RECT  5.64 17.893 6.072 19.621 ;
     RECT  7.968 19.273 7.992 19.669 ;
     RECT  18.816 19.669 18.84 19.701 ;
     RECT  5.64 19.621 6.84 19.705 ;
     RECT  7.968 19.669 8.52 19.755 ;
     RECT  17.856 19.701 18.84 19.755 ;
     RECT  32.64 18.899 32.952 19.765 ;
     RECT  17.856 19.755 17.88 19.789 ;
     RECT  21.408 19.307 22.152 19.789 ;
     RECT  25.104 19.701 25.128 19.811 ;
     RECT  31.92 19.765 32.952 19.849 ;
     RECT  27.24 19.381 28.248 19.861 ;
     RECT  27.24 19.861 28.44 19.947 ;
     RECT  5.64 19.705 6.072 20.003 ;
     RECT  7.968 19.755 8.328 20.003 ;
     RECT  56.16 19.957 56.184 20.051 ;
     RECT  62.928 19.957 62.952 20.051 ;
     RECT  1.68 20.149 1.704 20.233 ;
     RECT  2.88 20.149 2.904 20.243 ;
     RECT  4.128 20.149 4.152 20.339 ;
     RECT  37.008 20.255 37.032 20.339 ;
     RECT  43.44 19.571 43.752 20.371 ;
     RECT  43.152 20.371 43.752 20.459 ;
     RECT  59.64 18.947 59.952 20.485 ;
     RECT  23.76 18.467 23.784 20.533 ;
     RECT  21.84 19.789 22.152 20.563 ;
     RECT  25.872 20.389 25.896 20.587 ;
     RECT  27.24 19.947 27.672 20.627 ;
     RECT  21.84 20.563 22.584 20.651 ;
     RECT  48.576 19.381 49.152 20.691 ;
     RECT  59.64 20.485 60.072 20.725 ;
     RECT  48.336 20.691 49.152 20.779 ;
     RECT  59.088 20.725 60.072 20.779 ;
     RECT  39.888 20.533 39.912 20.789 ;
     RECT  2.256 20.783 2.28 20.867 ;
     RECT  30.768 17.125 30.792 20.867 ;
     RECT  39.36 20.789 39.912 20.877 ;
     RECT  57.504 20.831 57.528 20.915 ;
     RECT  48.84 20.779 49.152 20.947 ;
     RECT  29.568 20.869 29.592 20.971 ;
     RECT  48.84 20.947 50.136 21.035 ;
     RECT  45.888 21.139 45.912 21.227 ;
     RECT  39.888 20.877 39.912 21.301 ;
     RECT  39.888 21.301 40.872 21.395 ;
     RECT  11.04 18.573 11.352 21.397 ;
     RECT  56.928 21.109 56.952 21.491 ;
     RECT  27.24 20.627 27.552 21.589 ;
     RECT  8.304 20.003 8.328 21.635 ;
     RECT  26.496 21.589 27.552 21.675 ;
     RECT  51.312 19.669 51.336 21.683 ;
     RECT  16.44 19.273 16.752 21.685 ;
     RECT  16.44 21.685 17.592 21.733 ;
     RECT  54.24 19.475 54.552 21.733 ;
     RECT  15.408 21.685 15.432 21.779 ;
     RECT  16.44 21.733 18.504 21.779 ;
     RECT  18.24 21.779 18.504 21.817 ;
     RECT  38.04 18.227 38.352 21.829 ;
     RECT  54.24 21.733 55.08 21.867 ;
     RECT  56.16 21.781 56.184 21.867 ;
     RECT  23.76 20.533 24.12 21.907 ;
     RECT  37.584 21.829 38.352 21.907 ;
     RECT  54.24 21.867 54.552 21.925 ;
     RECT  51.792 21.877 51.864 21.961 ;
     RECT  59.088 20.779 59.952 21.971 ;
     RECT  37.584 21.907 38.472 21.995 ;
     RECT  54.144 21.925 54.552 22.009 ;
     RECT  0.24 18.419 0.552 22.021 ;
     RECT  53.04 21.877 53.064 22.123 ;
     RECT  11.04 21.397 11.64 22.133 ;
     RECT  55.632 22.069 55.752 22.163 ;
     RECT  23.76 21.907 24.744 22.165 ;
     RECT  55.728 22.163 55.752 22.187 ;
     RECT  10.704 22.133 11.64 22.221 ;
     RECT  48.84 21.035 49.152 22.261 ;
     RECT  41.088 22.227 41.112 22.315 ;
     RECT  23.712 22.165 24.744 22.325 ;
     RECT  35.04 22.261 35.064 22.355 ;
     RECT  21.84 20.651 22.152 22.357 ;
     RECT  43.44 20.459 43.752 22.357 ;
     RECT  0.24 22.021 0.648 22.419 ;
     RECT  42.864 22.357 43.752 22.443 ;
     RECT  23.712 22.325 25.224 22.453 ;
     RECT  39.888 21.395 39.912 22.453 ;
     RECT  11.04 22.221 11.64 22.499 ;
     RECT  18.24 21.817 18.264 22.499 ;
     RECT  0.24 22.419 0.888 22.507 ;
     RECT  23.328 22.453 25.224 22.507 ;
     RECT  39.888 22.453 40.2 22.507 ;
     RECT  23.328 22.507 23.784 22.547 ;
     RECT  41.664 22.453 41.688 22.739 ;
     RECT  27.24 21.675 27.552 22.741 ;
     RECT  25.2 22.507 25.224 22.787 ;
     RECT  46.56 22.453 46.584 22.787 ;
     RECT  48.72 22.261 49.152 22.787 ;
     RECT  43.344 22.443 43.752 22.835 ;
     RECT  51.792 21.961 51.816 22.835 ;
     RECT  21.696 22.357 22.152 23.019 ;
     RECT  27.24 22.741 27.912 23.019 ;
     RECT  29.088 22.933 29.112 23.019 ;
     RECT  36.48 22.943 36.504 23.027 ;
     RECT  40.176 22.507 40.2 23.027 ;
     RECT  20.304 22.965 20.328 23.053 ;
     RECT  54.24 22.009 54.552 23.317 ;
     RECT  53.76 23.317 54.552 23.519 ;
     RECT  13.68 21.637 13.704 23.555 ;
     RECT  21.84 23.019 22.152 23.571 ;
     RECT  23.76 22.547 23.784 23.571 ;
     RECT  52.416 23.509 52.44 23.595 ;
     RECT  53.76 23.519 55.32 23.595 ;
     RECT  18.768 23.519 18.792 23.603 ;
     RECT  54.24 23.595 55.32 23.603 ;
     RECT  21.84 23.571 23.784 23.659 ;
     RECT  31.584 23.557 31.608 23.659 ;
     RECT  59.64 21.971 59.952 23.701 ;
     RECT  59.52 23.701 59.952 23.733 ;
     RECT  27.24 23.019 27.552 23.749 ;
     RECT  57.552 23.711 57.576 23.795 ;
     RECT  26.4 23.749 27.552 23.903 ;
     RECT  14.784 23.903 14.808 23.987 ;
     RECT  26.16 23.903 27.552 23.987 ;
     RECT  43.44 22.835 43.752 23.989 ;
     RECT  45.168 23.941 45.192 23.989 ;
     RECT  43.44 23.989 45.192 24.043 ;
     RECT  41.568 23.989 41.592 24.083 ;
     RECT  5.64 20.003 5.952 24.133 ;
     RECT  21.84 23.659 22.152 24.147 ;
     RECT  12.912 24.117 12.936 24.205 ;
     RECT  21.744 24.147 22.152 24.235 ;
     RECT  29.712 23.317 29.736 24.287 ;
     RECT  48.84 22.787 49.152 24.287 ;
     RECT  0.24 22.507 0.552 24.309 ;
     RECT  2.208 24.229 2.232 24.363 ;
     RECT  29.04 24.287 29.736 24.371 ;
     RECT  48.84 24.287 49.608 24.371 ;
     RECT  58.848 23.733 59.952 24.371 ;
     RECT  0.24 24.309 0.648 24.397 ;
     RECT  4.704 24.133 5.952 24.479 ;
     RECT  36.336 24.437 36.36 24.525 ;
     RECT  48.84 24.371 49.512 24.525 ;
     RECT  4.704 24.479 6.312 24.555 ;
     RECT  5.088 24.555 6.312 24.563 ;
     RECT  54.24 23.603 54.552 24.565 ;
     RECT  18.576 23.989 18.6 24.623 ;
     RECT  53.28 24.565 54.552 24.659 ;
     RECT  18.192 24.623 18.6 24.707 ;
     RECT  59.28 24.371 59.952 24.811 ;
     RECT  21.84 24.235 22.152 24.853 ;
     RECT  21.84 24.853 22.776 24.939 ;
     RECT  32.64 19.849 32.952 24.949 ;
     RECT  43.44 24.043 44.424 25.043 ;
     RECT  48.84 24.525 49.152 25.055 ;
     RECT  18.96 24.885 18.984 25.067 ;
     RECT  56.112 24.979 56.136 25.067 ;
     RECT  21.84 24.939 22.488 25.091 ;
     RECT  62.544 25.013 62.568 25.101 ;
     RECT  3.408 25.055 3.432 25.139 ;
     RECT  5.088 24.563 5.952 25.139 ;
     RECT  47.856 25.055 49.152 25.139 ;
     RECT  45.6 25.107 45.624 25.195 ;
     RECT  48.384 25.139 49.152 25.235 ;
     RECT  29.712 24.371 29.736 25.259 ;
     RECT  26.736 23.987 27.552 25.273 ;
     RECT  38.04 21.995 38.352 25.573 ;
     RECT  23.76 23.659 23.784 25.653 ;
     RECT  48.84 25.235 49.152 25.653 ;
     RECT  38.04 25.573 38.808 25.657 ;
     RECT  31.92 24.949 32.952 25.683 ;
     RECT  38.04 25.657 38.472 25.683 ;
     RECT  37.056 25.683 38.472 25.717 ;
     RECT  48.84 25.653 50.088 25.741 ;
     RECT  31.728 25.683 32.952 25.771 ;
     RECT  36.144 25.717 38.472 25.771 ;
     RECT  20.496 25.747 20.52 25.835 ;
     RECT  27.24 25.273 27.552 25.845 ;
     RECT  63.264 25.909 63.288 25.993 ;
     RECT  14.88 25.973 14.904 26.061 ;
     RECT  21.84 25.091 22.248 26.067 ;
     RECT  23.76 25.653 24.744 26.067 ;
     RECT  36.144 25.771 36.168 26.091 ;
     RECT  19.392 26.005 19.416 26.155 ;
     RECT  21.84 26.067 24.744 26.155 ;
     RECT  59.64 24.811 59.952 26.159 ;
     RECT  61.152 25.909 61.176 26.219 ;
     RECT  5.64 25.139 5.952 26.229 ;
     RECT  16.44 21.779 16.752 26.229 ;
     RECT  21.84 26.155 22.152 26.229 ;
     RECT  38.04 25.771 38.472 26.243 ;
     RECT  59.28 26.159 59.952 26.243 ;
     RECT  5.64 26.229 6.504 26.245 ;
     RECT  27.24 25.845 28.344 26.259 ;
     RECT  1.68 26.197 1.704 26.283 ;
     RECT  8.544 26.207 8.568 26.291 ;
     RECT  5.136 26.245 6.504 26.317 ;
     RECT  46.704 26.293 46.728 26.377 ;
     RECT  16.44 26.229 17.544 26.485 ;
     RECT  15.936 26.485 17.544 26.569 ;
     RECT  30.528 26.549 30.552 26.581 ;
     RECT  26.496 26.259 28.344 26.591 ;
     RECT  16.44 26.569 17.544 26.627 ;
     RECT  23.76 26.155 24.744 26.627 ;
     RECT  50.736 26.591 50.76 26.629 ;
     RECT  26.496 26.591 28.488 26.643 ;
     RECT  30.24 26.581 30.552 26.667 ;
     RECT  16.44 26.627 17.112 26.675 ;
     RECT  26.112 26.643 28.488 26.675 ;
     RECT  48.84 25.741 49.152 26.677 ;
     RECT  0.24 24.397 0.552 26.707 ;
     RECT  26.112 26.675 27.552 26.731 ;
     RECT  3.408 26.229 3.432 26.741 ;
     RECT  56.976 26.677 57 26.771 ;
     RECT  0.24 26.707 1.176 26.795 ;
     RECT  3.408 26.741 4.056 26.795 ;
     RECT  5.136 26.317 5.952 26.795 ;
     RECT  27.072 26.731 27.552 26.795 ;
     RECT  32.64 25.771 32.952 26.805 ;
     RECT  47.952 26.677 49.152 26.805 ;
     RECT  50.736 26.629 51.288 26.805 ;
     RECT  12.528 26.197 12.552 26.819 ;
     RECT  4.032 26.795 4.056 26.825 ;
     RECT  23.76 26.627 24.552 26.867 ;
     RECT  31.872 26.805 33.048 26.893 ;
     RECT  56.016 26.805 56.712 26.893 ;
     RECT  47.952 26.805 51.288 26.987 ;
     RECT  43.44 25.043 44.184 27.109 ;
     RECT  47.952 26.987 49.896 27.155 ;
     RECT  42.72 27.109 44.184 27.193 ;
     RECT  56.688 26.893 56.712 27.243 ;
     RECT  11.04 22.499 11.352 27.301 ;
     RECT  31.872 26.893 32.952 27.347 ;
     RECT  61.296 27.253 61.32 27.347 ;
     RECT  54.24 24.659 54.552 27.349 ;
     RECT  21.744 26.229 22.152 27.359 ;
     RECT  23.76 26.867 23.976 27.359 ;
     RECT  47.952 27.155 49.152 27.359 ;
     RECT  51.264 26.987 51.288 27.381 ;
     RECT  10.272 27.301 11.352 27.385 ;
     RECT  8.496 27.311 8.52 27.395 ;
     RECT  11.04 27.385 11.352 27.397 ;
     RECT  53.568 27.349 54.552 27.435 ;
     RECT  21.072 27.359 22.152 27.443 ;
     RECT  23.712 27.359 23.976 27.443 ;
     RECT  47.856 27.359 49.152 27.443 ;
     RECT  51.264 27.381 51.96 27.469 ;
     RECT  43.44 27.193 44.184 27.491 ;
     RECT  21.744 27.443 22.152 27.603 ;
     RECT  30.768 27.381 30.792 27.635 ;
     RECT  61.008 27.551 61.032 27.635 ;
     RECT  16.44 26.675 16.752 27.637 ;
     RECT  18.672 27.603 18.696 27.691 ;
     RECT  23.76 27.443 23.976 27.721 ;
     RECT  15.888 27.637 16.752 27.731 ;
     RECT  13.632 27.397 13.656 27.755 ;
     RECT  21.744 27.603 22.248 27.765 ;
     RECT  14.832 27.695 14.856 27.779 ;
     RECT  5.64 26.795 5.952 27.795 ;
     RECT  59.64 26.243 59.952 27.795 ;
     RECT  0.24 26.795 0.552 27.829 ;
     RECT  59.64 27.795 60.072 27.829 ;
     RECT  4.896 27.795 5.952 27.883 ;
     RECT  14.4 27.795 14.424 27.883 ;
     RECT  58.176 27.733 58.2 27.883 ;
     RECT  59.52 27.829 60.072 27.883 ;
     RECT  62.64 27.781 62.664 27.883 ;
     RECT  18.768 27.829 18.792 27.913 ;
     RECT  21.744 27.765 22.392 27.913 ;
     RECT  0.24 27.829 0.648 27.923 ;
     RECT  11.04 27.397 11.784 27.923 ;
     RECT  21.84 27.913 22.392 27.923 ;
     RECT  32.64 27.347 32.952 28.261 ;
     RECT  27.24 26.795 27.552 28.405 ;
     RECT  32.64 28.261 33.432 28.405 ;
     RECT  51.264 27.469 51.288 28.405 ;
     RECT  59.52 27.883 59.952 28.451 ;
     RECT  37.008 28.371 37.032 28.459 ;
     RECT  42.048 28.371 42.072 28.459 ;
     RECT  46.704 28.213 46.728 28.459 ;
     RECT  47.904 27.443 49.152 28.459 ;
     RECT  31.92 28.405 33.432 28.489 ;
     RECT  50.688 28.405 51.288 28.739 ;
     RECT  32.64 28.489 33.432 28.787 ;
     RECT  23.76 27.721 23.784 28.789 ;
     RECT  26.4 28.405 27.552 28.789 ;
     RECT  21.84 27.923 22.152 28.947 ;
     RECT  23.76 28.789 24.552 28.947 ;
     RECT  5.64 27.883 5.952 28.981 ;
     RECT  21.024 28.947 24.552 29.011 ;
     RECT  25.968 28.789 27.552 29.011 ;
     RECT  5.184 28.981 5.952 29.029 ;
     RECT  2.256 28.837 2.28 29.035 ;
     RECT  19.68 28.947 19.704 29.035 ;
     RECT  21.024 29.011 27.552 29.035 ;
     RECT  3.936 28.981 3.96 29.065 ;
     RECT  18.192 28.981 18.216 29.065 ;
     RECT  50.688 28.739 50.712 29.065 ;
     RECT  26.784 29.035 27.552 29.075 ;
     RECT  25.104 29.035 25.128 29.099 ;
     RECT  16.44 27.731 16.752 29.173 ;
     RECT  5.184 29.029 6.456 29.221 ;
     RECT  16.44 29.173 17.112 29.267 ;
     RECT  19.248 29.173 19.272 29.267 ;
     RECT  55.728 29.173 55.752 29.267 ;
     RECT  57.888 29.173 57.912 29.267 ;
     RECT  5.184 29.221 6.84 29.305 ;
     RECT  21.024 29.035 23.976 29.305 ;
     RECT  5.184 29.305 6.456 29.363 ;
     RECT  21.024 29.305 23.784 29.365 ;
     RECT  20.976 29.365 23.784 29.459 ;
     RECT  56.112 29.365 56.136 29.459 ;
     RECT  16.44 29.267 16.752 29.605 ;
     RECT  27.24 29.075 27.552 29.605 ;
     RECT  39.456 29.523 39.48 29.611 ;
     RECT  14.64 29.587 14.664 29.615 ;
     RECT  15.984 29.605 16.752 29.615 ;
     RECT  11.04 27.923 11.352 29.653 ;
     RECT  14.64 29.615 16.752 29.675 ;
     RECT  27.24 29.605 27.72 29.689 ;
     RECT  15.408 29.675 16.752 29.699 ;
     RECT  21.84 29.459 23.784 29.699 ;
     RECT  38.04 26.243 38.352 29.813 ;
     RECT  38.04 29.813 38.472 29.901 ;
     RECT  5.184 29.363 5.952 29.941 ;
     RECT  43.44 27.491 43.752 29.941 ;
     RECT  4.848 29.941 5.952 30.035 ;
     RECT  50.688 30.037 50.712 30.123 ;
     RECT  15.984 29.699 16.752 30.131 ;
     RECT  32.64 28.787 32.952 30.133 ;
     RECT  16.32 30.131 16.752 30.187 ;
     RECT  43.344 29.941 43.752 30.197 ;
     RECT  41.856 30.291 41.88 30.379 ;
     RECT  40.416 30.325 40.44 30.409 ;
     RECT  48.84 28.459 49.152 30.421 ;
     RECT  43.344 30.197 43.896 30.453 ;
     RECT  30.72 30.383 30.744 30.467 ;
     RECT  59.64 28.451 59.952 30.469 ;
     RECT  51.984 30.389 52.008 30.477 ;
     RECT  35.424 29.941 35.448 30.483 ;
     RECT  43.344 30.453 43.944 30.507 ;
     RECT  48.84 30.421 49.512 30.507 ;
     RECT  43.44 30.507 43.944 30.563 ;
     RECT  27.24 29.689 27.552 30.565 ;
     RECT  21.84 29.699 22.392 30.571 ;
     RECT  34.992 30.483 35.448 30.571 ;
     RECT  36.48 30.517 36.504 30.601 ;
     RECT  13.632 30.197 14.04 30.611 ;
     RECT  26.736 30.565 27.552 30.649 ;
     RECT  54.24 27.435 54.552 30.661 ;
     RECT  16.44 30.187 16.752 30.709 ;
     RECT  32.496 30.133 32.952 30.755 ;
     RECT  50.304 30.661 50.328 30.763 ;
     RECT  59.64 30.469 60.408 30.763 ;
     RECT  61.488 30.675 61.512 30.763 ;
     RECT  11.04 29.653 11.976 30.773 ;
     RECT  11.04 30.773 12.264 30.861 ;
     RECT  13.728 30.611 14.04 30.899 ;
     RECT  48.84 30.507 49.152 30.931 ;
     RECT  18.384 30.867 18.408 30.955 ;
     RECT  37.008 30.931 37.032 31.019 ;
     RECT  48.72 30.931 49.152 31.019 ;
     RECT  21.84 30.571 22.152 31.059 ;
     RECT  20.976 31.059 22.152 31.147 ;
     RECT  19.344 31.093 19.368 31.187 ;
     RECT  11.04 30.861 11.352 31.189 ;
     RECT  29.184 31.189 29.208 31.275 ;
     RECT  30.336 30.949 30.36 31.275 ;
     RECT  24.912 30.709 24.936 31.333 ;
     RECT  27.24 30.649 27.552 31.349 ;
     RECT  24.912 31.333 25.032 31.417 ;
     RECT  2.304 31.343 2.328 31.427 ;
     RECT  52.464 31.343 52.488 31.427 ;
     RECT  62.736 31.343 62.76 31.427 ;
     RECT  54.144 30.661 54.552 31.477 ;
     RECT  27.24 31.349 27.672 31.523 ;
     RECT  54.144 31.477 54.984 31.531 ;
     RECT  9.744 31.507 9.768 31.595 ;
     RECT  10.944 31.189 11.352 31.595 ;
     RECT  8.496 31.535 8.52 31.619 ;
     RECT  54.24 31.531 54.984 31.619 ;
     RECT  45.072 31.541 45.096 31.621 ;
     RECT  24.912 31.417 24.936 31.667 ;
     RECT  46.272 31.541 46.296 31.667 ;
     RECT  45.072 31.621 45.192 31.723 ;
     RECT  38.04 29.901 38.352 31.861 ;
     RECT  32.64 30.755 32.952 31.919 ;
     RECT  16.44 30.709 17.112 31.925 ;
     RECT  23.76 29.699 23.784 31.955 ;
     RECT  31.92 31.919 32.952 32.003 ;
     RECT  16.08 31.925 17.16 32.013 ;
     RECT  48.84 31.019 49.152 32.019 ;
     RECT  50.208 31.925 50.232 32.019 ;
     RECT  48.84 32.019 50.232 32.053 ;
     RECT  47.856 32.053 50.232 32.107 ;
     RECT  5.64 30.035 5.952 32.117 ;
     RECT  16.44 32.013 17.16 32.147 ;
     RECT  3.408 32.101 3.432 32.185 ;
     RECT  13.728 30.899 13.752 32.195 ;
     RECT  59.64 30.763 59.952 32.197 ;
     RECT  5.28 32.117 6.6 32.205 ;
     RECT  16.44 32.147 17.112 32.243 ;
     RECT  59.64 32.197 60.072 32.299 ;
     RECT  35.568 32.275 35.592 32.363 ;
     RECT  56.976 32.341 57 32.427 ;
     RECT  62.592 32.245 62.616 32.483 ;
     RECT  50.208 32.107 50.232 32.555 ;
     RECT  47.856 32.107 49.152 32.579 ;
     RECT  33.936 31.525 33.96 32.581 ;
     RECT  30.528 32.565 31.368 32.629 ;
     RECT  41.904 31.919 41.928 32.629 ;
     RECT  32.352 32.003 32.952 32.725 ;
     RECT  33.936 32.581 34.68 32.725 ;
     RECT  43.44 30.563 43.752 32.725 ;
     RECT  30.48 32.629 31.368 32.771 ;
     RECT  46.176 32.687 46.2 32.771 ;
     RECT  41.52 32.629 41.928 32.773 ;
     RECT  43.344 32.725 43.752 32.773 ;
     RECT  41.52 32.773 44.04 32.787 ;
     RECT  32.352 32.725 34.68 32.811 ;
     RECT  35.808 32.725 36.408 32.811 ;
     RECT  38.04 31.861 38.52 32.821 ;
     RECT  18.96 32.787 18.984 32.875 ;
     RECT  29.04 32.595 29.064 32.875 ;
     RECT  35.808 32.811 36.072 32.875 ;
     RECT  40.608 32.787 44.04 32.875 ;
     RECT  38.04 32.821 39.336 32.905 ;
     RECT  59.64 32.299 59.952 32.979 ;
     RECT  61.296 32.437 61.32 32.979 ;
     RECT  42.72 32.875 44.04 33.003 ;
     RECT  30.528 32.771 31.368 33.013 ;
     RECT  32.352 32.811 34.632 33.013 ;
     RECT  30.528 33.013 34.632 33.067 ;
     RECT  41.52 32.875 41.544 33.067 ;
     RECT  59.28 32.979 59.952 33.067 ;
     RECT  61.296 32.979 62.184 33.067 ;
     RECT  54.24 31.619 54.552 33.077 ;
     RECT  30.528 33.067 33.864 33.097 ;
     RECT  58.128 33.013 58.152 33.097 ;
     RECT  30.528 33.097 31.368 33.107 ;
     RECT  32.64 33.097 33.864 33.195 ;
     RECT  5.64 32.205 5.952 33.235 ;
     RECT  27.24 31.523 27.552 33.235 ;
     RECT  38.04 32.905 38.352 33.253 ;
     RECT  37.584 33.253 38.352 33.269 ;
     RECT  54.144 33.077 54.552 33.299 ;
     RECT  4.848 33.235 5.952 33.323 ;
     RECT  48.528 32.579 49.152 33.323 ;
     RECT  25.008 33.269 25.032 33.357 ;
     RECT  28.56 33.269 28.584 33.357 ;
     RECT  35.808 32.875 35.832 33.357 ;
     RECT  37.056 33.269 38.352 33.395 ;
     RECT  59.64 33.067 59.952 33.747 ;
     RECT  61.296 33.067 61.32 33.747 ;
     RECT  26.928 33.235 27.552 33.781 ;
     RECT  26.928 33.781 28.152 33.811 ;
     RECT  59.64 33.747 61.32 33.835 ;
     RECT  50.784 33.829 50.808 33.845 ;
     RECT  26.832 33.811 28.152 33.899 ;
     RECT  46.704 33.839 46.728 33.923 ;
     RECT  61.296 33.835 61.32 34.067 ;
     RECT  48.72 33.323 49.152 34.115 ;
     RECT  50.784 33.845 51.384 34.115 ;
     RECT  32.64 33.195 32.952 34.213 ;
     RECT  37.728 33.395 38.352 34.357 ;
     RECT  30.528 33.107 30.552 34.463 ;
     RECT  34.8 34.415 34.824 34.499 ;
     RECT  42.432 34.323 42.456 34.539 ;
     RECT  43.44 33.003 44.04 34.579 ;
     RECT  32.64 34.213 33.096 34.645 ;
     RECT  43.152 34.579 44.04 34.667 ;
     RECT  30.528 34.463 30.696 34.677 ;
     RECT  32.448 34.645 33.096 34.693 ;
     RECT  35.856 34.613 35.88 34.739 ;
     RECT  5.64 33.323 5.952 34.741 ;
     RECT  4.032 34.501 4.056 34.787 ;
     RECT  42.096 34.707 42.12 34.795 ;
     RECT  5.136 34.741 5.952 34.799 ;
     RECT  29.712 34.677 30.696 34.805 ;
     RECT  8.544 33.589 8.568 34.835 ;
     RECT  5.136 34.799 6.312 34.859 ;
     RECT  5.64 34.859 6.312 34.883 ;
     RECT  21.84 31.147 22.152 34.899 ;
     RECT  32.112 34.693 33.096 34.899 ;
     RECT  56.88 34.741 56.904 34.923 ;
     RECT  29.52 34.805 30.744 34.931 ;
     RECT  58.128 34.847 58.152 34.931 ;
     RECT  32.064 34.899 33.096 34.933 ;
     RECT  37.632 34.357 38.352 34.933 ;
     RECT  18.768 34.741 18.792 34.987 ;
     RECT  20.208 34.899 20.232 34.987 ;
     RECT  30.048 34.931 30.744 34.987 ;
     RECT  32.064 34.933 33.288 34.987 ;
     RECT  63.312 34.963 63.336 35.051 ;
     RECT  32.64 34.987 33.288 35.123 ;
     RECT  43.44 34.667 44.04 35.125 ;
     RECT  45.024 34.741 45.048 35.125 ;
     RECT  3.936 35.061 3.96 35.171 ;
     RECT  30.048 34.987 30.12 35.179 ;
     RECT  31.104 35.077 31.128 35.179 ;
     RECT  43.44 35.125 45.048 35.209 ;
     RECT  24.432 34.453 24.456 35.221 ;
     RECT  37.536 34.933 38.352 35.253 ;
     RECT  24.432 35.221 25.128 35.307 ;
     RECT  32.64 35.123 33.048 35.307 ;
     RECT  51.936 34.165 51.96 35.307 ;
     RECT  26.88 33.899 28.152 35.317 ;
     RECT  39.36 34.997 39.384 35.317 ;
     RECT  50.784 34.115 50.808 35.317 ;
     RECT  36.864 35.253 38.352 35.341 ;
     RECT  39.36 35.317 41.016 35.341 ;
     RECT  45.024 35.209 45.048 35.363 ;
     RECT  26.88 35.317 28.248 35.381 ;
     RECT  37.488 35.341 38.352 35.411 ;
     RECT  40.032 35.341 41.016 35.411 ;
     RECT  24.432 35.307 24.456 35.435 ;
     RECT  57.12 35.423 57.144 35.507 ;
     RECT  54.24 33.299 54.552 35.509 ;
     RECT  2.16 35.475 2.184 35.563 ;
     RECT  26.352 35.381 28.248 35.651 ;
     RECT  48.84 34.115 49.152 35.749 ;
     RECT  50.256 35.317 50.808 35.749 ;
     RECT  26.352 35.651 28.152 35.755 ;
     RECT  40.512 35.411 40.536 35.819 ;
     RECT  48.84 35.749 50.808 35.819 ;
     RECT  59.64 33.835 59.952 35.829 ;
     RECT  48.84 35.819 50.136 35.833 ;
     RECT  21.84 34.899 22.44 35.845 ;
     RECT  34.464 34.741 34.488 35.845 ;
     RECT  38.04 35.411 38.352 35.845 ;
     RECT  59.64 35.829 61.56 35.845 ;
     RECT  52.368 35.765 52.392 35.853 ;
     RECT  4.128 35.797 4.152 35.883 ;
     RECT  63.696 35.605 63.72 35.883 ;
     RECT  58.656 35.845 61.56 35.917 ;
     RECT  26.352 35.755 27.912 35.939 ;
     RECT  30.096 35.179 30.12 35.951 ;
     RECT  54.24 35.509 54.696 35.951 ;
     RECT  26.736 35.939 27.912 35.987 ;
     RECT  43.44 35.209 43.944 35.987 ;
     RECT  21.84 35.845 22.776 35.989 ;
     RECT  30.096 35.951 30.936 36.011 ;
     RECT  38.04 35.845 38.52 36.011 ;
     RECT  36.144 35.941 36.168 36.021 ;
     RECT  35.472 36.021 36.168 36.025 ;
     RECT  30.144 36.011 30.936 36.035 ;
     RECT  53.424 35.951 55.32 36.035 ;
     RECT  48.84 35.833 49.152 36.037 ;
     RECT  21.84 35.989 23.448 36.075 ;
     RECT  35.472 36.025 35.496 36.109 ;
     RECT  48.72 36.037 49.152 36.139 ;
     RECT  18.768 36.143 18.792 36.227 ;
     RECT  58.656 35.917 60.36 36.267 ;
     RECT  47.616 36.213 47.64 36.301 ;
     RECT  59.52 36.267 60.36 36.331 ;
     RECT  63.12 36.243 63.144 36.331 ;
     RECT  32.64 35.307 32.952 36.373 ;
     RECT  12.384 36.373 13.08 36.459 ;
     RECT  32.64 36.373 33.24 36.459 ;
     RECT  38.04 36.011 38.472 36.459 ;
     RECT  47.52 36.373 47.544 36.459 ;
     RECT  53.136 36.373 53.16 36.459 ;
     RECT  43.44 35.987 43.752 36.469 ;
     RECT  14.256 36.405 14.28 36.515 ;
     RECT  34.224 35.845 34.488 36.523 ;
     RECT  43.344 36.469 43.752 36.553 ;
     RECT  24.624 36.469 24.648 36.563 ;
     RECT  5.64 34.883 5.952 36.613 ;
     RECT  34.32 36.523 34.488 36.719 ;
     RECT  54.24 36.035 55.176 36.779 ;
     RECT  34.32 36.719 35.352 36.803 ;
     RECT  61.536 35.917 61.56 36.803 ;
     RECT  57.216 36.725 57.24 36.813 ;
     RECT  5.52 36.613 5.952 36.819 ;
     RECT  54.24 36.779 54.744 36.851 ;
     RECT  5.52 36.819 6.792 36.907 ;
     RECT  7.968 36.853 7.992 36.937 ;
     RECT  38.04 36.459 38.352 36.959 ;
     RECT  37.584 36.959 38.352 36.997 ;
     RECT  30.144 36.035 30.168 37.011 ;
     RECT  14.064 36.949 14.088 37.035 ;
     RECT  29.808 37.011 30.168 37.035 ;
     RECT  62.64 36.981 62.664 37.069 ;
     RECT  43.44 36.553 43.752 37.075 ;
     RECT  46.032 35.957 46.056 37.075 ;
     RECT  29.808 37.035 29.832 37.099 ;
     RECT  39.552 37.045 39.576 37.109 ;
     RECT  46.032 37.075 46.152 37.109 ;
     RECT  50.352 37.045 50.376 37.109 ;
     RECT  43.44 37.075 44.472 37.163 ;
     RECT  45.744 37.109 46.152 37.163 ;
     RECT  52.512 37.075 52.536 37.163 ;
     RECT  50.352 37.109 50.472 37.203 ;
     RECT  36.768 36.997 38.352 37.237 ;
     RECT  50.256 37.203 50.472 37.283 ;
     RECT  36.432 37.237 38.352 37.291 ;
     RECT  43.44 37.163 44.376 37.291 ;
     RECT  45.744 37.163 45.864 37.291 ;
     RECT  50.256 37.283 50.376 37.291 ;
     RECT  54.24 36.851 54.696 37.331 ;
     RECT  61.824 37.285 62.136 37.369 ;
     RECT  11.04 31.595 11.352 37.395 ;
     RECT  39.552 37.109 39.768 37.395 ;
     RECT  58.128 37.093 58.152 37.419 ;
     RECT  50.352 37.291 50.376 37.427 ;
     RECT  26.736 35.987 27.552 37.429 ;
     RECT  37.632 37.291 38.352 37.429 ;
     RECT  39.408 37.395 39.768 37.429 ;
     RECT  61.824 37.369 61.848 37.453 ;
     RECT  37.632 37.429 39.768 37.477 ;
     RECT  2.256 37.395 2.28 37.483 ;
     RECT  10.896 37.395 11.352 37.483 ;
     RECT  9.648 37.429 9.672 37.513 ;
     RECT  37.632 37.477 39.864 37.561 ;
     RECT  37.632 37.561 39.576 37.581 ;
     RECT  37.632 37.581 38.76 37.611 ;
     RECT  26.304 37.429 28.536 37.813 ;
     RECT  34.32 36.803 34.776 37.813 ;
     RECT  32.64 36.459 32.952 37.919 ;
     RECT  26.304 37.813 29.016 38.003 ;
     RECT  32.64 37.919 33.048 38.003 ;
     RECT  21.84 36.075 22.152 38.005 ;
     RECT  25.008 37.557 25.032 38.005 ;
     RECT  34.32 37.813 34.824 38.053 ;
     RECT  24.144 38.005 25.032 38.101 ;
     RECT  31.2 37.971 31.224 38.101 ;
     RECT  31.152 38.101 31.224 38.111 ;
     RECT  34.272 38.053 34.824 38.133 ;
     RECT  59.52 36.331 59.952 38.133 ;
     RECT  63.264 38.063 63.288 38.147 ;
     RECT  21.84 38.005 22.632 38.187 ;
     RECT  30.096 38.111 30.12 38.195 ;
     RECT  31.152 38.111 31.368 38.195 ;
     RECT  13.344 38.133 13.368 38.221 ;
     RECT  34.224 38.133 34.872 38.221 ;
     RECT  52.608 38.133 52.632 38.221 ;
     RECT  59.232 38.133 61.8 38.221 ;
     RECT  31.152 38.195 31.176 38.251 ;
     RECT  57.312 38.197 57.336 38.291 ;
     RECT  34.272 38.221 34.872 38.325 ;
     RECT  37.872 37.611 38.352 38.379 ;
     RECT  32.64 38.003 32.952 38.419 ;
     RECT  36.432 37.291 36.456 38.435 ;
     RECT  32.4 38.419 32.952 38.437 ;
     RECT  43.44 37.291 44.328 38.453 ;
     RECT  35.904 38.447 35.928 38.531 ;
     RECT  42.72 38.453 44.328 38.533 ;
     RECT  45.744 37.291 45.768 38.579 ;
     RECT  24.144 38.101 25.224 38.581 ;
     RECT  26.304 38.003 28.488 38.581 ;
     RECT  42.72 38.533 44.616 38.581 ;
     RECT  47.424 38.547 47.448 38.581 ;
     RECT  20.304 38.517 20.328 38.605 ;
     RECT  32.256 38.437 32.952 38.635 ;
     RECT  42.432 38.581 44.616 38.635 ;
     RECT  47.328 38.581 47.448 38.635 ;
     RECT  11.04 37.483 11.352 38.639 ;
     RECT  19.152 36.517 19.176 38.645 ;
     RECT  47.328 38.635 47.352 38.645 ;
     RECT  42.432 38.635 43.752 38.675 ;
     RECT  30.336 38.581 30.744 38.699 ;
     RECT  34.272 38.325 34.92 38.699 ;
     RECT  42.72 38.675 43.752 38.699 ;
     RECT  61.776 38.221 61.8 38.699 ;
     RECT  11.04 38.639 11.976 38.723 ;
     RECT  46.704 38.645 47.352 38.723 ;
     RECT  46.704 38.723 46.728 38.733 ;
     RECT  34.8 38.699 34.92 38.736 ;
     RECT  18.672 38.645 19.176 38.771 ;
     RECT  30.624 38.699 30.744 38.771 ;
     RECT  34.8 38.736 34.824 38.771 ;
     RECT  24.144 38.581 28.488 38.819 ;
     RECT  21.84 38.187 22.152 39.061 ;
     RECT  5.64 36.907 5.952 39.187 ;
     RECT  32.64 38.635 32.952 39.187 ;
     RECT  30.672 38.771 30.744 39.211 ;
     RECT  57.6 39.061 57.624 39.211 ;
     RECT  55.824 39.157 55.848 39.241 ;
     RECT  32.64 39.187 33.576 39.275 ;
     RECT  51.168 39.205 51.192 39.289 ;
     RECT  19.152 38.771 19.176 39.395 ;
     RECT  5.52 39.187 5.952 39.589 ;
     RECT  2.928 39.205 2.952 39.685 ;
     RECT  0.24 27.923 0.552 39.699 ;
     RECT  2.448 39.685 2.952 39.699 ;
     RECT  39.792 39.187 39.816 39.733 ;
     RECT  31.248 39.221 31.272 39.779 ;
     RECT  0.144 39.699 0.552 39.787 ;
     RECT  2.016 39.699 2.952 39.787 ;
     RECT  24.624 38.819 27.552 39.787 ;
     RECT  28.656 39.589 28.824 39.787 ;
     RECT  51.264 39.733 51.288 39.817 ;
     RECT  54.24 37.331 54.552 39.839 ;
     RECT  25.2 39.787 27.552 39.885 ;
     RECT  2.448 39.787 2.952 39.915 ;
     RECT  52.56 39.733 52.584 39.915 ;
     RECT  28.656 39.787 28.728 39.923 ;
     RECT  54.24 39.839 54.744 39.923 ;
     RECT  27.24 39.885 27.552 39.925 ;
     RECT  39.792 39.733 39.912 39.925 ;
     RECT  41.088 39.301 41.112 39.925 ;
     RECT  48.84 36.139 49.152 39.925 ;
     RECT  11.04 38.723 11.352 39.983 ;
     RECT  27.24 39.925 28.632 40.019 ;
     RECT  62.736 39.925 62.76 40.019 ;
     RECT  10.8 39.983 11.352 40.067 ;
     RECT  38.04 38.379 38.352 40.069 ;
     RECT  39.792 39.925 41.112 40.069 ;
     RECT  48.48 39.925 49.152 40.115 ;
     RECT  4.848 39.589 5.952 40.117 ;
     RECT  7.056 40.083 7.08 40.171 ;
     RECT  59.64 38.221 59.952 40.223 ;
     RECT  4.752 40.117 5.952 40.259 ;
     RECT  2.928 39.915 2.952 40.275 ;
     RECT  12.336 39.989 12.36 40.307 ;
     RECT  59.64 40.223 60.408 40.307 ;
     RECT  2.928 40.275 3.24 40.363 ;
     RECT  38.04 40.069 41.112 40.363 ;
     RECT  14.832 40.405 14.856 40.491 ;
     RECT  23.376 40.405 23.4 40.491 ;
     RECT  28.608 40.019 28.632 40.491 ;
     RECT  16.44 32.243 16.752 40.501 ;
     RECT  38.04 40.363 39.912 40.547 ;
     RECT  18.384 40.405 18.408 40.555 ;
     RECT  16.44 40.501 17.112 40.595 ;
     RECT  61.392 39.925 61.416 40.835 ;
     RECT  50.688 41.013 51.288 41.195 ;
     RECT  48.84 40.115 49.152 41.221 ;
     RECT  62.4 41.269 62.424 41.363 ;
     RECT  16.44 40.595 16.872 41.397 ;
     RECT  38.04 40.547 39.144 41.507 ;
     RECT  30.864 41.413 30.888 41.515 ;
     RECT  59.64 40.307 59.952 41.567 ;
     RECT  20.352 41.397 20.376 41.579 ;
     RECT  5.64 40.259 5.952 41.589 ;
     RECT  48.84 41.221 49.752 41.643 ;
     RECT  38.04 41.507 38.52 41.651 ;
     RECT  59.64 41.567 60.744 41.651 ;
     RECT  27.24 40.019 27.552 41.653 ;
     RECT  5.328 41.589 5.952 41.677 ;
     RECT  26.736 41.653 27.552 41.737 ;
     RECT  18.384 41.653 18.408 41.747 ;
     RECT  7.248 41.797 7.272 41.899 ;
     RECT  8.448 41.797 8.472 41.899 ;
     RECT  9.504 41.797 9.528 41.899 ;
     RECT  31.296 41.653 31.32 41.899 ;
     RECT  16.272 41.397 16.872 41.909 ;
     RECT  59.64 41.651 60.456 42.003 ;
     RECT  34.8 41.845 34.824 42.027 ;
     RECT  59.232 42.003 60.456 42.091 ;
     RECT  19.968 41.893 19.992 42.101 ;
     RECT  41.088 40.363 41.112 42.133 ;
     RECT  2.928 40.363 2.952 42.155 ;
     RECT  51.264 41.195 51.288 42.155 ;
     RECT  39.504 41.797 40.104 42.179 ;
     RECT  39.6 42.179 40.104 42.189 ;
     RECT  59.52 42.091 60.456 42.227 ;
     RECT  47.328 42.037 47.352 42.229 ;
     RECT  48.84 41.643 49.512 42.229 ;
     RECT  47.04 42.229 47.352 42.277 ;
     RECT  14.784 42.229 14.808 42.313 ;
     RECT  51.408 42.229 51.432 42.323 ;
     RECT  46.752 42.277 47.352 42.361 ;
     RECT  45.552 42.287 45.576 42.371 ;
     RECT  48.624 42.229 49.512 42.371 ;
     RECT  48.624 42.371 49.272 42.419 ;
     RECT  1.536 41.749 1.56 42.467 ;
     RECT  47.328 42.361 47.352 42.515 ;
     RECT  29.328 42.451 29.352 42.539 ;
     RECT  3.408 42.613 3.432 42.697 ;
     RECT  57.648 42.181 57.672 42.731 ;
     RECT  16.272 41.909 17.112 42.741 ;
     RECT  19.824 42.101 19.992 42.741 ;
     RECT  59.52 42.227 59.952 42.755 ;
     RECT  61.824 42.671 61.848 42.755 ;
     RECT  63.36 42.671 63.384 42.755 ;
     RECT  16.272 42.741 17.544 42.757 ;
     RECT  19.824 42.741 20.472 42.757 ;
     RECT  21.648 39.061 22.152 42.757 ;
     RECT  16.272 42.757 17.784 42.829 ;
     RECT  19.824 42.757 22.152 42.829 ;
     RECT  32.64 39.275 32.952 42.853 ;
     RECT  11.04 40.067 11.352 42.911 ;
     RECT  41.088 42.133 41.304 42.933 ;
     RECT  32.496 42.853 32.952 42.937 ;
     RECT  11.04 42.911 11.976 42.995 ;
     RECT  9.6 42.671 9.624 42.997 ;
     RECT  43.44 38.699 43.752 42.997 ;
     RECT  13.152 42.387 13.176 43.021 ;
     RECT  47.472 42.741 47.832 43.051 ;
     RECT  9.6 42.997 9.672 43.081 ;
     RECT  25.2 39.885 25.656 43.093 ;
     RECT  40.752 42.933 41.304 43.115 ;
     RECT  16.272 42.829 16.752 43.125 ;
     RECT  21.12 42.829 22.152 43.179 ;
     RECT  30.576 42.719 31.224 43.189 ;
     RECT  25.2 43.093 25.848 43.219 ;
     RECT  16.176 43.125 16.752 43.235 ;
     RECT  19.824 42.829 19.848 43.235 ;
     RECT  47.808 43.051 47.832 43.235 ;
     RECT  42.624 42.997 43.752 43.243 ;
     RECT  11.04 42.995 11.352 43.247 ;
     RECT  48.84 42.419 49.272 43.283 ;
     RECT  24.768 43.219 25.848 43.307 ;
     RECT  30.528 43.189 31.224 43.307 ;
     RECT  55.824 43.141 55.848 43.307 ;
     RECT  62.352 43.219 62.376 43.307 ;
     RECT  7.92 43.237 7.944 43.321 ;
     RECT  10.848 43.247 11.352 43.331 ;
     RECT  17.76 42.829 17.784 43.331 ;
     RECT  25.056 43.307 25.848 43.331 ;
     RECT  25.2 43.331 25.848 43.701 ;
     RECT  27.24 41.737 27.552 43.701 ;
     RECT  57.024 43.253 57.048 43.763 ;
     RECT  9.216 43.701 9.24 43.789 ;
     RECT  28.8 43.701 28.824 43.795 ;
     RECT  28.704 43.795 28.824 43.813 ;
     RECT  30.528 43.307 30.648 43.813 ;
     RECT  51.312 43.525 51.336 43.823 ;
     RECT  50.736 43.823 51.336 43.861 ;
     RECT  28.704 43.813 30.648 43.883 ;
     RECT  16.44 43.235 16.752 43.893 ;
     RECT  18.768 42.997 18.792 43.893 ;
     RECT  14.784 43.813 14.808 43.897 ;
     RECT  29.664 43.883 30.648 43.897 ;
     RECT  50.736 43.861 51.384 43.907 ;
     RECT  25.2 43.701 27.552 43.955 ;
     RECT  18.72 43.893 18.792 44.015 ;
     RECT  26.448 43.955 27.552 44.021 ;
     RECT  18.72 44.015 18.84 44.075 ;
     RECT  26.448 44.021 28.44 44.075 ;
     RECT  51.024 43.907 51.384 44.075 ;
     RECT  18.816 44.075 18.84 44.099 ;
     RECT  27.24 44.075 28.44 44.109 ;
     RECT  30.624 43.897 30.648 44.109 ;
     RECT  16.44 43.893 17.352 44.147 ;
     RECT  16.44 44.147 17.064 44.339 ;
     RECT  41.088 43.115 41.304 44.339 ;
     RECT  4.08 44.021 4.104 44.387 ;
     RECT  14.208 44.021 14.232 44.387 ;
     RECT  38.04 41.651 38.352 44.485 ;
     RECT  25.2 43.955 25.224 44.581 ;
     RECT  48.84 43.283 49.152 44.581 ;
     RECT  23.856 44.563 23.88 44.591 ;
     RECT  43.44 43.243 43.752 44.591 ;
     RECT  11.04 43.331 11.352 44.597 ;
     RECT  54.24 39.923 54.552 44.597 ;
     RECT  23.76 44.591 23.88 44.651 ;
     RECT  47.616 44.581 49.152 44.665 ;
     RECT  23.76 44.651 23.784 44.675 ;
     RECT  43.44 44.591 43.944 44.675 ;
     RECT  39.6 44.597 39.624 44.685 ;
     RECT  25.104 44.581 25.224 45.157 ;
     RECT  34.368 43.621 34.392 45.157 ;
     RECT  51.024 44.075 51.336 45.157 ;
     RECT  38.04 44.485 38.472 45.173 ;
     RECT  50.736 45.157 51.336 45.173 ;
     RECT  14.112 45.139 14.136 45.227 ;
     RECT  50.736 45.173 51.384 45.241 ;
     RECT  38.04 45.173 39.24 45.299 ;
     RECT  10.752 44.597 11.352 45.301 ;
     RECT  16.44 44.339 16.752 45.301 ;
     RECT  51.072 45.241 51.384 45.347 ;
     RECT  2.592 45.267 2.616 45.355 ;
     RECT  24.768 45.157 25.224 45.355 ;
     RECT  16.44 45.301 16.872 45.395 ;
     RECT  63.216 44.597 63.24 45.443 ;
     RECT  54.24 44.597 54.648 45.445 ;
     RECT  56.448 44.965 56.472 45.459 ;
     RECT  31.296 45.301 31.32 45.483 ;
     RECT  38.04 45.299 39.096 45.517 ;
     RECT  59.64 42.755 59.952 45.541 ;
     RECT  33.984 45.157 34.392 45.551 ;
     RECT  33.984 45.551 35.352 45.589 ;
     RECT  3.456 45.541 3.48 45.599 ;
     RECT  33.984 45.589 35.544 45.611 ;
     RECT  8.88 44.563 8.904 45.621 ;
     RECT  10.416 45.301 11.352 45.621 ;
     RECT  30.768 45.541 30.792 45.625 ;
     RECT  34.368 45.611 35.544 45.635 ;
     RECT  3.456 45.599 4.296 45.683 ;
     RECT  18.528 45.599 18.552 45.683 ;
     RECT  8.88 45.621 11.352 45.709 ;
     RECT  46.752 45.621 47.16 45.731 ;
     RECT  43.44 44.675 43.752 45.749 ;
     RECT  54.144 45.445 54.648 45.803 ;
     RECT  56.208 45.459 56.472 45.813 ;
     RECT  25.2 45.355 25.224 45.829 ;
     RECT  54.24 45.803 54.648 45.877 ;
     RECT  55.92 45.813 56.472 45.877 ;
     RECT  54.24 45.877 56.472 45.901 ;
     RECT  53.04 45.685 53.064 45.931 ;
     RECT  27.24 44.109 27.552 45.941 ;
     RECT  54.24 45.901 55.32 45.961 ;
     RECT  51.072 45.347 51.096 46.019 ;
     RECT  27.24 45.941 28.248 46.029 ;
     RECT  42.72 45.749 43.752 46.035 ;
     RECT  10.416 45.709 11.352 46.099 ;
     RECT  35.52 45.635 35.544 46.099 ;
     RECT  19.92 46.021 19.944 46.123 ;
     RECT  25.2 45.829 25.992 46.123 ;
     RECT  42.72 46.035 44.376 46.123 ;
     RECT  45.696 46.035 45.72 46.123 ;
     RECT  46.752 45.731 46.776 46.123 ;
     RECT  21.84 43.179 22.152 46.175 ;
     RECT  35.52 46.099 35.64 46.187 ;
     RECT  56.832 46.117 56.856 46.197 ;
     RECT  58.704 45.541 59.952 46.197 ;
     RECT  42.72 46.123 43.752 46.211 ;
     RECT  56.832 46.197 57.336 46.251 ;
     RECT  58.464 46.197 59.952 46.251 ;
     RECT  16.44 45.395 16.752 46.261 ;
     RECT  58.464 46.251 58.488 46.285 ;
     RECT  16.32 46.261 16.752 46.355 ;
     RECT  15.072 46.389 15.096 46.499 ;
     RECT  21.744 46.175 22.152 46.517 ;
     RECT  16.44 46.355 16.752 46.581 ;
     RECT  3.456 45.683 3.48 46.645 ;
     RECT  21.024 46.517 22.152 46.645 ;
     RECT  38.04 45.517 38.664 46.645 ;
     RECT  38.04 46.645 39.336 46.693 ;
     RECT  21.024 46.645 22.344 46.729 ;
     RECT  10.416 46.099 11.64 46.739 ;
     RECT  25.2 46.123 25.224 46.739 ;
     RECT  3.36 46.645 3.48 46.763 ;
     RECT  44.736 46.517 45.528 46.763 ;
     RECT  10.56 46.739 11.64 46.773 ;
     RECT  57.312 46.251 57.336 46.787 ;
     RECT  2.304 45.541 2.328 46.793 ;
     RECT  21.024 46.729 22.152 46.793 ;
     RECT  26.208 46.751 26.232 46.835 ;
     RECT  30.672 46.751 30.696 46.835 ;
     RECT  10.56 46.773 12.12 46.861 ;
     RECT  13.584 46.773 14.52 46.861 ;
     RECT  54.24 45.961 54.792 46.891 ;
     RECT  8.88 45.709 8.904 46.955 ;
     RECT  19.776 46.867 19.8 46.955 ;
     RECT  35.52 46.187 35.544 46.955 ;
     RECT  45.024 46.763 45.528 46.969 ;
     RECT  3.504 46.965 3.528 47.053 ;
     RECT  37.872 46.693 39.336 47.093 ;
     RECT  54.24 46.891 54.648 47.157 ;
     RECT  27.24 46.029 27.552 47.279 ;
     RECT  5.64 41.677 5.952 47.285 ;
     RECT  41.088 44.339 41.112 47.285 ;
     RECT  20.784 46.901 20.808 47.315 ;
     RECT  41.088 47.285 41.544 47.317 ;
     RECT  9.024 47.269 9.048 47.353 ;
     RECT  26.352 47.279 27.552 47.363 ;
     RECT  56.448 47.279 56.472 47.363 ;
     RECT  5.64 47.285 6.552 47.373 ;
     RECT  54.144 47.157 54.648 47.373 ;
     RECT  16.44 46.581 16.872 47.443 ;
     RECT  41.088 47.317 41.976 47.477 ;
     RECT  43.2 46.211 43.752 47.477 ;
     RECT  37.872 47.093 39.912 47.605 ;
     RECT  41.088 47.477 43.752 47.605 ;
     RECT  48.84 44.665 49.152 47.605 ;
     RECT  10.56 46.861 11.352 47.629 ;
     RECT  16.44 47.443 17.448 47.635 ;
     RECT  45.504 46.969 45.528 47.659 ;
     RECT  47.472 47.279 47.496 47.711 ;
     RECT  16.44 47.635 18.024 47.723 ;
     RECT  37.872 47.605 43.752 47.747 ;
     RECT  47.328 47.711 47.496 47.795 ;
     RECT  13.584 46.861 13.608 47.843 ;
     RECT  16.44 47.723 17.88 47.855 ;
     RECT  16.32 47.855 17.88 47.881 ;
     RECT  31.344 47.797 31.368 47.881 ;
     RECT  40.032 47.747 43.752 47.881 ;
     RECT  35.712 47.605 35.736 47.891 ;
     RECT  56.832 47.925 56.856 48.013 ;
     RECT  21.84 46.793 22.152 48.147 ;
     RECT  17.856 47.881 17.88 48.171 ;
     RECT  19.968 48.095 19.992 48.179 ;
     RECT  42.528 47.881 43.752 48.205 ;
     RECT  13.92 47.861 14.232 48.227 ;
     RECT  34.368 45.635 34.392 48.229 ;
     RECT  54.144 47.373 54.552 48.309 ;
     RECT  48.624 47.605 49.152 48.339 ;
     RECT  47.472 47.795 47.496 48.419 ;
     RECT  16.32 47.881 16.752 48.421 ;
     RECT  48.576 48.339 49.152 48.427 ;
     RECT  34.368 48.229 34.776 48.467 ;
     RECT  34.368 48.467 34.392 48.565 ;
     RECT  34.128 48.565 34.392 48.659 ;
     RECT  11.04 47.629 11.352 48.723 ;
     RECT  53.568 48.309 54.552 48.803 ;
     RECT  21.744 48.147 22.152 48.853 ;
     RECT  23.376 48.757 23.4 48.853 ;
     RECT  3.936 48.821 3.96 48.909 ;
     RECT  40.032 47.881 41.112 48.909 ;
     RECT  16.128 48.421 16.752 48.915 ;
     RECT  21.744 48.853 23.4 48.915 ;
     RECT  32.64 42.937 32.952 48.915 ;
     RECT  21.744 48.915 23.688 48.949 ;
     RECT  48.84 48.427 49.152 48.949 ;
     RECT  10.944 48.723 11.352 48.997 ;
     RECT  21.744 48.949 23.832 49.003 ;
     RECT  32.64 48.915 33.048 49.003 ;
     RECT  51.312 48.309 51.336 49.003 ;
     RECT  43.44 48.205 43.752 49.013 ;
     RECT  44.976 48.997 45.576 49.013 ;
     RECT  35.856 48.949 35.88 49.033 ;
     RECT  13.92 48.227 13.944 49.067 ;
     RECT  41.088 48.909 41.112 49.091 ;
     RECT  23.808 49.003 23.832 49.139 ;
     RECT  43.44 49.013 45.576 49.139 ;
     RECT  32.64 49.003 32.952 49.141 ;
     RECT  40.032 48.909 40.056 49.187 ;
     RECT  30.672 49.141 30.696 49.235 ;
     RECT  31.92 49.141 32.952 49.283 ;
     RECT  30.816 49.237 30.84 49.323 ;
     RECT  5.64 47.373 5.952 49.363 ;
     RECT  48.84 48.949 50.136 49.439 ;
     RECT  5.28 49.363 5.952 49.451 ;
     RECT  43.44 49.139 43.944 49.475 ;
     RECT  3.6 49.397 3.624 49.485 ;
     RECT  7.728 49.461 7.752 49.549 ;
     RECT  9.168 49.461 9.192 49.549 ;
     RECT  43.44 49.475 43.848 49.549 ;
     RECT  16.128 48.915 17.064 49.619 ;
     RECT  44.928 49.139 45.576 49.619 ;
     RECT  48.72 49.439 50.136 49.619 ;
     RECT  12.528 48.421 12.552 49.813 ;
     RECT  16.44 49.619 17.064 49.813 ;
     RECT  43.44 49.549 43.752 49.813 ;
     RECT  16.44 49.813 17.112 49.909 ;
     RECT  10.8 48.997 11.352 49.967 ;
     RECT  21.744 49.003 22.728 49.973 ;
     RECT  32.64 49.283 32.952 49.973 ;
     RECT  37.872 47.747 38.352 49.973 ;
     RECT  16.44 49.909 17.352 50.005 ;
     RECT  25.536 49.939 25.56 50.005 ;
     RECT  39.408 49.909 39.432 50.027 ;
     RECT  43.344 49.813 43.752 50.027 ;
     RECT  16.44 50.005 18.312 50.037 ;
     RECT  20.784 49.973 22.728 50.037 ;
     RECT  48.72 49.619 49.152 50.037 ;
     RECT  15.408 49.957 15.432 50.041 ;
     RECT  10.464 49.967 11.352 50.051 ;
     RECT  10.944 50.051 11.352 50.061 ;
     RECT  20.784 50.037 22.776 50.061 ;
     RECT  32.64 49.973 33.288 50.061 ;
     RECT  16.44 50.037 18.936 50.091 ;
     RECT  30.864 50.015 30.888 50.099 ;
     RECT  18.192 50.091 18.936 50.125 ;
     RECT  11.04 50.061 11.352 50.197 ;
     RECT  12.384 49.813 12.552 50.197 ;
     RECT  11.04 50.197 12.552 50.243 ;
     RECT  43.44 50.027 43.752 50.515 ;
     RECT  25.392 50.005 25.56 50.533 ;
     RECT  30.528 50.437 30.552 50.533 ;
     RECT  5.64 49.451 5.952 50.543 ;
     RECT  27.24 47.363 27.552 50.581 ;
     RECT  48.528 50.037 49.152 50.581 ;
     RECT  54.24 48.803 54.552 50.581 ;
     RECT  30.384 50.533 30.552 50.603 ;
     RECT  37.2 49.973 38.352 50.603 ;
     RECT  25.392 50.533 26.232 50.613 ;
     RECT  24.816 50.613 26.232 50.617 ;
     RECT  30.384 50.603 30.408 50.617 ;
     RECT  47.376 50.581 49.152 50.667 ;
     RECT  56.256 50.581 56.28 50.677 ;
     RECT  24.816 50.617 25.752 50.701 ;
     RECT  45.456 49.619 45.48 50.725 ;
     RECT  20.592 50.629 20.616 50.731 ;
     RECT  47.664 50.667 49.152 50.731 ;
     RECT  54.24 50.581 54.648 50.731 ;
     RECT  21.744 50.061 22.776 50.761 ;
     RECT  8.832 50.735 8.856 50.819 ;
     RECT  13.056 50.735 13.08 50.819 ;
     RECT  43.44 50.515 44.088 50.821 ;
     RECT  45.456 50.725 45.672 50.867 ;
     RECT  30.24 50.805 30.264 50.893 ;
     RECT  43.44 50.821 44.376 50.923 ;
     RECT  32.64 50.061 32.952 50.965 ;
     RECT  5.28 50.543 5.952 50.997 ;
     RECT  54.24 50.731 54.552 50.997 ;
     RECT  56.064 50.677 56.28 50.997 ;
     RECT  25.728 50.701 25.752 51.051 ;
     RECT  18.192 50.125 18.792 51.061 ;
     RECT  21.744 50.761 22.68 51.061 ;
     RECT  32.352 50.965 32.952 51.061 ;
     RECT  4.128 50.997 4.152 51.085 ;
     RECT  56.064 50.997 56.856 51.085 ;
     RECT  30.096 51.013 30.12 51.091 ;
     RECT  5.136 50.997 5.952 51.107 ;
     RECT  45.36 50.997 45.384 51.107 ;
     RECT  54.048 50.997 54.552 51.107 ;
     RECT  21.072 51.061 22.68 51.145 ;
     RECT  31.92 51.061 32.952 51.145 ;
     RECT  18.048 51.061 18.792 51.155 ;
     RECT  30.048 51.091 30.12 51.179 ;
     RECT  39.888 50.805 39.912 51.283 ;
     RECT  16.44 50.091 16.752 51.317 ;
     RECT  39.888 51.283 40.344 51.317 ;
     RECT  56.064 51.085 56.568 51.347 ;
     RECT  11.04 50.243 12.024 51.395 ;
     RECT  43.44 50.923 43.992 51.491 ;
     RECT  35.472 50.965 35.496 51.493 ;
     RECT  56.544 51.347 56.568 51.563 ;
     RECT  27.24 50.581 28.248 51.573 ;
     RECT  34.368 48.659 34.392 51.573 ;
     RECT  35.472 51.493 35.544 51.573 ;
     RECT  37.872 50.603 38.352 51.573 ;
     RECT  39.696 51.317 40.344 51.573 ;
     RECT  16.32 51.317 16.752 51.603 ;
     RECT  32.208 51.145 32.952 51.637 ;
     RECT  34.368 51.573 35.544 51.637 ;
     RECT  36.912 51.573 38.352 51.637 ;
     RECT  39.696 51.573 40.44 51.637 ;
     RECT  27.24 51.573 28.488 51.661 ;
     RECT  32.208 51.637 35.544 51.661 ;
     RECT  36.912 51.637 40.44 51.661 ;
     RECT  16.32 51.603 17.112 51.691 ;
     RECT  37.872 51.661 40.44 51.731 ;
     RECT  18.288 51.155 18.312 51.883 ;
     RECT  35.52 51.661 35.544 51.883 ;
     RECT  39.792 51.731 40.44 51.883 ;
     RECT  16.32 51.691 16.752 51.893 ;
     RECT  21.6 51.145 22.68 51.893 ;
     RECT  37.872 51.731 38.352 51.923 ;
     RECT  43.44 51.491 43.944 51.923 ;
     RECT  47.904 50.731 49.152 51.957 ;
     RECT  24.48 51.253 24.504 51.971 ;
     RECT  36.816 51.829 36.84 51.971 ;
     RECT  16.128 51.893 16.752 51.981 ;
     RECT  20.544 51.893 20.568 51.981 ;
     RECT  32.208 51.661 34.392 52.011 ;
     RECT  27.24 51.661 27.552 52.021 ;
     RECT  30.192 51.957 30.216 52.021 ;
     RECT  50.16 51.957 50.184 52.067 ;
     RECT  30.192 52.021 30.264 52.085 ;
     RECT  47.76 51.957 49.152 52.139 ;
     RECT  40.32 51.883 40.44 52.149 ;
     RECT  30.192 52.085 30.84 52.163 ;
     RECT  40.32 52.149 40.872 52.165 ;
     RECT  43.44 51.923 43.752 52.179 ;
     RECT  26.592 52.021 27.552 52.203 ;
     RECT  19.776 52.149 19.8 52.237 ;
     RECT  30.24 52.163 30.84 52.267 ;
     RECT  42.528 52.179 43.752 52.267 ;
     RECT  21.6 51.893 23.112 52.309 ;
     RECT  21.6 52.309 23.4 52.331 ;
     RECT  30.24 52.267 30.552 52.331 ;
     RECT  21.696 52.331 23.4 52.395 ;
     RECT  56.976 52.309 57.048 52.395 ;
     RECT  42.288 52.341 42.312 52.405 ;
     RECT  42.192 52.405 42.312 52.451 ;
     RECT  21.696 52.395 23.016 52.459 ;
     RECT  42.192 52.451 42.216 52.489 ;
     RECT  32.352 52.011 34.392 52.703 ;
     RECT  54.096 51.107 54.552 52.703 ;
     RECT  56.976 52.395 57 52.725 ;
     RECT  32.352 52.703 34.824 52.787 ;
     RECT  54.096 52.703 55.272 52.787 ;
     RECT  18.576 52.725 18.6 52.813 ;
     RECT  56.64 52.725 57 52.813 ;
     RECT  40.32 52.165 41.016 52.917 ;
     RECT  54.096 52.787 54.552 52.917 ;
     RECT  38.04 51.923 38.352 52.947 ;
     RECT  32.352 52.787 34.392 52.981 ;
     RECT  39.552 52.917 41.016 53.005 ;
     RECT  53.952 52.917 54.552 53.005 ;
     RECT  31.92 52.981 34.392 53.065 ;
     RECT  43.44 52.267 43.752 53.109 ;
     RECT  32.352 53.065 34.392 53.123 ;
     RECT  48.84 52.139 49.152 53.125 ;
     RECT  30.528 52.331 30.552 53.171 ;
     RECT  16.44 51.981 16.752 53.173 ;
     RECT  37.92 52.947 38.352 53.173 ;
     RECT  43.44 53.109 44.184 53.219 ;
     RECT  35.808 53.077 35.832 53.227 ;
     RECT  48.576 53.125 49.152 53.227 ;
     RECT  16.32 53.173 16.752 53.267 ;
     RECT  39.696 53.005 41.016 53.517 ;
     RECT  18.816 53.523 18.84 53.557 ;
     RECT  26.208 53.493 26.232 53.581 ;
     RECT  30.48 53.493 30.504 53.581 ;
     RECT  18.816 53.557 19.368 53.611 ;
     RECT  25.008 53.557 25.032 53.651 ;
     RECT  37.488 53.173 38.352 53.779 ;
     RECT  19.344 53.611 19.368 53.833 ;
     RECT  43.44 53.219 43.944 53.843 ;
     RECT  37.296 53.779 38.352 53.867 ;
     RECT  39.696 53.517 39.72 53.867 ;
     RECT  46.272 53.779 46.296 53.867 ;
     RECT  47.424 53.797 47.448 53.881 ;
     RECT  21.696 52.459 22.152 54.069 ;
     RECT  40.992 53.517 41.016 54.131 ;
     RECT  54.24 53.005 54.552 54.133 ;
     RECT  54.24 54.133 55.32 54.239 ;
     RECT  56.976 52.813 57 54.325 ;
     RECT  21.648 54.069 22.152 54.355 ;
     RECT  56.448 54.325 57 54.371 ;
     RECT  48.84 53.227 49.152 54.421 ;
     RECT  21.12 54.355 22.152 54.443 ;
     RECT  32.352 53.123 32.952 54.469 ;
     RECT  52.848 54.373 52.872 54.469 ;
     RECT  54.096 54.239 55.32 54.469 ;
     RECT  47.952 54.421 49.152 54.507 ;
     RECT  31.68 54.469 32.952 54.571 ;
     RECT  52.848 54.469 55.32 54.571 ;
     RECT  35.76 53.813 35.784 54.659 ;
     RECT  56.448 54.371 56.952 54.755 ;
     RECT  34.368 53.123 34.392 54.837 ;
     RECT  35.616 54.767 35.64 54.837 ;
     RECT  48.84 54.507 49.152 54.837 ;
     RECT  53.472 54.571 55.32 54.837 ;
     RECT  34.368 54.837 35.64 54.851 ;
     RECT  26.208 54.805 26.232 54.891 ;
     RECT  23.424 54.837 23.448 54.925 ;
     RECT  34.368 54.851 34.776 54.925 ;
     RECT  41.664 54.837 41.688 54.947 ;
     RECT  43.44 53.843 43.752 54.949 ;
     RECT  48.84 54.837 49.704 55.283 ;
     RECT  43.44 54.949 44.088 55.403 ;
     RECT  21.648 54.443 22.152 55.413 ;
     RECT  39.984 55.343 40.008 55.427 ;
     RECT  45.6 55.343 45.624 55.427 ;
     RECT  53.472 54.837 55.608 55.467 ;
     RECT  50.688 55.391 50.712 55.475 ;
     RECT  21.456 55.413 22.152 55.523 ;
     RECT  32.64 54.571 32.952 55.573 ;
     RECT  32.544 55.573 32.952 55.811 ;
     RECT  56.928 54.755 56.952 55.811 ;
     RECT  53.472 55.467 54.744 55.925 ;
     RECT  20.64 55.891 20.664 55.979 ;
     RECT  47.808 55.813 47.832 55.979 ;
     RECT  52.032 55.813 52.056 55.979 ;
     RECT  53.424 55.925 54.744 56.003 ;
     RECT  53.424 56.003 54.552 56.013 ;
     RECT  47.52 56.245 47.544 56.427 ;
     RECT  27.24 52.203 27.552 56.437 ;
     RECT  25.68 56.437 25.704 56.467 ;
     RECT  43.44 55.403 43.752 56.485 ;
     RECT  24.192 56.053 24.216 56.491 ;
     RECT  25.68 56.467 25.848 56.531 ;
     RECT  27.24 56.437 27.864 56.531 ;
     RECT  56.64 56.437 56.664 56.531 ;
     RECT  25.824 56.531 25.848 56.555 ;
     RECT  43.344 56.485 43.752 56.569 ;
     RECT  45.936 56.533 45.96 56.619 ;
     RECT  32.64 55.811 32.952 56.725 ;
     RECT  34.368 54.925 34.392 56.725 ;
     RECT  38.04 53.867 38.352 56.757 ;
     RECT  31.488 56.757 31.512 56.773 ;
     RECT  32.64 56.725 34.392 56.821 ;
     RECT  31.296 56.773 31.512 56.845 ;
     RECT  41.856 56.485 41.88 56.845 ;
     RECT  29.376 56.501 29.4 56.867 ;
     RECT  40.752 56.821 40.776 56.939 ;
     RECT  48.84 55.283 49.152 57.013 ;
     RECT  48.72 57.013 49.152 57.107 ;
     RECT  45.504 57.013 45.528 57.131 ;
     RECT  35.904 57.071 35.928 57.155 ;
     RECT  46.704 57.077 47.256 57.299 ;
     RECT  45.024 57.253 45.048 57.337 ;
     RECT  31.296 56.845 31.368 57.461 ;
     RECT  29.664 57.461 31.368 57.515 ;
     RECT  29.664 57.515 31.32 57.587 ;
     RECT  32.544 56.821 34.392 57.587 ;
     RECT  54.24 56.013 54.552 57.589 ;
     RECT  42.192 57.555 42.216 57.643 ;
     RECT  47.52 57.445 47.544 57.643 ;
     RECT  55.536 57.445 55.56 57.643 ;
     RECT  44.976 57.589 45 57.673 ;
     RECT  53.568 57.589 54.552 57.717 ;
     RECT  21.648 55.523 22.152 57.781 ;
     RECT  38.04 56.757 38.904 57.781 ;
     RECT  42.24 57.685 42.264 57.781 ;
     RECT  53.568 57.717 55.176 57.827 ;
     RECT  42.24 57.781 42.312 57.835 ;
     RECT  53.568 57.827 54.744 57.865 ;
     RECT  21.6 57.781 22.152 57.875 ;
     RECT  42.288 57.835 42.312 57.963 ;
     RECT  38.04 57.781 39.096 58.021 ;
     RECT  38.04 58.021 39.24 58.101 ;
     RECT  32.64 57.587 34.392 58.115 ;
     RECT  30.336 57.587 31.32 58.163 ;
     RECT  54.24 57.865 54.744 58.163 ;
     RECT  30.336 58.163 30.792 58.189 ;
     RECT  38.04 58.101 39.288 58.189 ;
     RECT  33.936 58.115 34.392 58.509 ;
     RECT  34.368 58.509 34.392 58.515 ;
     RECT  38.04 58.189 39.24 58.549 ;
     RECT  30.336 58.189 30.648 58.603 ;
     RECT  34.368 58.515 34.536 58.603 ;
     RECT  48.84 57.107 49.152 58.613 ;
     RECT  37.2 58.549 39.24 58.643 ;
     RECT  37.68 58.643 39.24 58.667 ;
     RECT  48.096 58.613 49.152 58.701 ;
     RECT  30.336 58.603 30.36 58.731 ;
     RECT  40.224 58.645 40.248 58.731 ;
     RECT  34.368 58.603 34.392 58.739 ;
     RECT  38.04 58.667 39.24 58.795 ;
     RECT  27.24 56.531 27.552 58.885 ;
     RECT  23.232 58.869 23.256 58.957 ;
     RECT  27.24 58.885 28.44 59.125 ;
     RECT  26.88 59.125 28.44 59.189 ;
     RECT  21.648 57.875 22.152 59.221 ;
     RECT  54.24 58.163 54.552 59.231 ;
     RECT  26.64 59.189 28.44 59.253 ;
     RECT  23.136 59.029 23.16 59.307 ;
     RECT  26.64 59.253 29.016 59.307 ;
     RECT  54.144 59.231 54.552 59.315 ;
     RECT  30.24 59.381 30.264 59.469 ;
     RECT  31.392 59.381 31.416 59.469 ;
     RECT  21.6 59.221 22.152 59.605 ;
     RECT  51.504 59.509 51.768 59.637 ;
     RECT  26.64 59.307 27.552 59.731 ;
     RECT  51.504 59.637 52.104 59.747 ;
     RECT  28.992 59.307 29.016 59.765 ;
     RECT  21.6 59.605 22.776 59.797 ;
     RECT  26.256 59.731 27.552 59.819 ;
     RECT  28.992 59.765 29.16 59.819 ;
     RECT  54.24 59.315 54.552 59.829 ;
     RECT  29.136 59.819 29.16 59.853 ;
     RECT  24.528 59.765 24.552 59.891 ;
     RECT  48.84 58.701 49.152 59.893 ;
     RECT  54.24 59.829 54.744 59.917 ;
     RECT  32.64 58.115 32.952 59.957 ;
     RECT  32.64 59.957 33.432 60.045 ;
     RECT  35.328 60.037 35.352 60.051 ;
     RECT  32.64 60.045 32.952 60.243 ;
     RECT  51.504 59.747 51.768 60.243 ;
     RECT  38.04 58.795 38.352 60.277 ;
     RECT  21.168 59.797 22.776 60.301 ;
     RECT  31.92 60.243 32.952 60.331 ;
     RECT  50.544 60.243 51.768 60.331 ;
     RECT  21.696 60.301 22.776 60.611 ;
     RECT  27.24 59.819 27.552 60.661 ;
     RECT  35.184 60.051 35.352 60.709 ;
     RECT  47.856 59.893 49.152 60.709 ;
     RECT  21.744 60.611 22.776 60.757 ;
     RECT  21.744 60.757 23.16 60.789 ;
     RECT  37.536 60.277 38.352 60.789 ;
     RECT  47.856 60.709 50.136 60.789 ;
     RECT  37.536 60.789 40.008 60.805 ;
     RECT  34.656 60.709 35.352 60.843 ;
     RECT  47.52 60.789 50.136 60.843 ;
     RECT  36.912 60.805 40.008 60.877 ;
     RECT  47.52 60.843 47.544 60.877 ;
     RECT  21.744 60.789 23.352 60.899 ;
     RECT  34.656 60.843 35.256 60.899 ;
     RECT  36.912 60.877 39.912 60.899 ;
     RECT  43.44 56.569 43.752 60.901 ;
     RECT  34.656 60.899 34.776 60.907 ;
     RECT  36.912 60.899 37.032 60.907 ;
     RECT  21.744 60.899 23.112 60.947 ;
     RECT  46.368 60.853 46.392 60.995 ;
     RECT  30.672 60.853 30.696 61.093 ;
     RECT  21.84 60.947 22.776 61.139 ;
     RECT  30.672 61.093 30.984 61.139 ;
     RECT  25.92 61.093 25.944 61.141 ;
     RECT  51.504 60.331 51.768 61.365 ;
     RECT  27.24 60.661 27.96 61.419 ;
     RECT  29.616 61.343 29.64 61.427 ;
     RECT  46.704 61.343 46.728 61.427 ;
     RECT  51.264 61.365 51.96 61.453 ;
     RECT  25.824 61.141 25.944 61.476 ;
     RECT  31.968 60.331 32.952 61.547 ;
     RECT  34.224 61.343 34.248 61.561 ;
     RECT  30.96 61.139 30.984 61.587 ;
     RECT  27.24 61.419 27.672 61.619 ;
     RECT  30.96 61.587 31.08 61.619 ;
     RECT  36.288 61.557 36.456 61.667 ;
     RECT  51.264 61.453 51.768 61.667 ;
     RECT  31.056 61.619 31.08 61.675 ;
     RECT  24.624 60.037 24.648 61.715 ;
     RECT  36.432 61.667 36.456 61.715 ;
     RECT  38.04 60.899 39.912 61.715 ;
     RECT  41.088 61.749 41.112 61.859 ;
     RECT  25.92 61.476 25.944 61.867 ;
     RECT  21.84 61.139 22.152 62.111 ;
     RECT  24.48 61.765 24.504 62.195 ;
     RECT  21.744 62.111 22.152 62.355 ;
     RECT  20.976 62.355 22.152 62.389 ;
     RECT  46.416 62.293 46.44 62.419 ;
     RECT  20.976 62.389 22.248 62.443 ;
     RECT  21.84 62.443 22.248 62.473 ;
     RECT  45.456 62.419 46.44 62.507 ;
     RECT  38.04 61.715 39.48 62.709 ;
     RECT  42.144 62.111 42.168 62.709 ;
     RECT  43.44 60.901 43.848 62.709 ;
     RECT  48.84 60.843 49.152 62.709 ;
     RECT  51.264 61.667 51.528 62.771 ;
     RECT  35.232 62.709 35.256 62.797 ;
     RECT  47.904 62.709 49.152 62.797 ;
     RECT  43.44 62.709 43.944 62.803 ;
     RECT  29.808 62.709 30.12 62.819 ;
     RECT  29.808 62.819 29.976 62.821 ;
     RECT  41.616 62.709 42.168 62.837 ;
     RECT  43.44 62.803 44.04 62.837 ;
     RECT  32.64 61.547 32.952 62.869 ;
     RECT  46.416 62.507 46.44 62.891 ;
     RECT  29.328 62.821 29.976 62.915 ;
     RECT  48.192 62.797 49.152 62.955 ;
     RECT  29.328 62.915 29.352 62.963 ;
     RECT  37.776 62.709 39.48 62.965 ;
     RECT  45.216 62.837 45.24 63.011 ;
     RECT  35.568 62.931 35.592 63.019 ;
     RECT  41.616 62.837 44.04 63.019 ;
     RECT  42.912 63.019 44.04 63.023 ;
     RECT  37.776 62.965 39.576 63.049 ;
     RECT  48.336 62.955 49.152 63.083 ;
     RECT  37.776 63.049 38.352 63.107 ;
     RECT  42.912 63.023 44.472 63.107 ;
     RECT  39.456 63.049 39.576 63.203 ;
     RECT  27.24 61.619 27.552 63.205 ;
     RECT  39.456 63.203 39.48 63.251 ;
     RECT  32.64 62.869 33.096 63.253 ;
     RECT  48.84 63.083 49.152 63.263 ;
     RECT  27.24 63.205 27.96 63.285 ;
     RECT  26.976 63.285 27.96 63.339 ;
     RECT  41.52 63.221 41.544 63.347 ;
     RECT  42.912 63.107 43.752 63.347 ;
     RECT  48.84 63.263 49.272 63.347 ;
     RECT  51.264 62.771 51.288 63.36 ;
     RECT  25.488 63.285 25.512 63.373 ;
     RECT  26.976 63.339 27.552 63.373 ;
     RECT  31.344 63.285 31.368 63.731 ;
     RECT  32.64 63.253 33.384 63.829 ;
     RECT  0.24 39.787 0.552 64.013 ;
     RECT  5.64 51.107 5.952 64.013 ;
     RECT  11.04 51.395 11.352 64.013 ;
     RECT  16.44 53.267 16.752 64.013 ;
     RECT  21.84 62.473 22.152 64.013 ;
     RECT  27.24 63.373 27.552 64.013 ;
     RECT  38.04 63.107 38.352 64.013 ;
     RECT  43.44 63.347 43.752 64.013 ;
     RECT  48.84 63.347 49.152 64.013 ;
     RECT  54.24 59.917 54.552 64.013 ;
     RECT  59.64 46.251 59.952 64.013 ;
     RECT  0.24 64.013 0.36 64.283 ;
     RECT  5.64 64.013 5.76 64.283 ;
     RECT  11.04 64.013 11.16 64.283 ;
     RECT  16.44 64.013 16.56 64.283 ;
     RECT  21.84 64.013 21.96 64.283 ;
     RECT  27.24 64.013 27.36 64.283 ;
     RECT  38.04 64.013 38.16 64.283 ;
     RECT  43.44 64.013 43.56 64.283 ;
     RECT  48.84 64.013 48.96 64.283 ;
     RECT  54.24 64.013 54.36 64.283 ;
     RECT  59.64 64.013 59.76 64.283 ;
     RECT  32.496 63.829 33.384 64.309 ;
     RECT  32.496 64.309 33.48 64.405 ;
     RECT  31.152 63.829 31.272 64.656 ;
     RECT  32.496 64.405 33.576 64.656 ;
    LAYER M6 ;
     RECT  0 17.196 0.133 18.06 ;
     RECT  0 38.796 0.133 39.66 ;
     RECT  0.133 16 0.437 18.06 ;
     RECT  0.437 14.784 0.491 18.06 ;
     RECT  0 22.596 0.613 23.46 ;
     RECT  0 27.996 0.613 28.86 ;
     RECT  0.491 14.784 0.659 14.816 ;
     RECT  0.613 27.84 0.693 28.86 ;
     RECT  0.613 22.464 0.899 24.352 ;
     RECT  0.693 26.752 1.187 28.86 ;
     RECT  0 6.396 1.237 7.26 ;
     RECT  0 33.396 2.149 34.26 ;
     RECT  1.187 27.996 2.229 28.86 ;
     RECT  0.899 22.596 2.243 24.352 ;
     RECT  1.669 20.16 2.245 20.192 ;
     RECT  2.229 27.996 2.302 29.024 ;
     RECT  2.229 31.36 2.339 31.392 ;
     RECT  0.133 38.796 2.357 39.776 ;
     RECT  2.149 33.396 2.411 35.552 ;
     RECT  2.245 37.44 2.411 37.472 ;
     RECT  0 44.196 2.581 45.06 ;
     RECT  0.491 17.196 2.821 18.06 ;
     RECT  1.237 6.396 2.963 8.352 ;
     RECT  1.525 42.112 2.963 42.144 ;
     RECT  2.357 38.796 3.205 39.904 ;
     RECT  1.669 26.24 3.374 26.272 ;
     RECT  2.293 46.72 3.395 46.752 ;
     RECT  2.963 6.396 3.397 7.26 ;
     RECT  3.374 25.088 3.397 26.272 ;
     RECT  2.302 27.996 3.397 28.86 ;
     RECT  2.411 33.396 3.397 34.26 ;
     RECT  3.397 25.088 3.443 28.86 ;
     RECT  0 49.596 3.445 50.46 ;
     RECT  3.445 46.976 3.539 47.328 ;
     RECT  2.581 44.196 3.701 45.344 ;
     RECT  3.397 42.624 3.755 42.656 ;
     RECT  0 11.796 3.829 12.66 ;
     RECT  3.829 11.796 3.898 14.112 ;
     RECT  3.898 11.796 3.925 12.66 ;
     RECT  3.443 26.752 3.925 28.86 ;
     RECT  3.397 32.128 3.925 34.26 ;
     RECT  3.445 48.832 3.971 50.46 ;
     RECT  3.701 44.032 4.115 45.344 ;
     RECT  3.925 32.128 4.117 35.104 ;
     RECT  3.971 49.408 4.117 50.46 ;
     RECT  2.245 20.16 4.163 20.832 ;
     RECT  4.117 32.128 4.203 35.872 ;
     RECT  3.205 38.796 4.203 40.352 ;
     RECT  4.115 44.196 4.261 45.344 ;
     RECT  4.261 44.196 4.331 45.664 ;
     RECT  2.821 17.196 4.595 18.72 ;
     RECT  2.243 22.596 4.693 23.46 ;
     RECT  3.925 26.752 4.837 29.024 ;
     RECT  4.837 26.752 4.907 29.984 ;
     RECT  3.829 8.896 5.109 9.12 ;
     RECT  3.925 10.88 5.109 12.66 ;
     RECT  4.907 26.752 5.171 29.024 ;
     RECT  5.109 8.896 5.182 12.66 ;
     RECT  4.117 49.408 5.205 51.04 ;
     RECT  5.171 27.996 5.219 29.024 ;
     RECT  5.182 10.24 5.267 12.66 ;
     RECT  5.205 49.408 5.315 50.592 ;
     RECT  4.149 42.688 5.317 42.72 ;
     RECT  3.397 5.12 5.509 7.26 ;
     RECT  5.317 41.6 5.611 42.72 ;
     RECT  5.267 10.24 6.083 10.272 ;
     RECT  4.693 22.596 6.323 24.544 ;
     RECT  4.203 32.128 6.323 34.848 ;
     RECT  6.323 32.128 6.611 34.26 ;
     RECT  5.509 5.12 6.699 8.032 ;
     RECT  4.163 20.8 6.805 20.832 ;
     RECT  5.219 27.996 6.805 28.86 ;
     RECT  4.203 38.796 7.091 40.16 ;
     RECT  5.611 42.688 7.237 42.72 ;
     RECT  4.595 17.196 7.381 18.06 ;
     RECT  6.805 19.648 7.381 20.832 ;
     RECT  5.315 49.596 7.717 50.46 ;
     RECT  7.237 41.856 7.909 42.72 ;
     RECT  4.331 44.196 7.909 45.06 ;
     RECT  5.509 36.864 8.003 36.896 ;
     RECT  6.699 6.272 8.171 8.032 ;
     RECT  5.267 11.796 8.245 12.66 ;
     RECT  6.469 26.24 8.485 26.272 ;
     RECT  6.805 27.996 8.485 29.28 ;
     RECT  7.381 17.196 8.555 20.832 ;
     RECT  8.485 26.24 8.579 29.28 ;
     RECT  7.573 10.24 8.61 10.272 ;
     RECT  8.245 11.648 8.61 12.66 ;
     RECT  8.61 10.24 8.675 12.66 ;
     RECT  8.171 6.272 8.677 7.26 ;
     RECT  8.675 10.56 8.683 12.66 ;
     RECT  7.717 49.472 8.821 50.46 ;
     RECT  3.539 47.296 8.869 47.328 ;
     RECT  8.821 49.472 8.89 50.784 ;
     RECT  8.869 46.912 9.059 47.328 ;
     RECT  3.898 14.08 9.061 14.112 ;
     RECT  7.909 41.856 9.461 45.06 ;
     RECT  9.059 46.912 9.461 46.944 ;
     RECT  9.461 41.856 9.539 46.944 ;
     RECT  8.555 17.196 10.213 19.232 ;
     RECT  8.683 11.648 10.229 12.66 ;
     RECT  9.061 14.08 10.229 14.24 ;
     RECT  10.229 11.648 10.283 14.24 ;
     RECT  8.579 27.328 10.307 29.28 ;
     RECT  8.677 6.016 10.338 7.26 ;
     RECT  0 0.996 10.485 1.86 ;
     RECT  10.338 4.864 10.485 7.26 ;
     RECT  10.283 11.796 10.499 14.24 ;
     RECT  10.485 4.544 10.501 7.26 ;
     RECT  9.539 42.432 10.549 46.944 ;
     RECT  10.501 4.544 10.643 8.48 ;
     RECT  6.323 22.596 10.693 23.46 ;
     RECT  7.091 38.796 10.789 39.66 ;
     RECT  10.549 42.432 10.795 47.584 ;
     RECT  9.637 37.44 10.931 37.472 ;
     RECT  8.89 49.472 10.933 50.46 ;
     RECT  10.499 14.016 10.979 14.24 ;
     RECT  8.485 31.552 10.979 31.584 ;
     RECT  10.979 14.208 11.317 14.24 ;
     RECT  11.317 14.208 11.371 14.88 ;
     RECT  10.693 22.144 11.651 23.46 ;
     RECT  10.307 27.996 11.749 29.28 ;
     RECT  11.749 27.712 11.941 29.28 ;
     RECT  10.789 38.796 11.941 40.032 ;
     RECT  10.499 11.796 11.989 12.66 ;
     RECT  10.643 5.632 12.075 8.48 ;
     RECT  11.989 10.688 12.075 12.66 ;
     RECT  11.941 27.712 12.206 30.24 ;
     RECT  11.651 22.596 12.213 23.46 ;
     RECT  8.555 20.8 12.267 20.832 ;
     RECT  12.206 27.712 12.267 30.816 ;
     RECT  12.267 30.208 12.275 30.816 ;
     RECT  11.941 38.656 12.341 40.032 ;
     RECT  12.341 38.144 12.417 40.032 ;
     RECT  10.933 48.768 12.563 50.46 ;
     RECT  12.075 5.632 12.803 7.968 ;
     RECT  12.213 22.596 12.947 24.16 ;
     RECT  10.213 16.192 13.043 19.232 ;
     RECT  12.563 49.024 13.045 50.46 ;
     RECT  13.043 16.512 13.099 19.232 ;
     RECT  13.045 49.024 13.114 50.784 ;
     RECT  12.803 5.632 13.139 7.392 ;
     RECT  10.795 42.432 13.187 46.816 ;
     RECT  12.417 38.144 13.379 39.66 ;
     RECT  11.371 14.848 13.571 14.88 ;
     RECT  12.947 22.596 13.669 23.46 ;
     RECT  13.114 49.024 13.955 50.46 ;
     RECT  12.373 36.416 14.053 36.448 ;
     RECT  14.053 36.416 14.123 37.024 ;
     RECT  13.187 43.008 14.197 46.816 ;
     RECT  14.197 43.008 14.251 47.904 ;
     RECT  14.251 46.4 14.266 47.904 ;
     RECT  14.123 36.416 14.291 36.448 ;
     RECT  12.267 27.712 14.517 28.86 ;
     RECT  12.275 30.208 14.517 30.24 ;
     RECT  14.266 46.4 14.531 46.816 ;
     RECT  14.517 27.712 14.571 30.24 ;
     RECT  12.075 10.752 14.629 12.66 ;
     RECT  13.669 21.696 14.773 23.46 ;
     RECT  14.251 43.008 14.773 45.06 ;
     RECT  13.379 38.796 14.821 39.66 ;
     RECT  14.773 21.696 14.891 23.968 ;
     RECT  14.837 25.984 14.915 26.016 ;
     RECT  14.821 38.796 15.147 40.48 ;
     RECT  14.773 42.24 15.147 45.06 ;
     RECT  14.531 46.4 15.147 46.432 ;
     RECT  14.197 3.648 15.299 3.68 ;
     RECT  13.099 17.196 15.349 19.232 ;
     RECT  10.485 0.996 15.443 2.016 ;
     RECT  14.891 21.696 15.443 23.46 ;
     RECT  14.571 27.712 15.443 29.664 ;
     RECT  15.669 8.832 15.742 8.864 ;
     RECT  15.443 27.712 15.877 28.86 ;
     RECT  15.877 27.648 15.925 28.86 ;
     RECT  13.955 49.596 16.117 50.46 ;
     RECT  16.098 51.904 16.117 51.936 ;
     RECT  16.117 49.472 16.29 51.936 ;
     RECT  16.238 14.336 16.309 14.368 ;
     RECT  15.147 43.008 16.309 45.06 ;
     RECT  16.29 49.472 16.363 53.216 ;
     RECT  16.309 43.008 16.501 46.304 ;
     RECT  16.309 47.872 16.501 47.904 ;
     RECT  16.309 30.144 16.555 30.176 ;
     RECT  15.147 38.796 16.565 39.66 ;
     RECT  16.261 41.408 16.565 41.44 ;
     RECT  16.565 41.216 16.629 41.44 ;
     RECT  16.501 43.008 16.629 47.904 ;
     RECT  16.629 41.216 16.883 47.904 ;
     RECT  16.883 47.488 17.029 47.904 ;
     RECT  16.363 49.472 17.029 52.768 ;
     RECT  15.925 26.496 17.077 28.86 ;
     RECT  16.069 31.936 17.077 31.968 ;
     RECT  16.565 38.656 17.077 39.66 ;
     RECT  16.883 41.216 17.077 45.06 ;
     RECT  14.629 10.56 17.461 12.66 ;
     RECT  16.309 14.336 17.461 15.456 ;
     RECT  17.077 26.496 17.509 29.216 ;
     RECT  17.461 10.56 17.515 15.456 ;
     RECT  17.029 47.488 17.515 52.768 ;
     RECT  17.077 30.912 17.525 31.968 ;
     RECT  6.611 33.396 17.525 34.26 ;
     RECT  15.443 22.596 17.557 23.46 ;
     RECT  17.515 10.816 17.605 15.456 ;
     RECT  15.349 17.196 17.605 19.36 ;
     RECT  17.605 10.816 17.771 19.36 ;
     RECT  17.771 11.072 17.803 19.36 ;
     RECT  17.557 4.224 17.826 4.256 ;
     RECT  17.803 11.072 17.899 19.744 ;
     RECT  17.557 21.696 17.899 23.46 ;
     RECT  17.515 47.68 18.046 48.16 ;
     RECT  17.826 3.328 18.133 4.256 ;
     RECT  13.139 6.396 18.133 7.392 ;
     RECT  17.899 21.76 18.181 23.46 ;
     RECT  18.133 3.328 18.219 7.456 ;
     RECT  17.899 11.072 18.283 18.06 ;
     RECT  17.525 30.912 18.419 34.26 ;
     RECT  17.077 38.656 18.419 45.06 ;
     RECT  18.181 21.76 18.485 24.672 ;
     RECT  18.419 41.408 18.517 45.06 ;
     RECT  18.485 21.76 18.539 24.928 ;
     RECT  18.517 41.408 18.603 45.664 ;
     RECT  17.515 49.596 18.611 52.768 ;
     RECT  18.419 31.104 18.757 34.26 ;
     RECT  18.539 22.596 18.805 24.928 ;
     RECT  17.509 26.24 18.805 29.216 ;
     RECT  17.899 19.712 18.851 19.744 ;
     RECT  18.805 22.596 18.859 29.216 ;
     RECT  18.859 22.596 18.987 26.272 ;
     RECT  18.419 38.656 19.141 39.66 ;
     RECT  18.859 27.648 19.283 29.216 ;
     RECT  18.283 11.072 19.285 12.66 ;
     RECT  18.805 53.568 19.333 53.6 ;
     RECT  0 54.996 19.333 55.86 ;
     RECT  18.987 22.596 19.427 26.144 ;
     RECT  19.333 53.568 19.435 55.86 ;
     RECT  19.285 10.816 19.637 12.66 ;
     RECT  18.283 14.144 19.637 18.06 ;
     RECT  18.046 48.128 19.701 48.16 ;
     RECT  18.611 49.596 19.811 52.192 ;
     RECT  18.603 41.408 19.909 45.06 ;
     RECT  19.701 46.912 19.909 48.16 ;
     RECT  18.219 3.328 20.005 3.36 ;
     RECT  17.605 8.768 20.149 8.8 ;
     RECT  19.637 10.816 20.149 18.06 ;
     RECT  20.149 8.768 20.203 18.06 ;
     RECT  18.757 31.104 20.243 36.192 ;
     RECT  19.141 38.528 20.339 39.66 ;
     RECT  19.909 41.408 20.395 48.16 ;
     RECT  15.443 0.996 20.437 1.86 ;
     RECT  20.005 3.328 20.437 3.488 ;
     RECT  20.395 42.752 20.523 48.16 ;
     RECT  19.435 53.76 20.629 55.86 ;
     RECT  20.629 53.76 20.715 55.968 ;
     RECT  20.203 9.344 20.819 18.06 ;
     RECT  20.523 42.816 20.853 48.16 ;
     RECT  19.283 27.648 20.965 29.024 ;
     RECT  0 60.396 20.965 61.26 ;
     RECT  20.243 31.104 21.011 34.26 ;
     RECT  20.819 10.816 21.061 18.06 ;
     RECT  20.965 27.648 21.061 29.408 ;
     RECT  20.853 42.816 21.155 48.224 ;
     RECT  20.965 60.396 21.157 62.432 ;
     RECT  21.061 10.816 21.178 19.04 ;
     RECT  21.178 17.196 21.365 19.04 ;
     RECT  21.365 17.196 21.443 19.744 ;
     RECT  19.811 49.596 21.589 51.936 ;
     RECT  21.157 60.224 21.589 62.432 ;
     RECT  20.437 0.996 21.635 3.488 ;
     RECT  20.339 38.796 21.637 39.66 ;
     RECT  19.427 22.596 21.685 25.824 ;
     RECT  21.061 27.392 21.685 29.408 ;
     RECT  21.589 49.596 21.685 52.32 ;
     RECT  20.715 53.76 21.685 55.86 ;
     RECT  21.178 10.816 21.731 15.264 ;
     RECT  21.637 38.796 21.733 40.48 ;
     RECT  21.155 44.196 21.733 48.224 ;
     RECT  21.685 49.596 21.733 55.86 ;
     RECT  21.589 59.264 21.733 62.432 ;
     RECT  18.219 5.184 21.779 7.392 ;
     RECT  21.155 42.816 21.803 42.848 ;
     RECT  21.733 44.196 21.803 55.86 ;
     RECT  21.589 57.792 21.931 57.824 ;
     RECT  21.733 38.796 22.059 41.056 ;
     RECT  21.731 11.136 22.259 15.264 ;
     RECT  21.733 59.136 22.259 62.432 ;
     RECT  21.803 46.528 22.315 55.86 ;
     RECT  21.685 22.596 22.325 29.6 ;
     RECT  21.011 32.192 22.325 34.26 ;
     RECT  20.243 36.16 22.325 36.192 ;
     RECT  22.315 46.656 22.355 55.86 ;
     RECT  22.325 32.192 22.379 36.192 ;
     RECT  22.325 22.596 22.403 30.56 ;
     RECT  22.379 32.192 22.451 36.064 ;
     RECT  21.635 0.996 22.595 3.36 ;
     RECT  22.325 20.608 22.595 20.64 ;
     RECT  22.059 38.796 22.597 40.48 ;
     RECT  21.443 17.196 22.741 19.296 ;
     RECT  22.403 22.596 22.835 29.6 ;
     RECT  22.835 22.596 23.029 29.28 ;
     RECT  22.259 14.144 23.083 15.136 ;
     RECT  23.029 21.952 23.083 29.28 ;
     RECT  22.259 59.136 23.093 61.856 ;
     RECT  21.779 5.184 23.123 7.26 ;
     RECT  23.093 58.88 23.171 61.856 ;
     RECT  23.171 58.88 23.275 58.912 ;
     RECT  22.597 38.144 23.411 40.48 ;
     RECT  21.803 44.196 23.861 45.06 ;
     RECT  22.355 47.232 23.915 55.86 ;
     RECT  23.083 14.144 23.987 14.816 ;
     RECT  23.083 24.896 23.987 29.28 ;
     RECT  22.741 17.024 24.085 19.296 ;
     RECT  23.915 49.596 24.181 55.86 ;
     RECT  22.451 32.192 24.421 34.26 ;
     RECT  22.451 36.032 24.421 36.064 ;
     RECT  23.171 60.396 24.469 61.856 ;
     RECT  24.469 60.396 24.517 62.176 ;
     RECT  23.987 24.896 24.563 29.088 ;
     RECT  20.819 9.344 24.613 9.376 ;
     RECT  22.259 11.136 24.613 12.66 ;
     RECT  24.421 32.192 24.613 36.064 ;
     RECT  23.861 44.196 24.629 45.344 ;
     RECT  24.085 17.024 24.659 20.576 ;
     RECT  24.613 32.192 24.683 36.512 ;
     RECT  23.987 14.144 24.707 14.432 ;
     RECT  23.083 21.952 24.755 23.584 ;
     RECT  24.683 32.192 24.997 35.424 ;
     RECT  23.411 38.144 24.997 39.776 ;
     RECT  24.613 9.344 25.003 12.66 ;
     RECT  24.997 31.36 25.067 35.424 ;
     RECT  24.997 37.568 25.131 39.776 ;
     RECT  25.003 9.344 25.139 9.504 ;
     RECT  24.563 27.996 25.139 29.088 ;
     RECT  23.123 5.312 25.333 7.26 ;
     RECT  24.181 49.596 25.333 56.48 ;
     RECT  24.517 59.776 25.387 62.176 ;
     RECT  25.333 5.312 25.475 8.16 ;
     RECT  25.003 10.816 25.573 12.66 ;
     RECT  24.707 14.144 25.573 14.176 ;
     RECT  25.333 49.596 25.579 57.568 ;
     RECT  25.573 10.816 25.643 14.176 ;
     RECT  24.659 17.196 25.643 20.576 ;
     RECT  22.595 0.996 25.698 2.08 ;
     RECT  23.893 3.968 25.763 4 ;
     RECT  25.698 0.996 25.771 2.592 ;
     RECT  25.643 10.816 25.786 12.66 ;
     RECT  24.629 43.264 25.813 45.344 ;
     RECT  25.131 38.144 25.845 39.776 ;
     RECT  25.813 43.136 25.845 45.344 ;
     RECT  23.915 47.232 25.845 47.84 ;
     RECT  24.563 24.896 26.082 26.016 ;
     RECT  25.139 27.996 26.082 29.024 ;
     RECT  25.845 43.136 26.091 47.84 ;
     RECT  25.771 0.996 26.099 2.08 ;
     RECT  24.755 22.336 26.149 23.584 ;
     RECT  26.082 24.896 26.149 29.024 ;
     RECT  25.643 20.544 26.155 20.576 ;
     RECT  25.579 49.596 26.243 53.536 ;
     RECT  25.579 54.848 26.243 57.568 ;
     RECT  25.475 6.272 26.283 8.16 ;
     RECT  25.139 9.472 26.387 9.504 ;
     RECT  26.091 43.136 26.411 45.06 ;
     RECT  26.149 22.336 26.485 29.024 ;
     RECT  26.485 21.632 26.554 29.024 ;
     RECT  25.387 59.776 26.629 61.856 ;
     RECT  26.554 22.336 26.667 29.024 ;
     RECT  25.067 32.192 26.725 35.424 ;
     RECT  25.845 38.144 26.725 39.84 ;
     RECT  26.629 59.2 26.795 61.856 ;
     RECT  25.643 14.144 26.819 14.176 ;
     RECT  25.643 17.196 26.869 19.04 ;
     RECT  26.667 22.596 27.13 29.024 ;
     RECT  26.869 16.768 27.618 19.04 ;
     RECT  26.725 30.592 27.637 30.624 ;
     RECT  26.725 32.192 27.637 39.84 ;
     RECT  27.13 27.996 27.685 29.024 ;
     RECT  27.637 30.592 27.685 39.84 ;
     RECT  27.618 16.768 27.691 20.576 ;
     RECT  27.685 27.996 27.701 39.84 ;
     RECT  27.691 16.768 27.755 19.936 ;
     RECT  27.701 27.996 27.755 39.968 ;
     RECT  25.477 63.296 27.971 63.328 ;
     RECT  25.786 11.796 28.117 12.66 ;
     RECT  26.411 43.264 28.194 45.06 ;
     RECT  26.091 46.784 28.194 47.84 ;
     RECT  26.725 41.664 28.213 41.696 ;
     RECT  28.194 43.264 28.213 47.84 ;
     RECT  27.755 31.232 28.267 39.968 ;
     RECT  28.213 41.664 28.267 47.84 ;
     RECT  27.755 17.196 28.282 19.936 ;
     RECT  26.283 6.272 28.386 7.712 ;
     RECT  27.13 22.596 28.453 26.016 ;
     RECT  28.453 22.596 28.459 26.656 ;
     RECT  28.267 31.232 28.523 35.744 ;
     RECT  28.267 37.568 28.597 39.968 ;
     RECT  28.597 37.568 28.779 40.48 ;
     RECT  29.077 3.52 29.109 3.68 ;
     RECT  28.386 5.568 29.109 7.712 ;
     RECT  29.109 3.52 29.227 7.712 ;
     RECT  29.227 4.544 29.269 7.712 ;
     RECT  28.282 19.776 29.538 19.936 ;
     RECT  28.282 17.196 29.611 18.272 ;
     RECT  29.538 19.776 29.611 20.96 ;
     RECT  28.117 10.496 29.621 12.66 ;
     RECT  29.621 9.728 29.675 12.66 ;
     RECT  26.099 0.996 29.699 2.016 ;
     RECT  29.675 9.728 29.699 9.76 ;
     RECT  28.779 37.568 29.797 39.84 ;
     RECT  26.795 59.264 29.797 61.856 ;
     RECT  28.523 31.232 29.813 35.168 ;
     RECT  29.797 37.056 29.813 39.84 ;
     RECT  26.243 54.996 29.813 57.568 ;
     RECT  29.797 59.264 29.813 62.752 ;
     RECT  28.267 42.496 29.877 45.06 ;
     RECT  28.459 26.624 30.133 26.656 ;
     RECT  27.755 27.996 30.133 28.86 ;
     RECT  29.813 54.996 30.142 62.752 ;
     RECT  28.459 22.596 30.187 25.248 ;
     RECT  29.813 31.232 30.202 39.84 ;
     RECT  26.243 49.596 30.325 53.344 ;
     RECT  30.142 54.996 30.325 61.856 ;
     RECT  30.202 31.232 30.371 36 ;
     RECT  30.133 26.624 30.498 28.86 ;
     RECT  29.877 42.496 30.638 45.6 ;
     RECT  28.267 47.808 30.638 47.84 ;
     RECT  30.638 42.496 30.707 47.84 ;
     RECT  29.675 11.648 30.757 12.66 ;
     RECT  29.269 4.544 30.803 7.968 ;
     RECT  30.707 42.496 30.803 45.6 ;
     RECT  30.803 42.496 30.853 45.472 ;
     RECT  30.371 32.192 30.947 36 ;
     RECT  30.853 41.472 30.955 45.472 ;
     RECT  30.955 41.856 31.235 45.472 ;
     RECT  30.803 5.76 31.379 7.968 ;
     RECT  30.707 47.808 31.379 47.84 ;
     RECT  31.157 63.296 31.379 63.328 ;
     RECT  30.325 49.152 31.427 61.856 ;
     RECT  30.187 22.596 31.669 24.992 ;
     RECT  30.498 26.56 31.669 28.86 ;
     RECT  31.669 22.596 31.723 28.86 ;
     RECT  31.427 49.152 31.723 58.592 ;
     RECT  30.947 32.192 31.909 35.936 ;
     RECT  29.699 0.996 31.925 1.86 ;
     RECT  29.611 19.776 31.955 19.808 ;
     RECT  31.723 24.96 31.955 28.86 ;
     RECT  31.723 49.152 31.955 57.056 ;
     RECT  31.909 31.936 31.979 35.936 ;
     RECT  30.202 37.824 32.235 39.84 ;
     RECT  30.709 30.4 32.531 30.432 ;
     RECT  31.235 41.856 32.531 42.912 ;
     RECT  31.379 5.76 32.994 7.26 ;
     RECT  32.533 9.536 32.994 9.568 ;
     RECT  32.994 9.536 33.013 9.632 ;
     RECT  31.979 32.192 33.013 35.936 ;
     RECT  32.235 37.824 33.013 39.66 ;
     RECT  31.955 49.152 33.013 50.46 ;
     RECT  32.994 5.76 33.067 7.392 ;
     RECT  33.013 9.472 33.067 9.632 ;
     RECT  31.955 53.824 33.141 57.056 ;
     RECT  31.723 58.56 33.141 58.592 ;
     RECT  31.427 60.288 33.141 61.856 ;
     RECT  33.141 59.968 33.443 61.856 ;
     RECT  31.955 51.968 33.541 52.384 ;
     RECT  33.141 53.824 33.541 57.12 ;
     RECT  31.235 44.196 33.973 45.472 ;
     RECT  33.541 51.968 34.069 57.12 ;
     RECT  33.141 58.432 34.069 58.592 ;
     RECT  33.013 48.96 34.101 50.46 ;
     RECT  34.069 51.968 34.101 58.592 ;
     RECT  34.101 48.96 34.117 58.592 ;
     RECT  34.117 48.576 34.155 58.592 ;
     RECT  33.067 5.76 34.165 7.26 ;
     RECT  30.757 11.648 34.165 13.088 ;
     RECT  29.611 17.196 34.165 18.208 ;
     RECT  34.165 10.944 34.219 13.088 ;
     RECT  32.531 41.856 34.789 41.888 ;
     RECT  34.155 58.56 34.795 58.592 ;
     RECT  34.789 41.856 34.835 42.016 ;
     RECT  33.443 60.396 34.997 61.856 ;
     RECT  31.723 22.596 35.029 23.46 ;
     RECT  34.997 60.096 35.189 61.856 ;
     RECT  35.189 60.096 35.219 62.752 ;
     RECT  34.219 10.944 35.557 12.66 ;
     RECT  35.219 60.288 35.557 62.752 ;
     RECT  34.165 16 35.573 18.528 ;
     RECT  33.973 44.196 35.573 45.6 ;
     RECT  35.509 46.912 35.573 46.944 ;
     RECT  35.557 10.944 35.627 12.768 ;
     RECT  35.573 14.848 35.627 18.528 ;
     RECT  34.155 48.576 35.627 57.12 ;
     RECT  35.573 44.196 35.701 46.944 ;
     RECT  34.165 5.696 35.795 7.26 ;
     RECT  35.029 22.272 35.893 23.46 ;
     RECT  34.261 3.456 35.939 3.488 ;
     RECT  35.627 48.96 35.939 57.12 ;
     RECT  35.627 17.196 36.277 18.528 ;
     RECT  35.893 21.952 36.325 23.46 ;
     RECT  31.955 25.728 36.325 28.86 ;
     RECT  36.277 17.196 36.346 18.848 ;
     RECT  36.325 21.952 36.459 28.86 ;
     RECT  34.981 30.528 36.515 30.56 ;
     RECT  33.013 32.192 36.981 39.66 ;
     RECT  36.981 30.976 37.054 39.66 ;
     RECT  36.459 25.728 37.091 26.08 ;
     RECT  35.939 48.96 37.227 57.056 ;
     RECT  37.173 58.56 37.246 58.592 ;
     RECT  37.227 49.596 37.331 57.056 ;
     RECT  37.331 49.596 37.547 53.216 ;
     RECT  31.925 0.064 37.573 1.86 ;
     RECT  37.669 58.624 37.739 58.656 ;
     RECT  35.557 60.288 37.739 63.008 ;
     RECT  34.835 41.984 38.133 42.016 ;
     RECT  35.795 5.76 38.197 7.26 ;
     RECT  33.067 9.472 38.197 9.568 ;
     RECT  35.627 10.944 38.197 12.66 ;
     RECT  38.197 9.472 38.251 12.832 ;
     RECT  36.459 27.996 38.437 28.86 ;
     RECT  37.091 26.048 38.453 26.08 ;
     RECT  37.054 32.192 38.453 39.66 ;
     RECT  38.133 41.408 38.453 42.016 ;
     RECT  38.251 9.536 38.483 12.832 ;
     RECT  35.627 14.848 38.483 14.88 ;
     RECT  38.453 25.6 38.483 26.08 ;
     RECT  38.453 32.192 38.485 42.016 ;
     RECT  38.437 27.996 38.507 29.856 ;
     RECT  36.789 4.416 38.517 4.448 ;
     RECT  38.197 5.76 38.517 7.968 ;
     RECT  38.517 4.416 38.579 7.968 ;
     RECT  38.579 6.144 38.627 7.968 ;
     RECT  37.573 0.064 38.725 3.04 ;
     RECT  36.346 17.196 38.819 18.208 ;
     RECT  38.483 25.6 38.819 25.632 ;
     RECT  38.579 4.416 38.867 4.576 ;
     RECT  38.485 31.872 39.029 42.016 ;
     RECT  37.331 54.72 39.029 57.056 ;
     RECT  38.725 58.688 39.029 58.72 ;
     RECT  39.029 54.72 39.157 58.72 ;
     RECT  39.029 31.68 39.221 42.016 ;
     RECT  35.701 44.196 39.221 47.648 ;
     RECT  39.157 54.72 39.251 58.784 ;
     RECT  39.221 31.68 39.339 47.648 ;
     RECT  36.997 20.288 39.349 20.32 ;
     RECT  36.459 21.952 39.349 23.46 ;
     RECT  38.507 27.996 39.491 29.6 ;
     RECT  39.339 42.048 39.595 47.648 ;
     RECT  39.339 31.68 39.659 40.736 ;
     RECT  37.547 49.596 39.685 53.024 ;
     RECT  39.251 54.72 39.685 58.72 ;
     RECT  38.725 0.064 39.971 3.104 ;
     RECT  39.595 42.112 40.021 47.648 ;
     RECT  40.021 42.112 40.181 48.16 ;
     RECT  39.685 49.596 40.181 58.72 ;
     RECT  40.181 42.112 40.299 58.72 ;
     RECT  38.483 10.944 40.309 12.832 ;
     RECT  39.349 15.744 40.309 15.776 ;
     RECT  38.819 17.196 40.309 18.06 ;
     RECT  40.299 42.112 40.355 57.824 ;
     RECT  40.309 10.944 40.378 18.06 ;
     RECT  40.378 16 40.405 18.06 ;
     RECT  38.627 6.144 40.595 7.26 ;
     RECT  39.659 31.68 40.595 40.352 ;
     RECT  38.867 4.416 41.075 4.448 ;
     RECT  40.405 16 41.077 18.784 ;
     RECT  39.349 20.288 41.077 23.46 ;
     RECT  41.077 16 41.123 23.46 ;
     RECT  41.123 16 41.195 21.088 ;
     RECT  41.195 16 41.387 20.576 ;
     RECT  37.739 60.396 41.509 63.008 ;
     RECT  40.378 10.944 41.557 13.664 ;
     RECT  41.123 22.464 41.557 23.46 ;
     RECT  41.387 16 41.603 18.06 ;
     RECT  41.557 10.688 41.651 13.664 ;
     RECT  40.355 53.824 41.653 57.824 ;
     RECT  40.405 30.336 41.909 30.368 ;
     RECT  40.595 31.68 41.909 40.224 ;
     RECT  41.653 53.76 41.909 57.824 ;
     RECT  41.909 30.336 41.963 40.224 ;
     RECT  40.355 42.112 42.101 52.384 ;
     RECT  42.101 42.112 42.227 52.448 ;
     RECT  41.509 60.396 42.293 63.264 ;
     RECT  42.227 42.112 42.323 52.384 ;
     RECT  41.909 53.76 42.323 57.952 ;
     RECT  42.323 53.76 42.347 57.632 ;
     RECT  41.963 30.464 42.475 40.224 ;
     RECT  40.595 6.396 42.709 7.26 ;
     RECT  39.491 27.996 42.709 28.86 ;
     RECT  41.557 22.464 42.853 24.032 ;
     RECT  42.853 22.4 42.923 24.032 ;
     RECT  42.293 59.52 42.947 63.264 ;
     RECT  42.757 14.912 43.317 14.944 ;
     RECT  41.603 16.704 43.317 18.06 ;
     RECT  39.971 0.064 43.379 3.04 ;
     RECT  41.651 10.688 43.379 12.832 ;
     RECT  41.387 20.288 43.861 20.448 ;
     RECT  42.475 30.464 43.861 37.152 ;
     RECT  43.125 9.28 43.893 9.312 ;
     RECT  43.861 19.392 43.893 20.448 ;
     RECT  43.861 30.208 43.893 37.152 ;
     RECT  42.475 38.464 43.893 40.224 ;
     RECT  42.323 42.112 43.893 52.256 ;
     RECT  42.347 53.76 43.893 57.312 ;
     RECT  42.709 5.824 43.947 7.392 ;
     RECT  43.893 30.208 43.947 40.224 ;
     RECT  43.893 42.112 43.947 57.312 ;
     RECT  43.947 30.208 43.955 39.66 ;
     RECT  42.709 27.136 44.195 28.86 ;
     RECT  43.955 31.552 44.339 39.66 ;
     RECT  43.893 8.704 44.405 9.312 ;
     RECT  43.379 10.688 44.405 12.66 ;
     RECT  42.923 22.464 44.405 24.032 ;
     RECT  42.947 59.52 44.437 63.008 ;
     RECT  43.317 14.912 44.459 18.06 ;
     RECT  43.893 19.392 44.459 20.512 ;
     RECT  43.955 30.208 44.459 30.24 ;
     RECT  43.947 42.112 44.459 55.86 ;
     RECT  44.459 14.912 44.483 15.776 ;
     RECT  44.339 38.592 44.627 39.66 ;
     RECT  43.947 57.28 44.965 57.312 ;
     RECT  44.339 31.552 45.059 37.28 ;
     RECT  44.405 8.704 45.061 12.66 ;
     RECT  45.061 8.704 45.107 12.768 ;
     RECT  44.405 22.464 45.203 25.184 ;
     RECT  43.379 0.064 45.301 2.912 ;
     RECT  44.459 42.112 45.395 52.256 ;
     RECT  44.459 53.824 45.493 55.86 ;
     RECT  44.965 57.28 45.493 57.632 ;
     RECT  45.203 25.152 45.635 25.184 ;
     RECT  45.395 52.096 45.675 52.256 ;
     RECT  45.395 42.112 45.694 50.784 ;
     RECT  45.301 0.064 45.781 3.936 ;
     RECT  43.947 5.824 45.781 7.26 ;
     RECT  45.107 8.704 45.827 8.736 ;
     RECT  45.203 22.464 45.858 23.46 ;
     RECT  45.059 35.968 45.875 37.28 ;
     RECT  45.781 0.064 45.877 7.26 ;
     RECT  45.877 0.064 45.931 8.544 ;
     RECT  45.858 21.184 45.931 23.46 ;
     RECT  45.875 35.968 46.067 37.152 ;
     RECT  45.107 10.112 46.069 12.768 ;
     RECT  44.483 15.744 46.069 15.776 ;
     RECT  46.069 10.112 46.138 13.088 ;
     RECT  45.931 5.824 46.307 8.544 ;
     RECT  45.059 31.552 46.307 34.26 ;
     RECT  45.931 22.464 46.595 23.46 ;
     RECT  45.931 0.064 46.787 3.936 ;
     RECT  46.138 10.112 46.787 12.66 ;
     RECT  46.069 14.848 46.787 15.776 ;
     RECT  45.694 42.112 47.285 50.656 ;
     RECT  44.627 38.656 47.394 39.66 ;
     RECT  47.394 38.592 47.413 39.66 ;
     RECT  47.413 38.592 47.467 39.968 ;
     RECT  46.067 36.224 47.477 37.152 ;
     RECT  47.285 41.6 47.531 50.656 ;
     RECT  45.493 53.824 47.541 57.632 ;
     RECT  44.437 59.52 47.541 63.072 ;
     RECT  47.541 53.824 47.555 63.072 ;
     RECT  47.531 44.196 47.653 50.656 ;
     RECT  47.653 44.196 47.669 50.72 ;
     RECT  45.675 52.096 47.669 52.128 ;
     RECT  46.693 26.304 47.845 26.336 ;
     RECT  44.195 27.996 47.845 28.86 ;
     RECT  47.555 53.824 47.851 57.248 ;
     RECT  47.669 44.196 47.861 52.128 ;
     RECT  47.851 53.824 47.861 57.056 ;
     RECT  47.531 41.6 47.866 42.784 ;
     RECT  47.845 25.088 47.915 28.86 ;
     RECT  46.307 5.824 47.97 7.26 ;
     RECT  46.787 10.56 47.97 12.66 ;
     RECT  47.861 44.196 47.979 57.056 ;
     RECT  47.915 26.688 47.987 28.86 ;
     RECT  47.97 5.824 47.989 7.712 ;
     RECT  47.989 5.056 48.043 7.712 ;
     RECT  47.97 10.56 48.043 13.024 ;
     RECT  46.787 15.424 48.058 15.776 ;
     RECT  48.043 5.056 48.083 5.088 ;
     RECT  47.987 26.752 48.083 28.86 ;
     RECT  47.555 58.624 48.131 63.072 ;
     RECT  46.787 0.064 48.419 2.656 ;
     RECT  44.459 17.196 48.437 18.06 ;
     RECT  46.595 22.596 48.437 23.46 ;
     RECT  47.915 25.088 48.437 25.184 ;
     RECT  48.419 0.064 48.491 2.336 ;
     RECT  48.437 22.596 48.491 25.184 ;
     RECT  48.437 17.196 48.501 18.208 ;
     RECT  47.467 38.796 48.515 39.968 ;
     RECT  48.501 17.088 48.565 18.208 ;
     RECT  47.541 20.736 48.565 20.768 ;
     RECT  48.565 17.088 48.611 20.768 ;
     RECT  47.979 51.968 48.619 57.056 ;
     RECT  47.477 36.224 48.693 37.28 ;
     RECT  48.491 22.596 48.709 25.12 ;
     RECT  46.307 31.936 48.709 34.26 ;
     RECT  48.058 15.744 48.747 15.776 ;
     RECT  48.611 17.196 48.757 20.768 ;
     RECT  48.709 22.272 48.757 25.12 ;
     RECT  48.693 36.096 48.766 37.28 ;
     RECT  48.757 17.196 49.003 25.12 ;
     RECT  48.619 54.848 49.003 57.056 ;
     RECT  48.131 59.52 49.237 63.072 ;
     RECT  49.003 17.196 49.283 19.296 ;
     RECT  48.043 10.56 49.333 12.66 ;
     RECT  48.709 30.976 49.333 34.26 ;
     RECT  49.333 10.368 49.387 13.152 ;
     RECT  49.387 11.796 49.427 13.152 ;
     RECT  49.003 20.992 49.619 25.12 ;
     RECT  47.979 44.196 49.845 50.46 ;
     RECT  48.083 26.944 49.861 28.86 ;
     RECT  49.619 25.088 50.037 25.12 ;
     RECT  49.861 26.816 50.037 28.86 ;
     RECT  50.037 25.088 50.091 28.86 ;
     RECT  48.766 36.8 50.101 37.28 ;
     RECT  50.091 25.664 50.11 28.86 ;
     RECT  49.619 20.992 50.147 23.46 ;
     RECT  48.619 51.968 50.195 52 ;
     RECT  49.333 30.464 50.229 34.26 ;
     RECT  50.101 35.776 50.229 37.28 ;
     RECT  50.229 30.464 50.291 37.28 ;
     RECT  50.291 30.464 50.302 37.152 ;
     RECT  50.302 30.464 50.347 34.26 ;
     RECT  50.347 30.464 50.362 30.752 ;
     RECT  47.866 41.6 50.613 42.272 ;
     RECT  50.11 26.624 50.677 28.86 ;
     RECT  50.677 26.624 50.771 30.112 ;
     RECT  49.845 43.84 50.771 50.46 ;
     RECT  48.515 38.796 51.253 39.66 ;
     RECT  50.613 41.024 51.253 42.272 ;
     RECT  50.771 26.816 51.299 30.112 ;
     RECT  49.237 59.52 51.299 63.328 ;
     RECT  51.253 38.796 51.371 42.272 ;
     RECT  50.771 44.032 51.395 50.46 ;
     RECT  51.371 42.24 51.443 42.272 ;
     RECT  51.299 59.52 51.539 62.496 ;
     RECT  50.147 21.952 51.829 23.46 ;
     RECT  50.347 33.088 51.829 34.26 ;
     RECT  50.302 35.776 51.829 37.152 ;
     RECT  49.283 17.196 51.877 18.06 ;
     RECT  51.829 33.088 51.971 37.152 ;
     RECT  51.299 27.392 51.973 30.112 ;
     RECT  49.003 54.848 52.002 55.86 ;
     RECT  51.539 59.648 52.115 61.408 ;
     RECT  51.973 27.392 52.149 30.432 ;
     RECT  52.149 27.392 52.203 31.392 ;
     RECT  51.971 35.776 52.403 37.152 ;
     RECT  51.829 21.888 52.405 23.46 ;
     RECT  52.403 35.968 52.547 37.152 ;
     RECT  51.371 38.796 52.578 39.904 ;
     RECT  52.578 38.144 52.651 39.904 ;
     RECT  52.002 54.848 52.837 55.968 ;
     RECT  51.877 16.512 52.962 18.06 ;
     RECT  49.387 10.368 52.981 10.4 ;
     RECT  49.427 11.796 52.981 12.66 ;
     RECT  52.962 16.448 53.035 18.06 ;
     RECT  52.405 21.888 53.075 23.584 ;
     RECT  53.075 21.952 53.237 23.584 ;
     RECT  48.491 0.064 53.267 1.86 ;
     RECT  53.237 21.952 53.315 24.608 ;
     RECT  52.981 10.368 53.411 12.66 ;
     RECT  53.493 57.6 53.557 57.632 ;
     RECT  52.203 27.392 53.603 29.024 ;
     RECT  53.411 11.796 53.749 12.66 ;
     RECT  53.411 10.368 53.803 10.4 ;
     RECT  53.813 52.352 53.987 52.96 ;
     RECT  51.395 44.196 54.037 50.46 ;
     RECT  52.837 54.528 54.039 55.968 ;
     RECT  54.037 44.196 54.085 51.04 ;
     RECT  53.987 52.352 54.085 52.768 ;
     RECT  52.203 31.36 54.133 31.392 ;
     RECT  52.115 60.396 54.133 61.408 ;
     RECT  54.133 31.36 54.179 31.52 ;
     RECT  51.971 33.088 54.179 34.26 ;
     RECT  54.133 59.264 54.202 61.408 ;
     RECT  53.035 17.196 54.613 18.06 ;
     RECT  54.179 33.396 54.661 34.26 ;
     RECT  52.547 35.968 54.661 36.832 ;
     RECT  53.557 57.6 54.709 57.824 ;
     RECT  54.039 54.272 54.755 55.968 ;
     RECT  54.085 44.196 54.763 52.768 ;
     RECT  54.202 59.84 54.763 61.408 ;
     RECT  54.709 57.6 54.778 58.144 ;
     RECT  54.763 59.84 54.778 61.26 ;
     RECT  54.179 31.488 54.995 31.52 ;
     RECT  53.315 21.952 55.045 23.584 ;
     RECT  54.661 33.396 55.275 37.152 ;
     RECT  55.045 21.824 55.331 23.584 ;
     RECT  54.755 54.272 55.331 55.86 ;
     RECT  55.275 35.968 55.403 37.152 ;
     RECT  52.651 38.796 55.605 39.904 ;
     RECT  53.603 27.996 55.717 29.024 ;
     RECT  54.763 44.196 55.813 47.968 ;
     RECT  55.605 38.796 55.979 39.968 ;
     RECT  55.717 27.996 55.982 29.216 ;
     RECT  54.613 16.256 56.053 18.06 ;
     RECT  55.982 26.816 56.101 29.216 ;
     RECT  56.053 15.36 56.147 18.06 ;
     RECT  55.989 25.024 56.147 25.056 ;
     RECT  54.613 19.392 56.149 19.424 ;
     RECT  56.101 26.816 56.171 29.408 ;
     RECT  56.149 19.392 56.235 20 ;
     RECT  55.331 21.824 56.235 23.46 ;
     RECT  54.763 49.596 56.245 52.768 ;
     RECT  55.331 54.72 56.245 55.86 ;
     RECT  54.778 57.6 56.245 57.76 ;
     RECT  56.245 54.72 56.299 57.76 ;
     RECT  56.245 49.596 56.427 53.024 ;
     RECT  55.813 43.264 56.483 47.968 ;
     RECT  56.427 49.596 56.619 52.768 ;
     RECT  56.619 52.352 56.675 52.768 ;
     RECT  56.299 54.72 56.675 56.48 ;
     RECT  56.483 47.936 56.867 47.968 ;
     RECT  56.619 49.596 56.867 51.04 ;
     RECT  55.275 33.396 56.869 34.26 ;
     RECT  56.147 16.256 56.949 18.06 ;
     RECT  56.235 19.392 56.949 19.552 ;
     RECT  56.675 54.72 56.963 55.86 ;
     RECT  56.171 26.816 56.965 29.216 ;
     RECT  56.869 33.396 56.965 34.912 ;
     RECT  56.917 20.864 57.003 21.152 ;
     RECT  56.483 43.264 57.059 46.24 ;
     RECT  56.675 52.352 57.059 52.384 ;
     RECT  56.965 32.384 57.109 34.912 ;
     RECT  55.403 36.736 57.109 36.768 ;
     RECT  57.109 32.384 57.141 36.768 ;
     RECT  57.141 32.256 57.195 36.768 ;
     RECT  55.979 38.796 57.269 39.904 ;
     RECT  57.195 36.736 57.323 36.768 ;
     RECT  57.269 38.208 57.347 39.904 ;
     RECT  56.235 22.596 57.541 23.46 ;
     RECT  56.965 26.688 57.963 29.216 ;
     RECT  57.195 32.256 58.163 34.912 ;
     RECT  56.949 16.256 58.499 19.552 ;
     RECT  58.117 37.376 58.645 37.408 ;
     RECT  57.059 44.196 58.739 46.24 ;
     RECT  58.499 17.024 59.077 19.552 ;
     RECT  57.003 20.864 59.077 20.896 ;
     RECT  59.077 17.024 59.123 20.896 ;
     RECT  58.645 36.224 59.221 37.408 ;
     RECT  57.347 38.796 59.221 39.904 ;
     RECT  57.637 42.688 59.221 42.72 ;
     RECT  57.541 22.596 59.253 23.776 ;
     RECT  57.963 26.688 59.269 28.86 ;
     RECT  59.253 22.596 59.326 24.8 ;
     RECT  59.123 17.024 59.411 20.768 ;
     RECT  53.749 11.796 59.509 13.92 ;
     RECT  59.509 11.796 59.555 14.048 ;
     RECT  59.326 22.596 59.555 23.776 ;
     RECT  59.411 17.196 60.083 20.768 ;
     RECT  59.555 14.016 60.139 14.048 ;
     RECT  59.221 36.224 60.373 39.904 ;
     RECT  60.373 36.224 60.642 40.288 ;
     RECT  59.221 42.048 60.661 42.72 ;
     RECT  60.661 41.6 60.755 42.72 ;
     RECT  59.269 26.176 61.141 28.86 ;
     RECT  61.141 25.92 61.187 28.86 ;
     RECT  61.187 27.264 61.331 28.86 ;
     RECT  60.642 35.84 61.427 40.288 ;
     RECT  60.085 15.424 61.619 15.456 ;
     RECT  60.083 17.196 61.619 19.552 ;
     RECT  61.619 17.196 61.861 18.784 ;
     RECT  61.861 17.024 61.931 18.784 ;
     RECT  60.755 42.688 62.341 42.72 ;
     RECT  58.739 44.196 62.341 45.06 ;
     RECT  62.37 41.28 62.443 41.312 ;
     RECT  62.341 42.688 62.443 45.06 ;
     RECT  61.187 25.92 62.517 25.952 ;
     RECT  62.517 25.024 62.59 25.952 ;
     RECT  58.163 32.256 62.627 34.26 ;
     RECT  61.331 27.996 62.629 28.86 ;
     RECT  60.373 30.72 62.645 30.752 ;
     RECT  62.629 27.84 62.699 28.86 ;
     RECT  62.645 30.72 62.699 31.392 ;
     RECT  61.427 35.84 62.763 39.968 ;
     RECT  62.699 31.36 62.771 31.392 ;
     RECT  62.763 38.08 62.771 39.968 ;
     RECT  61.931 17.196 62.917 18.784 ;
     RECT  62.917 17.196 63.083 20 ;
     RECT  62.627 33.396 63.221 34.26 ;
     RECT  62.763 35.84 63.221 36.32 ;
     RECT  63.221 33.396 63.275 36.32 ;
     RECT  62.59 25.92 63.299 25.952 ;
     RECT  62.771 38.08 63.299 39.66 ;
     RECT  63.275 33.396 63.347 35.872 ;
     RECT  62.443 42.688 63.395 42.72 ;
     RECT  63.347 35.84 63.731 35.872 ;
     RECT  53.267 0.996 64.8 1.86 ;
     RECT  48.043 6.396 64.8 7.26 ;
     RECT  59.555 11.796 64.8 12.66 ;
     RECT  63.083 17.196 64.8 18.06 ;
     RECT  59.555 22.596 64.8 23.46 ;
     RECT  62.699 27.996 64.8 28.86 ;
     RECT  63.347 33.396 64.8 34.26 ;
     RECT  63.299 38.796 64.8 39.66 ;
     RECT  62.443 44.196 64.8 45.06 ;
     RECT  56.867 49.596 64.8 50.46 ;
     RECT  56.963 54.996 64.8 55.86 ;
     RECT  54.778 60.396 64.8 61.26 ;
    LAYER M7 ;
     RECT  49.456 0.531 49.744 0.821 ;
     RECT  11.656 0.531 11.944 1.973 ;
     RECT  48.448 0.821 49.744 2.347 ;
     RECT  44.056 0.531 44.344 2.869 ;
     RECT  38.656 0.531 38.944 3.061 ;
     RECT  22.456 0.531 22.744 3.253 ;
     RECT  17.056 0.531 17.344 3.317 ;
     RECT  20.032 1.397 20.512 3.499 ;
     RECT  27.856 0.531 28.144 3.509 ;
     RECT  17.056 3.317 17.888 4.213 ;
     RECT  38.656 3.061 39.392 4.533 ;
     RECT  10.496 1.973 11.944 4.853 ;
     RECT  6.256 0.531 6.544 5.109 ;
     RECT  17.056 4.213 18.208 5.621 ;
     RECT  20.48 3.499 20.512 5.621 ;
     RECT  27.856 3.509 29.216 5.739 ;
     RECT  35.328 3.445 35.36 5.739 ;
     RECT  44.056 2.869 44.448 5.813 ;
     RECT  6.256 5.109 6.688 6.315 ;
     RECT  22.336 3.253 22.744 6.315 ;
     RECT  38.528 4.533 39.392 6.315 ;
     RECT  31.936 0.053 31.968 7.349 ;
     RECT  33.256 0.531 33.544 7.349 ;
     RECT  25.728 2.037 25.76 7.669 ;
     RECT  10.368 4.853 11.944 7.925 ;
     RECT  27.856 5.739 29.024 7.925 ;
     RECT  38.528 6.315 38.944 7.925 ;
     RECT  8.128 6.773 8.16 8.043 ;
     RECT  45.888 5.045 45.92 8.501 ;
     RECT  45.888 8.501 46.176 8.555 ;
     RECT  6.256 6.315 6.544 9.013 ;
     RECT  5.12 9.013 6.544 9.077 ;
     RECT  25.728 7.669 26.272 9.515 ;
     RECT  31.936 7.349 33.544 9.643 ;
     RECT  24.064 9.333 24.096 10.037 ;
     RECT  25.728 9.515 25.76 10.037 ;
     RECT  43.136 5.813 44.448 10.101 ;
     RECT  46.144 8.555 46.176 10.101 ;
     RECT  49.456 2.347 49.744 10.357 ;
     RECT  54.856 0.531 55.144 10.357 ;
     RECT  27.856 7.925 29.664 10.539 ;
     RECT  53.76 10.357 55.144 10.549 ;
     RECT  15.68 8.821 15.712 10.603 ;
     RECT  10.368 7.925 12.064 10.731 ;
     RECT  43.136 10.101 46.176 10.731 ;
     RECT  24.064 10.037 25.76 10.859 ;
     RECT  3.84 9.077 6.544 10.923 ;
     RECT  33.256 9.643 33.544 10.933 ;
     RECT  36.8 4.405 36.832 10.987 ;
     RECT  17.056 5.621 20.512 11.307 ;
     RECT  24.064 10.859 24.992 11.307 ;
     RECT  48 5.045 48.032 11.509 ;
     RECT  49.344 10.357 49.744 11.509 ;
     RECT  10.368 10.731 11.944 11.637 ;
     RECT  8.64 10.549 8.672 11.691 ;
     RECT  13.248 10.741 13.28 12.203 ;
     RECT  24.064 11.307 24.096 12.203 ;
     RECT  17.056 11.307 18.272 12.213 ;
     RECT  22.456 6.315 22.744 12.213 ;
     RECT  27.856 10.539 28.512 12.213 ;
     RECT  27.712 12.213 28.512 12.267 ;
     RECT  43.136 10.731 45.152 12.779 ;
     RECT  38.208 7.925 38.944 12.843 ;
     RECT  43.136 12.779 44.344 12.843 ;
     RECT  33.256 10.933 34.208 13.099 ;
     RECT  10.24 11.637 11.944 13.291 ;
     RECT  41.344 11.317 41.376 13.621 ;
     RECT  3.84 10.923 3.872 13.739 ;
     RECT  52.992 10.549 55.144 13.931 ;
     RECT  60.256 0.531 60.544 14.005 ;
     RECT  10.368 13.291 11.944 14.059 ;
     RECT  19.648 11.307 20.512 14.325 ;
     RECT  22.336 12.213 22.744 14.325 ;
     RECT  16.256 12.213 18.272 14.379 ;
     RECT  0.856 0.531 1.144 14.773 ;
     RECT  19.648 14.325 22.744 14.773 ;
     RECT  16.704 14.379 18.272 14.837 ;
     RECT  19.648 14.773 22.88 14.837 ;
     RECT  46.08 13.045 46.112 14.891 ;
     RECT  43.904 12.843 44.344 14.901 ;
     RECT  16.704 14.837 22.88 15.093 ;
     RECT  54.856 13.931 55.144 15.349 ;
     RECT  48 11.509 49.744 15.467 ;
     RECT  60.096 14.005 60.544 15.467 ;
     RECT  0.448 14.773 1.144 16.043 ;
     RECT  35.584 12.725 35.616 16.043 ;
     RECT  40.32 13.621 41.376 16.043 ;
     RECT  11.328 14.059 11.944 16.235 ;
     RECT  54.856 15.349 56.096 16.299 ;
     RECT  11.656 16.235 11.944 16.501 ;
     RECT  16.704 15.093 23.072 16.619 ;
     RECT  43.328 14.901 44.344 16.693 ;
     RECT  43.328 16.693 44.448 16.747 ;
     RECT  25.6 13.045 25.632 17.013 ;
     RECT  60.256 15.467 60.544 17.013 ;
     RECT  48.512 15.467 49.744 17.589 ;
     RECT  54.856 16.299 55.144 17.589 ;
     RECT  19.264 16.619 23.072 17.707 ;
     RECT  27.712 12.267 28.144 17.707 ;
     RECT  27.856 17.707 28.144 18.165 ;
     RECT  48.448 17.589 49.744 18.219 ;
     RECT  59.328 17.013 60.544 18.219 ;
     RECT  9.728 17.589 9.76 18.283 ;
     RECT  24.512 17.013 25.632 18.357 ;
     RECT  24.512 18.357 26.144 18.411 ;
     RECT  11.656 16.501 13.088 18.539 ;
     RECT  16.704 16.619 17.344 18.613 ;
     RECT  8.384 14.069 8.416 18.741 ;
     RECT  41.344 16.043 41.376 18.741 ;
     RECT  61.888 17.013 61.92 18.741 ;
     RECT  61.888 18.741 63.072 18.795 ;
     RECT  36.288 18.485 36.32 18.859 ;
     RECT  60.096 18.219 60.544 18.923 ;
     RECT  16.704 18.613 17.888 19.243 ;
     RECT  27.856 18.165 28.256 19.253 ;
     RECT  48.576 18.219 49.744 19.435 ;
     RECT  54.656 17.589 55.144 19.435 ;
     RECT  54.856 19.435 55.144 19.509 ;
     RECT  56.96 19.317 56.992 19.509 ;
     RECT  7.936 18.741 8.416 19.691 ;
     RECT  8.384 19.691 8.416 19.701 ;
     RECT  8.384 19.701 8.544 19.755 ;
     RECT  19.456 17.707 23.072 19.755 ;
     RECT  25.6 18.411 26.144 19.755 ;
     RECT  27.648 19.253 28.256 19.893 ;
     RECT  29.568 18.229 29.6 19.893 ;
     RECT  63.04 18.795 63.072 20.011 ;
     RECT  43.904 16.747 44.448 20.523 ;
     RECT  26.112 19.755 26.144 20.587 ;
     RECT  27.648 19.893 29.6 20.587 ;
     RECT  40.448 18.741 41.376 20.587 ;
     RECT  48.704 19.435 49.744 20.725 ;
     RECT  11.656 18.539 11.944 20.789 ;
     RECT  38.656 12.843 38.944 20.789 ;
     RECT  40.448 20.587 41.184 20.789 ;
     RECT  8.512 19.755 8.544 20.843 ;
     RECT  38.656 20.789 41.184 21.099 ;
     RECT  54.856 19.509 56.992 21.163 ;
     RECT  17.056 19.243 17.888 21.749 ;
     RECT  19.456 19.755 20.512 21.749 ;
     RECT  52.992 13.931 53.024 21.931 ;
     RECT  47.552 20.725 49.744 21.995 ;
     RECT  54.856 21.163 56.224 22.123 ;
     RECT  22.336 19.755 23.072 22.197 ;
     RECT  38.656 21.099 41.056 22.315 ;
     RECT  48.96 21.995 49.744 22.315 ;
     RECT  26.496 21.621 26.528 22.325 ;
     RECT  27.856 20.587 29.6 22.325 ;
     RECT  44.056 20.523 44.448 22.389 ;
     RECT  0.856 16.043 1.144 22.453 ;
     RECT  26.496 22.325 29.6 22.453 ;
     RECT  45.888 21.173 45.92 22.507 ;
     RECT  35.904 21.941 35.936 23.019 ;
     RECT  38.656 22.315 40.16 23.019 ;
     RECT  17.056 21.749 20.512 23.595 ;
     RECT  31.936 9.643 31.968 23.605 ;
     RECT  26.176 22.453 29.6 23.979 ;
     RECT  42.88 22.389 44.448 24.043 ;
     RECT  20.48 23.595 20.512 24.181 ;
     RECT  22.336 22.197 23.776 24.181 ;
     RECT  47.552 21.995 47.584 24.309 ;
     RECT  49.456 22.315 49.744 24.309 ;
     RECT  0.704 22.453 1.144 24.363 ;
     RECT  26.368 23.979 29.6 24.363 ;
     RECT  53.248 23.541 53.28 24.619 ;
     RECT  60.256 18.923 60.544 24.757 ;
     RECT  31.68 23.605 31.968 24.949 ;
     RECT  17.056 23.595 18.528 25.013 ;
     RECT  47.552 24.309 49.744 25.077 ;
     RECT  3.392 20.789 3.424 25.131 ;
     RECT  26.368 24.363 28.448 25.131 ;
     RECT  47.552 25.077 50.08 25.195 ;
     RECT  38.656 23.019 38.944 25.589 ;
     RECT  27.856 25.131 28.448 25.899 ;
     RECT  62.528 25.013 62.56 25.963 ;
     RECT  14.848 23.925 14.88 26.027 ;
     RECT  17.056 25.013 18.976 26.101 ;
     RECT  20.48 24.181 23.776 26.101 ;
     RECT  30.144 24.949 31.968 26.603 ;
     RECT  26.368 25.131 26.528 26.677 ;
     RECT  47.552 25.195 47.904 26.677 ;
     RECT  59.264 24.757 60.544 26.731 ;
     RECT  0.856 24.363 1.144 26.741 ;
     RECT  26.112 26.677 26.528 26.741 ;
     RECT  27.856 25.899 28.144 26.741 ;
     RECT  30.144 26.603 30.176 26.859 ;
     RECT  36.416 24.437 36.448 26.859 ;
     RECT  49.456 25.195 50.08 26.933 ;
     RECT  59.776 26.731 60.544 27.307 ;
     RECT  17.056 26.101 23.776 27.435 ;
     RECT  31.68 26.603 31.968 27.435 ;
     RECT  0.704 26.741 1.144 27.883 ;
     RECT  17.056 27.435 22.744 27.883 ;
     RECT  47.552 26.677 47.968 27.883 ;
     RECT  49.456 26.933 50.784 28.459 ;
     RECT  0.856 27.883 1.144 28.981 ;
     RECT  26.112 26.741 28.144 29.035 ;
     RECT  17.056 27.883 18.848 29.227 ;
     RECT  57.92 27.189 57.952 29.227 ;
     RECT  54.856 22.123 56.16 29.419 ;
     RECT  20.48 27.883 22.744 29.611 ;
     RECT  38.464 25.589 38.944 29.867 ;
     RECT  4.864 27.829 4.896 29.995 ;
     RECT  17.056 29.227 17.568 30.133 ;
     RECT  14.528 27.829 14.56 30.251 ;
     RECT  44.056 24.043 44.448 30.251 ;
     RECT  49.456 28.459 49.744 30.453 ;
     RECT  49.344 30.453 49.744 30.709 ;
     RECT  11.656 20.789 12.256 30.827 ;
     RECT  49.344 30.709 50.336 30.965 ;
     RECT  27.712 29.035 28.144 31.221 ;
     RECT  0.856 28.981 2.272 31.403 ;
     RECT  25.024 29.045 25.056 31.403 ;
     RECT  27.712 31.221 29.024 31.403 ;
     RECT  52.16 30.069 52.192 31.403 ;
     RECT  62.656 27.829 62.688 31.403 ;
     RECT  38.656 29.867 38.944 31.669 ;
     RECT  44.056 30.251 44.344 31.669 ;
     RECT  38.656 31.669 39.072 31.861 ;
     RECT  47.552 27.883 47.584 31.925 ;
     RECT  16.512 30.133 17.568 31.979 ;
     RECT  41.92 28.405 41.952 31.979 ;
     RECT  49.024 30.965 50.336 31.979 ;
     RECT  49.024 31.979 49.744 32.107 ;
     RECT  60.256 27.307 60.544 32.245 ;
     RECT  47.296 31.925 47.584 32.309 ;
     RECT  47.296 32.309 47.648 32.363 ;
     RECT  35.52 32.309 35.552 32.757 ;
     RECT  36.992 30.965 37.024 32.757 ;
     RECT  44.056 31.669 45.216 32.757 ;
     RECT  43.904 32.757 45.216 32.949 ;
     RECT  31.936 27.435 31.968 33.013 ;
     RECT  33.256 13.099 33.544 33.013 ;
     RECT  35.52 32.757 37.024 33.013 ;
     RECT  31.232 33.013 37.024 33.269 ;
     RECT  38.528 31.861 39.072 33.269 ;
     RECT  31.232 33.269 39.072 33.323 ;
     RECT  27.856 31.403 29.024 33.781 ;
     RECT  60.256 32.245 60.704 33.835 ;
     RECT  47.616 32.363 47.648 33.845 ;
     RECT  49.456 32.107 49.744 33.845 ;
     RECT  37.632 33.323 39.072 34.485 ;
     RECT  42.304 32.949 45.216 34.741 ;
     RECT  27.712 33.781 29.024 34.859 ;
     RECT  57.152 32.245 57.184 34.869 ;
     RECT  18.944 32.821 18.976 34.987 ;
     RECT  31.232 33.323 36.192 34.987 ;
     RECT  4.032 33.269 4.064 35.115 ;
     RECT  31.232 34.987 33.544 35.125 ;
     RECT  24.64 33.269 24.672 35.253 ;
     RECT  37.632 34.485 39.904 35.371 ;
     RECT  57.152 34.869 57.312 35.499 ;
     RECT  0.856 31.403 1.144 35.509 ;
     RECT  54.856 29.419 55.144 35.509 ;
     RECT  27.712 34.859 28.512 35.755 ;
     RECT  37.632 35.371 39.648 35.765 ;
     RECT  60.256 33.835 60.544 35.829 ;
     RECT  63.232 34.997 63.264 35.829 ;
     RECT  31.104 35.125 33.544 35.947 ;
     RECT  54.856 35.509 55.264 35.957 ;
     RECT  35.456 34.987 36.192 36.011 ;
     RECT  22.336 29.611 22.744 36.021 ;
     RECT  46.72 33.845 47.648 36.085 ;
     RECT  49.456 33.845 50.272 36.085 ;
     RECT  20.48 29.611 20.512 36.149 ;
     RECT  22.336 36.021 22.88 36.203 ;
     RECT  46.72 36.085 50.272 36.267 ;
     RECT  62.528 35.829 63.264 36.331 ;
     RECT  11.656 30.827 11.944 36.405 ;
     RECT  32.192 35.947 33.544 36.469 ;
     RECT  35.456 36.011 35.808 36.469 ;
     RECT  24.64 35.253 25.12 36.523 ;
     RECT  42.112 34.741 45.216 36.523 ;
     RECT  37.568 35.765 39.648 37.035 ;
     RECT  62.528 36.331 62.752 37.035 ;
     RECT  29.824 35.957 30.176 37.099 ;
     RECT  47.296 36.267 50.272 37.099 ;
     RECT  42.112 36.523 42.464 37.163 ;
     RECT  51.84 35.253 51.872 37.163 ;
     RECT  54.856 35.957 55.392 37.163 ;
     RECT  38.144 37.035 39.648 37.237 ;
     RECT  38.144 37.237 40.288 37.557 ;
     RECT  30.144 37.099 30.176 37.877 ;
     RECT  30.144 37.877 30.496 37.931 ;
     RECT  32.192 36.469 35.808 37.931 ;
     RECT  30.464 37.931 30.496 38.005 ;
     RECT  32.192 37.931 34.848 38.005 ;
     RECT  53.184 36.405 53.216 38.133 ;
     RECT  22.456 36.203 22.88 38.187 ;
     RECT  57.28 35.499 57.312 38.251 ;
     RECT  27.712 35.755 28.256 38.453 ;
     RECT  25.088 36.523 25.12 38.517 ;
     RECT  42.432 37.163 42.464 38.581 ;
     RECT  43.904 36.523 45.216 38.581 ;
     RECT  42.432 38.581 45.216 38.635 ;
     RECT  17.056 31.979 17.568 38.645 ;
     RECT  60.256 35.829 60.704 38.645 ;
     RECT  62.656 37.035 62.752 38.645 ;
     RECT  30.464 38.005 34.848 39.211 ;
     RECT  6.256 10.923 6.544 39.221 ;
     RECT  49.456 37.099 49.744 39.221 ;
     RECT  54.856 37.163 55.144 39.733 ;
     RECT  52.608 38.133 53.216 39.787 ;
     RECT  24.64 38.517 25.12 39.797 ;
     RECT  30.464 39.211 34.592 39.851 ;
     RECT  4.16 35.829 4.192 39.861 ;
     RECT  0.856 35.509 2.4 39.915 ;
     RECT  52.608 39.787 52.64 39.915 ;
     RECT  54.856 39.733 55.904 39.925 ;
     RECT  27.712 38.453 28.768 39.979 ;
     RECT  60.256 38.645 62.752 39.979 ;
     RECT  14.08 36.981 14.112 40.437 ;
     RECT  16.576 38.645 17.568 40.501 ;
     RECT  22.456 38.187 22.744 41.013 ;
     RECT  49.456 39.221 51.232 41.013 ;
     RECT  16.576 40.501 18.4 41.259 ;
     RECT  62.4 39.979 62.752 41.323 ;
     RECT  38.144 37.557 40.736 41.451 ;
     RECT  5.568 39.221 6.544 41.643 ;
     RECT  38.464 41.451 40.736 41.643 ;
     RECT  60.256 39.979 60.704 41.643 ;
     RECT  16.64 41.259 18.4 41.707 ;
     RECT  47.296 37.099 47.84 42.091 ;
     RECT  49.456 41.013 51.36 42.283 ;
     RECT  9.472 41.845 9.504 42.421 ;
     RECT  11.656 36.405 12.448 42.421 ;
     RECT  9.472 42.421 12.448 42.475 ;
     RECT  3.712 39.861 4.192 42.677 ;
     RECT  62.72 41.323 62.752 42.731 ;
     RECT  19.84 36.149 20.512 42.795 ;
     RECT  30.464 39.851 31.264 42.795 ;
     RECT  47.488 42.091 47.84 42.795 ;
     RECT  22.016 41.013 22.744 42.805 ;
     RECT  16.64 41.707 17.568 42.997 ;
     RECT  19.84 42.795 20.384 42.997 ;
     RECT  38.528 41.643 40.736 43.061 ;
     RECT  24.64 39.797 25.888 43.125 ;
     RECT  24.64 43.125 26.4 43.307 ;
     RECT  30.464 42.795 31.2 43.307 ;
     RECT  43.584 38.635 45.216 43.307 ;
     RECT  16.64 42.997 20.384 43.829 ;
     RECT  27.856 39.979 28.768 43.829 ;
     RECT  49.456 42.283 51.04 44.021 ;
     RECT  27.856 43.829 29.024 44.075 ;
     RECT  21.76 42.805 22.744 44.597 ;
     RECT  24.768 43.307 26.4 44.597 ;
     RECT  47.488 42.795 47.648 44.597 ;
     RECT  54.856 39.925 55.968 44.597 ;
     RECT  7.936 43.253 7.968 44.651 ;
     RECT  38.528 43.061 40.8 44.651 ;
     RECT  62.4 43.253 62.432 44.651 ;
     RECT  54.656 44.597 55.968 45.173 ;
     RECT  49.456 44.021 51.36 45.227 ;
     RECT  3.712 42.677 4.32 45.301 ;
     RECT  54.656 45.173 56.352 45.493 ;
     RECT  30.656 43.307 31.2 45.557 ;
     RECT  3.456 45.301 4.32 45.675 ;
     RECT  9.472 42.475 11.944 45.675 ;
     RECT  16.512 43.829 20.384 45.675 ;
     RECT  19.712 45.675 20.384 46.069 ;
     RECT  21.76 44.597 26.4 46.069 ;
     RECT  38.528 44.651 40.288 46.069 ;
     RECT  33.256 39.851 34.592 46.133 ;
     RECT  14.08 40.437 15.136 46.187 ;
     RECT  14.208 46.187 15.136 46.443 ;
     RECT  42.176 45.941 42.208 46.773 ;
     RECT  43.776 43.307 45.216 46.773 ;
     RECT  42.176 46.773 45.216 46.827 ;
     RECT  19.712 46.069 26.4 47.275 ;
     RECT  6.256 41.643 6.544 47.285 ;
     RECT  25.536 47.275 26.4 47.339 ;
     RECT  47.488 44.597 47.968 47.339 ;
     RECT  47.936 47.339 47.968 47.605 ;
     RECT  49.456 45.227 49.744 47.605 ;
     RECT  16.512 45.675 17.696 47.669 ;
     RECT  42.176 46.827 44.96 47.787 ;
     RECT  47.936 47.605 49.744 47.851 ;
     RECT  14.208 46.443 14.24 47.915 ;
     RECT  16.512 47.669 18.016 47.915 ;
     RECT  19.712 47.275 23.904 48.171 ;
     RECT  42.432 47.787 44.96 48.171 ;
     RECT  33.256 46.133 35.616 48.619 ;
     RECT  3.456 45.675 3.488 48.875 ;
     RECT  33.256 48.619 34.592 48.949 ;
     RECT  37.504 46.069 40.288 48.949 ;
     RECT  10.56 45.675 11.944 49.013 ;
     RECT  5.248 47.285 6.544 49.397 ;
     RECT  17.056 47.915 18.016 49.461 ;
     RECT  37.184 48.949 40.288 49.461 ;
     RECT  43.776 48.171 44.96 49.515 ;
     RECT  42.432 48.171 42.464 49.973 ;
     RECT  43.776 49.515 44.344 49.973 ;
     RECT  10.56 49.013 13.088 50.027 ;
     RECT  33.152 48.949 34.592 50.027 ;
     RECT  16.128 49.461 18.016 50.037 ;
     RECT  48.576 47.851 49.744 50.037 ;
     RECT  47.936 50.037 49.744 50.091 ;
     RECT  37.184 49.461 40.48 50.549 ;
     RECT  20.864 48.171 23.904 50.613 ;
     RECT  25.536 47.339 26.08 50.613 ;
     RECT  20.864 50.613 26.08 50.677 ;
     RECT  47.936 50.091 47.968 50.677 ;
     RECT  8.832 47.285 8.864 50.795 ;
     RECT  11.656 50.027 13.088 50.795 ;
     RECT  20.544 50.677 26.08 50.859 ;
     RECT  42.432 49.973 44.344 50.869 ;
     RECT  45.632 50.741 45.664 50.869 ;
     RECT  42.432 50.869 45.664 50.923 ;
     RECT  47.68 50.677 47.968 50.923 ;
     RECT  21.888 50.859 26.08 50.997 ;
     RECT  5.12 49.397 6.544 51.051 ;
     RECT  16.128 50.037 18.208 51.115 ;
     RECT  36.928 50.549 40.48 51.371 ;
     RECT  47.68 50.923 47.904 51.371 ;
     RECT  53.824 45.493 56.352 51.509 ;
     RECT  36.928 51.371 40.288 51.627 ;
     RECT  20.544 50.859 20.576 51.829 ;
     RECT  37.312 51.627 40.288 51.883 ;
     RECT  16.128 51.115 17.344 51.947 ;
     RECT  19.392 51.829 20.576 51.947 ;
     RECT  21.888 50.997 26.272 52.085 ;
     RECT  27.856 44.075 28.256 52.085 ;
     RECT  44.056 50.923 45.664 52.213 ;
     RECT  43.904 52.213 45.664 52.267 ;
     RECT  21.888 52.085 28.256 52.277 ;
     RECT  42.432 50.923 42.464 52.405 ;
     RECT  53.824 51.509 56.608 52.971 ;
     RECT  29.888 45.557 31.2 52.981 ;
     RECT  47.872 51.371 47.904 53.173 ;
     RECT  49.456 50.091 49.744 53.173 ;
     RECT  16.32 51.947 17.344 53.227 ;
     RECT  37.504 51.883 40.288 53.227 ;
     RECT  43.904 52.267 44.448 53.291 ;
     RECT  37.568 53.227 40.288 53.483 ;
     RECT  19.392 51.947 19.424 53.611 ;
     RECT  21.696 52.277 28.256 53.611 ;
     RECT  42.112 52.405 42.464 53.749 ;
     RECT  25.344 53.611 28.256 53.803 ;
     RECT  47.872 53.173 49.744 53.813 ;
     RECT  21.696 53.611 23.968 54.389 ;
     RECT  54.08 52.971 56.608 54.517 ;
     RECT  37.568 53.483 39.968 54.709 ;
     RECT  53.504 54.517 56.608 54.763 ;
     RECT  37.504 54.709 39.968 54.837 ;
     RECT  20.672 54.389 23.968 54.891 ;
     RECT  37.184 54.837 39.968 55.403 ;
     RECT  20.672 54.891 23.264 55.979 ;
     RECT  47.424 53.813 49.744 56.117 ;
     RECT  26.752 53.803 28.256 56.949 ;
     RECT  47.296 56.117 49.744 57.067 ;
     RECT  29.888 52.981 31.712 57.515 ;
     RECT  41.664 53.749 42.464 57.643 ;
     RECT  47.296 57.067 47.84 57.643 ;
     RECT  53.504 54.763 56.288 57.643 ;
     RECT  54.144 57.643 56.288 57.771 ;
     RECT  29.888 57.515 31.2 58.101 ;
     RECT  33.152 50.027 34.272 58.549 ;
     RECT  35.648 54.773 35.68 58.549 ;
     RECT  37.184 55.403 39.84 58.603 ;
     RECT  37.568 58.603 39.84 58.677 ;
     RECT  21.888 55.979 23.264 58.923 ;
     RECT  21.888 58.923 23.136 59.253 ;
     RECT  54.144 57.771 55.144 59.307 ;
     RECT  26.752 56.949 28.512 59.765 ;
     RECT  29.824 58.101 31.2 59.765 ;
     RECT  47.552 57.643 47.84 59.947 ;
     RECT  33.152 58.549 35.68 60.011 ;
     RECT  33.256 60.011 35.68 60.277 ;
     RECT  37.568 58.677 40.288 60.277 ;
     RECT  21.696 59.253 23.136 60.843 ;
     RECT  26.752 59.765 31.2 60.843 ;
     RECT  33.256 60.277 40.288 60.843 ;
     RECT  52.032 54.837 52.064 60.843 ;
     RECT  37.76 60.843 40.288 60.853 ;
     RECT  41.92 57.643 42.464 60.853 ;
     RECT  37.76 60.853 42.464 60.907 ;
     RECT  45.952 56.565 45.984 60.907 ;
     RECT  26.752 60.843 28.144 61.419 ;
     RECT  33.256 60.843 36.448 61.419 ;
     RECT  54.72 59.307 55.144 61.419 ;
     RECT  35.008 61.419 36.448 61.675 ;
     RECT  37.76 60.907 42.336 61.803 ;
     RECT  22.016 60.843 23.136 61.867 ;
     RECT  22.016 61.867 22.744 62.187 ;
     RECT  25.344 53.803 25.376 62.187 ;
     RECT  41.6 61.803 42.336 62.187 ;
     RECT  37.76 61.803 39.968 62.251 ;
     RECT  37.76 62.251 39.648 62.507 ;
     RECT  29.824 60.843 31.2 62.763 ;
     RECT  35.2 61.675 35.68 62.763 ;
     RECT  37.76 62.507 38.944 62.763 ;
     RECT  41.6 62.187 41.632 62.763 ;
     RECT  43.904 53.291 44.344 62.763 ;
     RECT  47.552 59.947 47.584 62.763 ;
     RECT  35.648 62.763 35.68 63.019 ;
     RECT  31.168 62.763 31.2 63.339 ;
     RECT  0.856 39.915 1.144 64.269 ;
     RECT  6.256 51.051 6.544 64.269 ;
     RECT  11.656 50.795 11.944 64.269 ;
     RECT  17.056 53.227 17.344 64.269 ;
     RECT  22.456 62.187 22.744 64.269 ;
     RECT  27.856 61.419 28.144 64.269 ;
     RECT  33.256 61.419 33.544 64.269 ;
     RECT  38.656 62.763 38.944 64.269 ;
     RECT  44.056 62.763 44.344 64.269 ;
     RECT  49.456 57.067 49.744 64.269 ;
     RECT  54.856 61.419 55.144 64.269 ;
     RECT  60.256 41.643 60.544 64.269 ;
  END
END dsfd_dw_ep_s
END LIBRARY
